VERSION 5.8 ;
BUSBITCHARS "[]" ;
DIVIDERCHAR "/" ;
UNITS
    DATABASE MICRONS 1000 ;
END UNITS

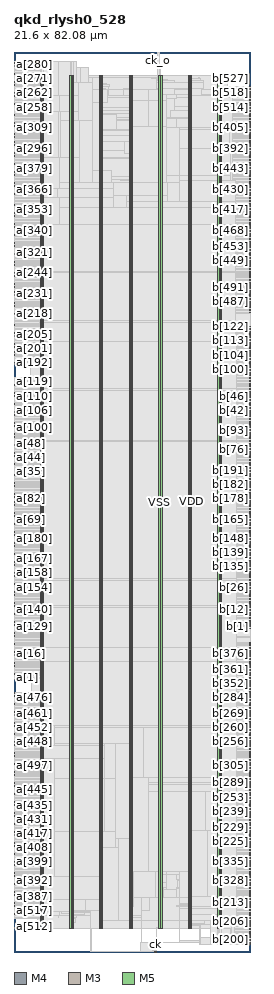
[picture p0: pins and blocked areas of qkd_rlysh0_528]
MACRO qkd_rlysh0_528
  FOREIGN qkd_rlysh0_528 0 0 ;
  CLASS BLOCK ;
  SIZE 21.6 BY 82.08 ;
  PIN a[0]
    DIRECTION INPUT ;
    USE SIGNAL ;
    PORT
      LAYER M4 ;
        RECT  0 24.912 0.084 24.936 ;
    END
  END a[0]
  PIN a[100]
    DIRECTION INPUT ;
    USE SIGNAL ;
    PORT
      LAYER M4 ;
        RECT  0 48.528 0.084 48.552 ;
    END
  END a[100]
  PIN a[101]
    DIRECTION INPUT ;
    USE SIGNAL ;
    PORT
      LAYER M4 ;
        RECT  0 48.672 0.084 48.696 ;
    END
  END a[101]
  PIN a[102]
    DIRECTION INPUT ;
    USE SIGNAL ;
    PORT
      LAYER M4 ;
        RECT  0 48.816 0.084 48.84 ;
    END
  END a[102]
  PIN a[103]
    DIRECTION INPUT ;
    USE SIGNAL ;
    PORT
      LAYER M4 ;
        RECT  0 48.96 0.084 48.984 ;
    END
  END a[103]
  PIN a[104]
    DIRECTION INPUT ;
    USE SIGNAL ;
    PORT
      LAYER M4 ;
        RECT  0 49.104 0.084 49.128 ;
    END
  END a[104]
  PIN a[105]
    DIRECTION INPUT ;
    USE SIGNAL ;
    PORT
      LAYER M4 ;
        RECT  0 49.248 0.084 49.272 ;
    END
  END a[105]
  PIN a[106]
    DIRECTION INPUT ;
    USE SIGNAL ;
    PORT
      LAYER M4 ;
        RECT  0 49.392 0.084 49.416 ;
    END
  END a[106]
  PIN a[107]
    DIRECTION INPUT ;
    USE SIGNAL ;
    PORT
      LAYER M4 ;
        RECT  0 49.536 0.084 49.56 ;
    END
  END a[107]
  PIN a[108]
    DIRECTION INPUT ;
    USE SIGNAL ;
    PORT
      LAYER M4 ;
        RECT  0 49.68 0.084 49.704 ;
    END
  END a[108]
  PIN a[109]
    DIRECTION INPUT ;
    USE SIGNAL ;
    PORT
      LAYER M4 ;
        RECT  0 49.824 0.084 49.848 ;
    END
  END a[109]
  PIN a[10]
    DIRECTION INPUT ;
    USE SIGNAL ;
    PORT
      LAYER M4 ;
        RECT  0 26.352 0.084 26.376 ;
    END
  END a[10]
  PIN a[110]
    DIRECTION INPUT ;
    USE SIGNAL ;
    PORT
      LAYER M4 ;
        RECT  0 49.968 0.084 49.992 ;
    END
  END a[110]
  PIN a[111]
    DIRECTION INPUT ;
    USE SIGNAL ;
    PORT
      LAYER M4 ;
        RECT  0 50.112 0.084 50.136 ;
    END
  END a[111]
  PIN a[112]
    DIRECTION INPUT ;
    USE SIGNAL ;
    PORT
      LAYER M4 ;
        RECT  0 50.256 0.084 50.28 ;
    END
  END a[112]
  PIN a[113]
    DIRECTION INPUT ;
    USE SIGNAL ;
    PORT
      LAYER M4 ;
        RECT  0 50.4 0.084 50.424 ;
    END
  END a[113]
  PIN a[114]
    DIRECTION INPUT ;
    USE SIGNAL ;
    PORT
      LAYER M4 ;
        RECT  0 50.544 0.084 50.568 ;
    END
  END a[114]
  PIN a[115]
    DIRECTION INPUT ;
    USE SIGNAL ;
    PORT
      LAYER M4 ;
        RECT  0 50.688 0.084 50.712 ;
    END
  END a[115]
  PIN a[116]
    DIRECTION INPUT ;
    USE SIGNAL ;
    PORT
      LAYER M4 ;
        RECT  0 50.832 0.084 50.856 ;
    END
  END a[116]
  PIN a[117]
    DIRECTION INPUT ;
    USE SIGNAL ;
    PORT
      LAYER M4 ;
        RECT  0 50.976 0.084 51 ;
    END
  END a[117]
  PIN a[118]
    DIRECTION INPUT ;
    USE SIGNAL ;
    PORT
      LAYER M4 ;
        RECT  0 51.12 0.084 51.144 ;
    END
  END a[118]
  PIN a[119]
    DIRECTION INPUT ;
    USE SIGNAL ;
    PORT
      LAYER M4 ;
        RECT  0 51.264 0.084 51.288 ;
    END
  END a[119]
  PIN a[11]
    DIRECTION INPUT ;
    USE SIGNAL ;
    PORT
      LAYER M4 ;
        RECT  0 26.496 0.084 26.52 ;
    END
  END a[11]
  PIN a[120]
    DIRECTION INPUT ;
    USE SIGNAL ;
    PORT
      LAYER M4 ;
        RECT  0 51.408 0.084 51.432 ;
    END
  END a[120]
  PIN a[121]
    DIRECTION INPUT ;
    USE SIGNAL ;
    PORT
      LAYER M4 ;
        RECT  0 51.552 0.084 51.576 ;
    END
  END a[121]
  PIN a[122]
    DIRECTION INPUT ;
    USE SIGNAL ;
    PORT
      LAYER M4 ;
        RECT  0 51.696 0.084 51.72 ;
    END
  END a[122]
  PIN a[123]
    DIRECTION INPUT ;
    USE SIGNAL ;
    PORT
      LAYER M4 ;
        RECT  0 51.84 0.084 51.864 ;
    END
  END a[123]
  PIN a[124]
    DIRECTION INPUT ;
    USE SIGNAL ;
    PORT
      LAYER M4 ;
        RECT  0 51.984 0.084 52.008 ;
    END
  END a[124]
  PIN a[125]
    DIRECTION INPUT ;
    USE SIGNAL ;
    PORT
      LAYER M4 ;
        RECT  0 52.128 0.084 52.152 ;
    END
  END a[125]
  PIN a[126]
    DIRECTION INPUT ;
    USE SIGNAL ;
    PORT
      LAYER M4 ;
        RECT  0 52.272 0.084 52.296 ;
    END
  END a[126]
  PIN a[127]
    DIRECTION INPUT ;
    USE SIGNAL ;
    PORT
      LAYER M4 ;
        RECT  0 52.416 0.084 52.44 ;
    END
  END a[127]
  PIN a[128]
    DIRECTION INPUT ;
    USE SIGNAL ;
    PORT
      LAYER M4 ;
        RECT  0 29.52 0.084 29.544 ;
    END
  END a[128]
  PIN a[129]
    DIRECTION INPUT ;
    USE SIGNAL ;
    PORT
      LAYER M4 ;
        RECT  0 29.664 0.084 29.688 ;
    END
  END a[129]
  PIN a[12]
    DIRECTION INPUT ;
    USE SIGNAL ;
    PORT
      LAYER M4 ;
        RECT  0 26.64 0.084 26.664 ;
    END
  END a[12]
  PIN a[130]
    DIRECTION INPUT ;
    USE SIGNAL ;
    PORT
      LAYER M4 ;
        RECT  0 29.808 0.084 29.832 ;
    END
  END a[130]
  PIN a[131]
    DIRECTION INPUT ;
    USE SIGNAL ;
    PORT
      LAYER M4 ;
        RECT  0 29.952 0.084 29.976 ;
    END
  END a[131]
  PIN a[132]
    DIRECTION INPUT ;
    USE SIGNAL ;
    PORT
      LAYER M4 ;
        RECT  0 30.096 0.084 30.12 ;
    END
  END a[132]
  PIN a[133]
    DIRECTION INPUT ;
    USE SIGNAL ;
    PORT
      LAYER M4 ;
        RECT  0 30.24 0.084 30.264 ;
    END
  END a[133]
  PIN a[134]
    DIRECTION INPUT ;
    USE SIGNAL ;
    PORT
      LAYER M4 ;
        RECT  0 30.384 0.084 30.408 ;
    END
  END a[134]
  PIN a[135]
    DIRECTION INPUT ;
    USE SIGNAL ;
    PORT
      LAYER M4 ;
        RECT  0 30.528 0.084 30.552 ;
    END
  END a[135]
  PIN a[136]
    DIRECTION INPUT ;
    USE SIGNAL ;
    PORT
      LAYER M4 ;
        RECT  0 30.672 0.084 30.696 ;
    END
  END a[136]
  PIN a[137]
    DIRECTION INPUT ;
    USE SIGNAL ;
    PORT
      LAYER M4 ;
        RECT  0 30.816 0.084 30.84 ;
    END
  END a[137]
  PIN a[138]
    DIRECTION INPUT ;
    USE SIGNAL ;
    PORT
      LAYER M4 ;
        RECT  0 30.96 0.084 30.984 ;
    END
  END a[138]
  PIN a[139]
    DIRECTION INPUT ;
    USE SIGNAL ;
    PORT
      LAYER M4 ;
        RECT  0 31.104 0.084 31.128 ;
    END
  END a[139]
  PIN a[13]
    DIRECTION INPUT ;
    USE SIGNAL ;
    PORT
      LAYER M4 ;
        RECT  0 26.784 0.084 26.808 ;
    END
  END a[13]
  PIN a[140]
    DIRECTION INPUT ;
    USE SIGNAL ;
    PORT
      LAYER M4 ;
        RECT  0 31.248 0.084 31.272 ;
    END
  END a[140]
  PIN a[141]
    DIRECTION INPUT ;
    USE SIGNAL ;
    PORT
      LAYER M4 ;
        RECT  0 31.392 0.084 31.416 ;
    END
  END a[141]
  PIN a[142]
    DIRECTION INPUT ;
    USE SIGNAL ;
    PORT
      LAYER M4 ;
        RECT  0 31.536 0.084 31.56 ;
    END
  END a[142]
  PIN a[143]
    DIRECTION INPUT ;
    USE SIGNAL ;
    PORT
      LAYER M4 ;
        RECT  0 31.68 0.084 31.704 ;
    END
  END a[143]
  PIN a[144]
    DIRECTION INPUT ;
    USE SIGNAL ;
    PORT
      LAYER M4 ;
        RECT  0 31.824 0.084 31.848 ;
    END
  END a[144]
  PIN a[145]
    DIRECTION INPUT ;
    USE SIGNAL ;
    PORT
      LAYER M4 ;
        RECT  0 31.968 0.084 31.992 ;
    END
  END a[145]
  PIN a[146]
    DIRECTION INPUT ;
    USE SIGNAL ;
    PORT
      LAYER M4 ;
        RECT  0 32.112 0.084 32.136 ;
    END
  END a[146]
  PIN a[147]
    DIRECTION INPUT ;
    USE SIGNAL ;
    PORT
      LAYER M4 ;
        RECT  0 32.256 0.084 32.28 ;
    END
  END a[147]
  PIN a[148]
    DIRECTION INPUT ;
    USE SIGNAL ;
    PORT
      LAYER M4 ;
        RECT  0 32.4 0.084 32.424 ;
    END
  END a[148]
  PIN a[149]
    DIRECTION INPUT ;
    USE SIGNAL ;
    PORT
      LAYER M4 ;
        RECT  0 32.544 0.084 32.568 ;
    END
  END a[149]
  PIN a[14]
    DIRECTION INPUT ;
    USE SIGNAL ;
    PORT
      LAYER M4 ;
        RECT  0 26.928 0.084 26.952 ;
    END
  END a[14]
  PIN a[150]
    DIRECTION INPUT ;
    USE SIGNAL ;
    PORT
      LAYER M4 ;
        RECT  0 32.688 0.084 32.712 ;
    END
  END a[150]
  PIN a[151]
    DIRECTION INPUT ;
    USE SIGNAL ;
    PORT
      LAYER M4 ;
        RECT  0 32.832 0.084 32.856 ;
    END
  END a[151]
  PIN a[152]
    DIRECTION INPUT ;
    USE SIGNAL ;
    PORT
      LAYER M4 ;
        RECT  0 32.976 0.084 33 ;
    END
  END a[152]
  PIN a[153]
    DIRECTION INPUT ;
    USE SIGNAL ;
    PORT
      LAYER M4 ;
        RECT  0 33.12 0.084 33.144 ;
    END
  END a[153]
  PIN a[154]
    DIRECTION INPUT ;
    USE SIGNAL ;
    PORT
      LAYER M4 ;
        RECT  0 33.264 0.084 33.288 ;
    END
  END a[154]
  PIN a[155]
    DIRECTION INPUT ;
    USE SIGNAL ;
    PORT
      LAYER M4 ;
        RECT  0 33.408 0.084 33.432 ;
    END
  END a[155]
  PIN a[156]
    DIRECTION INPUT ;
    USE SIGNAL ;
    PORT
      LAYER M4 ;
        RECT  0 33.552 0.084 33.576 ;
    END
  END a[156]
  PIN a[157]
    DIRECTION INPUT ;
    USE SIGNAL ;
    PORT
      LAYER M4 ;
        RECT  0 33.696 0.084 33.72 ;
    END
  END a[157]
  PIN a[158]
    DIRECTION INPUT ;
    USE SIGNAL ;
    PORT
      LAYER M4 ;
        RECT  0 33.84 0.084 33.864 ;
    END
  END a[158]
  PIN a[159]
    DIRECTION INPUT ;
    USE SIGNAL ;
    PORT
      LAYER M4 ;
        RECT  0 33.984 0.084 34.008 ;
    END
  END a[159]
  PIN a[15]
    DIRECTION INPUT ;
    USE SIGNAL ;
    PORT
      LAYER M4 ;
        RECT  0 27.072 0.084 27.096 ;
    END
  END a[15]
  PIN a[160]
    DIRECTION INPUT ;
    USE SIGNAL ;
    PORT
      LAYER M4 ;
        RECT  0 34.128 0.084 34.152 ;
    END
  END a[160]
  PIN a[161]
    DIRECTION INPUT ;
    USE SIGNAL ;
    PORT
      LAYER M4 ;
        RECT  0 34.272 0.084 34.296 ;
    END
  END a[161]
  PIN a[162]
    DIRECTION INPUT ;
    USE SIGNAL ;
    PORT
      LAYER M4 ;
        RECT  0 34.416 0.084 34.44 ;
    END
  END a[162]
  PIN a[163]
    DIRECTION INPUT ;
    USE SIGNAL ;
    PORT
      LAYER M4 ;
        RECT  0 34.56 0.084 34.584 ;
    END
  END a[163]
  PIN a[164]
    DIRECTION INPUT ;
    USE SIGNAL ;
    PORT
      LAYER M4 ;
        RECT  0 34.704 0.084 34.728 ;
    END
  END a[164]
  PIN a[165]
    DIRECTION INPUT ;
    USE SIGNAL ;
    PORT
      LAYER M4 ;
        RECT  0 34.848 0.084 34.872 ;
    END
  END a[165]
  PIN a[166]
    DIRECTION INPUT ;
    USE SIGNAL ;
    PORT
      LAYER M4 ;
        RECT  0 34.992 0.084 35.016 ;
    END
  END a[166]
  PIN a[167]
    DIRECTION INPUT ;
    USE SIGNAL ;
    PORT
      LAYER M4 ;
        RECT  0 35.136 0.084 35.16 ;
    END
  END a[167]
  PIN a[168]
    DIRECTION INPUT ;
    USE SIGNAL ;
    PORT
      LAYER M4 ;
        RECT  0 35.28 0.084 35.304 ;
    END
  END a[168]
  PIN a[169]
    DIRECTION INPUT ;
    USE SIGNAL ;
    PORT
      LAYER M4 ;
        RECT  0 35.424 0.084 35.448 ;
    END
  END a[169]
  PIN a[16]
    DIRECTION INPUT ;
    USE SIGNAL ;
    PORT
      LAYER M4 ;
        RECT  0 27.216 0.084 27.24 ;
    END
  END a[16]
  PIN a[170]
    DIRECTION INPUT ;
    USE SIGNAL ;
    PORT
      LAYER M4 ;
        RECT  0 35.568 0.084 35.592 ;
    END
  END a[170]
  PIN a[171]
    DIRECTION INPUT ;
    USE SIGNAL ;
    PORT
      LAYER M4 ;
        RECT  0 35.712 0.084 35.736 ;
    END
  END a[171]
  PIN a[172]
    DIRECTION INPUT ;
    USE SIGNAL ;
    PORT
      LAYER M4 ;
        RECT  0 35.856 0.084 35.88 ;
    END
  END a[172]
  PIN a[173]
    DIRECTION INPUT ;
    USE SIGNAL ;
    PORT
      LAYER M4 ;
        RECT  0 36 0.084 36.024 ;
    END
  END a[173]
  PIN a[174]
    DIRECTION INPUT ;
    USE SIGNAL ;
    PORT
      LAYER M4 ;
        RECT  0 36.144 0.084 36.168 ;
    END
  END a[174]
  PIN a[175]
    DIRECTION INPUT ;
    USE SIGNAL ;
    PORT
      LAYER M4 ;
        RECT  0 36.288 0.084 36.312 ;
    END
  END a[175]
  PIN a[176]
    DIRECTION INPUT ;
    USE SIGNAL ;
    PORT
      LAYER M4 ;
        RECT  0 36.432 0.084 36.456 ;
    END
  END a[176]
  PIN a[177]
    DIRECTION INPUT ;
    USE SIGNAL ;
    PORT
      LAYER M4 ;
        RECT  0 36.576 0.084 36.6 ;
    END
  END a[177]
  PIN a[178]
    DIRECTION INPUT ;
    USE SIGNAL ;
    PORT
      LAYER M4 ;
        RECT  0 36.72 0.084 36.744 ;
    END
  END a[178]
  PIN a[179]
    DIRECTION INPUT ;
    USE SIGNAL ;
    PORT
      LAYER M4 ;
        RECT  0 36.864 0.084 36.888 ;
    END
  END a[179]
  PIN a[17]
    DIRECTION INPUT ;
    USE SIGNAL ;
    PORT
      LAYER M4 ;
        RECT  0 27.36 0.084 27.384 ;
    END
  END a[17]
  PIN a[180]
    DIRECTION INPUT ;
    USE SIGNAL ;
    PORT
      LAYER M4 ;
        RECT  0 37.008 0.084 37.032 ;
    END
  END a[180]
  PIN a[181]
    DIRECTION INPUT ;
    USE SIGNAL ;
    PORT
      LAYER M4 ;
        RECT  0 37.152 0.084 37.176 ;
    END
  END a[181]
  PIN a[182]
    DIRECTION INPUT ;
    USE SIGNAL ;
    PORT
      LAYER M4 ;
        RECT  0 37.296 0.084 37.32 ;
    END
  END a[182]
  PIN a[183]
    DIRECTION INPUT ;
    USE SIGNAL ;
    PORT
      LAYER M4 ;
        RECT  0 37.44 0.084 37.464 ;
    END
  END a[183]
  PIN a[184]
    DIRECTION INPUT ;
    USE SIGNAL ;
    PORT
      LAYER M4 ;
        RECT  0 37.584 0.084 37.608 ;
    END
  END a[184]
  PIN a[185]
    DIRECTION INPUT ;
    USE SIGNAL ;
    PORT
      LAYER M4 ;
        RECT  0 37.728 0.084 37.752 ;
    END
  END a[185]
  PIN a[186]
    DIRECTION INPUT ;
    USE SIGNAL ;
    PORT
      LAYER M4 ;
        RECT  0 37.872 0.084 37.896 ;
    END
  END a[186]
  PIN a[187]
    DIRECTION INPUT ;
    USE SIGNAL ;
    PORT
      LAYER M4 ;
        RECT  0 38.016 0.084 38.04 ;
    END
  END a[187]
  PIN a[188]
    DIRECTION INPUT ;
    USE SIGNAL ;
    PORT
      LAYER M4 ;
        RECT  0 38.16 0.084 38.184 ;
    END
  END a[188]
  PIN a[189]
    DIRECTION INPUT ;
    USE SIGNAL ;
    PORT
      LAYER M4 ;
        RECT  0 38.304 0.084 38.328 ;
    END
  END a[189]
  PIN a[18]
    DIRECTION INPUT ;
    USE SIGNAL ;
    PORT
      LAYER M4 ;
        RECT  0 27.504 0.084 27.528 ;
    END
  END a[18]
  PIN a[190]
    DIRECTION INPUT ;
    USE SIGNAL ;
    PORT
      LAYER M4 ;
        RECT  0 38.448 0.084 38.472 ;
    END
  END a[190]
  PIN a[191]
    DIRECTION INPUT ;
    USE SIGNAL ;
    PORT
      LAYER M4 ;
        RECT  0 38.592 0.084 38.616 ;
    END
  END a[191]
  PIN a[192]
    DIRECTION INPUT ;
    USE SIGNAL ;
    PORT
      LAYER M4 ;
        RECT  0 53.712 0.084 53.736 ;
    END
  END a[192]
  PIN a[193]
    DIRECTION INPUT ;
    USE SIGNAL ;
    PORT
      LAYER M4 ;
        RECT  0 53.856 0.084 53.88 ;
    END
  END a[193]
  PIN a[194]
    DIRECTION INPUT ;
    USE SIGNAL ;
    PORT
      LAYER M4 ;
        RECT  0 54 0.084 54.024 ;
    END
  END a[194]
  PIN a[195]
    DIRECTION INPUT ;
    USE SIGNAL ;
    PORT
      LAYER M4 ;
        RECT  0 54.144 0.084 54.168 ;
    END
  END a[195]
  PIN a[196]
    DIRECTION INPUT ;
    USE SIGNAL ;
    PORT
      LAYER M4 ;
        RECT  0 54.288 0.084 54.312 ;
    END
  END a[196]
  PIN a[197]
    DIRECTION INPUT ;
    USE SIGNAL ;
    PORT
      LAYER M4 ;
        RECT  0 54.432 0.084 54.456 ;
    END
  END a[197]
  PIN a[198]
    DIRECTION INPUT ;
    USE SIGNAL ;
    PORT
      LAYER M4 ;
        RECT  0 54.576 0.084 54.6 ;
    END
  END a[198]
  PIN a[199]
    DIRECTION INPUT ;
    USE SIGNAL ;
    PORT
      LAYER M4 ;
        RECT  0 54.72 0.084 54.744 ;
    END
  END a[199]
  PIN a[19]
    DIRECTION INPUT ;
    USE SIGNAL ;
    PORT
      LAYER M4 ;
        RECT  0 27.648 0.084 27.672 ;
    END
  END a[19]
  PIN a[1]
    DIRECTION INPUT ;
    USE SIGNAL ;
    PORT
      LAYER M4 ;
        RECT  0 25.056 0.084 25.08 ;
    END
  END a[1]
  PIN a[200]
    DIRECTION INPUT ;
    USE SIGNAL ;
    PORT
      LAYER M4 ;
        RECT  0 54.864 0.084 54.888 ;
    END
  END a[200]
  PIN a[201]
    DIRECTION INPUT ;
    USE SIGNAL ;
    PORT
      LAYER M4 ;
        RECT  0 55.008 0.084 55.032 ;
    END
  END a[201]
  PIN a[202]
    DIRECTION INPUT ;
    USE SIGNAL ;
    PORT
      LAYER M4 ;
        RECT  0 55.152 0.084 55.176 ;
    END
  END a[202]
  PIN a[203]
    DIRECTION INPUT ;
    USE SIGNAL ;
    PORT
      LAYER M4 ;
        RECT  0 55.296 0.084 55.32 ;
    END
  END a[203]
  PIN a[204]
    DIRECTION INPUT ;
    USE SIGNAL ;
    PORT
      LAYER M4 ;
        RECT  0 55.44 0.084 55.464 ;
    END
  END a[204]
  PIN a[205]
    DIRECTION INPUT ;
    USE SIGNAL ;
    PORT
      LAYER M4 ;
        RECT  0 55.584 0.084 55.608 ;
    END
  END a[205]
  PIN a[206]
    DIRECTION INPUT ;
    USE SIGNAL ;
    PORT
      LAYER M4 ;
        RECT  0 55.728 0.084 55.752 ;
    END
  END a[206]
  PIN a[207]
    DIRECTION INPUT ;
    USE SIGNAL ;
    PORT
      LAYER M4 ;
        RECT  0 55.872 0.084 55.896 ;
    END
  END a[207]
  PIN a[208]
    DIRECTION INPUT ;
    USE SIGNAL ;
    PORT
      LAYER M4 ;
        RECT  0 56.016 0.084 56.04 ;
    END
  END a[208]
  PIN a[209]
    DIRECTION INPUT ;
    USE SIGNAL ;
    PORT
      LAYER M4 ;
        RECT  0 56.16 0.084 56.184 ;
    END
  END a[209]
  PIN a[20]
    DIRECTION INPUT ;
    USE SIGNAL ;
    PORT
      LAYER M4 ;
        RECT  0 27.792 0.084 27.816 ;
    END
  END a[20]
  PIN a[210]
    DIRECTION INPUT ;
    USE SIGNAL ;
    PORT
      LAYER M4 ;
        RECT  0 56.304 0.084 56.328 ;
    END
  END a[210]
  PIN a[211]
    DIRECTION INPUT ;
    USE SIGNAL ;
    PORT
      LAYER M4 ;
        RECT  0 56.448 0.084 56.472 ;
    END
  END a[211]
  PIN a[212]
    DIRECTION INPUT ;
    USE SIGNAL ;
    PORT
      LAYER M4 ;
        RECT  0 56.592 0.084 56.616 ;
    END
  END a[212]
  PIN a[213]
    DIRECTION INPUT ;
    USE SIGNAL ;
    PORT
      LAYER M4 ;
        RECT  0 56.736 0.084 56.76 ;
    END
  END a[213]
  PIN a[214]
    DIRECTION INPUT ;
    USE SIGNAL ;
    PORT
      LAYER M4 ;
        RECT  0 56.88 0.084 56.904 ;
    END
  END a[214]
  PIN a[215]
    DIRECTION INPUT ;
    USE SIGNAL ;
    PORT
      LAYER M4 ;
        RECT  0 57.024 0.084 57.048 ;
    END
  END a[215]
  PIN a[216]
    DIRECTION INPUT ;
    USE SIGNAL ;
    PORT
      LAYER M4 ;
        RECT  0 57.168 0.084 57.192 ;
    END
  END a[216]
  PIN a[217]
    DIRECTION INPUT ;
    USE SIGNAL ;
    PORT
      LAYER M4 ;
        RECT  0 57.312 0.084 57.336 ;
    END
  END a[217]
  PIN a[218]
    DIRECTION INPUT ;
    USE SIGNAL ;
    PORT
      LAYER M4 ;
        RECT  0 57.456 0.084 57.48 ;
    END
  END a[218]
  PIN a[219]
    DIRECTION INPUT ;
    USE SIGNAL ;
    PORT
      LAYER M4 ;
        RECT  0 57.6 0.084 57.624 ;
    END
  END a[219]
  PIN a[21]
    DIRECTION INPUT ;
    USE SIGNAL ;
    PORT
      LAYER M4 ;
        RECT  0 27.936 0.084 27.96 ;
    END
  END a[21]
  PIN a[220]
    DIRECTION INPUT ;
    USE SIGNAL ;
    PORT
      LAYER M4 ;
        RECT  0 57.744 0.084 57.768 ;
    END
  END a[220]
  PIN a[221]
    DIRECTION INPUT ;
    USE SIGNAL ;
    PORT
      LAYER M4 ;
        RECT  0 57.888 0.084 57.912 ;
    END
  END a[221]
  PIN a[222]
    DIRECTION INPUT ;
    USE SIGNAL ;
    PORT
      LAYER M4 ;
        RECT  0 58.032 0.084 58.056 ;
    END
  END a[222]
  PIN a[223]
    DIRECTION INPUT ;
    USE SIGNAL ;
    PORT
      LAYER M4 ;
        RECT  0 58.176 0.084 58.2 ;
    END
  END a[223]
  PIN a[224]
    DIRECTION INPUT ;
    USE SIGNAL ;
    PORT
      LAYER M4 ;
        RECT  0 58.32 0.084 58.344 ;
    END
  END a[224]
  PIN a[225]
    DIRECTION INPUT ;
    USE SIGNAL ;
    PORT
      LAYER M4 ;
        RECT  0 58.464 0.084 58.488 ;
    END
  END a[225]
  PIN a[226]
    DIRECTION INPUT ;
    USE SIGNAL ;
    PORT
      LAYER M4 ;
        RECT  0 58.608 0.084 58.632 ;
    END
  END a[226]
  PIN a[227]
    DIRECTION INPUT ;
    USE SIGNAL ;
    PORT
      LAYER M4 ;
        RECT  0 58.752 0.084 58.776 ;
    END
  END a[227]
  PIN a[228]
    DIRECTION INPUT ;
    USE SIGNAL ;
    PORT
      LAYER M4 ;
        RECT  0 58.896 0.084 58.92 ;
    END
  END a[228]
  PIN a[229]
    DIRECTION INPUT ;
    USE SIGNAL ;
    PORT
      LAYER M4 ;
        RECT  0 59.04 0.084 59.064 ;
    END
  END a[229]
  PIN a[22]
    DIRECTION INPUT ;
    USE SIGNAL ;
    PORT
      LAYER M4 ;
        RECT  0 28.08 0.084 28.104 ;
    END
  END a[22]
  PIN a[230]
    DIRECTION INPUT ;
    USE SIGNAL ;
    PORT
      LAYER M4 ;
        RECT  0 59.184 0.084 59.208 ;
    END
  END a[230]
  PIN a[231]
    DIRECTION INPUT ;
    USE SIGNAL ;
    PORT
      LAYER M4 ;
        RECT  0 59.328 0.084 59.352 ;
    END
  END a[231]
  PIN a[232]
    DIRECTION INPUT ;
    USE SIGNAL ;
    PORT
      LAYER M4 ;
        RECT  0 59.472 0.084 59.496 ;
    END
  END a[232]
  PIN a[233]
    DIRECTION INPUT ;
    USE SIGNAL ;
    PORT
      LAYER M4 ;
        RECT  0 59.616 0.084 59.64 ;
    END
  END a[233]
  PIN a[234]
    DIRECTION INPUT ;
    USE SIGNAL ;
    PORT
      LAYER M4 ;
        RECT  0 59.76 0.084 59.784 ;
    END
  END a[234]
  PIN a[235]
    DIRECTION INPUT ;
    USE SIGNAL ;
    PORT
      LAYER M4 ;
        RECT  0 59.904 0.084 59.928 ;
    END
  END a[235]
  PIN a[236]
    DIRECTION INPUT ;
    USE SIGNAL ;
    PORT
      LAYER M4 ;
        RECT  0 60.048 0.084 60.072 ;
    END
  END a[236]
  PIN a[237]
    DIRECTION INPUT ;
    USE SIGNAL ;
    PORT
      LAYER M4 ;
        RECT  0 60.192 0.084 60.216 ;
    END
  END a[237]
  PIN a[238]
    DIRECTION INPUT ;
    USE SIGNAL ;
    PORT
      LAYER M4 ;
        RECT  0 60.336 0.084 60.36 ;
    END
  END a[238]
  PIN a[239]
    DIRECTION INPUT ;
    USE SIGNAL ;
    PORT
      LAYER M4 ;
        RECT  0 60.48 0.084 60.504 ;
    END
  END a[239]
  PIN a[23]
    DIRECTION INPUT ;
    USE SIGNAL ;
    PORT
      LAYER M4 ;
        RECT  0 28.224 0.084 28.248 ;
    END
  END a[23]
  PIN a[240]
    DIRECTION INPUT ;
    USE SIGNAL ;
    PORT
      LAYER M4 ;
        RECT  0 60.624 0.084 60.648 ;
    END
  END a[240]
  PIN a[241]
    DIRECTION INPUT ;
    USE SIGNAL ;
    PORT
      LAYER M4 ;
        RECT  0 60.768 0.084 60.792 ;
    END
  END a[241]
  PIN a[242]
    DIRECTION INPUT ;
    USE SIGNAL ;
    PORT
      LAYER M4 ;
        RECT  0 60.912 0.084 60.936 ;
    END
  END a[242]
  PIN a[243]
    DIRECTION INPUT ;
    USE SIGNAL ;
    PORT
      LAYER M4 ;
        RECT  0 61.056 0.084 61.08 ;
    END
  END a[243]
  PIN a[244]
    DIRECTION INPUT ;
    USE SIGNAL ;
    PORT
      LAYER M4 ;
        RECT  0 61.2 0.084 61.224 ;
    END
  END a[244]
  PIN a[245]
    DIRECTION INPUT ;
    USE SIGNAL ;
    PORT
      LAYER M4 ;
        RECT  0 61.344 0.084 61.368 ;
    END
  END a[245]
  PIN a[246]
    DIRECTION INPUT ;
    USE SIGNAL ;
    PORT
      LAYER M4 ;
        RECT  0 61.488 0.084 61.512 ;
    END
  END a[246]
  PIN a[247]
    DIRECTION INPUT ;
    USE SIGNAL ;
    PORT
      LAYER M4 ;
        RECT  0 61.632 0.084 61.656 ;
    END
  END a[247]
  PIN a[248]
    DIRECTION INPUT ;
    USE SIGNAL ;
    PORT
      LAYER M4 ;
        RECT  0 61.776 0.084 61.8 ;
    END
  END a[248]
  PIN a[249]
    DIRECTION INPUT ;
    USE SIGNAL ;
    PORT
      LAYER M4 ;
        RECT  0 61.92 0.084 61.944 ;
    END
  END a[249]
  PIN a[24]
    DIRECTION INPUT ;
    USE SIGNAL ;
    PORT
      LAYER M4 ;
        RECT  0 28.368 0.084 28.392 ;
    END
  END a[24]
  PIN a[250]
    DIRECTION INPUT ;
    USE SIGNAL ;
    PORT
      LAYER M4 ;
        RECT  0 62.064 0.084 62.088 ;
    END
  END a[250]
  PIN a[251]
    DIRECTION INPUT ;
    USE SIGNAL ;
    PORT
      LAYER M4 ;
        RECT  0 62.208 0.084 62.232 ;
    END
  END a[251]
  PIN a[252]
    DIRECTION INPUT ;
    USE SIGNAL ;
    PORT
      LAYER M4 ;
        RECT  0 62.352 0.084 62.376 ;
    END
  END a[252]
  PIN a[253]
    DIRECTION INPUT ;
    USE SIGNAL ;
    PORT
      LAYER M4 ;
        RECT  0 62.496 0.084 62.52 ;
    END
  END a[253]
  PIN a[254]
    DIRECTION INPUT ;
    USE SIGNAL ;
    PORT
      LAYER M4 ;
        RECT  0 62.64 0.084 62.664 ;
    END
  END a[254]
  PIN a[255]
    DIRECTION INPUT ;
    USE SIGNAL ;
    PORT
      LAYER M4 ;
        RECT  0 62.784 0.084 62.808 ;
    END
  END a[255]
  PIN a[256]
    DIRECTION INPUT ;
    USE SIGNAL ;
    PORT
      LAYER M4 ;
        RECT  0 76.752 0.084 76.776 ;
    END
  END a[256]
  PIN a[257]
    DIRECTION INPUT ;
    USE SIGNAL ;
    PORT
      LAYER M4 ;
        RECT  0 76.896 0.084 76.92 ;
    END
  END a[257]
  PIN a[258]
    DIRECTION INPUT ;
    USE SIGNAL ;
    PORT
      LAYER M4 ;
        RECT  0 77.04 0.084 77.064 ;
    END
  END a[258]
  PIN a[259]
    DIRECTION INPUT ;
    USE SIGNAL ;
    PORT
      LAYER M4 ;
        RECT  0 77.184 0.084 77.208 ;
    END
  END a[259]
  PIN a[25]
    DIRECTION INPUT ;
    USE SIGNAL ;
    PORT
      LAYER M4 ;
        RECT  0 28.512 0.084 28.536 ;
    END
  END a[25]
  PIN a[260]
    DIRECTION INPUT ;
    USE SIGNAL ;
    PORT
      LAYER M4 ;
        RECT  0 77.328 0.084 77.352 ;
    END
  END a[260]
  PIN a[261]
    DIRECTION INPUT ;
    USE SIGNAL ;
    PORT
      LAYER M4 ;
        RECT  0 77.472 0.084 77.496 ;
    END
  END a[261]
  PIN a[262]
    DIRECTION INPUT ;
    USE SIGNAL ;
    PORT
      LAYER M4 ;
        RECT  0 77.616 0.084 77.64 ;
    END
  END a[262]
  PIN a[263]
    DIRECTION INPUT ;
    USE SIGNAL ;
    PORT
      LAYER M4 ;
        RECT  0 77.76 0.084 77.784 ;
    END
  END a[263]
  PIN a[264]
    DIRECTION INPUT ;
    USE SIGNAL ;
    PORT
      LAYER M4 ;
        RECT  0 77.904 0.084 77.928 ;
    END
  END a[264]
  PIN a[265]
    DIRECTION INPUT ;
    USE SIGNAL ;
    PORT
      LAYER M4 ;
        RECT  0 78.048 0.084 78.072 ;
    END
  END a[265]
  PIN a[266]
    DIRECTION INPUT ;
    USE SIGNAL ;
    PORT
      LAYER M4 ;
        RECT  0 78.192 0.084 78.216 ;
    END
  END a[266]
  PIN a[267]
    DIRECTION INPUT ;
    USE SIGNAL ;
    PORT
      LAYER M4 ;
        RECT  0 78.336 0.084 78.36 ;
    END
  END a[267]
  PIN a[268]
    DIRECTION INPUT ;
    USE SIGNAL ;
    PORT
      LAYER M4 ;
        RECT  0 78.48 0.084 78.504 ;
    END
  END a[268]
  PIN a[269]
    DIRECTION INPUT ;
    USE SIGNAL ;
    PORT
      LAYER M4 ;
        RECT  0 78.624 0.084 78.648 ;
    END
  END a[269]
  PIN a[26]
    DIRECTION INPUT ;
    USE SIGNAL ;
    PORT
      LAYER M4 ;
        RECT  0 28.656 0.084 28.68 ;
    END
  END a[26]
  PIN a[270]
    DIRECTION INPUT ;
    USE SIGNAL ;
    PORT
      LAYER M4 ;
        RECT  0 78.768 0.084 78.792 ;
    END
  END a[270]
  PIN a[271]
    DIRECTION INPUT ;
    USE SIGNAL ;
    PORT
      LAYER M4 ;
        RECT  0 78.912 0.084 78.936 ;
    END
  END a[271]
  PIN a[272]
    DIRECTION INPUT ;
    USE SIGNAL ;
    PORT
      LAYER M4 ;
        RECT  0 79.056 0.084 79.08 ;
    END
  END a[272]
  PIN a[273]
    DIRECTION INPUT ;
    USE SIGNAL ;
    PORT
      LAYER M4 ;
        RECT  0 79.2 0.084 79.224 ;
    END
  END a[273]
  PIN a[274]
    DIRECTION INPUT ;
    USE SIGNAL ;
    PORT
      LAYER M4 ;
        RECT  0 79.344 0.084 79.368 ;
    END
  END a[274]
  PIN a[275]
    DIRECTION INPUT ;
    USE SIGNAL ;
    PORT
      LAYER M4 ;
        RECT  0 79.488 0.084 79.512 ;
    END
  END a[275]
  PIN a[276]
    DIRECTION INPUT ;
    USE SIGNAL ;
    PORT
      LAYER M4 ;
        RECT  0 79.632 0.084 79.656 ;
    END
  END a[276]
  PIN a[277]
    DIRECTION INPUT ;
    USE SIGNAL ;
    PORT
      LAYER M4 ;
        RECT  0 79.776 0.084 79.8 ;
    END
  END a[277]
  PIN a[278]
    DIRECTION INPUT ;
    USE SIGNAL ;
    PORT
      LAYER M4 ;
        RECT  0 79.92 0.084 79.944 ;
    END
  END a[278]
  PIN a[279]
    DIRECTION INPUT ;
    USE SIGNAL ;
    PORT
      LAYER M4 ;
        RECT  0 80.064 0.084 80.088 ;
    END
  END a[279]
  PIN a[27]
    DIRECTION INPUT ;
    USE SIGNAL ;
    PORT
      LAYER M4 ;
        RECT  0 28.8 0.084 28.824 ;
    END
  END a[27]
  PIN a[280]
    DIRECTION INPUT ;
    USE SIGNAL ;
    PORT
      LAYER M4 ;
        RECT  0 80.208 0.084 80.232 ;
    END
  END a[280]
  PIN a[281]
    DIRECTION INPUT ;
    USE SIGNAL ;
    PORT
      LAYER M4 ;
        RECT  0 80.352 0.084 80.376 ;
    END
  END a[281]
  PIN a[282]
    DIRECTION INPUT ;
    USE SIGNAL ;
    PORT
      LAYER M4 ;
        RECT  0 80.496 0.084 80.52 ;
    END
  END a[282]
  PIN a[283]
    DIRECTION INPUT ;
    USE SIGNAL ;
    PORT
      LAYER M4 ;
        RECT  0 80.64 0.084 80.664 ;
    END
  END a[283]
  PIN a[284]
    DIRECTION INPUT ;
    USE SIGNAL ;
    PORT
      LAYER M4 ;
        RECT  0 80.784 0.084 80.808 ;
    END
  END a[284]
  PIN a[285]
    DIRECTION INPUT ;
    USE SIGNAL ;
    PORT
      LAYER M4 ;
        RECT  0 80.928 0.084 80.952 ;
    END
  END a[285]
  PIN a[286]
    DIRECTION INPUT ;
    USE SIGNAL ;
    PORT
      LAYER M4 ;
        RECT  0 81.072 0.084 81.096 ;
    END
  END a[286]
  PIN a[287]
    DIRECTION INPUT ;
    USE SIGNAL ;
    PORT
      LAYER M4 ;
        RECT  0 81.216 0.084 81.24 ;
    END
  END a[287]
  PIN a[288]
    DIRECTION INPUT ;
    USE SIGNAL ;
    PORT
      LAYER M4 ;
        RECT  0 72.144 0.084 72.168 ;
    END
  END a[288]
  PIN a[289]
    DIRECTION INPUT ;
    USE SIGNAL ;
    PORT
      LAYER M4 ;
        RECT  0 72.288 0.084 72.312 ;
    END
  END a[289]
  PIN a[28]
    DIRECTION INPUT ;
    USE SIGNAL ;
    PORT
      LAYER M4 ;
        RECT  0 28.944 0.084 28.968 ;
    END
  END a[28]
  PIN a[290]
    DIRECTION INPUT ;
    USE SIGNAL ;
    PORT
      LAYER M4 ;
        RECT  0 72.432 0.084 72.456 ;
    END
  END a[290]
  PIN a[291]
    DIRECTION INPUT ;
    USE SIGNAL ;
    PORT
      LAYER M4 ;
        RECT  0 72.576 0.084 72.6 ;
    END
  END a[291]
  PIN a[292]
    DIRECTION INPUT ;
    USE SIGNAL ;
    PORT
      LAYER M4 ;
        RECT  0 72.72 0.084 72.744 ;
    END
  END a[292]
  PIN a[293]
    DIRECTION INPUT ;
    USE SIGNAL ;
    PORT
      LAYER M4 ;
        RECT  0 72.864 0.084 72.888 ;
    END
  END a[293]
  PIN a[294]
    DIRECTION INPUT ;
    USE SIGNAL ;
    PORT
      LAYER M4 ;
        RECT  0 73.008 0.084 73.032 ;
    END
  END a[294]
  PIN a[295]
    DIRECTION INPUT ;
    USE SIGNAL ;
    PORT
      LAYER M4 ;
        RECT  0 73.152 0.084 73.176 ;
    END
  END a[295]
  PIN a[296]
    DIRECTION INPUT ;
    USE SIGNAL ;
    PORT
      LAYER M4 ;
        RECT  0 73.296 0.084 73.32 ;
    END
  END a[296]
  PIN a[297]
    DIRECTION INPUT ;
    USE SIGNAL ;
    PORT
      LAYER M4 ;
        RECT  0 73.44 0.084 73.464 ;
    END
  END a[297]
  PIN a[298]
    DIRECTION INPUT ;
    USE SIGNAL ;
    PORT
      LAYER M4 ;
        RECT  0 73.584 0.084 73.608 ;
    END
  END a[298]
  PIN a[299]
    DIRECTION INPUT ;
    USE SIGNAL ;
    PORT
      LAYER M4 ;
        RECT  0 73.728 0.084 73.752 ;
    END
  END a[299]
  PIN a[29]
    DIRECTION INPUT ;
    USE SIGNAL ;
    PORT
      LAYER M4 ;
        RECT  0 29.088 0.084 29.112 ;
    END
  END a[29]
  PIN a[2]
    DIRECTION INPUT ;
    USE SIGNAL ;
    PORT
      LAYER M4 ;
        RECT  0 25.2 0.084 25.224 ;
    END
  END a[2]
  PIN a[300]
    DIRECTION INPUT ;
    USE SIGNAL ;
    PORT
      LAYER M4 ;
        RECT  0 73.872 0.084 73.896 ;
    END
  END a[300]
  PIN a[301]
    DIRECTION INPUT ;
    USE SIGNAL ;
    PORT
      LAYER M4 ;
        RECT  0 74.016 0.084 74.04 ;
    END
  END a[301]
  PIN a[302]
    DIRECTION INPUT ;
    USE SIGNAL ;
    PORT
      LAYER M4 ;
        RECT  0 74.16 0.084 74.184 ;
    END
  END a[302]
  PIN a[303]
    DIRECTION INPUT ;
    USE SIGNAL ;
    PORT
      LAYER M4 ;
        RECT  0 74.304 0.084 74.328 ;
    END
  END a[303]
  PIN a[304]
    DIRECTION INPUT ;
    USE SIGNAL ;
    PORT
      LAYER M4 ;
        RECT  0 74.448 0.084 74.472 ;
    END
  END a[304]
  PIN a[305]
    DIRECTION INPUT ;
    USE SIGNAL ;
    PORT
      LAYER M4 ;
        RECT  0 74.592 0.084 74.616 ;
    END
  END a[305]
  PIN a[306]
    DIRECTION INPUT ;
    USE SIGNAL ;
    PORT
      LAYER M4 ;
        RECT  0 74.736 0.084 74.76 ;
    END
  END a[306]
  PIN a[307]
    DIRECTION INPUT ;
    USE SIGNAL ;
    PORT
      LAYER M4 ;
        RECT  0 74.88 0.084 74.904 ;
    END
  END a[307]
  PIN a[308]
    DIRECTION INPUT ;
    USE SIGNAL ;
    PORT
      LAYER M4 ;
        RECT  0 75.024 0.084 75.048 ;
    END
  END a[308]
  PIN a[309]
    DIRECTION INPUT ;
    USE SIGNAL ;
    PORT
      LAYER M4 ;
        RECT  0 75.168 0.084 75.192 ;
    END
  END a[309]
  PIN a[30]
    DIRECTION INPUT ;
    USE SIGNAL ;
    PORT
      LAYER M4 ;
        RECT  0 29.232 0.084 29.256 ;
    END
  END a[30]
  PIN a[310]
    DIRECTION INPUT ;
    USE SIGNAL ;
    PORT
      LAYER M4 ;
        RECT  0 75.312 0.084 75.336 ;
    END
  END a[310]
  PIN a[311]
    DIRECTION INPUT ;
    USE SIGNAL ;
    PORT
      LAYER M4 ;
        RECT  0 75.456 0.084 75.48 ;
    END
  END a[311]
  PIN a[312]
    DIRECTION INPUT ;
    USE SIGNAL ;
    PORT
      LAYER M4 ;
        RECT  0 75.6 0.084 75.624 ;
    END
  END a[312]
  PIN a[313]
    DIRECTION INPUT ;
    USE SIGNAL ;
    PORT
      LAYER M4 ;
        RECT  0 75.744 0.084 75.768 ;
    END
  END a[313]
  PIN a[314]
    DIRECTION INPUT ;
    USE SIGNAL ;
    PORT
      LAYER M4 ;
        RECT  0 75.888 0.084 75.912 ;
    END
  END a[314]
  PIN a[315]
    DIRECTION INPUT ;
    USE SIGNAL ;
    PORT
      LAYER M4 ;
        RECT  0 76.032 0.084 76.056 ;
    END
  END a[315]
  PIN a[316]
    DIRECTION INPUT ;
    USE SIGNAL ;
    PORT
      LAYER M4 ;
        RECT  0 76.176 0.084 76.2 ;
    END
  END a[316]
  PIN a[317]
    DIRECTION INPUT ;
    USE SIGNAL ;
    PORT
      LAYER M4 ;
        RECT  0 76.32 0.084 76.344 ;
    END
  END a[317]
  PIN a[318]
    DIRECTION INPUT ;
    USE SIGNAL ;
    PORT
      LAYER M4 ;
        RECT  0 76.464 0.084 76.488 ;
    END
  END a[318]
  PIN a[319]
    DIRECTION INPUT ;
    USE SIGNAL ;
    PORT
      LAYER M4 ;
        RECT  0 76.608 0.084 76.632 ;
    END
  END a[319]
  PIN a[31]
    DIRECTION INPUT ;
    USE SIGNAL ;
    PORT
      LAYER M4 ;
        RECT  0 29.376 0.084 29.4 ;
    END
  END a[31]
  PIN a[320]
    DIRECTION INPUT ;
    USE SIGNAL ;
    PORT
      LAYER M4 ;
        RECT  0 62.928 0.084 62.952 ;
    END
  END a[320]
  PIN a[321]
    DIRECTION INPUT ;
    USE SIGNAL ;
    PORT
      LAYER M4 ;
        RECT  0 63.072 0.084 63.096 ;
    END
  END a[321]
  PIN a[322]
    DIRECTION INPUT ;
    USE SIGNAL ;
    PORT
      LAYER M4 ;
        RECT  0 63.216 0.084 63.24 ;
    END
  END a[322]
  PIN a[323]
    DIRECTION INPUT ;
    USE SIGNAL ;
    PORT
      LAYER M4 ;
        RECT  0 63.36 0.084 63.384 ;
    END
  END a[323]
  PIN a[324]
    DIRECTION INPUT ;
    USE SIGNAL ;
    PORT
      LAYER M4 ;
        RECT  0 63.504 0.084 63.528 ;
    END
  END a[324]
  PIN a[325]
    DIRECTION INPUT ;
    USE SIGNAL ;
    PORT
      LAYER M4 ;
        RECT  0 63.648 0.084 63.672 ;
    END
  END a[325]
  PIN a[326]
    DIRECTION INPUT ;
    USE SIGNAL ;
    PORT
      LAYER M4 ;
        RECT  0 63.792 0.084 63.816 ;
    END
  END a[326]
  PIN a[327]
    DIRECTION INPUT ;
    USE SIGNAL ;
    PORT
      LAYER M4 ;
        RECT  0 63.936 0.084 63.96 ;
    END
  END a[327]
  PIN a[328]
    DIRECTION INPUT ;
    USE SIGNAL ;
    PORT
      LAYER M4 ;
        RECT  0 64.08 0.084 64.104 ;
    END
  END a[328]
  PIN a[329]
    DIRECTION INPUT ;
    USE SIGNAL ;
    PORT
      LAYER M4 ;
        RECT  0 64.224 0.084 64.248 ;
    END
  END a[329]
  PIN a[32]
    DIRECTION INPUT ;
    USE SIGNAL ;
    PORT
      LAYER M4 ;
        RECT  0 43.344 0.084 43.368 ;
    END
  END a[32]
  PIN a[330]
    DIRECTION INPUT ;
    USE SIGNAL ;
    PORT
      LAYER M4 ;
        RECT  0 64.368 0.084 64.392 ;
    END
  END a[330]
  PIN a[331]
    DIRECTION INPUT ;
    USE SIGNAL ;
    PORT
      LAYER M4 ;
        RECT  0 64.512 0.084 64.536 ;
    END
  END a[331]
  PIN a[332]
    DIRECTION INPUT ;
    USE SIGNAL ;
    PORT
      LAYER M4 ;
        RECT  0 64.656 0.084 64.68 ;
    END
  END a[332]
  PIN a[333]
    DIRECTION INPUT ;
    USE SIGNAL ;
    PORT
      LAYER M4 ;
        RECT  0 64.8 0.084 64.824 ;
    END
  END a[333]
  PIN a[334]
    DIRECTION INPUT ;
    USE SIGNAL ;
    PORT
      LAYER M4 ;
        RECT  0 64.944 0.084 64.968 ;
    END
  END a[334]
  PIN a[335]
    DIRECTION INPUT ;
    USE SIGNAL ;
    PORT
      LAYER M4 ;
        RECT  0 65.088 0.084 65.112 ;
    END
  END a[335]
  PIN a[336]
    DIRECTION INPUT ;
    USE SIGNAL ;
    PORT
      LAYER M4 ;
        RECT  0 65.232 0.084 65.256 ;
    END
  END a[336]
  PIN a[337]
    DIRECTION INPUT ;
    USE SIGNAL ;
    PORT
      LAYER M4 ;
        RECT  0 65.376 0.084 65.4 ;
    END
  END a[337]
  PIN a[338]
    DIRECTION INPUT ;
    USE SIGNAL ;
    PORT
      LAYER M4 ;
        RECT  0 65.52 0.084 65.544 ;
    END
  END a[338]
  PIN a[339]
    DIRECTION INPUT ;
    USE SIGNAL ;
    PORT
      LAYER M4 ;
        RECT  0 65.664 0.084 65.688 ;
    END
  END a[339]
  PIN a[33]
    DIRECTION INPUT ;
    USE SIGNAL ;
    PORT
      LAYER M4 ;
        RECT  0 43.488 0.084 43.512 ;
    END
  END a[33]
  PIN a[340]
    DIRECTION INPUT ;
    USE SIGNAL ;
    PORT
      LAYER M4 ;
        RECT  0 65.808 0.084 65.832 ;
    END
  END a[340]
  PIN a[341]
    DIRECTION INPUT ;
    USE SIGNAL ;
    PORT
      LAYER M4 ;
        RECT  0 65.952 0.084 65.976 ;
    END
  END a[341]
  PIN a[342]
    DIRECTION INPUT ;
    USE SIGNAL ;
    PORT
      LAYER M4 ;
        RECT  0 66.096 0.084 66.12 ;
    END
  END a[342]
  PIN a[343]
    DIRECTION INPUT ;
    USE SIGNAL ;
    PORT
      LAYER M4 ;
        RECT  0 66.24 0.084 66.264 ;
    END
  END a[343]
  PIN a[344]
    DIRECTION INPUT ;
    USE SIGNAL ;
    PORT
      LAYER M4 ;
        RECT  0 66.384 0.084 66.408 ;
    END
  END a[344]
  PIN a[345]
    DIRECTION INPUT ;
    USE SIGNAL ;
    PORT
      LAYER M4 ;
        RECT  0 66.528 0.084 66.552 ;
    END
  END a[345]
  PIN a[346]
    DIRECTION INPUT ;
    USE SIGNAL ;
    PORT
      LAYER M4 ;
        RECT  0 66.672 0.084 66.696 ;
    END
  END a[346]
  PIN a[347]
    DIRECTION INPUT ;
    USE SIGNAL ;
    PORT
      LAYER M4 ;
        RECT  0 66.816 0.084 66.84 ;
    END
  END a[347]
  PIN a[348]
    DIRECTION INPUT ;
    USE SIGNAL ;
    PORT
      LAYER M4 ;
        RECT  0 66.96 0.084 66.984 ;
    END
  END a[348]
  PIN a[349]
    DIRECTION INPUT ;
    USE SIGNAL ;
    PORT
      LAYER M4 ;
        RECT  0 67.104 0.084 67.128 ;
    END
  END a[349]
  PIN a[34]
    DIRECTION INPUT ;
    USE SIGNAL ;
    PORT
      LAYER M4 ;
        RECT  0 43.632 0.084 43.656 ;
    END
  END a[34]
  PIN a[350]
    DIRECTION INPUT ;
    USE SIGNAL ;
    PORT
      LAYER M4 ;
        RECT  0 67.248 0.084 67.272 ;
    END
  END a[350]
  PIN a[351]
    DIRECTION INPUT ;
    USE SIGNAL ;
    PORT
      LAYER M4 ;
        RECT  0 67.392 0.084 67.416 ;
    END
  END a[351]
  PIN a[352]
    DIRECTION INPUT ;
    USE SIGNAL ;
    PORT
      LAYER M4 ;
        RECT  0 67.536 0.084 67.56 ;
    END
  END a[352]
  PIN a[353]
    DIRECTION INPUT ;
    USE SIGNAL ;
    PORT
      LAYER M4 ;
        RECT  0 67.68 0.084 67.704 ;
    END
  END a[353]
  PIN a[354]
    DIRECTION INPUT ;
    USE SIGNAL ;
    PORT
      LAYER M4 ;
        RECT  0 67.824 0.084 67.848 ;
    END
  END a[354]
  PIN a[355]
    DIRECTION INPUT ;
    USE SIGNAL ;
    PORT
      LAYER M4 ;
        RECT  0 67.968 0.084 67.992 ;
    END
  END a[355]
  PIN a[356]
    DIRECTION INPUT ;
    USE SIGNAL ;
    PORT
      LAYER M4 ;
        RECT  0 68.112 0.084 68.136 ;
    END
  END a[356]
  PIN a[357]
    DIRECTION INPUT ;
    USE SIGNAL ;
    PORT
      LAYER M4 ;
        RECT  0 68.256 0.084 68.28 ;
    END
  END a[357]
  PIN a[358]
    DIRECTION INPUT ;
    USE SIGNAL ;
    PORT
      LAYER M4 ;
        RECT  0 68.4 0.084 68.424 ;
    END
  END a[358]
  PIN a[359]
    DIRECTION INPUT ;
    USE SIGNAL ;
    PORT
      LAYER M4 ;
        RECT  0 68.544 0.084 68.568 ;
    END
  END a[359]
  PIN a[35]
    DIRECTION INPUT ;
    USE SIGNAL ;
    PORT
      LAYER M4 ;
        RECT  0 43.776 0.084 43.8 ;
    END
  END a[35]
  PIN a[360]
    DIRECTION INPUT ;
    USE SIGNAL ;
    PORT
      LAYER M4 ;
        RECT  0 68.688 0.084 68.712 ;
    END
  END a[360]
  PIN a[361]
    DIRECTION INPUT ;
    USE SIGNAL ;
    PORT
      LAYER M4 ;
        RECT  0 68.832 0.084 68.856 ;
    END
  END a[361]
  PIN a[362]
    DIRECTION INPUT ;
    USE SIGNAL ;
    PORT
      LAYER M4 ;
        RECT  0 68.976 0.084 69 ;
    END
  END a[362]
  PIN a[363]
    DIRECTION INPUT ;
    USE SIGNAL ;
    PORT
      LAYER M4 ;
        RECT  0 69.12 0.084 69.144 ;
    END
  END a[363]
  PIN a[364]
    DIRECTION INPUT ;
    USE SIGNAL ;
    PORT
      LAYER M4 ;
        RECT  0 69.264 0.084 69.288 ;
    END
  END a[364]
  PIN a[365]
    DIRECTION INPUT ;
    USE SIGNAL ;
    PORT
      LAYER M4 ;
        RECT  0 69.408 0.084 69.432 ;
    END
  END a[365]
  PIN a[366]
    DIRECTION INPUT ;
    USE SIGNAL ;
    PORT
      LAYER M4 ;
        RECT  0 69.552 0.084 69.576 ;
    END
  END a[366]
  PIN a[367]
    DIRECTION INPUT ;
    USE SIGNAL ;
    PORT
      LAYER M4 ;
        RECT  0 69.696 0.084 69.72 ;
    END
  END a[367]
  PIN a[368]
    DIRECTION INPUT ;
    USE SIGNAL ;
    PORT
      LAYER M4 ;
        RECT  0 69.84 0.084 69.864 ;
    END
  END a[368]
  PIN a[369]
    DIRECTION INPUT ;
    USE SIGNAL ;
    PORT
      LAYER M4 ;
        RECT  0 69.984 0.084 70.008 ;
    END
  END a[369]
  PIN a[36]
    DIRECTION INPUT ;
    USE SIGNAL ;
    PORT
      LAYER M4 ;
        RECT  0 43.92 0.084 43.944 ;
    END
  END a[36]
  PIN a[370]
    DIRECTION INPUT ;
    USE SIGNAL ;
    PORT
      LAYER M4 ;
        RECT  0 70.128 0.084 70.152 ;
    END
  END a[370]
  PIN a[371]
    DIRECTION INPUT ;
    USE SIGNAL ;
    PORT
      LAYER M4 ;
        RECT  0 70.272 0.084 70.296 ;
    END
  END a[371]
  PIN a[372]
    DIRECTION INPUT ;
    USE SIGNAL ;
    PORT
      LAYER M4 ;
        RECT  0 70.416 0.084 70.44 ;
    END
  END a[372]
  PIN a[373]
    DIRECTION INPUT ;
    USE SIGNAL ;
    PORT
      LAYER M4 ;
        RECT  0 70.56 0.084 70.584 ;
    END
  END a[373]
  PIN a[374]
    DIRECTION INPUT ;
    USE SIGNAL ;
    PORT
      LAYER M4 ;
        RECT  0 70.704 0.084 70.728 ;
    END
  END a[374]
  PIN a[375]
    DIRECTION INPUT ;
    USE SIGNAL ;
    PORT
      LAYER M4 ;
        RECT  0 70.848 0.084 70.872 ;
    END
  END a[375]
  PIN a[376]
    DIRECTION INPUT ;
    USE SIGNAL ;
    PORT
      LAYER M4 ;
        RECT  0 70.992 0.084 71.016 ;
    END
  END a[376]
  PIN a[377]
    DIRECTION INPUT ;
    USE SIGNAL ;
    PORT
      LAYER M4 ;
        RECT  0 71.136 0.084 71.16 ;
    END
  END a[377]
  PIN a[378]
    DIRECTION INPUT ;
    USE SIGNAL ;
    PORT
      LAYER M4 ;
        RECT  0 71.28 0.084 71.304 ;
    END
  END a[378]
  PIN a[379]
    DIRECTION INPUT ;
    USE SIGNAL ;
    PORT
      LAYER M4 ;
        RECT  0 71.424 0.084 71.448 ;
    END
  END a[379]
  PIN a[37]
    DIRECTION INPUT ;
    USE SIGNAL ;
    PORT
      LAYER M4 ;
        RECT  0 44.064 0.084 44.088 ;
    END
  END a[37]
  PIN a[380]
    DIRECTION INPUT ;
    USE SIGNAL ;
    PORT
      LAYER M4 ;
        RECT  0 71.568 0.084 71.592 ;
    END
  END a[380]
  PIN a[381]
    DIRECTION INPUT ;
    USE SIGNAL ;
    PORT
      LAYER M4 ;
        RECT  0 71.712 0.084 71.736 ;
    END
  END a[381]
  PIN a[382]
    DIRECTION INPUT ;
    USE SIGNAL ;
    PORT
      LAYER M4 ;
        RECT  0 71.856 0.084 71.88 ;
    END
  END a[382]
  PIN a[383]
    DIRECTION INPUT ;
    USE SIGNAL ;
    PORT
      LAYER M4 ;
        RECT  0 72 0.084 72.024 ;
    END
  END a[383]
  PIN a[384]
    DIRECTION INPUT ;
    USE SIGNAL ;
    PORT
      LAYER M4 ;
        RECT  0 5.328 0.084 5.352 ;
    END
  END a[384]
  PIN a[385]
    DIRECTION INPUT ;
    USE SIGNAL ;
    PORT
      LAYER M4 ;
        RECT  0 5.472 0.084 5.496 ;
    END
  END a[385]
  PIN a[386]
    DIRECTION INPUT ;
    USE SIGNAL ;
    PORT
      LAYER M4 ;
        RECT  0 5.616 0.084 5.64 ;
    END
  END a[386]
  PIN a[387]
    DIRECTION INPUT ;
    USE SIGNAL ;
    PORT
      LAYER M4 ;
        RECT  0 5.76 0.084 5.784 ;
    END
  END a[387]
  PIN a[388]
    DIRECTION INPUT ;
    USE SIGNAL ;
    PORT
      LAYER M4 ;
        RECT  0 5.904 0.084 5.928 ;
    END
  END a[388]
  PIN a[389]
    DIRECTION INPUT ;
    USE SIGNAL ;
    PORT
      LAYER M4 ;
        RECT  0 6.048 0.084 6.072 ;
    END
  END a[389]
  PIN a[38]
    DIRECTION INPUT ;
    USE SIGNAL ;
    PORT
      LAYER M4 ;
        RECT  0 44.208 0.084 44.232 ;
    END
  END a[38]
  PIN a[390]
    DIRECTION INPUT ;
    USE SIGNAL ;
    PORT
      LAYER M4 ;
        RECT  0 6.192 0.084 6.216 ;
    END
  END a[390]
  PIN a[391]
    DIRECTION INPUT ;
    USE SIGNAL ;
    PORT
      LAYER M4 ;
        RECT  0 6.336 0.084 6.36 ;
    END
  END a[391]
  PIN a[392]
    DIRECTION INPUT ;
    USE SIGNAL ;
    PORT
      LAYER M4 ;
        RECT  0 6.48 0.084 6.504 ;
    END
  END a[392]
  PIN a[393]
    DIRECTION INPUT ;
    USE SIGNAL ;
    PORT
      LAYER M4 ;
        RECT  0 6.624 0.084 6.648 ;
    END
  END a[393]
  PIN a[394]
    DIRECTION INPUT ;
    USE SIGNAL ;
    PORT
      LAYER M4 ;
        RECT  0 6.768 0.084 6.792 ;
    END
  END a[394]
  PIN a[395]
    DIRECTION INPUT ;
    USE SIGNAL ;
    PORT
      LAYER M4 ;
        RECT  0 6.912 0.084 6.936 ;
    END
  END a[395]
  PIN a[396]
    DIRECTION INPUT ;
    USE SIGNAL ;
    PORT
      LAYER M4 ;
        RECT  0 7.056 0.084 7.08 ;
    END
  END a[396]
  PIN a[397]
    DIRECTION INPUT ;
    USE SIGNAL ;
    PORT
      LAYER M4 ;
        RECT  0 7.2 0.084 7.224 ;
    END
  END a[397]
  PIN a[398]
    DIRECTION INPUT ;
    USE SIGNAL ;
    PORT
      LAYER M4 ;
        RECT  0 7.344 0.084 7.368 ;
    END
  END a[398]
  PIN a[399]
    DIRECTION INPUT ;
    USE SIGNAL ;
    PORT
      LAYER M4 ;
        RECT  0 7.488 0.084 7.512 ;
    END
  END a[399]
  PIN a[39]
    DIRECTION INPUT ;
    USE SIGNAL ;
    PORT
      LAYER M4 ;
        RECT  0 44.352 0.084 44.376 ;
    END
  END a[39]
  PIN a[3]
    DIRECTION INPUT ;
    USE SIGNAL ;
    PORT
      LAYER M4 ;
        RECT  0 25.344 0.084 25.368 ;
    END
  END a[3]
  PIN a[400]
    DIRECTION INPUT ;
    USE SIGNAL ;
    PORT
      LAYER M4 ;
        RECT  0 7.632 0.084 7.656 ;
    END
  END a[400]
  PIN a[401]
    DIRECTION INPUT ;
    USE SIGNAL ;
    PORT
      LAYER M4 ;
        RECT  0 7.776 0.084 7.8 ;
    END
  END a[401]
  PIN a[402]
    DIRECTION INPUT ;
    USE SIGNAL ;
    PORT
      LAYER M4 ;
        RECT  0 7.92 0.084 7.944 ;
    END
  END a[402]
  PIN a[403]
    DIRECTION INPUT ;
    USE SIGNAL ;
    PORT
      LAYER M4 ;
        RECT  0 8.064 0.084 8.088 ;
    END
  END a[403]
  PIN a[404]
    DIRECTION INPUT ;
    USE SIGNAL ;
    PORT
      LAYER M4 ;
        RECT  0 8.208 0.084 8.232 ;
    END
  END a[404]
  PIN a[405]
    DIRECTION INPUT ;
    USE SIGNAL ;
    PORT
      LAYER M4 ;
        RECT  0 8.352 0.084 8.376 ;
    END
  END a[405]
  PIN a[406]
    DIRECTION INPUT ;
    USE SIGNAL ;
    PORT
      LAYER M4 ;
        RECT  0 8.496 0.084 8.52 ;
    END
  END a[406]
  PIN a[407]
    DIRECTION INPUT ;
    USE SIGNAL ;
    PORT
      LAYER M4 ;
        RECT  0 8.64 0.084 8.664 ;
    END
  END a[407]
  PIN a[408]
    DIRECTION INPUT ;
    USE SIGNAL ;
    PORT
      LAYER M4 ;
        RECT  0 8.784 0.084 8.808 ;
    END
  END a[408]
  PIN a[409]
    DIRECTION INPUT ;
    USE SIGNAL ;
    PORT
      LAYER M4 ;
        RECT  0 8.928 0.084 8.952 ;
    END
  END a[409]
  PIN a[40]
    DIRECTION INPUT ;
    USE SIGNAL ;
    PORT
      LAYER M4 ;
        RECT  0 44.496 0.084 44.52 ;
    END
  END a[40]
  PIN a[410]
    DIRECTION INPUT ;
    USE SIGNAL ;
    PORT
      LAYER M4 ;
        RECT  0 9.072 0.084 9.096 ;
    END
  END a[410]
  PIN a[411]
    DIRECTION INPUT ;
    USE SIGNAL ;
    PORT
      LAYER M4 ;
        RECT  0 9.216 0.084 9.24 ;
    END
  END a[411]
  PIN a[412]
    DIRECTION INPUT ;
    USE SIGNAL ;
    PORT
      LAYER M4 ;
        RECT  0 9.36 0.084 9.384 ;
    END
  END a[412]
  PIN a[413]
    DIRECTION INPUT ;
    USE SIGNAL ;
    PORT
      LAYER M4 ;
        RECT  0 9.504 0.084 9.528 ;
    END
  END a[413]
  PIN a[414]
    DIRECTION INPUT ;
    USE SIGNAL ;
    PORT
      LAYER M4 ;
        RECT  0 9.648 0.084 9.672 ;
    END
  END a[414]
  PIN a[415]
    DIRECTION INPUT ;
    USE SIGNAL ;
    PORT
      LAYER M4 ;
        RECT  0 9.792 0.084 9.816 ;
    END
  END a[415]
  PIN a[416]
    DIRECTION INPUT ;
    USE SIGNAL ;
    PORT
      LAYER M4 ;
        RECT  0 9.936 0.084 9.96 ;
    END
  END a[416]
  PIN a[417]
    DIRECTION INPUT ;
    USE SIGNAL ;
    PORT
      LAYER M4 ;
        RECT  0 10.08 0.084 10.104 ;
    END
  END a[417]
  PIN a[418]
    DIRECTION INPUT ;
    USE SIGNAL ;
    PORT
      LAYER M4 ;
        RECT  0 10.224 0.084 10.248 ;
    END
  END a[418]
  PIN a[419]
    DIRECTION INPUT ;
    USE SIGNAL ;
    PORT
      LAYER M4 ;
        RECT  0 10.368 0.084 10.392 ;
    END
  END a[419]
  PIN a[41]
    DIRECTION INPUT ;
    USE SIGNAL ;
    PORT
      LAYER M4 ;
        RECT  0 44.64 0.084 44.664 ;
    END
  END a[41]
  PIN a[420]
    DIRECTION INPUT ;
    USE SIGNAL ;
    PORT
      LAYER M4 ;
        RECT  0 10.512 0.084 10.536 ;
    END
  END a[420]
  PIN a[421]
    DIRECTION INPUT ;
    USE SIGNAL ;
    PORT
      LAYER M4 ;
        RECT  0 10.656 0.084 10.68 ;
    END
  END a[421]
  PIN a[422]
    DIRECTION INPUT ;
    USE SIGNAL ;
    PORT
      LAYER M4 ;
        RECT  0 10.8 0.084 10.824 ;
    END
  END a[422]
  PIN a[423]
    DIRECTION INPUT ;
    USE SIGNAL ;
    PORT
      LAYER M4 ;
        RECT  0 10.944 0.084 10.968 ;
    END
  END a[423]
  PIN a[424]
    DIRECTION INPUT ;
    USE SIGNAL ;
    PORT
      LAYER M4 ;
        RECT  0 11.088 0.084 11.112 ;
    END
  END a[424]
  PIN a[425]
    DIRECTION INPUT ;
    USE SIGNAL ;
    PORT
      LAYER M4 ;
        RECT  0 11.232 0.084 11.256 ;
    END
  END a[425]
  PIN a[426]
    DIRECTION INPUT ;
    USE SIGNAL ;
    PORT
      LAYER M4 ;
        RECT  0 11.376 0.084 11.4 ;
    END
  END a[426]
  PIN a[427]
    DIRECTION INPUT ;
    USE SIGNAL ;
    PORT
      LAYER M4 ;
        RECT  0 11.52 0.084 11.544 ;
    END
  END a[427]
  PIN a[428]
    DIRECTION INPUT ;
    USE SIGNAL ;
    PORT
      LAYER M4 ;
        RECT  0 11.664 0.084 11.688 ;
    END
  END a[428]
  PIN a[429]
    DIRECTION INPUT ;
    USE SIGNAL ;
    PORT
      LAYER M4 ;
        RECT  0 11.808 0.084 11.832 ;
    END
  END a[429]
  PIN a[42]
    DIRECTION INPUT ;
    USE SIGNAL ;
    PORT
      LAYER M4 ;
        RECT  0 44.784 0.084 44.808 ;
    END
  END a[42]
  PIN a[430]
    DIRECTION INPUT ;
    USE SIGNAL ;
    PORT
      LAYER M4 ;
        RECT  0 11.952 0.084 11.976 ;
    END
  END a[430]
  PIN a[431]
    DIRECTION INPUT ;
    USE SIGNAL ;
    PORT
      LAYER M4 ;
        RECT  0 12.096 0.084 12.12 ;
    END
  END a[431]
  PIN a[432]
    DIRECTION INPUT ;
    USE SIGNAL ;
    PORT
      LAYER M4 ;
        RECT  0 12.24 0.084 12.264 ;
    END
  END a[432]
  PIN a[433]
    DIRECTION INPUT ;
    USE SIGNAL ;
    PORT
      LAYER M4 ;
        RECT  0 12.384 0.084 12.408 ;
    END
  END a[433]
  PIN a[434]
    DIRECTION INPUT ;
    USE SIGNAL ;
    PORT
      LAYER M4 ;
        RECT  0 12.528 0.084 12.552 ;
    END
  END a[434]
  PIN a[435]
    DIRECTION INPUT ;
    USE SIGNAL ;
    PORT
      LAYER M4 ;
        RECT  0 12.672 0.084 12.696 ;
    END
  END a[435]
  PIN a[436]
    DIRECTION INPUT ;
    USE SIGNAL ;
    PORT
      LAYER M4 ;
        RECT  0 12.816 0.084 12.84 ;
    END
  END a[436]
  PIN a[437]
    DIRECTION INPUT ;
    USE SIGNAL ;
    PORT
      LAYER M4 ;
        RECT  0 12.96 0.084 12.984 ;
    END
  END a[437]
  PIN a[438]
    DIRECTION INPUT ;
    USE SIGNAL ;
    PORT
      LAYER M4 ;
        RECT  0 13.104 0.084 13.128 ;
    END
  END a[438]
  PIN a[439]
    DIRECTION INPUT ;
    USE SIGNAL ;
    PORT
      LAYER M4 ;
        RECT  0 13.248 0.084 13.272 ;
    END
  END a[439]
  PIN a[43]
    DIRECTION INPUT ;
    USE SIGNAL ;
    PORT
      LAYER M4 ;
        RECT  0 44.928 0.084 44.952 ;
    END
  END a[43]
  PIN a[440]
    DIRECTION INPUT ;
    USE SIGNAL ;
    PORT
      LAYER M4 ;
        RECT  0 13.392 0.084 13.416 ;
    END
  END a[440]
  PIN a[441]
    DIRECTION INPUT ;
    USE SIGNAL ;
    PORT
      LAYER M4 ;
        RECT  0 13.536 0.084 13.56 ;
    END
  END a[441]
  PIN a[442]
    DIRECTION INPUT ;
    USE SIGNAL ;
    PORT
      LAYER M4 ;
        RECT  0 13.68 0.084 13.704 ;
    END
  END a[442]
  PIN a[443]
    DIRECTION INPUT ;
    USE SIGNAL ;
    PORT
      LAYER M4 ;
        RECT  0 13.824 0.084 13.848 ;
    END
  END a[443]
  PIN a[444]
    DIRECTION INPUT ;
    USE SIGNAL ;
    PORT
      LAYER M4 ;
        RECT  0 13.968 0.084 13.992 ;
    END
  END a[444]
  PIN a[445]
    DIRECTION INPUT ;
    USE SIGNAL ;
    PORT
      LAYER M4 ;
        RECT  0 14.112 0.084 14.136 ;
    END
  END a[445]
  PIN a[446]
    DIRECTION INPUT ;
    USE SIGNAL ;
    PORT
      LAYER M4 ;
        RECT  0 14.256 0.084 14.28 ;
    END
  END a[446]
  PIN a[447]
    DIRECTION INPUT ;
    USE SIGNAL ;
    PORT
      LAYER M4 ;
        RECT  0 14.4 0.084 14.424 ;
    END
  END a[447]
  PIN a[448]
    DIRECTION INPUT ;
    USE SIGNAL ;
    PORT
      LAYER M4 ;
        RECT  0 19.152 0.084 19.176 ;
    END
  END a[448]
  PIN a[449]
    DIRECTION INPUT ;
    USE SIGNAL ;
    PORT
      LAYER M4 ;
        RECT  0 19.296 0.084 19.32 ;
    END
  END a[449]
  PIN a[44]
    DIRECTION INPUT ;
    USE SIGNAL ;
    PORT
      LAYER M4 ;
        RECT  0 45.072 0.084 45.096 ;
    END
  END a[44]
  PIN a[450]
    DIRECTION INPUT ;
    USE SIGNAL ;
    PORT
      LAYER M4 ;
        RECT  0 19.44 0.084 19.464 ;
    END
  END a[450]
  PIN a[451]
    DIRECTION INPUT ;
    USE SIGNAL ;
    PORT
      LAYER M4 ;
        RECT  0 19.584 0.084 19.608 ;
    END
  END a[451]
  PIN a[452]
    DIRECTION INPUT ;
    USE SIGNAL ;
    PORT
      LAYER M4 ;
        RECT  0 19.728 0.084 19.752 ;
    END
  END a[452]
  PIN a[453]
    DIRECTION INPUT ;
    USE SIGNAL ;
    PORT
      LAYER M4 ;
        RECT  0 19.872 0.084 19.896 ;
    END
  END a[453]
  PIN a[454]
    DIRECTION INPUT ;
    USE SIGNAL ;
    PORT
      LAYER M4 ;
        RECT  0 20.016 0.084 20.04 ;
    END
  END a[454]
  PIN a[455]
    DIRECTION INPUT ;
    USE SIGNAL ;
    PORT
      LAYER M4 ;
        RECT  0 20.16 0.084 20.184 ;
    END
  END a[455]
  PIN a[456]
    DIRECTION INPUT ;
    USE SIGNAL ;
    PORT
      LAYER M4 ;
        RECT  0 20.304 0.084 20.328 ;
    END
  END a[456]
  PIN a[457]
    DIRECTION INPUT ;
    USE SIGNAL ;
    PORT
      LAYER M4 ;
        RECT  0 20.448 0.084 20.472 ;
    END
  END a[457]
  PIN a[458]
    DIRECTION INPUT ;
    USE SIGNAL ;
    PORT
      LAYER M4 ;
        RECT  0 20.592 0.084 20.616 ;
    END
  END a[458]
  PIN a[459]
    DIRECTION INPUT ;
    USE SIGNAL ;
    PORT
      LAYER M4 ;
        RECT  0 20.736 0.084 20.76 ;
    END
  END a[459]
  PIN a[45]
    DIRECTION INPUT ;
    USE SIGNAL ;
    PORT
      LAYER M4 ;
        RECT  0 45.216 0.084 45.24 ;
    END
  END a[45]
  PIN a[460]
    DIRECTION INPUT ;
    USE SIGNAL ;
    PORT
      LAYER M4 ;
        RECT  0 20.88 0.084 20.904 ;
    END
  END a[460]
  PIN a[461]
    DIRECTION INPUT ;
    USE SIGNAL ;
    PORT
      LAYER M4 ;
        RECT  0 21.024 0.084 21.048 ;
    END
  END a[461]
  PIN a[462]
    DIRECTION INPUT ;
    USE SIGNAL ;
    PORT
      LAYER M4 ;
        RECT  0 21.168 0.084 21.192 ;
    END
  END a[462]
  PIN a[463]
    DIRECTION INPUT ;
    USE SIGNAL ;
    PORT
      LAYER M4 ;
        RECT  0 21.312 0.084 21.336 ;
    END
  END a[463]
  PIN a[464]
    DIRECTION INPUT ;
    USE SIGNAL ;
    PORT
      LAYER M4 ;
        RECT  0 21.456 0.084 21.48 ;
    END
  END a[464]
  PIN a[465]
    DIRECTION INPUT ;
    USE SIGNAL ;
    PORT
      LAYER M4 ;
        RECT  0 21.6 0.084 21.624 ;
    END
  END a[465]
  PIN a[466]
    DIRECTION INPUT ;
    USE SIGNAL ;
    PORT
      LAYER M4 ;
        RECT  0 21.744 0.084 21.768 ;
    END
  END a[466]
  PIN a[467]
    DIRECTION INPUT ;
    USE SIGNAL ;
    PORT
      LAYER M4 ;
        RECT  0 21.888 0.084 21.912 ;
    END
  END a[467]
  PIN a[468]
    DIRECTION INPUT ;
    USE SIGNAL ;
    PORT
      LAYER M4 ;
        RECT  0 22.032 0.084 22.056 ;
    END
  END a[468]
  PIN a[469]
    DIRECTION INPUT ;
    USE SIGNAL ;
    PORT
      LAYER M4 ;
        RECT  0 22.176 0.084 22.2 ;
    END
  END a[469]
  PIN a[46]
    DIRECTION INPUT ;
    USE SIGNAL ;
    PORT
      LAYER M4 ;
        RECT  0 45.36 0.084 45.384 ;
    END
  END a[46]
  PIN a[470]
    DIRECTION INPUT ;
    USE SIGNAL ;
    PORT
      LAYER M4 ;
        RECT  0 22.32 0.084 22.344 ;
    END
  END a[470]
  PIN a[471]
    DIRECTION INPUT ;
    USE SIGNAL ;
    PORT
      LAYER M4 ;
        RECT  0 22.464 0.084 22.488 ;
    END
  END a[471]
  PIN a[472]
    DIRECTION INPUT ;
    USE SIGNAL ;
    PORT
      LAYER M4 ;
        RECT  0 22.608 0.084 22.632 ;
    END
  END a[472]
  PIN a[473]
    DIRECTION INPUT ;
    USE SIGNAL ;
    PORT
      LAYER M4 ;
        RECT  0 22.752 0.084 22.776 ;
    END
  END a[473]
  PIN a[474]
    DIRECTION INPUT ;
    USE SIGNAL ;
    PORT
      LAYER M4 ;
        RECT  0 22.896 0.084 22.92 ;
    END
  END a[474]
  PIN a[475]
    DIRECTION INPUT ;
    USE SIGNAL ;
    PORT
      LAYER M4 ;
        RECT  0 23.04 0.084 23.064 ;
    END
  END a[475]
  PIN a[476]
    DIRECTION INPUT ;
    USE SIGNAL ;
    PORT
      LAYER M4 ;
        RECT  0 23.184 0.084 23.208 ;
    END
  END a[476]
  PIN a[477]
    DIRECTION INPUT ;
    USE SIGNAL ;
    PORT
      LAYER M4 ;
        RECT  0 23.328 0.084 23.352 ;
    END
  END a[477]
  PIN a[478]
    DIRECTION INPUT ;
    USE SIGNAL ;
    PORT
      LAYER M4 ;
        RECT  0 23.472 0.084 23.496 ;
    END
  END a[478]
  PIN a[479]
    DIRECTION INPUT ;
    USE SIGNAL ;
    PORT
      LAYER M4 ;
        RECT  0 23.616 0.084 23.64 ;
    END
  END a[479]
  PIN a[47]
    DIRECTION INPUT ;
    USE SIGNAL ;
    PORT
      LAYER M4 ;
        RECT  0 45.504 0.084 45.528 ;
    END
  END a[47]
  PIN a[480]
    DIRECTION INPUT ;
    USE SIGNAL ;
    PORT
      LAYER M4 ;
        RECT  0 14.544 0.084 14.568 ;
    END
  END a[480]
  PIN a[481]
    DIRECTION INPUT ;
    USE SIGNAL ;
    PORT
      LAYER M4 ;
        RECT  0 14.688 0.084 14.712 ;
    END
  END a[481]
  PIN a[482]
    DIRECTION INPUT ;
    USE SIGNAL ;
    PORT
      LAYER M4 ;
        RECT  0 14.832 0.084 14.856 ;
    END
  END a[482]
  PIN a[483]
    DIRECTION INPUT ;
    USE SIGNAL ;
    PORT
      LAYER M4 ;
        RECT  0 14.976 0.084 15 ;
    END
  END a[483]
  PIN a[484]
    DIRECTION INPUT ;
    USE SIGNAL ;
    PORT
      LAYER M4 ;
        RECT  0 15.12 0.084 15.144 ;
    END
  END a[484]
  PIN a[485]
    DIRECTION INPUT ;
    USE SIGNAL ;
    PORT
      LAYER M4 ;
        RECT  0 15.264 0.084 15.288 ;
    END
  END a[485]
  PIN a[486]
    DIRECTION INPUT ;
    USE SIGNAL ;
    PORT
      LAYER M4 ;
        RECT  0 15.408 0.084 15.432 ;
    END
  END a[486]
  PIN a[487]
    DIRECTION INPUT ;
    USE SIGNAL ;
    PORT
      LAYER M4 ;
        RECT  0 15.552 0.084 15.576 ;
    END
  END a[487]
  PIN a[488]
    DIRECTION INPUT ;
    USE SIGNAL ;
    PORT
      LAYER M4 ;
        RECT  0 15.696 0.084 15.72 ;
    END
  END a[488]
  PIN a[489]
    DIRECTION INPUT ;
    USE SIGNAL ;
    PORT
      LAYER M4 ;
        RECT  0 15.84 0.084 15.864 ;
    END
  END a[489]
  PIN a[48]
    DIRECTION INPUT ;
    USE SIGNAL ;
    PORT
      LAYER M4 ;
        RECT  0 45.648 0.084 45.672 ;
    END
  END a[48]
  PIN a[490]
    DIRECTION INPUT ;
    USE SIGNAL ;
    PORT
      LAYER M4 ;
        RECT  0 15.984 0.084 16.008 ;
    END
  END a[490]
  PIN a[491]
    DIRECTION INPUT ;
    USE SIGNAL ;
    PORT
      LAYER M4 ;
        RECT  0 16.128 0.084 16.152 ;
    END
  END a[491]
  PIN a[492]
    DIRECTION INPUT ;
    USE SIGNAL ;
    PORT
      LAYER M4 ;
        RECT  0 16.272 0.084 16.296 ;
    END
  END a[492]
  PIN a[493]
    DIRECTION INPUT ;
    USE SIGNAL ;
    PORT
      LAYER M4 ;
        RECT  0 16.416 0.084 16.44 ;
    END
  END a[493]
  PIN a[494]
    DIRECTION INPUT ;
    USE SIGNAL ;
    PORT
      LAYER M4 ;
        RECT  0 16.56 0.084 16.584 ;
    END
  END a[494]
  PIN a[495]
    DIRECTION INPUT ;
    USE SIGNAL ;
    PORT
      LAYER M4 ;
        RECT  0 16.704 0.084 16.728 ;
    END
  END a[495]
  PIN a[496]
    DIRECTION INPUT ;
    USE SIGNAL ;
    PORT
      LAYER M4 ;
        RECT  0 16.848 0.084 16.872 ;
    END
  END a[496]
  PIN a[497]
    DIRECTION INPUT ;
    USE SIGNAL ;
    PORT
      LAYER M4 ;
        RECT  0 16.992 0.084 17.016 ;
    END
  END a[497]
  PIN a[498]
    DIRECTION INPUT ;
    USE SIGNAL ;
    PORT
      LAYER M4 ;
        RECT  0 17.136 0.084 17.16 ;
    END
  END a[498]
  PIN a[499]
    DIRECTION INPUT ;
    USE SIGNAL ;
    PORT
      LAYER M4 ;
        RECT  0 17.28 0.084 17.304 ;
    END
  END a[499]
  PIN a[49]
    DIRECTION INPUT ;
    USE SIGNAL ;
    PORT
      LAYER M4 ;
        RECT  0 45.792 0.084 45.816 ;
    END
  END a[49]
  PIN a[4]
    DIRECTION INPUT ;
    USE SIGNAL ;
    PORT
      LAYER M4 ;
        RECT  0 25.488 0.084 25.512 ;
    END
  END a[4]
  PIN a[500]
    DIRECTION INPUT ;
    USE SIGNAL ;
    PORT
      LAYER M4 ;
        RECT  0 17.424 0.084 17.448 ;
    END
  END a[500]
  PIN a[501]
    DIRECTION INPUT ;
    USE SIGNAL ;
    PORT
      LAYER M4 ;
        RECT  0 17.568 0.084 17.592 ;
    END
  END a[501]
  PIN a[502]
    DIRECTION INPUT ;
    USE SIGNAL ;
    PORT
      LAYER M4 ;
        RECT  0 17.712 0.084 17.736 ;
    END
  END a[502]
  PIN a[503]
    DIRECTION INPUT ;
    USE SIGNAL ;
    PORT
      LAYER M4 ;
        RECT  0 17.856 0.084 17.88 ;
    END
  END a[503]
  PIN a[504]
    DIRECTION INPUT ;
    USE SIGNAL ;
    PORT
      LAYER M4 ;
        RECT  0 18 0.084 18.024 ;
    END
  END a[504]
  PIN a[505]
    DIRECTION INPUT ;
    USE SIGNAL ;
    PORT
      LAYER M4 ;
        RECT  0 18.144 0.084 18.168 ;
    END
  END a[505]
  PIN a[506]
    DIRECTION INPUT ;
    USE SIGNAL ;
    PORT
      LAYER M4 ;
        RECT  0 18.288 0.084 18.312 ;
    END
  END a[506]
  PIN a[507]
    DIRECTION INPUT ;
    USE SIGNAL ;
    PORT
      LAYER M4 ;
        RECT  0 18.432 0.084 18.456 ;
    END
  END a[507]
  PIN a[508]
    DIRECTION INPUT ;
    USE SIGNAL ;
    PORT
      LAYER M4 ;
        RECT  0 18.576 0.084 18.6 ;
    END
  END a[508]
  PIN a[509]
    DIRECTION INPUT ;
    USE SIGNAL ;
    PORT
      LAYER M4 ;
        RECT  0 18.72 0.084 18.744 ;
    END
  END a[509]
  PIN a[50]
    DIRECTION INPUT ;
    USE SIGNAL ;
    PORT
      LAYER M4 ;
        RECT  0 45.936 0.084 45.96 ;
    END
  END a[50]
  PIN a[510]
    DIRECTION INPUT ;
    USE SIGNAL ;
    PORT
      LAYER M4 ;
        RECT  0 18.864 0.084 18.888 ;
    END
  END a[510]
  PIN a[511]
    DIRECTION INPUT ;
    USE SIGNAL ;
    PORT
      LAYER M4 ;
        RECT  0 19.008 0.084 19.032 ;
    END
  END a[511]
  PIN a[512]
    DIRECTION INPUT ;
    USE SIGNAL ;
    PORT
      LAYER M4 ;
        RECT  0 3.024 0.084 3.048 ;
    END
  END a[512]
  PIN a[513]
    DIRECTION INPUT ;
    USE SIGNAL ;
    PORT
      LAYER M4 ;
        RECT  0 3.168 0.084 3.192 ;
    END
  END a[513]
  PIN a[514]
    DIRECTION INPUT ;
    USE SIGNAL ;
    PORT
      LAYER M4 ;
        RECT  0 3.312 0.084 3.336 ;
    END
  END a[514]
  PIN a[515]
    DIRECTION INPUT ;
    USE SIGNAL ;
    PORT
      LAYER M4 ;
        RECT  0 3.456 0.084 3.48 ;
    END
  END a[515]
  PIN a[516]
    DIRECTION INPUT ;
    USE SIGNAL ;
    PORT
      LAYER M4 ;
        RECT  0 3.6 0.084 3.624 ;
    END
  END a[516]
  PIN a[517]
    DIRECTION INPUT ;
    USE SIGNAL ;
    PORT
      LAYER M4 ;
        RECT  0 3.744 0.084 3.768 ;
    END
  END a[517]
  PIN a[518]
    DIRECTION INPUT ;
    USE SIGNAL ;
    PORT
      LAYER M4 ;
        RECT  0 3.888 0.084 3.912 ;
    END
  END a[518]
  PIN a[519]
    DIRECTION INPUT ;
    USE SIGNAL ;
    PORT
      LAYER M4 ;
        RECT  0 4.032 0.084 4.056 ;
    END
  END a[519]
  PIN a[51]
    DIRECTION INPUT ;
    USE SIGNAL ;
    PORT
      LAYER M4 ;
        RECT  0 46.08 0.084 46.104 ;
    END
  END a[51]
  PIN a[520]
    DIRECTION INPUT ;
    USE SIGNAL ;
    PORT
      LAYER M4 ;
        RECT  0 4.176 0.084 4.2 ;
    END
  END a[520]
  PIN a[521]
    DIRECTION INPUT ;
    USE SIGNAL ;
    PORT
      LAYER M4 ;
        RECT  0 4.32 0.084 4.344 ;
    END
  END a[521]
  PIN a[522]
    DIRECTION INPUT ;
    USE SIGNAL ;
    PORT
      LAYER M4 ;
        RECT  0 4.464 0.084 4.488 ;
    END
  END a[522]
  PIN a[523]
    DIRECTION INPUT ;
    USE SIGNAL ;
    PORT
      LAYER M4 ;
        RECT  0 4.608 0.084 4.632 ;
    END
  END a[523]
  PIN a[524]
    DIRECTION INPUT ;
    USE SIGNAL ;
    PORT
      LAYER M4 ;
        RECT  0 4.752 0.084 4.776 ;
    END
  END a[524]
  PIN a[525]
    DIRECTION INPUT ;
    USE SIGNAL ;
    PORT
      LAYER M4 ;
        RECT  0 4.896 0.084 4.92 ;
    END
  END a[525]
  PIN a[526]
    DIRECTION INPUT ;
    USE SIGNAL ;
    PORT
      LAYER M4 ;
        RECT  0 5.04 0.084 5.064 ;
    END
  END a[526]
  PIN a[527]
    DIRECTION INPUT ;
    USE SIGNAL ;
    PORT
      LAYER M4 ;
        RECT  0 5.184 0.084 5.208 ;
    END
  END a[527]
  PIN a[52]
    DIRECTION INPUT ;
    USE SIGNAL ;
    PORT
      LAYER M4 ;
        RECT  0 46.224 0.084 46.248 ;
    END
  END a[52]
  PIN a[53]
    DIRECTION INPUT ;
    USE SIGNAL ;
    PORT
      LAYER M4 ;
        RECT  0 46.368 0.084 46.392 ;
    END
  END a[53]
  PIN a[54]
    DIRECTION INPUT ;
    USE SIGNAL ;
    PORT
      LAYER M4 ;
        RECT  0 46.512 0.084 46.536 ;
    END
  END a[54]
  PIN a[55]
    DIRECTION INPUT ;
    USE SIGNAL ;
    PORT
      LAYER M4 ;
        RECT  0 46.656 0.084 46.68 ;
    END
  END a[55]
  PIN a[56]
    DIRECTION INPUT ;
    USE SIGNAL ;
    PORT
      LAYER M4 ;
        RECT  0 46.8 0.084 46.824 ;
    END
  END a[56]
  PIN a[57]
    DIRECTION INPUT ;
    USE SIGNAL ;
    PORT
      LAYER M4 ;
        RECT  0 46.944 0.084 46.968 ;
    END
  END a[57]
  PIN a[58]
    DIRECTION INPUT ;
    USE SIGNAL ;
    PORT
      LAYER M4 ;
        RECT  0 47.088 0.084 47.112 ;
    END
  END a[58]
  PIN a[59]
    DIRECTION INPUT ;
    USE SIGNAL ;
    PORT
      LAYER M4 ;
        RECT  0 47.232 0.084 47.256 ;
    END
  END a[59]
  PIN a[5]
    DIRECTION INPUT ;
    USE SIGNAL ;
    PORT
      LAYER M4 ;
        RECT  0 25.632 0.084 25.656 ;
    END
  END a[5]
  PIN a[60]
    DIRECTION INPUT ;
    USE SIGNAL ;
    PORT
      LAYER M4 ;
        RECT  0 47.376 0.084 47.4 ;
    END
  END a[60]
  PIN a[61]
    DIRECTION INPUT ;
    USE SIGNAL ;
    PORT
      LAYER M4 ;
        RECT  0 47.52 0.084 47.544 ;
    END
  END a[61]
  PIN a[62]
    DIRECTION INPUT ;
    USE SIGNAL ;
    PORT
      LAYER M4 ;
        RECT  0 47.664 0.084 47.688 ;
    END
  END a[62]
  PIN a[63]
    DIRECTION INPUT ;
    USE SIGNAL ;
    PORT
      LAYER M4 ;
        RECT  0 47.808 0.084 47.832 ;
    END
  END a[63]
  PIN a[64]
    DIRECTION INPUT ;
    USE SIGNAL ;
    PORT
      LAYER M4 ;
        RECT  0 38.736 0.084 38.76 ;
    END
  END a[64]
  PIN a[65]
    DIRECTION INPUT ;
    USE SIGNAL ;
    PORT
      LAYER M4 ;
        RECT  0 38.88 0.084 38.904 ;
    END
  END a[65]
  PIN a[66]
    DIRECTION INPUT ;
    USE SIGNAL ;
    PORT
      LAYER M4 ;
        RECT  0 39.024 0.084 39.048 ;
    END
  END a[66]
  PIN a[67]
    DIRECTION INPUT ;
    USE SIGNAL ;
    PORT
      LAYER M4 ;
        RECT  0 39.168 0.084 39.192 ;
    END
  END a[67]
  PIN a[68]
    DIRECTION INPUT ;
    USE SIGNAL ;
    PORT
      LAYER M4 ;
        RECT  0 39.312 0.084 39.336 ;
    END
  END a[68]
  PIN a[69]
    DIRECTION INPUT ;
    USE SIGNAL ;
    PORT
      LAYER M4 ;
        RECT  0 39.456 0.084 39.48 ;
    END
  END a[69]
  PIN a[6]
    DIRECTION INPUT ;
    USE SIGNAL ;
    PORT
      LAYER M4 ;
        RECT  0 25.776 0.084 25.8 ;
    END
  END a[6]
  PIN a[70]
    DIRECTION INPUT ;
    USE SIGNAL ;
    PORT
      LAYER M4 ;
        RECT  0 39.6 0.084 39.624 ;
    END
  END a[70]
  PIN a[71]
    DIRECTION INPUT ;
    USE SIGNAL ;
    PORT
      LAYER M4 ;
        RECT  0 39.744 0.084 39.768 ;
    END
  END a[71]
  PIN a[72]
    DIRECTION INPUT ;
    USE SIGNAL ;
    PORT
      LAYER M4 ;
        RECT  0 39.888 0.084 39.912 ;
    END
  END a[72]
  PIN a[73]
    DIRECTION INPUT ;
    USE SIGNAL ;
    PORT
      LAYER M4 ;
        RECT  0 40.032 0.084 40.056 ;
    END
  END a[73]
  PIN a[74]
    DIRECTION INPUT ;
    USE SIGNAL ;
    PORT
      LAYER M4 ;
        RECT  0 40.176 0.084 40.2 ;
    END
  END a[74]
  PIN a[75]
    DIRECTION INPUT ;
    USE SIGNAL ;
    PORT
      LAYER M4 ;
        RECT  0 40.32 0.084 40.344 ;
    END
  END a[75]
  PIN a[76]
    DIRECTION INPUT ;
    USE SIGNAL ;
    PORT
      LAYER M4 ;
        RECT  0 40.464 0.084 40.488 ;
    END
  END a[76]
  PIN a[77]
    DIRECTION INPUT ;
    USE SIGNAL ;
    PORT
      LAYER M4 ;
        RECT  0 40.608 0.084 40.632 ;
    END
  END a[77]
  PIN a[78]
    DIRECTION INPUT ;
    USE SIGNAL ;
    PORT
      LAYER M4 ;
        RECT  0 40.752 0.084 40.776 ;
    END
  END a[78]
  PIN a[79]
    DIRECTION INPUT ;
    USE SIGNAL ;
    PORT
      LAYER M4 ;
        RECT  0 40.896 0.084 40.92 ;
    END
  END a[79]
  PIN a[7]
    DIRECTION INPUT ;
    USE SIGNAL ;
    PORT
      LAYER M4 ;
        RECT  0 25.92 0.084 25.944 ;
    END
  END a[7]
  PIN a[80]
    DIRECTION INPUT ;
    USE SIGNAL ;
    PORT
      LAYER M4 ;
        RECT  0 41.04 0.084 41.064 ;
    END
  END a[80]
  PIN a[81]
    DIRECTION INPUT ;
    USE SIGNAL ;
    PORT
      LAYER M4 ;
        RECT  0 41.184 0.084 41.208 ;
    END
  END a[81]
  PIN a[82]
    DIRECTION INPUT ;
    USE SIGNAL ;
    PORT
      LAYER M4 ;
        RECT  0 41.328 0.084 41.352 ;
    END
  END a[82]
  PIN a[83]
    DIRECTION INPUT ;
    USE SIGNAL ;
    PORT
      LAYER M4 ;
        RECT  0 41.472 0.084 41.496 ;
    END
  END a[83]
  PIN a[84]
    DIRECTION INPUT ;
    USE SIGNAL ;
    PORT
      LAYER M4 ;
        RECT  0 41.616 0.084 41.64 ;
    END
  END a[84]
  PIN a[85]
    DIRECTION INPUT ;
    USE SIGNAL ;
    PORT
      LAYER M4 ;
        RECT  0 41.76 0.084 41.784 ;
    END
  END a[85]
  PIN a[86]
    DIRECTION INPUT ;
    USE SIGNAL ;
    PORT
      LAYER M4 ;
        RECT  0 41.904 0.084 41.928 ;
    END
  END a[86]
  PIN a[87]
    DIRECTION INPUT ;
    USE SIGNAL ;
    PORT
      LAYER M4 ;
        RECT  0 42.048 0.084 42.072 ;
    END
  END a[87]
  PIN a[88]
    DIRECTION INPUT ;
    USE SIGNAL ;
    PORT
      LAYER M4 ;
        RECT  0 42.192 0.084 42.216 ;
    END
  END a[88]
  PIN a[89]
    DIRECTION INPUT ;
    USE SIGNAL ;
    PORT
      LAYER M4 ;
        RECT  0 42.336 0.084 42.36 ;
    END
  END a[89]
  PIN a[8]
    DIRECTION INPUT ;
    USE SIGNAL ;
    PORT
      LAYER M4 ;
        RECT  0 26.064 0.084 26.088 ;
    END
  END a[8]
  PIN a[90]
    DIRECTION INPUT ;
    USE SIGNAL ;
    PORT
      LAYER M4 ;
        RECT  0 42.48 0.084 42.504 ;
    END
  END a[90]
  PIN a[91]
    DIRECTION INPUT ;
    USE SIGNAL ;
    PORT
      LAYER M4 ;
        RECT  0 42.624 0.084 42.648 ;
    END
  END a[91]
  PIN a[92]
    DIRECTION INPUT ;
    USE SIGNAL ;
    PORT
      LAYER M4 ;
        RECT  0 42.768 0.084 42.792 ;
    END
  END a[92]
  PIN a[93]
    DIRECTION INPUT ;
    USE SIGNAL ;
    PORT
      LAYER M4 ;
        RECT  0 42.912 0.084 42.936 ;
    END
  END a[93]
  PIN a[94]
    DIRECTION INPUT ;
    USE SIGNAL ;
    PORT
      LAYER M4 ;
        RECT  0 43.056 0.084 43.08 ;
    END
  END a[94]
  PIN a[95]
    DIRECTION INPUT ;
    USE SIGNAL ;
    PORT
      LAYER M4 ;
        RECT  0 43.2 0.084 43.224 ;
    END
  END a[95]
  PIN a[96]
    DIRECTION INPUT ;
    USE SIGNAL ;
    PORT
      LAYER M4 ;
        RECT  0 47.952 0.084 47.976 ;
    END
  END a[96]
  PIN a[97]
    DIRECTION INPUT ;
    USE SIGNAL ;
    PORT
      LAYER M4 ;
        RECT  0 48.096 0.084 48.12 ;
    END
  END a[97]
  PIN a[98]
    DIRECTION INPUT ;
    USE SIGNAL ;
    PORT
      LAYER M4 ;
        RECT  0 48.24 0.084 48.264 ;
    END
  END a[98]
  PIN a[99]
    DIRECTION INPUT ;
    USE SIGNAL ;
    PORT
      LAYER M4 ;
        RECT  0 48.384 0.084 48.408 ;
    END
  END a[99]
  PIN a[9]
    DIRECTION INPUT ;
    USE SIGNAL ;
    PORT
      LAYER M4 ;
        RECT  0 26.208 0.084 26.232 ;
    END
  END a[9]
  PIN b[0]
    DIRECTION OUTPUT ;
    USE SIGNAL ;
    PORT
      LAYER M4 ;
        RECT  21.516 29.52 21.6 29.544 ;
    END
  END b[0]
  PIN b[100]
    DIRECTION OUTPUT ;
    USE SIGNAL ;
    PORT
      LAYER M4 ;
        RECT  21.516 53.136 21.6 53.16 ;
    END
  END b[100]
  PIN b[101]
    DIRECTION OUTPUT ;
    USE SIGNAL ;
    PORT
      LAYER M4 ;
        RECT  21.516 53.28 21.6 53.304 ;
    END
  END b[101]
  PIN b[102]
    DIRECTION OUTPUT ;
    USE SIGNAL ;
    PORT
      LAYER M4 ;
        RECT  21.516 53.424 21.6 53.448 ;
    END
  END b[102]
  PIN b[103]
    DIRECTION OUTPUT ;
    USE SIGNAL ;
    PORT
      LAYER M4 ;
        RECT  21.516 53.568 21.6 53.592 ;
    END
  END b[103]
  PIN b[104]
    DIRECTION OUTPUT ;
    USE SIGNAL ;
    PORT
      LAYER M4 ;
        RECT  21.516 53.712 21.6 53.736 ;
    END
  END b[104]
  PIN b[105]
    DIRECTION OUTPUT ;
    USE SIGNAL ;
    PORT
      LAYER M4 ;
        RECT  21.516 53.856 21.6 53.88 ;
    END
  END b[105]
  PIN b[106]
    DIRECTION OUTPUT ;
    USE SIGNAL ;
    PORT
      LAYER M4 ;
        RECT  21.516 54 21.6 54.024 ;
    END
  END b[106]
  PIN b[107]
    DIRECTION OUTPUT ;
    USE SIGNAL ;
    PORT
      LAYER M4 ;
        RECT  21.516 54.144 21.6 54.168 ;
    END
  END b[107]
  PIN b[108]
    DIRECTION OUTPUT ;
    USE SIGNAL ;
    PORT
      LAYER M4 ;
        RECT  21.516 54.288 21.6 54.312 ;
    END
  END b[108]
  PIN b[109]
    DIRECTION OUTPUT ;
    USE SIGNAL ;
    PORT
      LAYER M4 ;
        RECT  21.516 54.432 21.6 54.456 ;
    END
  END b[109]
  PIN b[10]
    DIRECTION OUTPUT ;
    USE SIGNAL ;
    PORT
      LAYER M4 ;
        RECT  21.516 30.96 21.6 30.984 ;
    END
  END b[10]
  PIN b[110]
    DIRECTION OUTPUT ;
    USE SIGNAL ;
    PORT
      LAYER M4 ;
        RECT  21.516 54.576 21.6 54.6 ;
    END
  END b[110]
  PIN b[111]
    DIRECTION OUTPUT ;
    USE SIGNAL ;
    PORT
      LAYER M4 ;
        RECT  21.516 54.72 21.6 54.744 ;
    END
  END b[111]
  PIN b[112]
    DIRECTION OUTPUT ;
    USE SIGNAL ;
    PORT
      LAYER M4 ;
        RECT  21.516 54.864 21.6 54.888 ;
    END
  END b[112]
  PIN b[113]
    DIRECTION OUTPUT ;
    USE SIGNAL ;
    PORT
      LAYER M4 ;
        RECT  21.516 55.008 21.6 55.032 ;
    END
  END b[113]
  PIN b[114]
    DIRECTION OUTPUT ;
    USE SIGNAL ;
    PORT
      LAYER M4 ;
        RECT  21.516 55.152 21.6 55.176 ;
    END
  END b[114]
  PIN b[115]
    DIRECTION OUTPUT ;
    USE SIGNAL ;
    PORT
      LAYER M4 ;
        RECT  21.516 55.296 21.6 55.32 ;
    END
  END b[115]
  PIN b[116]
    DIRECTION OUTPUT ;
    USE SIGNAL ;
    PORT
      LAYER M4 ;
        RECT  21.516 55.44 21.6 55.464 ;
    END
  END b[116]
  PIN b[117]
    DIRECTION OUTPUT ;
    USE SIGNAL ;
    PORT
      LAYER M4 ;
        RECT  21.516 55.584 21.6 55.608 ;
    END
  END b[117]
  PIN b[118]
    DIRECTION OUTPUT ;
    USE SIGNAL ;
    PORT
      LAYER M4 ;
        RECT  21.516 55.728 21.6 55.752 ;
    END
  END b[118]
  PIN b[119]
    DIRECTION OUTPUT ;
    USE SIGNAL ;
    PORT
      LAYER M4 ;
        RECT  21.516 55.872 21.6 55.896 ;
    END
  END b[119]
  PIN b[11]
    DIRECTION OUTPUT ;
    USE SIGNAL ;
    PORT
      LAYER M4 ;
        RECT  21.516 31.104 21.6 31.128 ;
    END
  END b[11]
  PIN b[120]
    DIRECTION OUTPUT ;
    USE SIGNAL ;
    PORT
      LAYER M4 ;
        RECT  21.516 56.016 21.6 56.04 ;
    END
  END b[120]
  PIN b[121]
    DIRECTION OUTPUT ;
    USE SIGNAL ;
    PORT
      LAYER M4 ;
        RECT  21.516 56.16 21.6 56.184 ;
    END
  END b[121]
  PIN b[122]
    DIRECTION OUTPUT ;
    USE SIGNAL ;
    PORT
      LAYER M4 ;
        RECT  21.516 56.304 21.6 56.328 ;
    END
  END b[122]
  PIN b[123]
    DIRECTION OUTPUT ;
    USE SIGNAL ;
    PORT
      LAYER M4 ;
        RECT  21.516 56.448 21.6 56.472 ;
    END
  END b[123]
  PIN b[124]
    DIRECTION OUTPUT ;
    USE SIGNAL ;
    PORT
      LAYER M4 ;
        RECT  21.516 56.592 21.6 56.616 ;
    END
  END b[124]
  PIN b[125]
    DIRECTION OUTPUT ;
    USE SIGNAL ;
    PORT
      LAYER M4 ;
        RECT  21.516 56.736 21.6 56.76 ;
    END
  END b[125]
  PIN b[126]
    DIRECTION OUTPUT ;
    USE SIGNAL ;
    PORT
      LAYER M4 ;
        RECT  21.516 56.88 21.6 56.904 ;
    END
  END b[126]
  PIN b[127]
    DIRECTION OUTPUT ;
    USE SIGNAL ;
    PORT
      LAYER M4 ;
        RECT  21.516 57.024 21.6 57.048 ;
    END
  END b[127]
  PIN b[128]
    DIRECTION OUTPUT ;
    USE SIGNAL ;
    PORT
      LAYER M4 ;
        RECT  21.516 34.128 21.6 34.152 ;
    END
  END b[128]
  PIN b[129]
    DIRECTION OUTPUT ;
    USE SIGNAL ;
    PORT
      LAYER M4 ;
        RECT  21.516 34.272 21.6 34.296 ;
    END
  END b[129]
  PIN b[12]
    DIRECTION OUTPUT ;
    USE SIGNAL ;
    PORT
      LAYER M4 ;
        RECT  21.516 31.248 21.6 31.272 ;
    END
  END b[12]
  PIN b[130]
    DIRECTION OUTPUT ;
    USE SIGNAL ;
    PORT
      LAYER M4 ;
        RECT  21.516 34.416 21.6 34.44 ;
    END
  END b[130]
  PIN b[131]
    DIRECTION OUTPUT ;
    USE SIGNAL ;
    PORT
      LAYER M4 ;
        RECT  21.516 34.56 21.6 34.584 ;
    END
  END b[131]
  PIN b[132]
    DIRECTION OUTPUT ;
    USE SIGNAL ;
    PORT
      LAYER M4 ;
        RECT  21.516 34.704 21.6 34.728 ;
    END
  END b[132]
  PIN b[133]
    DIRECTION OUTPUT ;
    USE SIGNAL ;
    PORT
      LAYER M4 ;
        RECT  21.516 34.848 21.6 34.872 ;
    END
  END b[133]
  PIN b[134]
    DIRECTION OUTPUT ;
    USE SIGNAL ;
    PORT
      LAYER M4 ;
        RECT  21.516 34.992 21.6 35.016 ;
    END
  END b[134]
  PIN b[135]
    DIRECTION OUTPUT ;
    USE SIGNAL ;
    PORT
      LAYER M4 ;
        RECT  21.516 35.136 21.6 35.16 ;
    END
  END b[135]
  PIN b[136]
    DIRECTION OUTPUT ;
    USE SIGNAL ;
    PORT
      LAYER M4 ;
        RECT  21.516 35.28 21.6 35.304 ;
    END
  END b[136]
  PIN b[137]
    DIRECTION OUTPUT ;
    USE SIGNAL ;
    PORT
      LAYER M4 ;
        RECT  21.516 35.424 21.6 35.448 ;
    END
  END b[137]
  PIN b[138]
    DIRECTION OUTPUT ;
    USE SIGNAL ;
    PORT
      LAYER M4 ;
        RECT  21.516 35.568 21.6 35.592 ;
    END
  END b[138]
  PIN b[139]
    DIRECTION OUTPUT ;
    USE SIGNAL ;
    PORT
      LAYER M4 ;
        RECT  21.516 35.712 21.6 35.736 ;
    END
  END b[139]
  PIN b[13]
    DIRECTION OUTPUT ;
    USE SIGNAL ;
    PORT
      LAYER M4 ;
        RECT  21.516 31.392 21.6 31.416 ;
    END
  END b[13]
  PIN b[140]
    DIRECTION OUTPUT ;
    USE SIGNAL ;
    PORT
      LAYER M4 ;
        RECT  21.516 35.856 21.6 35.88 ;
    END
  END b[140]
  PIN b[141]
    DIRECTION OUTPUT ;
    USE SIGNAL ;
    PORT
      LAYER M4 ;
        RECT  21.516 36 21.6 36.024 ;
    END
  END b[141]
  PIN b[142]
    DIRECTION OUTPUT ;
    USE SIGNAL ;
    PORT
      LAYER M4 ;
        RECT  21.516 36.144 21.6 36.168 ;
    END
  END b[142]
  PIN b[143]
    DIRECTION OUTPUT ;
    USE SIGNAL ;
    PORT
      LAYER M4 ;
        RECT  21.516 36.288 21.6 36.312 ;
    END
  END b[143]
  PIN b[144]
    DIRECTION OUTPUT ;
    USE SIGNAL ;
    PORT
      LAYER M4 ;
        RECT  21.516 36.432 21.6 36.456 ;
    END
  END b[144]
  PIN b[145]
    DIRECTION OUTPUT ;
    USE SIGNAL ;
    PORT
      LAYER M4 ;
        RECT  21.516 36.576 21.6 36.6 ;
    END
  END b[145]
  PIN b[146]
    DIRECTION OUTPUT ;
    USE SIGNAL ;
    PORT
      LAYER M4 ;
        RECT  21.516 36.72 21.6 36.744 ;
    END
  END b[146]
  PIN b[147]
    DIRECTION OUTPUT ;
    USE SIGNAL ;
    PORT
      LAYER M4 ;
        RECT  21.516 36.864 21.6 36.888 ;
    END
  END b[147]
  PIN b[148]
    DIRECTION OUTPUT ;
    USE SIGNAL ;
    PORT
      LAYER M4 ;
        RECT  21.516 37.008 21.6 37.032 ;
    END
  END b[148]
  PIN b[149]
    DIRECTION OUTPUT ;
    USE SIGNAL ;
    PORT
      LAYER M4 ;
        RECT  21.516 37.152 21.6 37.176 ;
    END
  END b[149]
  PIN b[14]
    DIRECTION OUTPUT ;
    USE SIGNAL ;
    PORT
      LAYER M4 ;
        RECT  21.516 31.536 21.6 31.56 ;
    END
  END b[14]
  PIN b[150]
    DIRECTION OUTPUT ;
    USE SIGNAL ;
    PORT
      LAYER M4 ;
        RECT  21.516 37.296 21.6 37.32 ;
    END
  END b[150]
  PIN b[151]
    DIRECTION OUTPUT ;
    USE SIGNAL ;
    PORT
      LAYER M4 ;
        RECT  21.516 37.44 21.6 37.464 ;
    END
  END b[151]
  PIN b[152]
    DIRECTION OUTPUT ;
    USE SIGNAL ;
    PORT
      LAYER M4 ;
        RECT  21.516 37.584 21.6 37.608 ;
    END
  END b[152]
  PIN b[153]
    DIRECTION OUTPUT ;
    USE SIGNAL ;
    PORT
      LAYER M4 ;
        RECT  21.516 37.728 21.6 37.752 ;
    END
  END b[153]
  PIN b[154]
    DIRECTION OUTPUT ;
    USE SIGNAL ;
    PORT
      LAYER M4 ;
        RECT  21.516 37.872 21.6 37.896 ;
    END
  END b[154]
  PIN b[155]
    DIRECTION OUTPUT ;
    USE SIGNAL ;
    PORT
      LAYER M4 ;
        RECT  21.516 38.016 21.6 38.04 ;
    END
  END b[155]
  PIN b[156]
    DIRECTION OUTPUT ;
    USE SIGNAL ;
    PORT
      LAYER M4 ;
        RECT  21.516 38.16 21.6 38.184 ;
    END
  END b[156]
  PIN b[157]
    DIRECTION OUTPUT ;
    USE SIGNAL ;
    PORT
      LAYER M4 ;
        RECT  21.516 38.304 21.6 38.328 ;
    END
  END b[157]
  PIN b[158]
    DIRECTION OUTPUT ;
    USE SIGNAL ;
    PORT
      LAYER M4 ;
        RECT  21.516 38.448 21.6 38.472 ;
    END
  END b[158]
  PIN b[159]
    DIRECTION OUTPUT ;
    USE SIGNAL ;
    PORT
      LAYER M4 ;
        RECT  21.516 38.592 21.6 38.616 ;
    END
  END b[159]
  PIN b[15]
    DIRECTION OUTPUT ;
    USE SIGNAL ;
    PORT
      LAYER M4 ;
        RECT  21.516 31.68 21.6 31.704 ;
    END
  END b[15]
  PIN b[160]
    DIRECTION OUTPUT ;
    USE SIGNAL ;
    PORT
      LAYER M4 ;
        RECT  21.516 38.736 21.6 38.76 ;
    END
  END b[160]
  PIN b[161]
    DIRECTION OUTPUT ;
    USE SIGNAL ;
    PORT
      LAYER M4 ;
        RECT  21.516 38.88 21.6 38.904 ;
    END
  END b[161]
  PIN b[162]
    DIRECTION OUTPUT ;
    USE SIGNAL ;
    PORT
      LAYER M4 ;
        RECT  21.516 39.024 21.6 39.048 ;
    END
  END b[162]
  PIN b[163]
    DIRECTION OUTPUT ;
    USE SIGNAL ;
    PORT
      LAYER M4 ;
        RECT  21.516 39.168 21.6 39.192 ;
    END
  END b[163]
  PIN b[164]
    DIRECTION OUTPUT ;
    USE SIGNAL ;
    PORT
      LAYER M4 ;
        RECT  21.516 39.312 21.6 39.336 ;
    END
  END b[164]
  PIN b[165]
    DIRECTION OUTPUT ;
    USE SIGNAL ;
    PORT
      LAYER M4 ;
        RECT  21.516 39.456 21.6 39.48 ;
    END
  END b[165]
  PIN b[166]
    DIRECTION OUTPUT ;
    USE SIGNAL ;
    PORT
      LAYER M4 ;
        RECT  21.516 39.6 21.6 39.624 ;
    END
  END b[166]
  PIN b[167]
    DIRECTION OUTPUT ;
    USE SIGNAL ;
    PORT
      LAYER M4 ;
        RECT  21.516 39.744 21.6 39.768 ;
    END
  END b[167]
  PIN b[168]
    DIRECTION OUTPUT ;
    USE SIGNAL ;
    PORT
      LAYER M4 ;
        RECT  21.516 39.888 21.6 39.912 ;
    END
  END b[168]
  PIN b[169]
    DIRECTION OUTPUT ;
    USE SIGNAL ;
    PORT
      LAYER M4 ;
        RECT  21.516 40.032 21.6 40.056 ;
    END
  END b[169]
  PIN b[16]
    DIRECTION OUTPUT ;
    USE SIGNAL ;
    PORT
      LAYER M4 ;
        RECT  21.516 31.824 21.6 31.848 ;
    END
  END b[16]
  PIN b[170]
    DIRECTION OUTPUT ;
    USE SIGNAL ;
    PORT
      LAYER M4 ;
        RECT  21.516 40.176 21.6 40.2 ;
    END
  END b[170]
  PIN b[171]
    DIRECTION OUTPUT ;
    USE SIGNAL ;
    PORT
      LAYER M4 ;
        RECT  21.516 40.32 21.6 40.344 ;
    END
  END b[171]
  PIN b[172]
    DIRECTION OUTPUT ;
    USE SIGNAL ;
    PORT
      LAYER M4 ;
        RECT  21.516 40.464 21.6 40.488 ;
    END
  END b[172]
  PIN b[173]
    DIRECTION OUTPUT ;
    USE SIGNAL ;
    PORT
      LAYER M4 ;
        RECT  21.516 40.608 21.6 40.632 ;
    END
  END b[173]
  PIN b[174]
    DIRECTION OUTPUT ;
    USE SIGNAL ;
    PORT
      LAYER M4 ;
        RECT  21.516 40.752 21.6 40.776 ;
    END
  END b[174]
  PIN b[175]
    DIRECTION OUTPUT ;
    USE SIGNAL ;
    PORT
      LAYER M4 ;
        RECT  21.516 40.896 21.6 40.92 ;
    END
  END b[175]
  PIN b[176]
    DIRECTION OUTPUT ;
    USE SIGNAL ;
    PORT
      LAYER M4 ;
        RECT  21.516 41.04 21.6 41.064 ;
    END
  END b[176]
  PIN b[177]
    DIRECTION OUTPUT ;
    USE SIGNAL ;
    PORT
      LAYER M4 ;
        RECT  21.516 41.184 21.6 41.208 ;
    END
  END b[177]
  PIN b[178]
    DIRECTION OUTPUT ;
    USE SIGNAL ;
    PORT
      LAYER M4 ;
        RECT  21.516 41.328 21.6 41.352 ;
    END
  END b[178]
  PIN b[179]
    DIRECTION OUTPUT ;
    USE SIGNAL ;
    PORT
      LAYER M4 ;
        RECT  21.516 41.472 21.6 41.496 ;
    END
  END b[179]
  PIN b[17]
    DIRECTION OUTPUT ;
    USE SIGNAL ;
    PORT
      LAYER M4 ;
        RECT  21.516 31.968 21.6 31.992 ;
    END
  END b[17]
  PIN b[180]
    DIRECTION OUTPUT ;
    USE SIGNAL ;
    PORT
      LAYER M4 ;
        RECT  21.516 41.616 21.6 41.64 ;
    END
  END b[180]
  PIN b[181]
    DIRECTION OUTPUT ;
    USE SIGNAL ;
    PORT
      LAYER M4 ;
        RECT  21.516 41.76 21.6 41.784 ;
    END
  END b[181]
  PIN b[182]
    DIRECTION OUTPUT ;
    USE SIGNAL ;
    PORT
      LAYER M4 ;
        RECT  21.516 41.904 21.6 41.928 ;
    END
  END b[182]
  PIN b[183]
    DIRECTION OUTPUT ;
    USE SIGNAL ;
    PORT
      LAYER M4 ;
        RECT  21.516 42.048 21.6 42.072 ;
    END
  END b[183]
  PIN b[184]
    DIRECTION OUTPUT ;
    USE SIGNAL ;
    PORT
      LAYER M4 ;
        RECT  21.516 42.192 21.6 42.216 ;
    END
  END b[184]
  PIN b[185]
    DIRECTION OUTPUT ;
    USE SIGNAL ;
    PORT
      LAYER M4 ;
        RECT  21.516 42.336 21.6 42.36 ;
    END
  END b[185]
  PIN b[186]
    DIRECTION OUTPUT ;
    USE SIGNAL ;
    PORT
      LAYER M4 ;
        RECT  21.516 42.48 21.6 42.504 ;
    END
  END b[186]
  PIN b[187]
    DIRECTION OUTPUT ;
    USE SIGNAL ;
    PORT
      LAYER M4 ;
        RECT  21.516 42.624 21.6 42.648 ;
    END
  END b[187]
  PIN b[188]
    DIRECTION OUTPUT ;
    USE SIGNAL ;
    PORT
      LAYER M4 ;
        RECT  21.516 42.768 21.6 42.792 ;
    END
  END b[188]
  PIN b[189]
    DIRECTION OUTPUT ;
    USE SIGNAL ;
    PORT
      LAYER M4 ;
        RECT  21.516 42.912 21.6 42.936 ;
    END
  END b[189]
  PIN b[18]
    DIRECTION OUTPUT ;
    USE SIGNAL ;
    PORT
      LAYER M4 ;
        RECT  21.516 32.112 21.6 32.136 ;
    END
  END b[18]
  PIN b[190]
    DIRECTION OUTPUT ;
    USE SIGNAL ;
    PORT
      LAYER M4 ;
        RECT  21.516 43.056 21.6 43.08 ;
    END
  END b[190]
  PIN b[191]
    DIRECTION OUTPUT ;
    USE SIGNAL ;
    PORT
      LAYER M4 ;
        RECT  21.516 43.2 21.6 43.224 ;
    END
  END b[191]
  PIN b[192]
    DIRECTION OUTPUT ;
    USE SIGNAL ;
    PORT
      LAYER M4 ;
        RECT  21.516 0.72 21.6 0.744 ;
    END
  END b[192]
  PIN b[193]
    DIRECTION OUTPUT ;
    USE SIGNAL ;
    PORT
      LAYER M4 ;
        RECT  21.516 0.864 21.6 0.888 ;
    END
  END b[193]
  PIN b[194]
    DIRECTION OUTPUT ;
    USE SIGNAL ;
    PORT
      LAYER M4 ;
        RECT  21.516 1.008 21.6 1.032 ;
    END
  END b[194]
  PIN b[195]
    DIRECTION OUTPUT ;
    USE SIGNAL ;
    PORT
      LAYER M4 ;
        RECT  21.516 1.152 21.6 1.176 ;
    END
  END b[195]
  PIN b[196]
    DIRECTION OUTPUT ;
    USE SIGNAL ;
    PORT
      LAYER M4 ;
        RECT  21.516 1.296 21.6 1.32 ;
    END
  END b[196]
  PIN b[197]
    DIRECTION OUTPUT ;
    USE SIGNAL ;
    PORT
      LAYER M4 ;
        RECT  21.516 1.44 21.6 1.464 ;
    END
  END b[197]
  PIN b[198]
    DIRECTION OUTPUT ;
    USE SIGNAL ;
    PORT
      LAYER M4 ;
        RECT  21.516 1.584 21.6 1.608 ;
    END
  END b[198]
  PIN b[199]
    DIRECTION OUTPUT ;
    USE SIGNAL ;
    PORT
      LAYER M4 ;
        RECT  21.516 1.728 21.6 1.752 ;
    END
  END b[199]
  PIN b[19]
    DIRECTION OUTPUT ;
    USE SIGNAL ;
    PORT
      LAYER M4 ;
        RECT  21.516 32.256 21.6 32.28 ;
    END
  END b[19]
  PIN b[1]
    DIRECTION OUTPUT ;
    USE SIGNAL ;
    PORT
      LAYER M4 ;
        RECT  21.516 29.664 21.6 29.688 ;
    END
  END b[1]
  PIN b[200]
    DIRECTION OUTPUT ;
    USE SIGNAL ;
    PORT
      LAYER M4 ;
        RECT  21.516 1.872 21.6 1.896 ;
    END
  END b[200]
  PIN b[201]
    DIRECTION OUTPUT ;
    USE SIGNAL ;
    PORT
      LAYER M4 ;
        RECT  21.516 2.016 21.6 2.04 ;
    END
  END b[201]
  PIN b[202]
    DIRECTION OUTPUT ;
    USE SIGNAL ;
    PORT
      LAYER M4 ;
        RECT  21.516 2.16 21.6 2.184 ;
    END
  END b[202]
  PIN b[203]
    DIRECTION OUTPUT ;
    USE SIGNAL ;
    PORT
      LAYER M4 ;
        RECT  21.516 2.304 21.6 2.328 ;
    END
  END b[203]
  PIN b[204]
    DIRECTION OUTPUT ;
    USE SIGNAL ;
    PORT
      LAYER M4 ;
        RECT  21.516 2.448 21.6 2.472 ;
    END
  END b[204]
  PIN b[205]
    DIRECTION OUTPUT ;
    USE SIGNAL ;
    PORT
      LAYER M4 ;
        RECT  21.516 2.592 21.6 2.616 ;
    END
  END b[205]
  PIN b[206]
    DIRECTION OUTPUT ;
    USE SIGNAL ;
    PORT
      LAYER M4 ;
        RECT  21.516 2.736 21.6 2.76 ;
    END
  END b[206]
  PIN b[207]
    DIRECTION OUTPUT ;
    USE SIGNAL ;
    PORT
      LAYER M4 ;
        RECT  21.516 2.88 21.6 2.904 ;
    END
  END b[207]
  PIN b[208]
    DIRECTION OUTPUT ;
    USE SIGNAL ;
    PORT
      LAYER M4 ;
        RECT  21.516 3.024 21.6 3.048 ;
    END
  END b[208]
  PIN b[209]
    DIRECTION OUTPUT ;
    USE SIGNAL ;
    PORT
      LAYER M4 ;
        RECT  21.516 3.168 21.6 3.192 ;
    END
  END b[209]
  PIN b[20]
    DIRECTION OUTPUT ;
    USE SIGNAL ;
    PORT
      LAYER M4 ;
        RECT  21.516 32.4 21.6 32.424 ;
    END
  END b[20]
  PIN b[210]
    DIRECTION OUTPUT ;
    USE SIGNAL ;
    PORT
      LAYER M4 ;
        RECT  21.516 3.312 21.6 3.336 ;
    END
  END b[210]
  PIN b[211]
    DIRECTION OUTPUT ;
    USE SIGNAL ;
    PORT
      LAYER M4 ;
        RECT  21.516 3.456 21.6 3.48 ;
    END
  END b[211]
  PIN b[212]
    DIRECTION OUTPUT ;
    USE SIGNAL ;
    PORT
      LAYER M4 ;
        RECT  21.516 3.6 21.6 3.624 ;
    END
  END b[212]
  PIN b[213]
    DIRECTION OUTPUT ;
    USE SIGNAL ;
    PORT
      LAYER M4 ;
        RECT  21.516 3.744 21.6 3.768 ;
    END
  END b[213]
  PIN b[214]
    DIRECTION OUTPUT ;
    USE SIGNAL ;
    PORT
      LAYER M4 ;
        RECT  21.516 3.888 21.6 3.912 ;
    END
  END b[214]
  PIN b[215]
    DIRECTION OUTPUT ;
    USE SIGNAL ;
    PORT
      LAYER M4 ;
        RECT  21.516 4.032 21.6 4.056 ;
    END
  END b[215]
  PIN b[216]
    DIRECTION OUTPUT ;
    USE SIGNAL ;
    PORT
      LAYER M4 ;
        RECT  21.516 4.176 21.6 4.2 ;
    END
  END b[216]
  PIN b[217]
    DIRECTION OUTPUT ;
    USE SIGNAL ;
    PORT
      LAYER M4 ;
        RECT  21.516 4.32 21.6 4.344 ;
    END
  END b[217]
  PIN b[218]
    DIRECTION OUTPUT ;
    USE SIGNAL ;
    PORT
      LAYER M4 ;
        RECT  21.516 4.464 21.6 4.488 ;
    END
  END b[218]
  PIN b[219]
    DIRECTION OUTPUT ;
    USE SIGNAL ;
    PORT
      LAYER M4 ;
        RECT  21.516 4.608 21.6 4.632 ;
    END
  END b[219]
  PIN b[21]
    DIRECTION OUTPUT ;
    USE SIGNAL ;
    PORT
      LAYER M4 ;
        RECT  21.516 32.544 21.6 32.568 ;
    END
  END b[21]
  PIN b[220]
    DIRECTION OUTPUT ;
    USE SIGNAL ;
    PORT
      LAYER M4 ;
        RECT  21.516 4.752 21.6 4.776 ;
    END
  END b[220]
  PIN b[221]
    DIRECTION OUTPUT ;
    USE SIGNAL ;
    PORT
      LAYER M4 ;
        RECT  21.516 4.896 21.6 4.92 ;
    END
  END b[221]
  PIN b[222]
    DIRECTION OUTPUT ;
    USE SIGNAL ;
    PORT
      LAYER M4 ;
        RECT  21.516 5.04 21.6 5.064 ;
    END
  END b[222]
  PIN b[223]
    DIRECTION OUTPUT ;
    USE SIGNAL ;
    PORT
      LAYER M4 ;
        RECT  21.516 5.184 21.6 5.208 ;
    END
  END b[223]
  PIN b[224]
    DIRECTION OUTPUT ;
    USE SIGNAL ;
    PORT
      LAYER M4 ;
        RECT  21.516 9.936 21.6 9.96 ;
    END
  END b[224]
  PIN b[225]
    DIRECTION OUTPUT ;
    USE SIGNAL ;
    PORT
      LAYER M4 ;
        RECT  21.516 10.08 21.6 10.104 ;
    END
  END b[225]
  PIN b[226]
    DIRECTION OUTPUT ;
    USE SIGNAL ;
    PORT
      LAYER M4 ;
        RECT  21.516 10.224 21.6 10.248 ;
    END
  END b[226]
  PIN b[227]
    DIRECTION OUTPUT ;
    USE SIGNAL ;
    PORT
      LAYER M4 ;
        RECT  21.516 10.368 21.6 10.392 ;
    END
  END b[227]
  PIN b[228]
    DIRECTION OUTPUT ;
    USE SIGNAL ;
    PORT
      LAYER M4 ;
        RECT  21.516 10.512 21.6 10.536 ;
    END
  END b[228]
  PIN b[229]
    DIRECTION OUTPUT ;
    USE SIGNAL ;
    PORT
      LAYER M4 ;
        RECT  21.516 10.656 21.6 10.68 ;
    END
  END b[229]
  PIN b[22]
    DIRECTION OUTPUT ;
    USE SIGNAL ;
    PORT
      LAYER M4 ;
        RECT  21.516 32.688 21.6 32.712 ;
    END
  END b[22]
  PIN b[230]
    DIRECTION OUTPUT ;
    USE SIGNAL ;
    PORT
      LAYER M4 ;
        RECT  21.516 10.8 21.6 10.824 ;
    END
  END b[230]
  PIN b[231]
    DIRECTION OUTPUT ;
    USE SIGNAL ;
    PORT
      LAYER M4 ;
        RECT  21.516 10.944 21.6 10.968 ;
    END
  END b[231]
  PIN b[232]
    DIRECTION OUTPUT ;
    USE SIGNAL ;
    PORT
      LAYER M4 ;
        RECT  21.516 11.088 21.6 11.112 ;
    END
  END b[232]
  PIN b[233]
    DIRECTION OUTPUT ;
    USE SIGNAL ;
    PORT
      LAYER M4 ;
        RECT  21.516 11.232 21.6 11.256 ;
    END
  END b[233]
  PIN b[234]
    DIRECTION OUTPUT ;
    USE SIGNAL ;
    PORT
      LAYER M4 ;
        RECT  21.516 11.376 21.6 11.4 ;
    END
  END b[234]
  PIN b[235]
    DIRECTION OUTPUT ;
    USE SIGNAL ;
    PORT
      LAYER M4 ;
        RECT  21.516 11.52 21.6 11.544 ;
    END
  END b[235]
  PIN b[236]
    DIRECTION OUTPUT ;
    USE SIGNAL ;
    PORT
      LAYER M4 ;
        RECT  21.516 11.664 21.6 11.688 ;
    END
  END b[236]
  PIN b[237]
    DIRECTION OUTPUT ;
    USE SIGNAL ;
    PORT
      LAYER M4 ;
        RECT  21.516 11.808 21.6 11.832 ;
    END
  END b[237]
  PIN b[238]
    DIRECTION OUTPUT ;
    USE SIGNAL ;
    PORT
      LAYER M4 ;
        RECT  21.516 11.952 21.6 11.976 ;
    END
  END b[238]
  PIN b[239]
    DIRECTION OUTPUT ;
    USE SIGNAL ;
    PORT
      LAYER M4 ;
        RECT  21.516 12.096 21.6 12.12 ;
    END
  END b[239]
  PIN b[23]
    DIRECTION OUTPUT ;
    USE SIGNAL ;
    PORT
      LAYER M4 ;
        RECT  21.516 32.832 21.6 32.856 ;
    END
  END b[23]
  PIN b[240]
    DIRECTION OUTPUT ;
    USE SIGNAL ;
    PORT
      LAYER M4 ;
        RECT  21.516 12.24 21.6 12.264 ;
    END
  END b[240]
  PIN b[241]
    DIRECTION OUTPUT ;
    USE SIGNAL ;
    PORT
      LAYER M4 ;
        RECT  21.516 12.384 21.6 12.408 ;
    END
  END b[241]
  PIN b[242]
    DIRECTION OUTPUT ;
    USE SIGNAL ;
    PORT
      LAYER M4 ;
        RECT  21.516 12.528 21.6 12.552 ;
    END
  END b[242]
  PIN b[243]
    DIRECTION OUTPUT ;
    USE SIGNAL ;
    PORT
      LAYER M4 ;
        RECT  21.516 12.672 21.6 12.696 ;
    END
  END b[243]
  PIN b[244]
    DIRECTION OUTPUT ;
    USE SIGNAL ;
    PORT
      LAYER M4 ;
        RECT  21.516 12.816 21.6 12.84 ;
    END
  END b[244]
  PIN b[245]
    DIRECTION OUTPUT ;
    USE SIGNAL ;
    PORT
      LAYER M4 ;
        RECT  21.516 12.96 21.6 12.984 ;
    END
  END b[245]
  PIN b[246]
    DIRECTION OUTPUT ;
    USE SIGNAL ;
    PORT
      LAYER M4 ;
        RECT  21.516 13.104 21.6 13.128 ;
    END
  END b[246]
  PIN b[247]
    DIRECTION OUTPUT ;
    USE SIGNAL ;
    PORT
      LAYER M4 ;
        RECT  21.516 13.248 21.6 13.272 ;
    END
  END b[247]
  PIN b[248]
    DIRECTION OUTPUT ;
    USE SIGNAL ;
    PORT
      LAYER M4 ;
        RECT  21.516 13.392 21.6 13.416 ;
    END
  END b[248]
  PIN b[249]
    DIRECTION OUTPUT ;
    USE SIGNAL ;
    PORT
      LAYER M4 ;
        RECT  21.516 13.536 21.6 13.56 ;
    END
  END b[249]
  PIN b[24]
    DIRECTION OUTPUT ;
    USE SIGNAL ;
    PORT
      LAYER M4 ;
        RECT  21.516 32.976 21.6 33 ;
    END
  END b[24]
  PIN b[250]
    DIRECTION OUTPUT ;
    USE SIGNAL ;
    PORT
      LAYER M4 ;
        RECT  21.516 13.68 21.6 13.704 ;
    END
  END b[250]
  PIN b[251]
    DIRECTION OUTPUT ;
    USE SIGNAL ;
    PORT
      LAYER M4 ;
        RECT  21.516 13.824 21.6 13.848 ;
    END
  END b[251]
  PIN b[252]
    DIRECTION OUTPUT ;
    USE SIGNAL ;
    PORT
      LAYER M4 ;
        RECT  21.516 13.968 21.6 13.992 ;
    END
  END b[252]
  PIN b[253]
    DIRECTION OUTPUT ;
    USE SIGNAL ;
    PORT
      LAYER M4 ;
        RECT  21.516 14.112 21.6 14.136 ;
    END
  END b[253]
  PIN b[254]
    DIRECTION OUTPUT ;
    USE SIGNAL ;
    PORT
      LAYER M4 ;
        RECT  21.516 14.256 21.6 14.28 ;
    END
  END b[254]
  PIN b[255]
    DIRECTION OUTPUT ;
    USE SIGNAL ;
    PORT
      LAYER M4 ;
        RECT  21.516 14.4 21.6 14.424 ;
    END
  END b[255]
  PIN b[256]
    DIRECTION OUTPUT ;
    USE SIGNAL ;
    PORT
      LAYER M4 ;
        RECT  21.516 19.152 21.6 19.176 ;
    END
  END b[256]
  PIN b[257]
    DIRECTION OUTPUT ;
    USE SIGNAL ;
    PORT
      LAYER M4 ;
        RECT  21.516 19.296 21.6 19.32 ;
    END
  END b[257]
  PIN b[258]
    DIRECTION OUTPUT ;
    USE SIGNAL ;
    PORT
      LAYER M4 ;
        RECT  21.516 19.44 21.6 19.464 ;
    END
  END b[258]
  PIN b[259]
    DIRECTION OUTPUT ;
    USE SIGNAL ;
    PORT
      LAYER M4 ;
        RECT  21.516 19.584 21.6 19.608 ;
    END
  END b[259]
  PIN b[25]
    DIRECTION OUTPUT ;
    USE SIGNAL ;
    PORT
      LAYER M4 ;
        RECT  21.516 33.12 21.6 33.144 ;
    END
  END b[25]
  PIN b[260]
    DIRECTION OUTPUT ;
    USE SIGNAL ;
    PORT
      LAYER M4 ;
        RECT  21.516 19.728 21.6 19.752 ;
    END
  END b[260]
  PIN b[261]
    DIRECTION OUTPUT ;
    USE SIGNAL ;
    PORT
      LAYER M4 ;
        RECT  21.516 19.872 21.6 19.896 ;
    END
  END b[261]
  PIN b[262]
    DIRECTION OUTPUT ;
    USE SIGNAL ;
    PORT
      LAYER M4 ;
        RECT  21.516 20.016 21.6 20.04 ;
    END
  END b[262]
  PIN b[263]
    DIRECTION OUTPUT ;
    USE SIGNAL ;
    PORT
      LAYER M4 ;
        RECT  21.516 20.16 21.6 20.184 ;
    END
  END b[263]
  PIN b[264]
    DIRECTION OUTPUT ;
    USE SIGNAL ;
    PORT
      LAYER M4 ;
        RECT  21.516 20.304 21.6 20.328 ;
    END
  END b[264]
  PIN b[265]
    DIRECTION OUTPUT ;
    USE SIGNAL ;
    PORT
      LAYER M4 ;
        RECT  21.516 20.448 21.6 20.472 ;
    END
  END b[265]
  PIN b[266]
    DIRECTION OUTPUT ;
    USE SIGNAL ;
    PORT
      LAYER M4 ;
        RECT  21.516 20.592 21.6 20.616 ;
    END
  END b[266]
  PIN b[267]
    DIRECTION OUTPUT ;
    USE SIGNAL ;
    PORT
      LAYER M4 ;
        RECT  21.516 20.736 21.6 20.76 ;
    END
  END b[267]
  PIN b[268]
    DIRECTION OUTPUT ;
    USE SIGNAL ;
    PORT
      LAYER M4 ;
        RECT  21.516 20.88 21.6 20.904 ;
    END
  END b[268]
  PIN b[269]
    DIRECTION OUTPUT ;
    USE SIGNAL ;
    PORT
      LAYER M4 ;
        RECT  21.516 21.024 21.6 21.048 ;
    END
  END b[269]
  PIN b[26]
    DIRECTION OUTPUT ;
    USE SIGNAL ;
    PORT
      LAYER M4 ;
        RECT  21.516 33.264 21.6 33.288 ;
    END
  END b[26]
  PIN b[270]
    DIRECTION OUTPUT ;
    USE SIGNAL ;
    PORT
      LAYER M4 ;
        RECT  21.516 21.168 21.6 21.192 ;
    END
  END b[270]
  PIN b[271]
    DIRECTION OUTPUT ;
    USE SIGNAL ;
    PORT
      LAYER M4 ;
        RECT  21.516 21.312 21.6 21.336 ;
    END
  END b[271]
  PIN b[272]
    DIRECTION OUTPUT ;
    USE SIGNAL ;
    PORT
      LAYER M4 ;
        RECT  21.516 21.456 21.6 21.48 ;
    END
  END b[272]
  PIN b[273]
    DIRECTION OUTPUT ;
    USE SIGNAL ;
    PORT
      LAYER M4 ;
        RECT  21.516 21.6 21.6 21.624 ;
    END
  END b[273]
  PIN b[274]
    DIRECTION OUTPUT ;
    USE SIGNAL ;
    PORT
      LAYER M4 ;
        RECT  21.516 21.744 21.6 21.768 ;
    END
  END b[274]
  PIN b[275]
    DIRECTION OUTPUT ;
    USE SIGNAL ;
    PORT
      LAYER M4 ;
        RECT  21.516 21.888 21.6 21.912 ;
    END
  END b[275]
  PIN b[276]
    DIRECTION OUTPUT ;
    USE SIGNAL ;
    PORT
      LAYER M4 ;
        RECT  21.516 22.032 21.6 22.056 ;
    END
  END b[276]
  PIN b[277]
    DIRECTION OUTPUT ;
    USE SIGNAL ;
    PORT
      LAYER M4 ;
        RECT  21.516 22.176 21.6 22.2 ;
    END
  END b[277]
  PIN b[278]
    DIRECTION OUTPUT ;
    USE SIGNAL ;
    PORT
      LAYER M4 ;
        RECT  21.516 22.32 21.6 22.344 ;
    END
  END b[278]
  PIN b[279]
    DIRECTION OUTPUT ;
    USE SIGNAL ;
    PORT
      LAYER M4 ;
        RECT  21.516 22.464 21.6 22.488 ;
    END
  END b[279]
  PIN b[27]
    DIRECTION OUTPUT ;
    USE SIGNAL ;
    PORT
      LAYER M4 ;
        RECT  21.516 33.408 21.6 33.432 ;
    END
  END b[27]
  PIN b[280]
    DIRECTION OUTPUT ;
    USE SIGNAL ;
    PORT
      LAYER M4 ;
        RECT  21.516 22.608 21.6 22.632 ;
    END
  END b[280]
  PIN b[281]
    DIRECTION OUTPUT ;
    USE SIGNAL ;
    PORT
      LAYER M4 ;
        RECT  21.516 22.752 21.6 22.776 ;
    END
  END b[281]
  PIN b[282]
    DIRECTION OUTPUT ;
    USE SIGNAL ;
    PORT
      LAYER M4 ;
        RECT  21.516 22.896 21.6 22.92 ;
    END
  END b[282]
  PIN b[283]
    DIRECTION OUTPUT ;
    USE SIGNAL ;
    PORT
      LAYER M4 ;
        RECT  21.516 23.04 21.6 23.064 ;
    END
  END b[283]
  PIN b[284]
    DIRECTION OUTPUT ;
    USE SIGNAL ;
    PORT
      LAYER M4 ;
        RECT  21.516 23.184 21.6 23.208 ;
    END
  END b[284]
  PIN b[285]
    DIRECTION OUTPUT ;
    USE SIGNAL ;
    PORT
      LAYER M4 ;
        RECT  21.516 23.328 21.6 23.352 ;
    END
  END b[285]
  PIN b[286]
    DIRECTION OUTPUT ;
    USE SIGNAL ;
    PORT
      LAYER M4 ;
        RECT  21.516 23.472 21.6 23.496 ;
    END
  END b[286]
  PIN b[287]
    DIRECTION OUTPUT ;
    USE SIGNAL ;
    PORT
      LAYER M4 ;
        RECT  21.516 23.616 21.6 23.64 ;
    END
  END b[287]
  PIN b[288]
    DIRECTION OUTPUT ;
    USE SIGNAL ;
    PORT
      LAYER M4 ;
        RECT  21.516 14.544 21.6 14.568 ;
    END
  END b[288]
  PIN b[289]
    DIRECTION OUTPUT ;
    USE SIGNAL ;
    PORT
      LAYER M4 ;
        RECT  21.516 14.688 21.6 14.712 ;
    END
  END b[289]
  PIN b[28]
    DIRECTION OUTPUT ;
    USE SIGNAL ;
    PORT
      LAYER M4 ;
        RECT  21.516 33.552 21.6 33.576 ;
    END
  END b[28]
  PIN b[290]
    DIRECTION OUTPUT ;
    USE SIGNAL ;
    PORT
      LAYER M4 ;
        RECT  21.516 14.832 21.6 14.856 ;
    END
  END b[290]
  PIN b[291]
    DIRECTION OUTPUT ;
    USE SIGNAL ;
    PORT
      LAYER M4 ;
        RECT  21.516 14.976 21.6 15 ;
    END
  END b[291]
  PIN b[292]
    DIRECTION OUTPUT ;
    USE SIGNAL ;
    PORT
      LAYER M4 ;
        RECT  21.516 15.12 21.6 15.144 ;
    END
  END b[292]
  PIN b[293]
    DIRECTION OUTPUT ;
    USE SIGNAL ;
    PORT
      LAYER M4 ;
        RECT  21.516 15.264 21.6 15.288 ;
    END
  END b[293]
  PIN b[294]
    DIRECTION OUTPUT ;
    USE SIGNAL ;
    PORT
      LAYER M4 ;
        RECT  21.516 15.408 21.6 15.432 ;
    END
  END b[294]
  PIN b[295]
    DIRECTION OUTPUT ;
    USE SIGNAL ;
    PORT
      LAYER M4 ;
        RECT  21.516 15.552 21.6 15.576 ;
    END
  END b[295]
  PIN b[296]
    DIRECTION OUTPUT ;
    USE SIGNAL ;
    PORT
      LAYER M4 ;
        RECT  21.516 15.696 21.6 15.72 ;
    END
  END b[296]
  PIN b[297]
    DIRECTION OUTPUT ;
    USE SIGNAL ;
    PORT
      LAYER M4 ;
        RECT  21.516 15.84 21.6 15.864 ;
    END
  END b[297]
  PIN b[298]
    DIRECTION OUTPUT ;
    USE SIGNAL ;
    PORT
      LAYER M4 ;
        RECT  21.516 15.984 21.6 16.008 ;
    END
  END b[298]
  PIN b[299]
    DIRECTION OUTPUT ;
    USE SIGNAL ;
    PORT
      LAYER M4 ;
        RECT  21.516 16.128 21.6 16.152 ;
    END
  END b[299]
  PIN b[29]
    DIRECTION OUTPUT ;
    USE SIGNAL ;
    PORT
      LAYER M4 ;
        RECT  21.516 33.696 21.6 33.72 ;
    END
  END b[29]
  PIN b[2]
    DIRECTION OUTPUT ;
    USE SIGNAL ;
    PORT
      LAYER M4 ;
        RECT  21.516 29.808 21.6 29.832 ;
    END
  END b[2]
  PIN b[300]
    DIRECTION OUTPUT ;
    USE SIGNAL ;
    PORT
      LAYER M4 ;
        RECT  21.516 16.272 21.6 16.296 ;
    END
  END b[300]
  PIN b[301]
    DIRECTION OUTPUT ;
    USE SIGNAL ;
    PORT
      LAYER M4 ;
        RECT  21.516 16.416 21.6 16.44 ;
    END
  END b[301]
  PIN b[302]
    DIRECTION OUTPUT ;
    USE SIGNAL ;
    PORT
      LAYER M4 ;
        RECT  21.516 16.56 21.6 16.584 ;
    END
  END b[302]
  PIN b[303]
    DIRECTION OUTPUT ;
    USE SIGNAL ;
    PORT
      LAYER M4 ;
        RECT  21.516 16.704 21.6 16.728 ;
    END
  END b[303]
  PIN b[304]
    DIRECTION OUTPUT ;
    USE SIGNAL ;
    PORT
      LAYER M4 ;
        RECT  21.516 16.848 21.6 16.872 ;
    END
  END b[304]
  PIN b[305]
    DIRECTION OUTPUT ;
    USE SIGNAL ;
    PORT
      LAYER M4 ;
        RECT  21.516 16.992 21.6 17.016 ;
    END
  END b[305]
  PIN b[306]
    DIRECTION OUTPUT ;
    USE SIGNAL ;
    PORT
      LAYER M4 ;
        RECT  21.516 17.136 21.6 17.16 ;
    END
  END b[306]
  PIN b[307]
    DIRECTION OUTPUT ;
    USE SIGNAL ;
    PORT
      LAYER M4 ;
        RECT  21.516 17.28 21.6 17.304 ;
    END
  END b[307]
  PIN b[308]
    DIRECTION OUTPUT ;
    USE SIGNAL ;
    PORT
      LAYER M4 ;
        RECT  21.516 17.424 21.6 17.448 ;
    END
  END b[308]
  PIN b[309]
    DIRECTION OUTPUT ;
    USE SIGNAL ;
    PORT
      LAYER M4 ;
        RECT  21.516 17.568 21.6 17.592 ;
    END
  END b[309]
  PIN b[30]
    DIRECTION OUTPUT ;
    USE SIGNAL ;
    PORT
      LAYER M4 ;
        RECT  21.516 33.84 21.6 33.864 ;
    END
  END b[30]
  PIN b[310]
    DIRECTION OUTPUT ;
    USE SIGNAL ;
    PORT
      LAYER M4 ;
        RECT  21.516 17.712 21.6 17.736 ;
    END
  END b[310]
  PIN b[311]
    DIRECTION OUTPUT ;
    USE SIGNAL ;
    PORT
      LAYER M4 ;
        RECT  21.516 17.856 21.6 17.88 ;
    END
  END b[311]
  PIN b[312]
    DIRECTION OUTPUT ;
    USE SIGNAL ;
    PORT
      LAYER M4 ;
        RECT  21.516 18 21.6 18.024 ;
    END
  END b[312]
  PIN b[313]
    DIRECTION OUTPUT ;
    USE SIGNAL ;
    PORT
      LAYER M4 ;
        RECT  21.516 18.144 21.6 18.168 ;
    END
  END b[313]
  PIN b[314]
    DIRECTION OUTPUT ;
    USE SIGNAL ;
    PORT
      LAYER M4 ;
        RECT  21.516 18.288 21.6 18.312 ;
    END
  END b[314]
  PIN b[315]
    DIRECTION OUTPUT ;
    USE SIGNAL ;
    PORT
      LAYER M4 ;
        RECT  21.516 18.432 21.6 18.456 ;
    END
  END b[315]
  PIN b[316]
    DIRECTION OUTPUT ;
    USE SIGNAL ;
    PORT
      LAYER M4 ;
        RECT  21.516 18.576 21.6 18.6 ;
    END
  END b[316]
  PIN b[317]
    DIRECTION OUTPUT ;
    USE SIGNAL ;
    PORT
      LAYER M4 ;
        RECT  21.516 18.72 21.6 18.744 ;
    END
  END b[317]
  PIN b[318]
    DIRECTION OUTPUT ;
    USE SIGNAL ;
    PORT
      LAYER M4 ;
        RECT  21.516 18.864 21.6 18.888 ;
    END
  END b[318]
  PIN b[319]
    DIRECTION OUTPUT ;
    USE SIGNAL ;
    PORT
      LAYER M4 ;
        RECT  21.516 19.008 21.6 19.032 ;
    END
  END b[319]
  PIN b[31]
    DIRECTION OUTPUT ;
    USE SIGNAL ;
    PORT
      LAYER M4 ;
        RECT  21.516 33.984 21.6 34.008 ;
    END
  END b[31]
  PIN b[320]
    DIRECTION OUTPUT ;
    USE SIGNAL ;
    PORT
      LAYER M4 ;
        RECT  21.516 5.328 21.6 5.352 ;
    END
  END b[320]
  PIN b[321]
    DIRECTION OUTPUT ;
    USE SIGNAL ;
    PORT
      LAYER M4 ;
        RECT  21.516 5.472 21.6 5.496 ;
    END
  END b[321]
  PIN b[322]
    DIRECTION OUTPUT ;
    USE SIGNAL ;
    PORT
      LAYER M4 ;
        RECT  21.516 5.616 21.6 5.64 ;
    END
  END b[322]
  PIN b[323]
    DIRECTION OUTPUT ;
    USE SIGNAL ;
    PORT
      LAYER M4 ;
        RECT  21.516 5.76 21.6 5.784 ;
    END
  END b[323]
  PIN b[324]
    DIRECTION OUTPUT ;
    USE SIGNAL ;
    PORT
      LAYER M4 ;
        RECT  21.516 5.904 21.6 5.928 ;
    END
  END b[324]
  PIN b[325]
    DIRECTION OUTPUT ;
    USE SIGNAL ;
    PORT
      LAYER M4 ;
        RECT  21.516 6.048 21.6 6.072 ;
    END
  END b[325]
  PIN b[326]
    DIRECTION OUTPUT ;
    USE SIGNAL ;
    PORT
      LAYER M4 ;
        RECT  21.516 6.192 21.6 6.216 ;
    END
  END b[326]
  PIN b[327]
    DIRECTION OUTPUT ;
    USE SIGNAL ;
    PORT
      LAYER M4 ;
        RECT  21.516 6.336 21.6 6.36 ;
    END
  END b[327]
  PIN b[328]
    DIRECTION OUTPUT ;
    USE SIGNAL ;
    PORT
      LAYER M4 ;
        RECT  21.516 6.48 21.6 6.504 ;
    END
  END b[328]
  PIN b[329]
    DIRECTION OUTPUT ;
    USE SIGNAL ;
    PORT
      LAYER M4 ;
        RECT  21.516 6.624 21.6 6.648 ;
    END
  END b[329]
  PIN b[32]
    DIRECTION OUTPUT ;
    USE SIGNAL ;
    PORT
      LAYER M4 ;
        RECT  21.516 47.952 21.6 47.976 ;
    END
  END b[32]
  PIN b[330]
    DIRECTION OUTPUT ;
    USE SIGNAL ;
    PORT
      LAYER M4 ;
        RECT  21.516 6.768 21.6 6.792 ;
    END
  END b[330]
  PIN b[331]
    DIRECTION OUTPUT ;
    USE SIGNAL ;
    PORT
      LAYER M4 ;
        RECT  21.516 6.912 21.6 6.936 ;
    END
  END b[331]
  PIN b[332]
    DIRECTION OUTPUT ;
    USE SIGNAL ;
    PORT
      LAYER M4 ;
        RECT  21.516 7.056 21.6 7.08 ;
    END
  END b[332]
  PIN b[333]
    DIRECTION OUTPUT ;
    USE SIGNAL ;
    PORT
      LAYER M4 ;
        RECT  21.516 7.2 21.6 7.224 ;
    END
  END b[333]
  PIN b[334]
    DIRECTION OUTPUT ;
    USE SIGNAL ;
    PORT
      LAYER M4 ;
        RECT  21.516 7.344 21.6 7.368 ;
    END
  END b[334]
  PIN b[335]
    DIRECTION OUTPUT ;
    USE SIGNAL ;
    PORT
      LAYER M4 ;
        RECT  21.516 7.488 21.6 7.512 ;
    END
  END b[335]
  PIN b[336]
    DIRECTION OUTPUT ;
    USE SIGNAL ;
    PORT
      LAYER M4 ;
        RECT  21.516 7.632 21.6 7.656 ;
    END
  END b[336]
  PIN b[337]
    DIRECTION OUTPUT ;
    USE SIGNAL ;
    PORT
      LAYER M4 ;
        RECT  21.516 7.776 21.6 7.8 ;
    END
  END b[337]
  PIN b[338]
    DIRECTION OUTPUT ;
    USE SIGNAL ;
    PORT
      LAYER M4 ;
        RECT  21.516 7.92 21.6 7.944 ;
    END
  END b[338]
  PIN b[339]
    DIRECTION OUTPUT ;
    USE SIGNAL ;
    PORT
      LAYER M4 ;
        RECT  21.516 8.064 21.6 8.088 ;
    END
  END b[339]
  PIN b[33]
    DIRECTION OUTPUT ;
    USE SIGNAL ;
    PORT
      LAYER M4 ;
        RECT  21.516 48.096 21.6 48.12 ;
    END
  END b[33]
  PIN b[340]
    DIRECTION OUTPUT ;
    USE SIGNAL ;
    PORT
      LAYER M4 ;
        RECT  21.516 8.208 21.6 8.232 ;
    END
  END b[340]
  PIN b[341]
    DIRECTION OUTPUT ;
    USE SIGNAL ;
    PORT
      LAYER M4 ;
        RECT  21.516 8.352 21.6 8.376 ;
    END
  END b[341]
  PIN b[342]
    DIRECTION OUTPUT ;
    USE SIGNAL ;
    PORT
      LAYER M4 ;
        RECT  21.516 8.496 21.6 8.52 ;
    END
  END b[342]
  PIN b[343]
    DIRECTION OUTPUT ;
    USE SIGNAL ;
    PORT
      LAYER M4 ;
        RECT  21.516 8.64 21.6 8.664 ;
    END
  END b[343]
  PIN b[344]
    DIRECTION OUTPUT ;
    USE SIGNAL ;
    PORT
      LAYER M4 ;
        RECT  21.516 8.784 21.6 8.808 ;
    END
  END b[344]
  PIN b[345]
    DIRECTION OUTPUT ;
    USE SIGNAL ;
    PORT
      LAYER M4 ;
        RECT  21.516 8.928 21.6 8.952 ;
    END
  END b[345]
  PIN b[346]
    DIRECTION OUTPUT ;
    USE SIGNAL ;
    PORT
      LAYER M4 ;
        RECT  21.516 9.072 21.6 9.096 ;
    END
  END b[346]
  PIN b[347]
    DIRECTION OUTPUT ;
    USE SIGNAL ;
    PORT
      LAYER M4 ;
        RECT  21.516 9.216 21.6 9.24 ;
    END
  END b[347]
  PIN b[348]
    DIRECTION OUTPUT ;
    USE SIGNAL ;
    PORT
      LAYER M4 ;
        RECT  21.516 9.36 21.6 9.384 ;
    END
  END b[348]
  PIN b[349]
    DIRECTION OUTPUT ;
    USE SIGNAL ;
    PORT
      LAYER M4 ;
        RECT  21.516 9.504 21.6 9.528 ;
    END
  END b[349]
  PIN b[34]
    DIRECTION OUTPUT ;
    USE SIGNAL ;
    PORT
      LAYER M4 ;
        RECT  21.516 48.24 21.6 48.264 ;
    END
  END b[34]
  PIN b[350]
    DIRECTION OUTPUT ;
    USE SIGNAL ;
    PORT
      LAYER M4 ;
        RECT  21.516 9.648 21.6 9.672 ;
    END
  END b[350]
  PIN b[351]
    DIRECTION OUTPUT ;
    USE SIGNAL ;
    PORT
      LAYER M4 ;
        RECT  21.516 9.792 21.6 9.816 ;
    END
  END b[351]
  PIN b[352]
    DIRECTION OUTPUT ;
    USE SIGNAL ;
    PORT
      LAYER M4 ;
        RECT  21.516 23.76 21.6 23.784 ;
    END
  END b[352]
  PIN b[353]
    DIRECTION OUTPUT ;
    USE SIGNAL ;
    PORT
      LAYER M4 ;
        RECT  21.516 23.904 21.6 23.928 ;
    END
  END b[353]
  PIN b[354]
    DIRECTION OUTPUT ;
    USE SIGNAL ;
    PORT
      LAYER M4 ;
        RECT  21.516 24.048 21.6 24.072 ;
    END
  END b[354]
  PIN b[355]
    DIRECTION OUTPUT ;
    USE SIGNAL ;
    PORT
      LAYER M4 ;
        RECT  21.516 24.192 21.6 24.216 ;
    END
  END b[355]
  PIN b[356]
    DIRECTION OUTPUT ;
    USE SIGNAL ;
    PORT
      LAYER M4 ;
        RECT  21.516 24.336 21.6 24.36 ;
    END
  END b[356]
  PIN b[357]
    DIRECTION OUTPUT ;
    USE SIGNAL ;
    PORT
      LAYER M4 ;
        RECT  21.516 24.48 21.6 24.504 ;
    END
  END b[357]
  PIN b[358]
    DIRECTION OUTPUT ;
    USE SIGNAL ;
    PORT
      LAYER M4 ;
        RECT  21.516 24.624 21.6 24.648 ;
    END
  END b[358]
  PIN b[359]
    DIRECTION OUTPUT ;
    USE SIGNAL ;
    PORT
      LAYER M4 ;
        RECT  21.516 24.768 21.6 24.792 ;
    END
  END b[359]
  PIN b[35]
    DIRECTION OUTPUT ;
    USE SIGNAL ;
    PORT
      LAYER M4 ;
        RECT  21.516 48.384 21.6 48.408 ;
    END
  END b[35]
  PIN b[360]
    DIRECTION OUTPUT ;
    USE SIGNAL ;
    PORT
      LAYER M4 ;
        RECT  21.516 24.912 21.6 24.936 ;
    END
  END b[360]
  PIN b[361]
    DIRECTION OUTPUT ;
    USE SIGNAL ;
    PORT
      LAYER M4 ;
        RECT  21.516 25.056 21.6 25.08 ;
    END
  END b[361]
  PIN b[362]
    DIRECTION OUTPUT ;
    USE SIGNAL ;
    PORT
      LAYER M4 ;
        RECT  21.516 25.2 21.6 25.224 ;
    END
  END b[362]
  PIN b[363]
    DIRECTION OUTPUT ;
    USE SIGNAL ;
    PORT
      LAYER M4 ;
        RECT  21.516 25.344 21.6 25.368 ;
    END
  END b[363]
  PIN b[364]
    DIRECTION OUTPUT ;
    USE SIGNAL ;
    PORT
      LAYER M4 ;
        RECT  21.516 25.488 21.6 25.512 ;
    END
  END b[364]
  PIN b[365]
    DIRECTION OUTPUT ;
    USE SIGNAL ;
    PORT
      LAYER M4 ;
        RECT  21.516 25.632 21.6 25.656 ;
    END
  END b[365]
  PIN b[366]
    DIRECTION OUTPUT ;
    USE SIGNAL ;
    PORT
      LAYER M4 ;
        RECT  21.516 25.776 21.6 25.8 ;
    END
  END b[366]
  PIN b[367]
    DIRECTION OUTPUT ;
    USE SIGNAL ;
    PORT
      LAYER M4 ;
        RECT  21.516 25.92 21.6 25.944 ;
    END
  END b[367]
  PIN b[368]
    DIRECTION OUTPUT ;
    USE SIGNAL ;
    PORT
      LAYER M4 ;
        RECT  21.516 26.064 21.6 26.088 ;
    END
  END b[368]
  PIN b[369]
    DIRECTION OUTPUT ;
    USE SIGNAL ;
    PORT
      LAYER M4 ;
        RECT  21.516 26.208 21.6 26.232 ;
    END
  END b[369]
  PIN b[36]
    DIRECTION OUTPUT ;
    USE SIGNAL ;
    PORT
      LAYER M4 ;
        RECT  21.516 48.528 21.6 48.552 ;
    END
  END b[36]
  PIN b[370]
    DIRECTION OUTPUT ;
    USE SIGNAL ;
    PORT
      LAYER M4 ;
        RECT  21.516 26.352 21.6 26.376 ;
    END
  END b[370]
  PIN b[371]
    DIRECTION OUTPUT ;
    USE SIGNAL ;
    PORT
      LAYER M4 ;
        RECT  21.516 26.496 21.6 26.52 ;
    END
  END b[371]
  PIN b[372]
    DIRECTION OUTPUT ;
    USE SIGNAL ;
    PORT
      LAYER M4 ;
        RECT  21.516 26.64 21.6 26.664 ;
    END
  END b[372]
  PIN b[373]
    DIRECTION OUTPUT ;
    USE SIGNAL ;
    PORT
      LAYER M4 ;
        RECT  21.516 26.784 21.6 26.808 ;
    END
  END b[373]
  PIN b[374]
    DIRECTION OUTPUT ;
    USE SIGNAL ;
    PORT
      LAYER M4 ;
        RECT  21.516 26.928 21.6 26.952 ;
    END
  END b[374]
  PIN b[375]
    DIRECTION OUTPUT ;
    USE SIGNAL ;
    PORT
      LAYER M4 ;
        RECT  21.516 27.072 21.6 27.096 ;
    END
  END b[375]
  PIN b[376]
    DIRECTION OUTPUT ;
    USE SIGNAL ;
    PORT
      LAYER M4 ;
        RECT  21.516 27.216 21.6 27.24 ;
    END
  END b[376]
  PIN b[377]
    DIRECTION OUTPUT ;
    USE SIGNAL ;
    PORT
      LAYER M4 ;
        RECT  21.516 27.36 21.6 27.384 ;
    END
  END b[377]
  PIN b[378]
    DIRECTION OUTPUT ;
    USE SIGNAL ;
    PORT
      LAYER M4 ;
        RECT  21.516 27.504 21.6 27.528 ;
    END
  END b[378]
  PIN b[379]
    DIRECTION OUTPUT ;
    USE SIGNAL ;
    PORT
      LAYER M4 ;
        RECT  21.516 27.648 21.6 27.672 ;
    END
  END b[379]
  PIN b[37]
    DIRECTION OUTPUT ;
    USE SIGNAL ;
    PORT
      LAYER M4 ;
        RECT  21.516 48.672 21.6 48.696 ;
    END
  END b[37]
  PIN b[380]
    DIRECTION OUTPUT ;
    USE SIGNAL ;
    PORT
      LAYER M4 ;
        RECT  21.516 27.792 21.6 27.816 ;
    END
  END b[380]
  PIN b[381]
    DIRECTION OUTPUT ;
    USE SIGNAL ;
    PORT
      LAYER M4 ;
        RECT  21.516 27.936 21.6 27.96 ;
    END
  END b[381]
  PIN b[382]
    DIRECTION OUTPUT ;
    USE SIGNAL ;
    PORT
      LAYER M4 ;
        RECT  21.516 28.08 21.6 28.104 ;
    END
  END b[382]
  PIN b[383]
    DIRECTION OUTPUT ;
    USE SIGNAL ;
    PORT
      LAYER M4 ;
        RECT  21.516 28.224 21.6 28.248 ;
    END
  END b[383]
  PIN b[384]
    DIRECTION OUTPUT ;
    USE SIGNAL ;
    PORT
      LAYER M4 ;
        RECT  21.516 72.144 21.6 72.168 ;
    END
  END b[384]
  PIN b[385]
    DIRECTION OUTPUT ;
    USE SIGNAL ;
    PORT
      LAYER M4 ;
        RECT  21.516 72.288 21.6 72.312 ;
    END
  END b[385]
  PIN b[386]
    DIRECTION OUTPUT ;
    USE SIGNAL ;
    PORT
      LAYER M4 ;
        RECT  21.516 72.432 21.6 72.456 ;
    END
  END b[386]
  PIN b[387]
    DIRECTION OUTPUT ;
    USE SIGNAL ;
    PORT
      LAYER M4 ;
        RECT  21.516 72.576 21.6 72.6 ;
    END
  END b[387]
  PIN b[388]
    DIRECTION OUTPUT ;
    USE SIGNAL ;
    PORT
      LAYER M4 ;
        RECT  21.516 72.72 21.6 72.744 ;
    END
  END b[388]
  PIN b[389]
    DIRECTION OUTPUT ;
    USE SIGNAL ;
    PORT
      LAYER M4 ;
        RECT  21.516 72.864 21.6 72.888 ;
    END
  END b[389]
  PIN b[38]
    DIRECTION OUTPUT ;
    USE SIGNAL ;
    PORT
      LAYER M4 ;
        RECT  21.516 48.816 21.6 48.84 ;
    END
  END b[38]
  PIN b[390]
    DIRECTION OUTPUT ;
    USE SIGNAL ;
    PORT
      LAYER M4 ;
        RECT  21.516 73.008 21.6 73.032 ;
    END
  END b[390]
  PIN b[391]
    DIRECTION OUTPUT ;
    USE SIGNAL ;
    PORT
      LAYER M4 ;
        RECT  21.516 73.152 21.6 73.176 ;
    END
  END b[391]
  PIN b[392]
    DIRECTION OUTPUT ;
    USE SIGNAL ;
    PORT
      LAYER M4 ;
        RECT  21.516 73.296 21.6 73.32 ;
    END
  END b[392]
  PIN b[393]
    DIRECTION OUTPUT ;
    USE SIGNAL ;
    PORT
      LAYER M4 ;
        RECT  21.516 73.44 21.6 73.464 ;
    END
  END b[393]
  PIN b[394]
    DIRECTION OUTPUT ;
    USE SIGNAL ;
    PORT
      LAYER M4 ;
        RECT  21.516 73.584 21.6 73.608 ;
    END
  END b[394]
  PIN b[395]
    DIRECTION OUTPUT ;
    USE SIGNAL ;
    PORT
      LAYER M4 ;
        RECT  21.516 73.728 21.6 73.752 ;
    END
  END b[395]
  PIN b[396]
    DIRECTION OUTPUT ;
    USE SIGNAL ;
    PORT
      LAYER M4 ;
        RECT  21.516 73.872 21.6 73.896 ;
    END
  END b[396]
  PIN b[397]
    DIRECTION OUTPUT ;
    USE SIGNAL ;
    PORT
      LAYER M4 ;
        RECT  21.516 74.016 21.6 74.04 ;
    END
  END b[397]
  PIN b[398]
    DIRECTION OUTPUT ;
    USE SIGNAL ;
    PORT
      LAYER M4 ;
        RECT  21.516 74.16 21.6 74.184 ;
    END
  END b[398]
  PIN b[399]
    DIRECTION OUTPUT ;
    USE SIGNAL ;
    PORT
      LAYER M4 ;
        RECT  21.516 74.304 21.6 74.328 ;
    END
  END b[399]
  PIN b[39]
    DIRECTION OUTPUT ;
    USE SIGNAL ;
    PORT
      LAYER M4 ;
        RECT  21.516 48.96 21.6 48.984 ;
    END
  END b[39]
  PIN b[3]
    DIRECTION OUTPUT ;
    USE SIGNAL ;
    PORT
      LAYER M4 ;
        RECT  21.516 29.952 21.6 29.976 ;
    END
  END b[3]
  PIN b[400]
    DIRECTION OUTPUT ;
    USE SIGNAL ;
    PORT
      LAYER M4 ;
        RECT  21.516 74.448 21.6 74.472 ;
    END
  END b[400]
  PIN b[401]
    DIRECTION OUTPUT ;
    USE SIGNAL ;
    PORT
      LAYER M4 ;
        RECT  21.516 74.592 21.6 74.616 ;
    END
  END b[401]
  PIN b[402]
    DIRECTION OUTPUT ;
    USE SIGNAL ;
    PORT
      LAYER M4 ;
        RECT  21.516 74.736 21.6 74.76 ;
    END
  END b[402]
  PIN b[403]
    DIRECTION OUTPUT ;
    USE SIGNAL ;
    PORT
      LAYER M4 ;
        RECT  21.516 74.88 21.6 74.904 ;
    END
  END b[403]
  PIN b[404]
    DIRECTION OUTPUT ;
    USE SIGNAL ;
    PORT
      LAYER M4 ;
        RECT  21.516 75.024 21.6 75.048 ;
    END
  END b[404]
  PIN b[405]
    DIRECTION OUTPUT ;
    USE SIGNAL ;
    PORT
      LAYER M4 ;
        RECT  21.516 75.168 21.6 75.192 ;
    END
  END b[405]
  PIN b[406]
    DIRECTION OUTPUT ;
    USE SIGNAL ;
    PORT
      LAYER M4 ;
        RECT  21.516 75.312 21.6 75.336 ;
    END
  END b[406]
  PIN b[407]
    DIRECTION OUTPUT ;
    USE SIGNAL ;
    PORT
      LAYER M4 ;
        RECT  21.516 75.456 21.6 75.48 ;
    END
  END b[407]
  PIN b[408]
    DIRECTION OUTPUT ;
    USE SIGNAL ;
    PORT
      LAYER M4 ;
        RECT  21.516 75.6 21.6 75.624 ;
    END
  END b[408]
  PIN b[409]
    DIRECTION OUTPUT ;
    USE SIGNAL ;
    PORT
      LAYER M4 ;
        RECT  21.516 75.744 21.6 75.768 ;
    END
  END b[409]
  PIN b[40]
    DIRECTION OUTPUT ;
    USE SIGNAL ;
    PORT
      LAYER M4 ;
        RECT  21.516 49.104 21.6 49.128 ;
    END
  END b[40]
  PIN b[410]
    DIRECTION OUTPUT ;
    USE SIGNAL ;
    PORT
      LAYER M4 ;
        RECT  21.516 75.888 21.6 75.912 ;
    END
  END b[410]
  PIN b[411]
    DIRECTION OUTPUT ;
    USE SIGNAL ;
    PORT
      LAYER M4 ;
        RECT  21.516 76.032 21.6 76.056 ;
    END
  END b[411]
  PIN b[412]
    DIRECTION OUTPUT ;
    USE SIGNAL ;
    PORT
      LAYER M4 ;
        RECT  21.516 76.176 21.6 76.2 ;
    END
  END b[412]
  PIN b[413]
    DIRECTION OUTPUT ;
    USE SIGNAL ;
    PORT
      LAYER M4 ;
        RECT  21.516 76.32 21.6 76.344 ;
    END
  END b[413]
  PIN b[414]
    DIRECTION OUTPUT ;
    USE SIGNAL ;
    PORT
      LAYER M4 ;
        RECT  21.516 76.464 21.6 76.488 ;
    END
  END b[414]
  PIN b[415]
    DIRECTION OUTPUT ;
    USE SIGNAL ;
    PORT
      LAYER M4 ;
        RECT  21.516 76.608 21.6 76.632 ;
    END
  END b[415]
  PIN b[416]
    DIRECTION OUTPUT ;
    USE SIGNAL ;
    PORT
      LAYER M4 ;
        RECT  21.516 67.536 21.6 67.56 ;
    END
  END b[416]
  PIN b[417]
    DIRECTION OUTPUT ;
    USE SIGNAL ;
    PORT
      LAYER M4 ;
        RECT  21.516 67.68 21.6 67.704 ;
    END
  END b[417]
  PIN b[418]
    DIRECTION OUTPUT ;
    USE SIGNAL ;
    PORT
      LAYER M4 ;
        RECT  21.516 67.824 21.6 67.848 ;
    END
  END b[418]
  PIN b[419]
    DIRECTION OUTPUT ;
    USE SIGNAL ;
    PORT
      LAYER M4 ;
        RECT  21.516 67.968 21.6 67.992 ;
    END
  END b[419]
  PIN b[41]
    DIRECTION OUTPUT ;
    USE SIGNAL ;
    PORT
      LAYER M4 ;
        RECT  21.516 49.248 21.6 49.272 ;
    END
  END b[41]
  PIN b[420]
    DIRECTION OUTPUT ;
    USE SIGNAL ;
    PORT
      LAYER M4 ;
        RECT  21.516 68.112 21.6 68.136 ;
    END
  END b[420]
  PIN b[421]
    DIRECTION OUTPUT ;
    USE SIGNAL ;
    PORT
      LAYER M4 ;
        RECT  21.516 68.256 21.6 68.28 ;
    END
  END b[421]
  PIN b[422]
    DIRECTION OUTPUT ;
    USE SIGNAL ;
    PORT
      LAYER M4 ;
        RECT  21.516 68.4 21.6 68.424 ;
    END
  END b[422]
  PIN b[423]
    DIRECTION OUTPUT ;
    USE SIGNAL ;
    PORT
      LAYER M4 ;
        RECT  21.516 68.544 21.6 68.568 ;
    END
  END b[423]
  PIN b[424]
    DIRECTION OUTPUT ;
    USE SIGNAL ;
    PORT
      LAYER M4 ;
        RECT  21.516 68.688 21.6 68.712 ;
    END
  END b[424]
  PIN b[425]
    DIRECTION OUTPUT ;
    USE SIGNAL ;
    PORT
      LAYER M4 ;
        RECT  21.516 68.832 21.6 68.856 ;
    END
  END b[425]
  PIN b[426]
    DIRECTION OUTPUT ;
    USE SIGNAL ;
    PORT
      LAYER M4 ;
        RECT  21.516 68.976 21.6 69 ;
    END
  END b[426]
  PIN b[427]
    DIRECTION OUTPUT ;
    USE SIGNAL ;
    PORT
      LAYER M4 ;
        RECT  21.516 69.12 21.6 69.144 ;
    END
  END b[427]
  PIN b[428]
    DIRECTION OUTPUT ;
    USE SIGNAL ;
    PORT
      LAYER M4 ;
        RECT  21.516 69.264 21.6 69.288 ;
    END
  END b[428]
  PIN b[429]
    DIRECTION OUTPUT ;
    USE SIGNAL ;
    PORT
      LAYER M4 ;
        RECT  21.516 69.408 21.6 69.432 ;
    END
  END b[429]
  PIN b[42]
    DIRECTION OUTPUT ;
    USE SIGNAL ;
    PORT
      LAYER M4 ;
        RECT  21.516 49.392 21.6 49.416 ;
    END
  END b[42]
  PIN b[430]
    DIRECTION OUTPUT ;
    USE SIGNAL ;
    PORT
      LAYER M4 ;
        RECT  21.516 69.552 21.6 69.576 ;
    END
  END b[430]
  PIN b[431]
    DIRECTION OUTPUT ;
    USE SIGNAL ;
    PORT
      LAYER M4 ;
        RECT  21.516 69.696 21.6 69.72 ;
    END
  END b[431]
  PIN b[432]
    DIRECTION OUTPUT ;
    USE SIGNAL ;
    PORT
      LAYER M4 ;
        RECT  21.516 69.84 21.6 69.864 ;
    END
  END b[432]
  PIN b[433]
    DIRECTION OUTPUT ;
    USE SIGNAL ;
    PORT
      LAYER M4 ;
        RECT  21.516 69.984 21.6 70.008 ;
    END
  END b[433]
  PIN b[434]
    DIRECTION OUTPUT ;
    USE SIGNAL ;
    PORT
      LAYER M4 ;
        RECT  21.516 70.128 21.6 70.152 ;
    END
  END b[434]
  PIN b[435]
    DIRECTION OUTPUT ;
    USE SIGNAL ;
    PORT
      LAYER M4 ;
        RECT  21.516 70.272 21.6 70.296 ;
    END
  END b[435]
  PIN b[436]
    DIRECTION OUTPUT ;
    USE SIGNAL ;
    PORT
      LAYER M4 ;
        RECT  21.516 70.416 21.6 70.44 ;
    END
  END b[436]
  PIN b[437]
    DIRECTION OUTPUT ;
    USE SIGNAL ;
    PORT
      LAYER M4 ;
        RECT  21.516 70.56 21.6 70.584 ;
    END
  END b[437]
  PIN b[438]
    DIRECTION OUTPUT ;
    USE SIGNAL ;
    PORT
      LAYER M4 ;
        RECT  21.516 70.704 21.6 70.728 ;
    END
  END b[438]
  PIN b[439]
    DIRECTION OUTPUT ;
    USE SIGNAL ;
    PORT
      LAYER M4 ;
        RECT  21.516 70.848 21.6 70.872 ;
    END
  END b[439]
  PIN b[43]
    DIRECTION OUTPUT ;
    USE SIGNAL ;
    PORT
      LAYER M4 ;
        RECT  21.516 49.536 21.6 49.56 ;
    END
  END b[43]
  PIN b[440]
    DIRECTION OUTPUT ;
    USE SIGNAL ;
    PORT
      LAYER M4 ;
        RECT  21.516 70.992 21.6 71.016 ;
    END
  END b[440]
  PIN b[441]
    DIRECTION OUTPUT ;
    USE SIGNAL ;
    PORT
      LAYER M4 ;
        RECT  21.516 71.136 21.6 71.16 ;
    END
  END b[441]
  PIN b[442]
    DIRECTION OUTPUT ;
    USE SIGNAL ;
    PORT
      LAYER M4 ;
        RECT  21.516 71.28 21.6 71.304 ;
    END
  END b[442]
  PIN b[443]
    DIRECTION OUTPUT ;
    USE SIGNAL ;
    PORT
      LAYER M4 ;
        RECT  21.516 71.424 21.6 71.448 ;
    END
  END b[443]
  PIN b[444]
    DIRECTION OUTPUT ;
    USE SIGNAL ;
    PORT
      LAYER M4 ;
        RECT  21.516 71.568 21.6 71.592 ;
    END
  END b[444]
  PIN b[445]
    DIRECTION OUTPUT ;
    USE SIGNAL ;
    PORT
      LAYER M4 ;
        RECT  21.516 71.712 21.6 71.736 ;
    END
  END b[445]
  PIN b[446]
    DIRECTION OUTPUT ;
    USE SIGNAL ;
    PORT
      LAYER M4 ;
        RECT  21.516 71.856 21.6 71.88 ;
    END
  END b[446]
  PIN b[447]
    DIRECTION OUTPUT ;
    USE SIGNAL ;
    PORT
      LAYER M4 ;
        RECT  21.516 72 21.6 72.024 ;
    END
  END b[447]
  PIN b[448]
    DIRECTION OUTPUT ;
    USE SIGNAL ;
    PORT
      LAYER M4 ;
        RECT  21.516 62.928 21.6 62.952 ;
    END
  END b[448]
  PIN b[449]
    DIRECTION OUTPUT ;
    USE SIGNAL ;
    PORT
      LAYER M4 ;
        RECT  21.516 63.072 21.6 63.096 ;
    END
  END b[449]
  PIN b[44]
    DIRECTION OUTPUT ;
    USE SIGNAL ;
    PORT
      LAYER M4 ;
        RECT  21.516 49.68 21.6 49.704 ;
    END
  END b[44]
  PIN b[450]
    DIRECTION OUTPUT ;
    USE SIGNAL ;
    PORT
      LAYER M4 ;
        RECT  21.516 63.216 21.6 63.24 ;
    END
  END b[450]
  PIN b[451]
    DIRECTION OUTPUT ;
    USE SIGNAL ;
    PORT
      LAYER M4 ;
        RECT  21.516 63.36 21.6 63.384 ;
    END
  END b[451]
  PIN b[452]
    DIRECTION OUTPUT ;
    USE SIGNAL ;
    PORT
      LAYER M4 ;
        RECT  21.516 63.504 21.6 63.528 ;
    END
  END b[452]
  PIN b[453]
    DIRECTION OUTPUT ;
    USE SIGNAL ;
    PORT
      LAYER M4 ;
        RECT  21.516 63.648 21.6 63.672 ;
    END
  END b[453]
  PIN b[454]
    DIRECTION OUTPUT ;
    USE SIGNAL ;
    PORT
      LAYER M4 ;
        RECT  21.516 63.792 21.6 63.816 ;
    END
  END b[454]
  PIN b[455]
    DIRECTION OUTPUT ;
    USE SIGNAL ;
    PORT
      LAYER M4 ;
        RECT  21.516 63.936 21.6 63.96 ;
    END
  END b[455]
  PIN b[456]
    DIRECTION OUTPUT ;
    USE SIGNAL ;
    PORT
      LAYER M4 ;
        RECT  21.516 64.08 21.6 64.104 ;
    END
  END b[456]
  PIN b[457]
    DIRECTION OUTPUT ;
    USE SIGNAL ;
    PORT
      LAYER M4 ;
        RECT  21.516 64.224 21.6 64.248 ;
    END
  END b[457]
  PIN b[458]
    DIRECTION OUTPUT ;
    USE SIGNAL ;
    PORT
      LAYER M4 ;
        RECT  21.516 64.368 21.6 64.392 ;
    END
  END b[458]
  PIN b[459]
    DIRECTION OUTPUT ;
    USE SIGNAL ;
    PORT
      LAYER M4 ;
        RECT  21.516 64.512 21.6 64.536 ;
    END
  END b[459]
  PIN b[45]
    DIRECTION OUTPUT ;
    USE SIGNAL ;
    PORT
      LAYER M4 ;
        RECT  21.516 49.824 21.6 49.848 ;
    END
  END b[45]
  PIN b[460]
    DIRECTION OUTPUT ;
    USE SIGNAL ;
    PORT
      LAYER M4 ;
        RECT  21.516 64.656 21.6 64.68 ;
    END
  END b[460]
  PIN b[461]
    DIRECTION OUTPUT ;
    USE SIGNAL ;
    PORT
      LAYER M4 ;
        RECT  21.516 64.8 21.6 64.824 ;
    END
  END b[461]
  PIN b[462]
    DIRECTION OUTPUT ;
    USE SIGNAL ;
    PORT
      LAYER M4 ;
        RECT  21.516 64.944 21.6 64.968 ;
    END
  END b[462]
  PIN b[463]
    DIRECTION OUTPUT ;
    USE SIGNAL ;
    PORT
      LAYER M4 ;
        RECT  21.516 65.088 21.6 65.112 ;
    END
  END b[463]
  PIN b[464]
    DIRECTION OUTPUT ;
    USE SIGNAL ;
    PORT
      LAYER M4 ;
        RECT  21.516 65.232 21.6 65.256 ;
    END
  END b[464]
  PIN b[465]
    DIRECTION OUTPUT ;
    USE SIGNAL ;
    PORT
      LAYER M4 ;
        RECT  21.516 65.376 21.6 65.4 ;
    END
  END b[465]
  PIN b[466]
    DIRECTION OUTPUT ;
    USE SIGNAL ;
    PORT
      LAYER M4 ;
        RECT  21.516 65.52 21.6 65.544 ;
    END
  END b[466]
  PIN b[467]
    DIRECTION OUTPUT ;
    USE SIGNAL ;
    PORT
      LAYER M4 ;
        RECT  21.516 65.664 21.6 65.688 ;
    END
  END b[467]
  PIN b[468]
    DIRECTION OUTPUT ;
    USE SIGNAL ;
    PORT
      LAYER M4 ;
        RECT  21.516 65.808 21.6 65.832 ;
    END
  END b[468]
  PIN b[469]
    DIRECTION OUTPUT ;
    USE SIGNAL ;
    PORT
      LAYER M4 ;
        RECT  21.516 65.952 21.6 65.976 ;
    END
  END b[469]
  PIN b[46]
    DIRECTION OUTPUT ;
    USE SIGNAL ;
    PORT
      LAYER M4 ;
        RECT  21.516 49.968 21.6 49.992 ;
    END
  END b[46]
  PIN b[470]
    DIRECTION OUTPUT ;
    USE SIGNAL ;
    PORT
      LAYER M4 ;
        RECT  21.516 66.096 21.6 66.12 ;
    END
  END b[470]
  PIN b[471]
    DIRECTION OUTPUT ;
    USE SIGNAL ;
    PORT
      LAYER M4 ;
        RECT  21.516 66.24 21.6 66.264 ;
    END
  END b[471]
  PIN b[472]
    DIRECTION OUTPUT ;
    USE SIGNAL ;
    PORT
      LAYER M4 ;
        RECT  21.516 66.384 21.6 66.408 ;
    END
  END b[472]
  PIN b[473]
    DIRECTION OUTPUT ;
    USE SIGNAL ;
    PORT
      LAYER M4 ;
        RECT  21.516 66.528 21.6 66.552 ;
    END
  END b[473]
  PIN b[474]
    DIRECTION OUTPUT ;
    USE SIGNAL ;
    PORT
      LAYER M4 ;
        RECT  21.516 66.672 21.6 66.696 ;
    END
  END b[474]
  PIN b[475]
    DIRECTION OUTPUT ;
    USE SIGNAL ;
    PORT
      LAYER M4 ;
        RECT  21.516 66.816 21.6 66.84 ;
    END
  END b[475]
  PIN b[476]
    DIRECTION OUTPUT ;
    USE SIGNAL ;
    PORT
      LAYER M4 ;
        RECT  21.516 66.96 21.6 66.984 ;
    END
  END b[476]
  PIN b[477]
    DIRECTION OUTPUT ;
    USE SIGNAL ;
    PORT
      LAYER M4 ;
        RECT  21.516 67.104 21.6 67.128 ;
    END
  END b[477]
  PIN b[478]
    DIRECTION OUTPUT ;
    USE SIGNAL ;
    PORT
      LAYER M4 ;
        RECT  21.516 67.248 21.6 67.272 ;
    END
  END b[478]
  PIN b[479]
    DIRECTION OUTPUT ;
    USE SIGNAL ;
    PORT
      LAYER M4 ;
        RECT  21.516 67.392 21.6 67.416 ;
    END
  END b[479]
  PIN b[47]
    DIRECTION OUTPUT ;
    USE SIGNAL ;
    PORT
      LAYER M4 ;
        RECT  21.516 50.112 21.6 50.136 ;
    END
  END b[47]
  PIN b[480]
    DIRECTION OUTPUT ;
    USE SIGNAL ;
    PORT
      LAYER M4 ;
        RECT  21.516 58.32 21.6 58.344 ;
    END
  END b[480]
  PIN b[481]
    DIRECTION OUTPUT ;
    USE SIGNAL ;
    PORT
      LAYER M4 ;
        RECT  21.516 58.464 21.6 58.488 ;
    END
  END b[481]
  PIN b[482]
    DIRECTION OUTPUT ;
    USE SIGNAL ;
    PORT
      LAYER M4 ;
        RECT  21.516 58.608 21.6 58.632 ;
    END
  END b[482]
  PIN b[483]
    DIRECTION OUTPUT ;
    USE SIGNAL ;
    PORT
      LAYER M4 ;
        RECT  21.516 58.752 21.6 58.776 ;
    END
  END b[483]
  PIN b[484]
    DIRECTION OUTPUT ;
    USE SIGNAL ;
    PORT
      LAYER M4 ;
        RECT  21.516 58.896 21.6 58.92 ;
    END
  END b[484]
  PIN b[485]
    DIRECTION OUTPUT ;
    USE SIGNAL ;
    PORT
      LAYER M4 ;
        RECT  21.516 59.04 21.6 59.064 ;
    END
  END b[485]
  PIN b[486]
    DIRECTION OUTPUT ;
    USE SIGNAL ;
    PORT
      LAYER M4 ;
        RECT  21.516 59.184 21.6 59.208 ;
    END
  END b[486]
  PIN b[487]
    DIRECTION OUTPUT ;
    USE SIGNAL ;
    PORT
      LAYER M4 ;
        RECT  21.516 59.328 21.6 59.352 ;
    END
  END b[487]
  PIN b[488]
    DIRECTION OUTPUT ;
    USE SIGNAL ;
    PORT
      LAYER M4 ;
        RECT  21.516 59.472 21.6 59.496 ;
    END
  END b[488]
  PIN b[489]
    DIRECTION OUTPUT ;
    USE SIGNAL ;
    PORT
      LAYER M4 ;
        RECT  21.516 59.616 21.6 59.64 ;
    END
  END b[489]
  PIN b[48]
    DIRECTION OUTPUT ;
    USE SIGNAL ;
    PORT
      LAYER M4 ;
        RECT  21.516 50.256 21.6 50.28 ;
    END
  END b[48]
  PIN b[490]
    DIRECTION OUTPUT ;
    USE SIGNAL ;
    PORT
      LAYER M4 ;
        RECT  21.516 59.76 21.6 59.784 ;
    END
  END b[490]
  PIN b[491]
    DIRECTION OUTPUT ;
    USE SIGNAL ;
    PORT
      LAYER M4 ;
        RECT  21.516 59.904 21.6 59.928 ;
    END
  END b[491]
  PIN b[492]
    DIRECTION OUTPUT ;
    USE SIGNAL ;
    PORT
      LAYER M4 ;
        RECT  21.516 60.048 21.6 60.072 ;
    END
  END b[492]
  PIN b[493]
    DIRECTION OUTPUT ;
    USE SIGNAL ;
    PORT
      LAYER M4 ;
        RECT  21.516 60.192 21.6 60.216 ;
    END
  END b[493]
  PIN b[494]
    DIRECTION OUTPUT ;
    USE SIGNAL ;
    PORT
      LAYER M4 ;
        RECT  21.516 60.336 21.6 60.36 ;
    END
  END b[494]
  PIN b[495]
    DIRECTION OUTPUT ;
    USE SIGNAL ;
    PORT
      LAYER M4 ;
        RECT  21.516 60.48 21.6 60.504 ;
    END
  END b[495]
  PIN b[496]
    DIRECTION OUTPUT ;
    USE SIGNAL ;
    PORT
      LAYER M4 ;
        RECT  21.516 60.624 21.6 60.648 ;
    END
  END b[496]
  PIN b[497]
    DIRECTION OUTPUT ;
    USE SIGNAL ;
    PORT
      LAYER M4 ;
        RECT  21.516 60.768 21.6 60.792 ;
    END
  END b[497]
  PIN b[498]
    DIRECTION OUTPUT ;
    USE SIGNAL ;
    PORT
      LAYER M4 ;
        RECT  21.516 60.912 21.6 60.936 ;
    END
  END b[498]
  PIN b[499]
    DIRECTION OUTPUT ;
    USE SIGNAL ;
    PORT
      LAYER M4 ;
        RECT  21.516 61.056 21.6 61.08 ;
    END
  END b[499]
  PIN b[49]
    DIRECTION OUTPUT ;
    USE SIGNAL ;
    PORT
      LAYER M4 ;
        RECT  21.516 50.4 21.6 50.424 ;
    END
  END b[49]
  PIN b[4]
    DIRECTION OUTPUT ;
    USE SIGNAL ;
    PORT
      LAYER M4 ;
        RECT  21.516 30.096 21.6 30.12 ;
    END
  END b[4]
  PIN b[500]
    DIRECTION OUTPUT ;
    USE SIGNAL ;
    PORT
      LAYER M4 ;
        RECT  21.516 61.2 21.6 61.224 ;
    END
  END b[500]
  PIN b[501]
    DIRECTION OUTPUT ;
    USE SIGNAL ;
    PORT
      LAYER M4 ;
        RECT  21.516 61.344 21.6 61.368 ;
    END
  END b[501]
  PIN b[502]
    DIRECTION OUTPUT ;
    USE SIGNAL ;
    PORT
      LAYER M4 ;
        RECT  21.516 61.488 21.6 61.512 ;
    END
  END b[502]
  PIN b[503]
    DIRECTION OUTPUT ;
    USE SIGNAL ;
    PORT
      LAYER M4 ;
        RECT  21.516 61.632 21.6 61.656 ;
    END
  END b[503]
  PIN b[504]
    DIRECTION OUTPUT ;
    USE SIGNAL ;
    PORT
      LAYER M4 ;
        RECT  21.516 61.776 21.6 61.8 ;
    END
  END b[504]
  PIN b[505]
    DIRECTION OUTPUT ;
    USE SIGNAL ;
    PORT
      LAYER M4 ;
        RECT  21.516 61.92 21.6 61.944 ;
    END
  END b[505]
  PIN b[506]
    DIRECTION OUTPUT ;
    USE SIGNAL ;
    PORT
      LAYER M4 ;
        RECT  21.516 62.064 21.6 62.088 ;
    END
  END b[506]
  PIN b[507]
    DIRECTION OUTPUT ;
    USE SIGNAL ;
    PORT
      LAYER M4 ;
        RECT  21.516 62.208 21.6 62.232 ;
    END
  END b[507]
  PIN b[508]
    DIRECTION OUTPUT ;
    USE SIGNAL ;
    PORT
      LAYER M4 ;
        RECT  21.516 62.352 21.6 62.376 ;
    END
  END b[508]
  PIN b[509]
    DIRECTION OUTPUT ;
    USE SIGNAL ;
    PORT
      LAYER M4 ;
        RECT  21.516 62.496 21.6 62.52 ;
    END
  END b[509]
  PIN b[50]
    DIRECTION OUTPUT ;
    USE SIGNAL ;
    PORT
      LAYER M4 ;
        RECT  21.516 50.544 21.6 50.568 ;
    END
  END b[50]
  PIN b[510]
    DIRECTION OUTPUT ;
    USE SIGNAL ;
    PORT
      LAYER M4 ;
        RECT  21.516 62.64 21.6 62.664 ;
    END
  END b[510]
  PIN b[511]
    DIRECTION OUTPUT ;
    USE SIGNAL ;
    PORT
      LAYER M4 ;
        RECT  21.516 62.784 21.6 62.808 ;
    END
  END b[511]
  PIN b[512]
    DIRECTION OUTPUT ;
    USE SIGNAL ;
    PORT
      LAYER M4 ;
        RECT  21.516 76.752 21.6 76.776 ;
    END
  END b[512]
  PIN b[513]
    DIRECTION OUTPUT ;
    USE SIGNAL ;
    PORT
      LAYER M4 ;
        RECT  21.516 76.896 21.6 76.92 ;
    END
  END b[513]
  PIN b[514]
    DIRECTION OUTPUT ;
    USE SIGNAL ;
    PORT
      LAYER M4 ;
        RECT  21.516 77.04 21.6 77.064 ;
    END
  END b[514]
  PIN b[515]
    DIRECTION OUTPUT ;
    USE SIGNAL ;
    PORT
      LAYER M4 ;
        RECT  21.516 77.184 21.6 77.208 ;
    END
  END b[515]
  PIN b[516]
    DIRECTION OUTPUT ;
    USE SIGNAL ;
    PORT
      LAYER M4 ;
        RECT  21.516 77.328 21.6 77.352 ;
    END
  END b[516]
  PIN b[517]
    DIRECTION OUTPUT ;
    USE SIGNAL ;
    PORT
      LAYER M4 ;
        RECT  21.516 77.472 21.6 77.496 ;
    END
  END b[517]
  PIN b[518]
    DIRECTION OUTPUT ;
    USE SIGNAL ;
    PORT
      LAYER M4 ;
        RECT  21.516 77.616 21.6 77.64 ;
    END
  END b[518]
  PIN b[519]
    DIRECTION OUTPUT ;
    USE SIGNAL ;
    PORT
      LAYER M4 ;
        RECT  21.516 77.76 21.6 77.784 ;
    END
  END b[519]
  PIN b[51]
    DIRECTION OUTPUT ;
    USE SIGNAL ;
    PORT
      LAYER M4 ;
        RECT  21.516 50.688 21.6 50.712 ;
    END
  END b[51]
  PIN b[520]
    DIRECTION OUTPUT ;
    USE SIGNAL ;
    PORT
      LAYER M4 ;
        RECT  21.516 77.904 21.6 77.928 ;
    END
  END b[520]
  PIN b[521]
    DIRECTION OUTPUT ;
    USE SIGNAL ;
    PORT
      LAYER M4 ;
        RECT  21.516 78.048 21.6 78.072 ;
    END
  END b[521]
  PIN b[522]
    DIRECTION OUTPUT ;
    USE SIGNAL ;
    PORT
      LAYER M4 ;
        RECT  21.516 78.192 21.6 78.216 ;
    END
  END b[522]
  PIN b[523]
    DIRECTION OUTPUT ;
    USE SIGNAL ;
    PORT
      LAYER M4 ;
        RECT  21.516 78.336 21.6 78.36 ;
    END
  END b[523]
  PIN b[524]
    DIRECTION OUTPUT ;
    USE SIGNAL ;
    PORT
      LAYER M4 ;
        RECT  21.516 78.48 21.6 78.504 ;
    END
  END b[524]
  PIN b[525]
    DIRECTION OUTPUT ;
    USE SIGNAL ;
    PORT
      LAYER M4 ;
        RECT  21.516 78.624 21.6 78.648 ;
    END
  END b[525]
  PIN b[526]
    DIRECTION OUTPUT ;
    USE SIGNAL ;
    PORT
      LAYER M4 ;
        RECT  21.516 78.768 21.6 78.792 ;
    END
  END b[526]
  PIN b[527]
    DIRECTION OUTPUT ;
    USE SIGNAL ;
    PORT
      LAYER M4 ;
        RECT  21.516 78.912 21.6 78.936 ;
    END
  END b[527]
  PIN b[52]
    DIRECTION OUTPUT ;
    USE SIGNAL ;
    PORT
      LAYER M4 ;
        RECT  21.516 50.832 21.6 50.856 ;
    END
  END b[52]
  PIN b[53]
    DIRECTION OUTPUT ;
    USE SIGNAL ;
    PORT
      LAYER M4 ;
        RECT  21.516 50.976 21.6 51 ;
    END
  END b[53]
  PIN b[54]
    DIRECTION OUTPUT ;
    USE SIGNAL ;
    PORT
      LAYER M4 ;
        RECT  21.516 51.12 21.6 51.144 ;
    END
  END b[54]
  PIN b[55]
    DIRECTION OUTPUT ;
    USE SIGNAL ;
    PORT
      LAYER M4 ;
        RECT  21.516 51.264 21.6 51.288 ;
    END
  END b[55]
  PIN b[56]
    DIRECTION OUTPUT ;
    USE SIGNAL ;
    PORT
      LAYER M4 ;
        RECT  21.516 51.408 21.6 51.432 ;
    END
  END b[56]
  PIN b[57]
    DIRECTION OUTPUT ;
    USE SIGNAL ;
    PORT
      LAYER M4 ;
        RECT  21.516 51.552 21.6 51.576 ;
    END
  END b[57]
  PIN b[58]
    DIRECTION OUTPUT ;
    USE SIGNAL ;
    PORT
      LAYER M4 ;
        RECT  21.516 51.696 21.6 51.72 ;
    END
  END b[58]
  PIN b[59]
    DIRECTION OUTPUT ;
    USE SIGNAL ;
    PORT
      LAYER M4 ;
        RECT  21.516 51.84 21.6 51.864 ;
    END
  END b[59]
  PIN b[5]
    DIRECTION OUTPUT ;
    USE SIGNAL ;
    PORT
      LAYER M4 ;
        RECT  21.516 30.24 21.6 30.264 ;
    END
  END b[5]
  PIN b[60]
    DIRECTION OUTPUT ;
    USE SIGNAL ;
    PORT
      LAYER M4 ;
        RECT  21.516 51.984 21.6 52.008 ;
    END
  END b[60]
  PIN b[61]
    DIRECTION OUTPUT ;
    USE SIGNAL ;
    PORT
      LAYER M4 ;
        RECT  21.516 52.128 21.6 52.152 ;
    END
  END b[61]
  PIN b[62]
    DIRECTION OUTPUT ;
    USE SIGNAL ;
    PORT
      LAYER M4 ;
        RECT  21.516 52.272 21.6 52.296 ;
    END
  END b[62]
  PIN b[63]
    DIRECTION OUTPUT ;
    USE SIGNAL ;
    PORT
      LAYER M4 ;
        RECT  21.516 52.416 21.6 52.44 ;
    END
  END b[63]
  PIN b[64]
    DIRECTION OUTPUT ;
    USE SIGNAL ;
    PORT
      LAYER M4 ;
        RECT  21.516 43.344 21.6 43.368 ;
    END
  END b[64]
  PIN b[65]
    DIRECTION OUTPUT ;
    USE SIGNAL ;
    PORT
      LAYER M4 ;
        RECT  21.516 43.488 21.6 43.512 ;
    END
  END b[65]
  PIN b[66]
    DIRECTION OUTPUT ;
    USE SIGNAL ;
    PORT
      LAYER M4 ;
        RECT  21.516 43.632 21.6 43.656 ;
    END
  END b[66]
  PIN b[67]
    DIRECTION OUTPUT ;
    USE SIGNAL ;
    PORT
      LAYER M4 ;
        RECT  21.516 43.776 21.6 43.8 ;
    END
  END b[67]
  PIN b[68]
    DIRECTION OUTPUT ;
    USE SIGNAL ;
    PORT
      LAYER M4 ;
        RECT  21.516 43.92 21.6 43.944 ;
    END
  END b[68]
  PIN b[69]
    DIRECTION OUTPUT ;
    USE SIGNAL ;
    PORT
      LAYER M4 ;
        RECT  21.516 44.064 21.6 44.088 ;
    END
  END b[69]
  PIN b[6]
    DIRECTION OUTPUT ;
    USE SIGNAL ;
    PORT
      LAYER M4 ;
        RECT  21.516 30.384 21.6 30.408 ;
    END
  END b[6]
  PIN b[70]
    DIRECTION OUTPUT ;
    USE SIGNAL ;
    PORT
      LAYER M4 ;
        RECT  21.516 44.208 21.6 44.232 ;
    END
  END b[70]
  PIN b[71]
    DIRECTION OUTPUT ;
    USE SIGNAL ;
    PORT
      LAYER M4 ;
        RECT  21.516 44.352 21.6 44.376 ;
    END
  END b[71]
  PIN b[72]
    DIRECTION OUTPUT ;
    USE SIGNAL ;
    PORT
      LAYER M4 ;
        RECT  21.516 44.496 21.6 44.52 ;
    END
  END b[72]
  PIN b[73]
    DIRECTION OUTPUT ;
    USE SIGNAL ;
    PORT
      LAYER M4 ;
        RECT  21.516 44.64 21.6 44.664 ;
    END
  END b[73]
  PIN b[74]
    DIRECTION OUTPUT ;
    USE SIGNAL ;
    PORT
      LAYER M4 ;
        RECT  21.516 44.784 21.6 44.808 ;
    END
  END b[74]
  PIN b[75]
    DIRECTION OUTPUT ;
    USE SIGNAL ;
    PORT
      LAYER M4 ;
        RECT  21.516 44.928 21.6 44.952 ;
    END
  END b[75]
  PIN b[76]
    DIRECTION OUTPUT ;
    USE SIGNAL ;
    PORT
      LAYER M4 ;
        RECT  21.516 45.072 21.6 45.096 ;
    END
  END b[76]
  PIN b[77]
    DIRECTION OUTPUT ;
    USE SIGNAL ;
    PORT
      LAYER M4 ;
        RECT  21.516 45.216 21.6 45.24 ;
    END
  END b[77]
  PIN b[78]
    DIRECTION OUTPUT ;
    USE SIGNAL ;
    PORT
      LAYER M4 ;
        RECT  21.516 45.36 21.6 45.384 ;
    END
  END b[78]
  PIN b[79]
    DIRECTION OUTPUT ;
    USE SIGNAL ;
    PORT
      LAYER M4 ;
        RECT  21.516 45.504 21.6 45.528 ;
    END
  END b[79]
  PIN b[7]
    DIRECTION OUTPUT ;
    USE SIGNAL ;
    PORT
      LAYER M4 ;
        RECT  21.516 30.528 21.6 30.552 ;
    END
  END b[7]
  PIN b[80]
    DIRECTION OUTPUT ;
    USE SIGNAL ;
    PORT
      LAYER M4 ;
        RECT  21.516 45.648 21.6 45.672 ;
    END
  END b[80]
  PIN b[81]
    DIRECTION OUTPUT ;
    USE SIGNAL ;
    PORT
      LAYER M4 ;
        RECT  21.516 45.792 21.6 45.816 ;
    END
  END b[81]
  PIN b[82]
    DIRECTION OUTPUT ;
    USE SIGNAL ;
    PORT
      LAYER M4 ;
        RECT  21.516 45.936 21.6 45.96 ;
    END
  END b[82]
  PIN b[83]
    DIRECTION OUTPUT ;
    USE SIGNAL ;
    PORT
      LAYER M4 ;
        RECT  21.516 46.08 21.6 46.104 ;
    END
  END b[83]
  PIN b[84]
    DIRECTION OUTPUT ;
    USE SIGNAL ;
    PORT
      LAYER M4 ;
        RECT  21.516 46.224 21.6 46.248 ;
    END
  END b[84]
  PIN b[85]
    DIRECTION OUTPUT ;
    USE SIGNAL ;
    PORT
      LAYER M4 ;
        RECT  21.516 46.368 21.6 46.392 ;
    END
  END b[85]
  PIN b[86]
    DIRECTION OUTPUT ;
    USE SIGNAL ;
    PORT
      LAYER M4 ;
        RECT  21.516 46.512 21.6 46.536 ;
    END
  END b[86]
  PIN b[87]
    DIRECTION OUTPUT ;
    USE SIGNAL ;
    PORT
      LAYER M4 ;
        RECT  21.516 46.656 21.6 46.68 ;
    END
  END b[87]
  PIN b[88]
    DIRECTION OUTPUT ;
    USE SIGNAL ;
    PORT
      LAYER M4 ;
        RECT  21.516 46.8 21.6 46.824 ;
    END
  END b[88]
  PIN b[89]
    DIRECTION OUTPUT ;
    USE SIGNAL ;
    PORT
      LAYER M4 ;
        RECT  21.516 46.944 21.6 46.968 ;
    END
  END b[89]
  PIN b[8]
    DIRECTION OUTPUT ;
    USE SIGNAL ;
    PORT
      LAYER M4 ;
        RECT  21.516 30.672 21.6 30.696 ;
    END
  END b[8]
  PIN b[90]
    DIRECTION OUTPUT ;
    USE SIGNAL ;
    PORT
      LAYER M4 ;
        RECT  21.516 47.088 21.6 47.112 ;
    END
  END b[90]
  PIN b[91]
    DIRECTION OUTPUT ;
    USE SIGNAL ;
    PORT
      LAYER M4 ;
        RECT  21.516 47.232 21.6 47.256 ;
    END
  END b[91]
  PIN b[92]
    DIRECTION OUTPUT ;
    USE SIGNAL ;
    PORT
      LAYER M4 ;
        RECT  21.516 47.376 21.6 47.4 ;
    END
  END b[92]
  PIN b[93]
    DIRECTION OUTPUT ;
    USE SIGNAL ;
    PORT
      LAYER M4 ;
        RECT  21.516 47.52 21.6 47.544 ;
    END
  END b[93]
  PIN b[94]
    DIRECTION OUTPUT ;
    USE SIGNAL ;
    PORT
      LAYER M4 ;
        RECT  21.516 47.664 21.6 47.688 ;
    END
  END b[94]
  PIN b[95]
    DIRECTION OUTPUT ;
    USE SIGNAL ;
    PORT
      LAYER M4 ;
        RECT  21.516 47.808 21.6 47.832 ;
    END
  END b[95]
  PIN b[96]
    DIRECTION OUTPUT ;
    USE SIGNAL ;
    PORT
      LAYER M4 ;
        RECT  21.516 52.56 21.6 52.584 ;
    END
  END b[96]
  PIN b[97]
    DIRECTION OUTPUT ;
    USE SIGNAL ;
    PORT
      LAYER M4 ;
        RECT  21.516 52.704 21.6 52.728 ;
    END
  END b[97]
  PIN b[98]
    DIRECTION OUTPUT ;
    USE SIGNAL ;
    PORT
      LAYER M4 ;
        RECT  21.516 52.848 21.6 52.872 ;
    END
  END b[98]
  PIN b[99]
    DIRECTION OUTPUT ;
    USE SIGNAL ;
    PORT
      LAYER M4 ;
        RECT  21.516 52.992 21.6 53.016 ;
    END
  END b[99]
  PIN b[9]
    DIRECTION OUTPUT ;
    USE SIGNAL ;
    PORT
      LAYER M4 ;
        RECT  21.516 30.816 21.6 30.84 ;
    END
  END b[9]
  PIN ck
    DIRECTION INPUT ;
    USE SIGNAL ;
    PORT
      LAYER M3 ;
        RECT  12.852 0 12.87 0.037 ;
    END
  END ck
  PIN ck_o
    DIRECTION OUTPUT ;
    USE SIGNAL ;
    PORT
      LAYER M5 ;
        RECT  13.104 81.996 13.128 82.08 ;
    END
  END ck_o
  PIN eb
    DIRECTION OUTPUT ;
    USE SIGNAL ;
    PORT
      LAYER M5 ;
        RECT  13.248 81.996 13.272 82.08 ;
    END
  END eb
  PIN en
    DIRECTION INPUT ;
    USE SIGNAL ;
    PORT
      LAYER M3 ;
        RECT  12.96 0 12.978 0.037 ;
    END
  END en
  PIN VDD
    DIRECTION INOUT ;
    USE POWER ;
    PORT
      LAYER M5 ;
        RECT  18.792 2.151 18.912 79.929 ;
        RECT  16.092 2.151 16.212 79.929 ;
        RECT  13.392 2.151 13.512 79.929 ;
        RECT  10.692 2.151 10.812 79.929 ;
        RECT  7.992 2.151 8.112 79.929 ;
        RECT  5.292 2.151 5.412 79.929 ;
        RECT  2.592 2.151 2.712 79.929 ;
    END
  END VDD
  PIN VSS
    DIRECTION INOUT ;
    USE GROUND ;
    PORT
      LAYER M5 ;
        RECT  18.6 2.137 18.72 79.943 ;
        RECT  15.9 2.137 16.02 79.943 ;
        RECT  13.2 2.137 13.32 79.943 ;
        RECT  10.5 2.137 10.62 79.943 ;
        RECT  7.8 2.137 7.92 79.943 ;
        RECT  5.1 2.137 5.22 79.943 ;
        RECT  2.4 2.137 2.52 79.943 ;
    END
  END VSS
  # OT_OBS_CLOSED layer=M5 d_um=1.536 added=33
  OBS
    LAYER RVTN ;
     RECT  2.16 2.16 19.44 2.295 ;
     RECT  2.16 2.565 19.44 2.835 ;
     RECT  2.16 3.105 19.44 3.375 ;
     RECT  2.16 3.645 19.44 3.915 ;
     RECT  2.16 4.185 19.44 4.455 ;
     RECT  2.16 4.725 19.44 4.995 ;
     RECT  2.16 5.265 19.44 5.535 ;
     RECT  2.16 5.805 19.44 6.075 ;
     RECT  2.16 6.345 19.44 6.615 ;
     RECT  2.16 6.885 19.44 7.155 ;
     RECT  2.16 7.425 19.44 7.695 ;
     RECT  2.16 7.965 19.44 8.235 ;
     RECT  2.16 8.505 19.44 8.775 ;
     RECT  2.16 9.045 19.44 9.315 ;
     RECT  2.16 9.585 19.44 9.855 ;
     RECT  2.16 10.125 19.44 10.395 ;
     RECT  2.16 10.665 19.44 10.935 ;
     RECT  2.16 11.205 19.44 11.475 ;
     RECT  2.16 11.745 19.44 12.015 ;
     RECT  2.16 12.285 19.44 12.555 ;
     RECT  2.16 12.825 19.44 13.095 ;
     RECT  2.16 13.365 19.44 13.635 ;
     RECT  2.16 13.905 19.44 14.175 ;
     RECT  2.16 14.445 19.44 14.715 ;
     RECT  2.16 14.985 19.44 15.255 ;
     RECT  2.16 15.525 19.44 15.795 ;
     RECT  2.16 16.065 19.44 16.335 ;
     RECT  2.16 16.605 19.44 16.875 ;
     RECT  2.16 17.145 19.44 17.415 ;
     RECT  2.16 17.685 19.44 17.955 ;
     RECT  2.16 18.225 19.44 18.495 ;
     RECT  2.16 18.765 19.44 19.035 ;
     RECT  2.16 19.305 19.44 19.575 ;
     RECT  2.16 19.845 19.44 20.115 ;
     RECT  2.16 20.385 19.44 20.655 ;
     RECT  2.16 20.925 19.44 21.195 ;
     RECT  2.16 21.465 19.44 21.735 ;
     RECT  2.16 22.005 19.44 22.275 ;
     RECT  2.16 22.545 19.44 22.815 ;
     RECT  2.16 23.085 19.44 23.355 ;
     RECT  2.16 23.625 19.44 23.895 ;
     RECT  2.16 24.165 19.44 24.435 ;
     RECT  2.16 24.705 19.44 24.975 ;
     RECT  2.16 25.245 19.44 25.515 ;
     RECT  2.16 25.785 19.44 26.055 ;
     RECT  2.16 26.325 19.44 26.595 ;
     RECT  2.16 26.865 19.44 27.135 ;
     RECT  2.16 27.405 19.44 27.675 ;
     RECT  2.16 27.945 19.44 28.215 ;
     RECT  2.16 28.485 19.44 28.755 ;
     RECT  2.16 29.025 19.44 29.295 ;
     RECT  2.16 29.565 19.44 29.835 ;
     RECT  2.16 30.105 19.44 30.375 ;
     RECT  2.16 30.645 19.44 30.915 ;
     RECT  2.16 31.185 19.44 31.455 ;
     RECT  2.16 31.725 19.44 31.995 ;
     RECT  2.16 32.265 19.44 32.535 ;
     RECT  2.16 32.805 19.44 33.075 ;
     RECT  2.16 33.345 19.44 33.615 ;
     RECT  2.16 33.885 19.44 34.155 ;
     RECT  2.16 34.425 19.44 34.695 ;
     RECT  2.16 34.965 19.44 35.235 ;
     RECT  2.16 35.505 19.44 35.775 ;
     RECT  2.16 36.045 19.44 36.315 ;
     RECT  2.16 36.585 19.44 36.855 ;
     RECT  2.16 37.125 19.44 37.395 ;
     RECT  2.16 37.665 19.44 37.935 ;
     RECT  2.16 38.205 19.44 38.475 ;
     RECT  2.16 38.745 19.44 39.015 ;
     RECT  2.16 39.285 19.44 39.555 ;
     RECT  2.16 39.825 19.44 40.095 ;
     RECT  2.16 40.365 19.44 40.635 ;
     RECT  2.16 40.905 19.44 41.175 ;
     RECT  2.16 41.445 19.44 41.715 ;
     RECT  2.16 41.985 19.44 42.255 ;
     RECT  2.16 42.525 19.44 42.795 ;
     RECT  2.16 43.065 19.44 43.335 ;
     RECT  2.16 43.605 19.44 43.875 ;
     RECT  2.16 44.145 19.44 44.415 ;
     RECT  2.16 44.685 19.44 44.955 ;
     RECT  2.16 45.225 19.44 45.495 ;
     RECT  2.16 45.765 19.44 46.035 ;
     RECT  2.16 46.305 19.44 46.575 ;
     RECT  2.16 46.845 19.44 47.115 ;
     RECT  2.16 47.385 19.44 47.655 ;
     RECT  2.16 47.925 19.44 48.195 ;
     RECT  2.16 48.465 19.44 48.735 ;
     RECT  2.16 49.005 19.44 49.275 ;
     RECT  2.16 49.545 19.44 49.815 ;
     RECT  2.16 50.085 19.44 50.355 ;
     RECT  2.16 50.625 19.44 50.895 ;
     RECT  2.16 51.165 19.44 51.435 ;
     RECT  2.16 51.705 19.44 51.975 ;
     RECT  2.16 52.245 19.44 52.515 ;
     RECT  2.16 52.785 19.44 53.055 ;
     RECT  2.16 53.325 19.44 53.595 ;
     RECT  2.16 53.865 19.44 54.135 ;
     RECT  2.16 54.405 19.44 54.675 ;
     RECT  2.16 54.945 19.44 55.215 ;
     RECT  2.16 55.485 19.44 55.755 ;
     RECT  2.16 56.025 19.44 56.295 ;
     RECT  2.16 56.565 19.44 56.835 ;
     RECT  2.16 57.105 19.44 57.375 ;
     RECT  2.16 57.645 19.44 57.915 ;
     RECT  2.16 58.185 19.44 58.455 ;
     RECT  2.16 58.725 19.44 58.995 ;
     RECT  2.16 59.265 19.44 59.535 ;
     RECT  2.16 59.805 19.44 60.075 ;
     RECT  2.16 60.345 19.44 60.615 ;
     RECT  2.16 60.885 19.44 61.155 ;
     RECT  2.16 61.425 19.44 61.695 ;
     RECT  2.16 61.965 19.44 62.235 ;
     RECT  2.16 62.505 19.44 62.775 ;
     RECT  2.16 63.045 19.44 63.315 ;
     RECT  2.16 63.585 19.44 63.855 ;
     RECT  2.16 64.125 19.44 64.395 ;
     RECT  2.16 64.665 19.44 64.935 ;
     RECT  2.16 65.205 19.44 65.475 ;
     RECT  2.16 65.745 19.44 66.015 ;
     RECT  2.16 66.285 19.44 66.555 ;
     RECT  2.16 66.825 19.44 67.095 ;
     RECT  2.16 67.365 19.44 67.635 ;
     RECT  2.16 67.905 19.44 68.175 ;
     RECT  2.16 68.445 19.44 68.715 ;
     RECT  2.16 68.985 19.44 69.255 ;
     RECT  2.16 69.525 19.44 69.795 ;
     RECT  2.16 70.065 19.44 70.335 ;
     RECT  2.16 70.605 19.44 70.875 ;
     RECT  2.16 71.145 19.44 71.415 ;
     RECT  2.16 71.685 19.44 71.955 ;
     RECT  2.16 72.225 19.44 72.495 ;
     RECT  2.16 72.765 19.44 73.035 ;
     RECT  2.16 73.305 19.44 73.575 ;
     RECT  2.16 73.845 19.44 74.115 ;
     RECT  2.16 74.385 19.44 74.655 ;
     RECT  2.16 74.925 19.44 75.195 ;
     RECT  2.16 75.465 19.44 75.735 ;
     RECT  2.16 76.005 19.44 76.275 ;
     RECT  2.16 76.545 19.44 76.815 ;
     RECT  2.16 77.085 19.44 77.355 ;
     RECT  2.16 77.625 19.44 77.895 ;
     RECT  2.16 78.165 19.44 78.435 ;
     RECT  2.16 78.705 19.44 78.975 ;
     RECT  2.16 79.245 19.44 79.515 ;
     RECT  2.16 79.785 19.44 79.92 ;
    LAYER RVTP ;
     RECT  2.16 2.295 19.44 2.565 ;
     RECT  2.16 2.835 19.44 3.105 ;
     RECT  2.16 3.375 19.44 3.645 ;
     RECT  2.16 3.915 19.44 4.185 ;
     RECT  2.16 4.455 19.44 4.725 ;
     RECT  2.16 4.995 19.44 5.265 ;
     RECT  2.16 5.535 19.44 5.805 ;
     RECT  2.16 6.075 19.44 6.345 ;
     RECT  2.16 6.615 19.44 6.885 ;
     RECT  2.16 7.155 19.44 7.425 ;
     RECT  2.16 7.695 19.44 7.965 ;
     RECT  2.16 8.235 19.44 8.505 ;
     RECT  2.16 8.775 19.44 9.045 ;
     RECT  2.16 9.315 19.44 9.585 ;
     RECT  2.16 9.855 19.44 10.125 ;
     RECT  2.16 10.395 19.44 10.665 ;
     RECT  2.16 10.935 19.44 11.205 ;
     RECT  2.16 11.475 19.44 11.745 ;
     RECT  2.16 12.015 19.44 12.285 ;
     RECT  2.16 12.555 19.44 12.825 ;
     RECT  2.16 13.095 19.44 13.365 ;
     RECT  2.16 13.635 19.44 13.905 ;
     RECT  2.16 14.175 19.44 14.445 ;
     RECT  2.16 14.715 19.44 14.985 ;
     RECT  2.16 15.255 19.44 15.525 ;
     RECT  2.16 15.795 19.44 16.065 ;
     RECT  2.16 16.335 19.44 16.605 ;
     RECT  2.16 16.875 19.44 17.145 ;
     RECT  2.16 17.415 19.44 17.685 ;
     RECT  2.16 17.955 19.44 18.225 ;
     RECT  2.16 18.495 19.44 18.765 ;
     RECT  2.16 19.035 19.44 19.305 ;
     RECT  2.16 19.575 19.44 19.845 ;
     RECT  2.16 20.115 19.44 20.385 ;
     RECT  2.16 20.655 19.44 20.925 ;
     RECT  2.16 21.195 19.44 21.465 ;
     RECT  2.16 21.735 19.44 22.005 ;
     RECT  2.16 22.275 19.44 22.545 ;
     RECT  2.16 22.815 19.44 23.085 ;
     RECT  2.16 23.355 19.44 23.625 ;
     RECT  2.16 23.895 19.44 24.165 ;
     RECT  2.16 24.435 19.44 24.705 ;
     RECT  2.16 24.975 19.44 25.245 ;
     RECT  2.16 25.515 19.44 25.785 ;
     RECT  2.16 26.055 19.44 26.325 ;
     RECT  2.16 26.595 19.44 26.865 ;
     RECT  2.16 27.135 19.44 27.405 ;
     RECT  2.16 27.675 19.44 27.945 ;
     RECT  2.16 28.215 19.44 28.485 ;
     RECT  2.16 28.755 19.44 29.025 ;
     RECT  2.16 29.295 19.44 29.565 ;
     RECT  2.16 29.835 19.44 30.105 ;
     RECT  2.16 30.375 19.44 30.645 ;
     RECT  2.16 30.915 19.44 31.185 ;
     RECT  2.16 31.455 19.44 31.725 ;
     RECT  2.16 31.995 19.44 32.265 ;
     RECT  2.16 32.535 19.44 32.805 ;
     RECT  2.16 33.075 19.44 33.345 ;
     RECT  2.16 33.615 19.44 33.885 ;
     RECT  2.16 34.155 19.44 34.425 ;
     RECT  2.16 34.695 19.44 34.965 ;
     RECT  2.16 35.235 19.44 35.505 ;
     RECT  2.16 35.775 19.44 36.045 ;
     RECT  2.16 36.315 19.44 36.585 ;
     RECT  2.16 36.855 19.44 37.125 ;
     RECT  2.16 37.395 19.44 37.665 ;
     RECT  2.16 37.935 19.44 38.205 ;
     RECT  2.16 38.475 19.44 38.745 ;
     RECT  2.16 39.015 19.44 39.285 ;
     RECT  2.16 39.555 19.44 39.825 ;
     RECT  2.16 40.095 19.44 40.365 ;
     RECT  2.16 40.635 19.44 40.905 ;
     RECT  2.16 41.175 19.44 41.445 ;
     RECT  2.16 41.715 19.44 41.985 ;
     RECT  2.16 42.255 19.44 42.525 ;
     RECT  2.16 42.795 19.44 43.065 ;
     RECT  2.16 43.335 19.44 43.605 ;
     RECT  2.16 43.875 19.44 44.145 ;
     RECT  2.16 44.415 19.44 44.685 ;
     RECT  2.16 44.955 19.44 45.225 ;
     RECT  2.16 45.495 19.44 45.765 ;
     RECT  2.16 46.035 19.44 46.305 ;
     RECT  2.16 46.575 19.44 46.845 ;
     RECT  2.16 47.115 19.44 47.385 ;
     RECT  2.16 47.655 19.44 47.925 ;
     RECT  2.16 48.195 19.44 48.465 ;
     RECT  2.16 48.735 19.44 49.005 ;
     RECT  2.16 49.275 19.44 49.545 ;
     RECT  2.16 49.815 19.44 50.085 ;
     RECT  2.16 50.355 19.44 50.625 ;
     RECT  2.16 50.895 19.44 51.165 ;
     RECT  2.16 51.435 19.44 51.705 ;
     RECT  2.16 51.975 19.44 52.245 ;
     RECT  2.16 52.515 19.44 52.785 ;
     RECT  2.16 53.055 19.44 53.325 ;
     RECT  2.16 53.595 19.44 53.865 ;
     RECT  2.16 54.135 19.44 54.405 ;
     RECT  2.16 54.675 19.44 54.945 ;
     RECT  2.16 55.215 19.44 55.485 ;
     RECT  2.16 55.755 19.44 56.025 ;
     RECT  2.16 56.295 19.44 56.565 ;
     RECT  2.16 56.835 19.44 57.105 ;
     RECT  2.16 57.375 19.44 57.645 ;
     RECT  2.16 57.915 19.44 58.185 ;
     RECT  2.16 58.455 19.44 58.725 ;
     RECT  2.16 58.995 19.44 59.265 ;
     RECT  2.16 59.535 19.44 59.805 ;
     RECT  2.16 60.075 19.44 60.345 ;
     RECT  2.16 60.615 19.44 60.885 ;
     RECT  2.16 61.155 19.44 61.425 ;
     RECT  2.16 61.695 19.44 61.965 ;
     RECT  2.16 62.235 19.44 62.505 ;
     RECT  2.16 62.775 19.44 63.045 ;
     RECT  2.16 63.315 19.44 63.585 ;
     RECT  2.16 63.855 19.44 64.125 ;
     RECT  2.16 64.395 19.44 64.665 ;
     RECT  2.16 64.935 19.44 65.205 ;
     RECT  2.16 65.475 19.44 65.745 ;
     RECT  2.16 66.015 19.44 66.285 ;
     RECT  2.16 66.555 19.44 66.825 ;
     RECT  2.16 67.095 19.44 67.365 ;
     RECT  2.16 67.635 19.44 67.905 ;
     RECT  2.16 68.175 19.44 68.445 ;
     RECT  2.16 68.715 19.44 68.985 ;
     RECT  2.16 69.255 19.44 69.525 ;
     RECT  2.16 69.795 19.44 70.065 ;
     RECT  2.16 70.335 19.44 70.605 ;
     RECT  2.16 70.875 19.44 71.145 ;
     RECT  2.16 71.415 19.44 71.685 ;
     RECT  2.16 71.955 19.44 72.225 ;
     RECT  2.16 72.495 19.44 72.765 ;
     RECT  2.16 73.035 19.44 73.305 ;
     RECT  2.16 73.575 19.44 73.845 ;
     RECT  2.16 74.115 19.44 74.385 ;
     RECT  2.16 74.655 19.44 74.925 ;
     RECT  2.16 75.195 19.44 75.465 ;
     RECT  2.16 75.735 19.44 76.005 ;
     RECT  2.16 76.275 19.44 76.545 ;
     RECT  2.16 76.815 19.44 77.085 ;
     RECT  2.16 77.355 19.44 77.625 ;
     RECT  2.16 77.895 19.44 78.165 ;
     RECT  2.16 78.435 19.44 78.705 ;
     RECT  2.16 78.975 19.44 79.245 ;
     RECT  2.16 79.515 19.44 79.785 ;
    LAYER M1 ;
     RECT  2.16 2.151 19.44 79.929 ;
    LAYER M2 ;
     RECT  0.103 3.456 0.175 3.474 ;
     RECT  0.103 76.59 0.175 76.608 ;
     RECT  0.175 3.348 0.203 3.474 ;
     RECT  0.103 48.24 0.203 48.258 ;
     RECT  0.175 76.482 0.203 76.608 ;
     RECT  0.139 55.566 0.239 55.584 ;
     RECT  0.203 3.348 0.275 3.366 ;
     RECT  0.203 76.482 0.275 76.5 ;
     RECT  0.283 35.748 0.419 35.766 ;
     RECT  0.175 73.818 0.535 73.836 ;
     RECT  0.499 78.912 0.535 78.93 ;
     RECT  0.535 78.912 1.147 79.236 ;
     RECT  0.535 68.382 1.507 68.976 ;
     RECT  1.507 68.382 1.543 69.246 ;
     RECT  1.543 67.914 1.579 69.246 ;
     RECT  0.103 13.878 1.615 13.896 ;
     RECT  1.579 12.366 1.651 12.384 ;
     RECT  1.543 25.326 2.011 25.344 ;
     RECT  0.103 66.096 2.011 66.114 ;
     RECT  2.011 24.642 2.047 25.344 ;
     RECT  2.011 65.556 2.047 66.114 ;
     RECT  1.687 66.906 2.047 66.924 ;
     RECT  1.651 11.826 2.155 12.384 ;
     RECT  2.047 65.556 2.155 66.924 ;
     RECT  1.579 67.68 2.155 69.246 ;
     RECT  1.687 10.206 2.16 10.224 ;
     RECT  2.155 11.25 2.16 12.384 ;
     RECT  1.615 13.878 2.16 14.544 ;
     RECT  2.083 19.854 2.16 19.872 ;
     RECT  2.047 22.086 2.16 22.104 ;
     RECT  0.139 22.896 2.16 22.914 ;
     RECT  2.047 24.372 2.16 25.344 ;
     RECT  1.507 26.676 2.16 26.694 ;
     RECT  0.535 27.918 2.16 27.936 ;
     RECT  0.535 30.15 2.16 30.168 ;
     RECT  1.975 36.252 2.16 36.27 ;
     RECT  1.975 39.6 2.16 39.618 ;
     RECT  0.535 58.122 2.16 59.256 ;
     RECT  0.103 61.128 2.16 61.146 ;
     RECT  2.083 62.316 2.16 62.334 ;
     RECT  2.119 64.476 2.16 64.494 ;
     RECT  2.155 65.556 2.16 69.246 ;
     RECT  1.615 70.11 2.16 70.128 ;
     RECT  0.535 73.512 2.16 73.836 ;
     RECT  1.147 78.912 2.16 79.74 ;
     RECT  2.16 2.151 19.44 79.929 ;
     RECT  19.44 77.904 19.463 78.624 ;
     RECT  19.44 53.028 19.751 57.366 ;
     RECT  19.44 71.964 19.787 72.954 ;
     RECT  19.44 63.126 19.931 71.064 ;
     RECT  19.787 72.036 19.931 72.954 ;
     RECT  19.44 2.736 19.967 3.33 ;
     RECT  19.751 53.298 19.967 57.366 ;
     RECT  19.44 59.976 19.967 62.19 ;
     RECT  19.931 63.126 19.967 68.814 ;
     RECT  19.931 72.036 19.967 72.909 ;
     RECT  19.44 75.636 19.967 77.004 ;
     RECT  19.463 77.904 19.967 78.309 ;
     RECT  19.44 29.376 20.003 35.496 ;
     RECT  19.967 55.926 20.003 57.366 ;
     RECT  19.44 23.67 20.183 24.498 ;
     RECT  20.183 24.246 20.191 24.498 ;
     RECT  19.44 25.416 20.191 28.404 ;
     RECT  19.44 19.206 20.219 19.224 ;
     RECT  19.44 21.096 20.219 22.734 ;
     RECT  20.003 56.574 20.255 57.366 ;
     RECT  19.967 63.126 20.255 65.502 ;
     RECT  19.967 77.976 20.255 78.084 ;
     RECT  19.967 53.298 20.291 54.666 ;
     RECT  19.967 59.976 20.327 61.146 ;
     RECT  19.967 62.136 20.327 62.19 ;
     RECT  19.44 10.296 20.335 12.618 ;
     RECT  19.44 13.536 20.335 14.274 ;
     RECT  19.44 15.156 20.335 16.326 ;
     RECT  20.327 60.552 20.363 61.146 ;
     RECT  20.335 10.296 20.435 14.274 ;
     RECT  20.335 15.156 20.435 16.398 ;
     RECT  20.219 21.168 20.435 22.734 ;
     RECT  20.003 29.376 20.435 30.564 ;
     RECT  19.44 36.252 20.471 48.996 ;
     RECT  20.291 53.298 20.471 53.856 ;
     RECT  19.44 4.266 20.507 4.374 ;
     RECT  19.44 5.31 20.507 8.064 ;
     RECT  19.44 8.946 20.507 9.414 ;
     RECT  20.435 10.296 20.507 12.618 ;
     RECT  20.435 21.636 20.507 22.734 ;
     RECT  20.191 24.246 20.507 28.404 ;
     RECT  19.44 51.876 20.507 52.074 ;
     RECT  20.255 56.574 20.507 57.132 ;
     RECT  19.967 72.036 20.507 72.054 ;
     RECT  20.435 29.916 20.543 30.564 ;
     RECT  20.003 31.464 20.543 35.46 ;
     RECT  20.471 36.252 20.543 47.844 ;
     RECT  20.291 54.648 20.543 54.666 ;
     RECT  20.507 56.574 20.543 56.979 ;
     RECT  20.363 60.552 20.543 61.11 ;
     RECT  20.327 62.172 20.543 62.19 ;
     RECT  20.255 63.126 20.543 65.232 ;
     RECT  19.967 66.762 20.543 68.814 ;
     RECT  19.931 69.606 20.543 71.064 ;
     RECT  19.44 73.926 20.543 73.944 ;
     RECT  19.967 75.636 20.543 75.654 ;
     RECT  20.543 39.6 20.579 47.844 ;
     RECT  20.543 64.368 20.579 65.124 ;
     RECT  20.543 66.762 20.579 67.194 ;
     RECT  20.543 69.84 20.579 70.056 ;
     RECT  20.543 71.046 20.579 71.064 ;
     RECT  20.579 40.068 20.615 47.844 ;
     RECT  20.579 64.368 20.615 64.386 ;
     RECT  20.579 70.038 20.615 70.056 ;
     RECT  20.543 32.004 20.651 35.262 ;
     RECT  20.615 40.068 20.651 43.29 ;
     RECT  19.44 51.102 20.803 51.12 ;
     RECT  20.507 51.876 20.803 51.894 ;
     RECT  20.615 44.154 20.831 47.844 ;
     RECT  19.44 49.824 20.839 50.31 ;
     RECT  20.803 51.102 20.839 51.894 ;
     RECT  20.831 44.154 20.867 46.908 ;
     RECT  20.867 44.154 20.903 45.414 ;
     RECT  20.507 22.716 20.911 22.734 ;
     RECT  19.44 58.428 20.911 58.446 ;
     RECT  20.651 32.004 20.939 34.614 ;
     RECT  20.939 32.004 20.975 34.524 ;
     RECT  20.903 44.316 20.975 45.414 ;
     RECT  20.471 48.636 20.975 48.996 ;
     RECT  20.839 49.824 20.975 51.894 ;
     RECT  20.471 53.298 20.975 53.316 ;
     RECT  19.44 17.856 21.011 18.414 ;
     RECT  20.507 25.056 21.011 28.404 ;
     RECT  20.975 32.004 21.011 33.372 ;
     RECT  20.651 40.536 21.011 43.29 ;
     RECT  20.975 51.876 21.011 51.894 ;
     RECT  20.975 34.506 21.047 34.524 ;
     RECT  20.911 22.716 21.083 23.274 ;
     RECT  20.543 36.252 21.083 38.664 ;
     RECT  21.011 40.536 21.083 42.354 ;
     RECT  20.911 58.428 21.091 58.824 ;
     RECT  21.083 40.536 21.119 42.174 ;
     RECT  20.867 46.161 21.119 46.908 ;
     RECT  20.975 49.824 21.119 51.039 ;
     RECT  21.055 20.358 21.155 20.376 ;
     RECT  20.543 29.916 21.155 30.024 ;
     RECT  21.119 49.986 21.191 51.039 ;
     RECT  21.083 38.106 21.227 38.664 ;
     RECT  21.011 43.272 21.227 43.29 ;
     RECT  20.975 48.636 21.227 48.654 ;
     RECT  20.435 13.536 21.235 14.274 ;
     RECT  21.119 40.95 21.263 42.174 ;
     RECT  20.543 60.552 21.271 61.029 ;
     RECT  21.011 26.406 21.299 28.404 ;
     RECT  21.011 32.004 21.299 33.264 ;
     RECT  21.083 36.252 21.299 37.314 ;
     RECT  20.507 10.476 21.307 10.692 ;
     RECT  20.507 11.448 21.307 11.97 ;
     RECT  20.507 21.816 21.335 21.834 ;
     RECT  20.975 44.928 21.335 45.414 ;
     RECT  20.543 56.646 21.343 56.979 ;
     RECT  21.235 13.104 21.371 14.274 ;
     RECT  21.235 17.082 21.371 17.1 ;
     RECT  20.507 24.246 21.371 24.264 ;
     RECT  21.155 30.006 21.371 30.024 ;
     RECT  21.299 37.296 21.371 37.314 ;
     RECT  21.271 60.471 21.371 61.029 ;
     RECT  20.507 9.396 21.407 9.414 ;
     RECT  21.299 36.252 21.407 36.54 ;
     RECT  21.119 46.386 21.407 46.908 ;
     RECT  20.831 47.826 21.407 47.844 ;
     RECT  21.011 25.056 21.415 25.434 ;
     RECT  21.307 10.476 21.443 11.97 ;
     RECT  21.343 56.232 21.443 56.979 ;
     RECT  21.343 64.98 21.443 65.079 ;
     RECT  21.091 58.392 21.451 58.824 ;
     RECT  21.299 32.346 21.479 33.264 ;
     RECT  21.407 36.252 21.479 36.414 ;
     RECT  21.335 44.928 21.479 45.018 ;
     RECT  21.407 46.746 21.479 46.908 ;
     RECT  21.191 50.436 21.479 51.039 ;
     RECT  21.443 56.808 21.479 56.979 ;
     RECT  21.371 61.011 21.479 61.029 ;
     RECT  21.415 30.771 21.487 30.789 ;
     RECT  19.967 76.896 21.487 76.914 ;
     RECT  20.255 78.066 21.487 78.084 ;
     RECT  19.967 2.736 21.515 2.754 ;
     RECT  20.507 4.266 21.515 4.284 ;
     RECT  20.507 5.31 21.515 6.138 ;
     RECT  20.507 7.056 21.515 7.074 ;
     RECT  20.507 8.046 21.515 8.064 ;
     RECT  21.443 10.674 21.515 10.854 ;
     RECT  21.443 11.79 21.515 11.808 ;
     RECT  21.371 13.536 21.515 14.274 ;
     RECT  20.435 15.156 21.515 15.714 ;
     RECT  21.083 22.716 21.515 22.734 ;
     RECT  21.415 24.984 21.515 25.434 ;
     RECT  21.299 27.576 21.515 28.404 ;
     RECT  21.479 36.252 21.515 36.27 ;
     RECT  21.227 38.106 21.515 38.124 ;
     RECT  21.415 38.952 21.515 38.97 ;
     RECT  21.263 40.95 21.515 41.94 ;
     RECT  21.415 53.028 21.515 53.046 ;
     RECT  21.451 58.392 21.515 58.914 ;
     RECT  21.443 64.98 21.515 64.998 ;
     RECT  21.487 76.896 21.515 78.084 ;
     RECT  21.515 10.836 21.551 10.854 ;
     RECT  21.515 24.984 21.551 25.074 ;
     RECT  21.515 58.896 21.551 58.914 ;
     RECT  21.515 5.778 21.587 5.796 ;
     RECT  21.515 14.256 21.587 14.274 ;
     RECT  21.011 18.396 21.587 18.414 ;
     RECT  21.487 30.69 21.587 30.789 ;
     RECT  21.479 33.201 21.587 33.219 ;
     RECT  21.515 40.95 21.587 41.094 ;
     RECT  21.515 41.841 21.587 41.94 ;
     RECT  21.479 46.89 21.587 46.908 ;
     RECT  21.479 50.526 21.587 51.039 ;
     RECT  21.479 56.844 21.587 56.934 ;
     RECT  21.515 77.598 21.587 77.616 ;
    LAYER M3 ;
     RECT  12.87 0.012 12.96 0.037 ;
     RECT  12.852 0.037 12.978 0.043 ;
     RECT  12.564 0.043 12.978 0.173 ;
     RECT  16.884 0.715 16.902 1.291 ;
     RECT  19.728 1.147 19.746 1.435 ;
     RECT  19.656 1.435 19.746 1.579 ;
     RECT  12.96 0.173 12.978 2.143 ;
     RECT  17.928 1.867 17.946 2.143 ;
     RECT  5.115 2.143 5.205 2.191 ;
     RECT  12.96 2.143 13.305 2.255 ;
     RECT  2.415 2.143 2.505 2.413 ;
     RECT  7.815 2.143 7.905 2.413 ;
     RECT  10.515 2.143 10.605 2.413 ;
     RECT  13.215 2.255 13.305 2.413 ;
     RECT  15.915 2.143 16.005 2.413 ;
     RECT  16.884 1.291 17.01 2.413 ;
     RECT  17.928 2.143 18.705 2.413 ;
     RECT  17.928 2.413 18.897 2.443 ;
     RECT  19.656 1.579 20.286 2.443 ;
     RECT  15.915 2.413 17.01 2.539 ;
     RECT  17.928 2.443 20.286 2.539 ;
     RECT  15.915 2.539 20.286 2.573 ;
     RECT  21.456 2.299 21.474 2.587 ;
     RECT  5.115 2.191 5.454 2.731 ;
     RECT  21.456 2.587 21.51 2.759 ;
     RECT  2.415 2.413 2.697 3.019 ;
     RECT  5.115 2.731 5.598 3.037 ;
     RECT  5.115 3.037 5.634 3.181 ;
     RECT  6.948 3.109 6.966 3.181 ;
     RECT  7.815 2.413 8.097 3.181 ;
     RECT  10.515 2.413 10.797 3.181 ;
     RECT  11.592 0.859 11.61 3.181 ;
     RECT  8.964 3.181 8.982 3.299 ;
     RECT  10.515 3.181 11.61 3.299 ;
     RECT  5.115 3.181 5.742 3.301 ;
     RECT  5.112 3.301 5.742 3.307 ;
     RECT  6.948 3.181 8.097 3.307 ;
     RECT  0.18 3.307 0.198 3.343 ;
     RECT  0.18 3.343 0.27 3.389 ;
     RECT  0.18 3.389 0.198 3.451 ;
     RECT  15.915 2.573 18.897 3.451 ;
     RECT  19.656 2.573 20.286 3.451 ;
     RECT  0.108 3.451 0.198 3.479 ;
     RECT  0.108 3.479 0.126 3.488 ;
     RECT  4.068 3.181 4.086 3.541 ;
     RECT  5.112 3.307 8.55 3.569 ;
     RECT  2.304 3.019 2.697 3.721 ;
     RECT  4.068 3.541 4.374 3.721 ;
     RECT  5.112 3.569 8.298 3.721 ;
     RECT  2.304 3.721 3.258 3.773 ;
     RECT  11.592 3.299 11.61 3.811 ;
     RECT  4.068 3.721 8.298 3.839 ;
     RECT  4.068 3.839 8.154 3.883 ;
     RECT  15.12 1.003 15.138 3.955 ;
     RECT  15.915 3.451 20.286 3.955 ;
     RECT  2.304 3.773 2.79 4.019 ;
     RECT  21.456 2.759 21.474 4.027 ;
     RECT  15.12 3.955 20.286 4.117 ;
     RECT  21.42 4.027 21.474 4.157 ;
     RECT  21.456 4.157 21.474 4.171 ;
     RECT  10.515 3.299 10.797 4.189 ;
     RECT  14.832 4.117 20.286 4.217 ;
     RECT  3.996 3.883 8.154 4.253 ;
     RECT  9.324 4.189 9.342 4.261 ;
     RECT  15.12 4.217 20.286 4.315 ;
     RECT  15.12 4.315 20.502 4.379 ;
     RECT  9.144 4.261 9.342 4.451 ;
     RECT  3.996 4.253 8.097 4.531 ;
     RECT  10.515 4.189 10.854 4.621 ;
     RECT  10.44 4.621 10.854 4.721 ;
     RECT  9.144 4.451 9.162 4.829 ;
     RECT  21.456 4.171 21.51 4.891 ;
     RECT  2.304 4.019 2.697 4.987 ;
     RECT  3.42 4.531 8.097 4.987 ;
     RECT  10.515 4.721 10.854 5.021 ;
     RECT  21.42 4.891 21.51 5.035 ;
     RECT  13.215 2.413 13.497 5.179 ;
     RECT  21.384 5.035 21.51 5.323 ;
     RECT  2.304 4.987 8.097 5.357 ;
     RECT  2.304 5.357 3.006 5.495 ;
     RECT  13.215 5.179 13.95 5.575 ;
     RECT  15.12 4.379 20.286 5.611 ;
     RECT  3.996 5.357 8.097 5.701 ;
     RECT  8.892 5.611 8.91 5.701 ;
     RECT  15.12 5.611 20.502 5.707 ;
     RECT  21.348 5.323 21.51 5.773 ;
     RECT  3.996 5.701 8.982 5.837 ;
     RECT  14.832 5.707 20.502 5.837 ;
     RECT  3.996 5.837 8.442 5.873 ;
     RECT  13.176 5.575 13.95 5.881 ;
     RECT  21.348 5.773 21.582 6.043 ;
     RECT  9.324 6.091 9.342 6.151 ;
     RECT  21.312 6.043 21.582 6.221 ;
     RECT  13.104 5.881 13.95 6.305 ;
     RECT  10.515 5.021 10.797 6.349 ;
     RECT  4.032 5.873 6.966 6.413 ;
     RECT  10.26 6.349 10.797 6.421 ;
     RECT  2.415 5.495 3.006 6.475 ;
     RECT  14.868 5.837 20.502 6.539 ;
     RECT  14.868 6.539 20.43 6.583 ;
     RECT  4.068 6.413 6.966 6.619 ;
     RECT  7.74 5.873 8.442 6.619 ;
     RECT  2.304 6.475 3.006 6.691 ;
     RECT  4.068 6.619 8.514 6.691 ;
     RECT  9.324 6.151 9.414 6.691 ;
     RECT  10.188 6.421 10.797 6.691 ;
     RECT  0.144 4.603 0.162 6.797 ;
     RECT  4.068 6.691 10.797 6.953 ;
     RECT  4.392 6.953 10.797 7.133 ;
     RECT  9.072 7.133 10.797 7.159 ;
     RECT  2.304 6.691 3.15 7.189 ;
     RECT  13.215 6.305 13.95 7.231 ;
     RECT  14.832 6.583 20.43 7.231 ;
     RECT  2.304 7.189 3.51 7.321 ;
     RECT  13.215 7.231 20.43 7.339 ;
     RECT  13.215 7.339 20.502 7.387 ;
     RECT  13.14 7.387 20.502 7.427 ;
     RECT  2.268 7.321 3.51 7.457 ;
     RECT  21.384 6.221 21.582 7.483 ;
     RECT  9.072 7.159 10.854 7.627 ;
     RECT  11.592 3.811 12.33 7.627 ;
     RECT  21.312 7.483 21.582 7.661 ;
     RECT  4.392 7.133 8.097 7.771 ;
     RECT  14.688 7.427 20.502 7.799 ;
     RECT  4.104 7.771 8.097 7.861 ;
     RECT  9.072 7.627 12.33 7.861 ;
     RECT  4.104 7.861 12.33 7.889 ;
     RECT  4.392 7.889 12.33 7.949 ;
     RECT  13.215 7.427 13.95 8.069 ;
     RECT  2.268 7.457 3.33 8.203 ;
     RECT  2.268 8.203 3.438 8.465 ;
     RECT  21.348 7.661 21.582 8.491 ;
     RECT  9.072 7.949 12.33 8.779 ;
     RECT  13.215 8.069 13.662 8.779 ;
     RECT  14.688 7.799 20.43 8.779 ;
     RECT  4.392 7.949 8.298 8.851 ;
     RECT  14.652 8.779 20.43 8.923 ;
     RECT  14.652 8.923 20.502 8.969 ;
     RECT  4.248 8.851 8.298 9.085 ;
     RECT  9.072 8.779 13.662 9.085 ;
     RECT  14.652 8.969 20.43 9.085 ;
     RECT  2.268 8.465 2.862 9.211 ;
     RECT  4.068 9.085 8.298 9.239 ;
     RECT  0.144 8.059 0.162 9.341 ;
     RECT  2.268 9.211 2.898 9.419 ;
     RECT  9.072 9.085 20.43 9.589 ;
     RECT  4.248 9.239 8.298 9.625 ;
     RECT  9.036 9.589 20.43 9.625 ;
     RECT  4.248 9.625 20.43 10.075 ;
     RECT  2.268 9.419 2.862 10.201 ;
     RECT  1.692 10.201 2.862 10.291 ;
     RECT  4.248 10.075 20.502 10.327 ;
     RECT  1.692 10.291 3.042 10.471 ;
     RECT  3.816 10.327 20.502 10.471 ;
     RECT  0.144 10.699 0.162 10.829 ;
     RECT  1.692 10.471 20.502 11.129 ;
     RECT  21.312 8.491 21.582 11.515 ;
     RECT  1.692 11.129 20.43 11.821 ;
     RECT  1.656 11.821 20.43 12.361 ;
     RECT  1.584 12.361 20.43 12.379 ;
     RECT  21.276 11.515 21.582 13.099 ;
     RECT  0.108 13.819 0.126 13.901 ;
     RECT  21.24 13.099 21.582 14.279 ;
     RECT  0.144 14.539 0.162 15.053 ;
     RECT  1.584 12.379 20.502 15.115 ;
     RECT  21.24 14.279 21.546 15.115 ;
     RECT  1.584 15.115 21.546 16.987 ;
     RECT  1.116 16.987 21.546 17.117 ;
     RECT  0.144 16.699 0.162 17.549 ;
     RECT  1.584 17.117 21.546 17.651 ;
     RECT  3.564 17.651 21.546 18.391 ;
     RECT  1.584 17.651 2.79 18.571 ;
     RECT  3.564 18.391 21.582 18.571 ;
     RECT  0.144 18.859 0.162 21.053 ;
     RECT  0.324 22.603 0.342 22.781 ;
     RECT  0.144 22.891 0.162 22.928 ;
     RECT  1.584 18.571 21.582 25.321 ;
     RECT  0.144 25.339 0.162 25.949 ;
     RECT  1.548 25.321 21.582 26.671 ;
     RECT  1.512 26.671 21.582 26.923 ;
     RECT  1.152 26.923 21.582 27.101 ;
     RECT  0.144 27.067 0.162 27.197 ;
     RECT  0.54 27.913 0.558 27.965 ;
     RECT  1.512 27.101 21.582 28.651 ;
     RECT  1.152 28.651 21.582 28.781 ;
     RECT  0.144 29.947 0.162 30.145 ;
     RECT  0.144 30.145 0.558 30.269 ;
     RECT  0.144 30.269 0.162 30.941 ;
     RECT  0.144 31.723 0.162 31.853 ;
     RECT  0.144 33.307 0.162 33.437 ;
     RECT  0.144 34.459 0.162 35.261 ;
     RECT  0.288 35.707 0.486 35.771 ;
     RECT  0.396 35.771 0.486 35.789 ;
     RECT  0.468 35.789 0.486 35.885 ;
     RECT  0.144 37.291 0.162 37.421 ;
     RECT  0.18 39.163 0.198 39.293 ;
     RECT  0.144 40.459 0.162 40.877 ;
     RECT  0.144 42.619 0.162 43.229 ;
     RECT  0.18 44.779 0.198 44.909 ;
     RECT  0.144 45.259 0.162 46.061 ;
     RECT  0.144 46.939 0.162 48.22 ;
     RECT  0.108 48.22 0.198 48.413 ;
     RECT  0.144 48.413 0.198 48.461 ;
     RECT  0.144 48.461 0.162 48.989 ;
     RECT  0.144 49.963 0.162 50.093 ;
     RECT  0.144 51.739 0.162 51.869 ;
     RECT  0.144 55.291 0.162 55.531 ;
     RECT  0.144 55.531 0.234 55.589 ;
     RECT  0.144 55.589 0.162 57.149 ;
     RECT  0.54 58.117 0.558 58.507 ;
     RECT  0.144 58.507 0.558 58.637 ;
     RECT  0.54 58.637 0.558 59.501 ;
     RECT  0.144 60.475 0.162 60.605 ;
     RECT  0.108 61.051 0.126 61.151 ;
     RECT  0.144 62.539 0.162 62.669 ;
     RECT  0.144 63.595 0.162 63.821 ;
     RECT  0.144 65.083 0.162 65.213 ;
     RECT  0.108 66.085 0.126 66.125 ;
     RECT  1.512 28.781 21.582 66.659 ;
     RECT  1.512 66.659 2.697 67.405 ;
     RECT  3.456 66.659 21.582 67.405 ;
     RECT  0.54 68.377 0.558 68.539 ;
     RECT  0.144 68.539 0.558 69.005 ;
     RECT  1.512 67.405 21.582 69.251 ;
     RECT  0.144 69.005 0.162 69.821 ;
     RECT  1.62 69.251 21.582 70.133 ;
     RECT  2.232 70.133 21.582 70.439 ;
     RECT  2.304 70.439 21.582 70.733 ;
     RECT  2.304 70.733 2.754 70.835 ;
     RECT  0.144 70.699 0.162 70.925 ;
     RECT  2.304 70.835 2.697 72.283 ;
     RECT  2.268 72.283 2.697 72.391 ;
     RECT  3.528 70.733 21.582 72.391 ;
     RECT  2.268 72.391 21.582 72.455 ;
     RECT  0.54 73.507 0.558 73.613 ;
     RECT  0.18 73.723 0.198 73.841 ;
     RECT  2.304 72.455 21.582 74.477 ;
     RECT  2.304 74.477 20.286 74.885 ;
     RECT  0.144 74.731 0.162 74.957 ;
     RECT  18.396 74.885 20.286 75.631 ;
     RECT  21.096 74.477 21.582 75.631 ;
     RECT  2.304 74.885 17.262 75.659 ;
     RECT  3.636 75.659 17.262 75.835 ;
     RECT  18.396 75.631 21.582 75.835 ;
     RECT  3.636 75.835 21.582 75.917 ;
     RECT  3.636 75.917 20.25 76.061 ;
     RECT  3.636 76.061 13.497 76.109 ;
     RECT  0.144 75.883 0.162 76.459 ;
     RECT  2.304 75.659 2.898 76.459 ;
     RECT  3.636 76.109 11.25 76.459 ;
     RECT  2.304 76.459 11.25 76.469 ;
     RECT  0.144 76.459 0.198 76.477 ;
     RECT  0.144 76.477 0.27 76.541 ;
     RECT  0.144 76.541 0.198 76.585 ;
     RECT  0.108 76.585 0.198 76.613 ;
     RECT  0.108 76.613 0.162 76.637 ;
     RECT  2.304 76.469 10.89 76.739 ;
     RECT  14.256 76.061 20.25 76.775 ;
     RECT  2.304 76.739 10.797 77.045 ;
     RECT  14.616 76.775 20.25 77.069 ;
     RECT  21.096 75.917 21.582 77.213 ;
     RECT  21.492 77.213 21.582 77.621 ;
     RECT  2.415 77.045 10.797 77.899 ;
     RECT  14.616 77.069 17.694 77.899 ;
     RECT  18.432 77.069 20.25 77.899 ;
     RECT  2.304 77.899 10.797 77.963 ;
     RECT  14.616 77.899 20.25 77.999 ;
     RECT  2.415 77.963 10.797 78.089 ;
     RECT  12.348 76.109 13.497 78.359 ;
     RECT  21.492 77.621 21.51 78.365 ;
     RECT  14.616 77.999 19.962 78.629 ;
     RECT  12.78 78.359 13.497 78.665 ;
     RECT  14.616 78.629 17.874 78.665 ;
     RECT  18.612 78.629 19.962 78.665 ;
     RECT  9.972 78.089 10.797 78.737 ;
     RECT  10.044 78.737 10.797 78.773 ;
     RECT  12.96 78.665 13.497 78.781 ;
     RECT  14.616 78.665 17.262 78.781 ;
     RECT  0.144 76.637 0.162 78.797 ;
     RECT  18.615 78.665 19.962 78.797 ;
     RECT  2.415 78.089 8.658 78.899 ;
     RECT  6.552 78.899 8.658 78.934 ;
     RECT  18.615 78.797 19.422 78.941 ;
     RECT  2.415 78.899 5.778 79.015 ;
     RECT  6.552 78.934 8.694 79.079 ;
     RECT  2.304 79.015 5.778 79.085 ;
     RECT  6.552 79.079 8.442 79.169 ;
     RECT  0.504 78.907 0.522 79.213 ;
     RECT  12.96 78.781 17.262 79.313 ;
     RECT  15.915 79.313 17.262 79.439 ;
     RECT  12.96 79.313 14.634 79.511 ;
     RECT  12.96 79.511 14.022 79.583 ;
     RECT  15.915 79.439 17.046 79.619 ;
     RECT  6.552 79.169 8.097 79.667 ;
     RECT  10.515 78.773 10.797 79.667 ;
     RECT  12.96 79.583 13.497 79.667 ;
     RECT  15.915 79.619 16.938 79.667 ;
     RECT  18.615 78.941 18.897 79.667 ;
     RECT  12.96 79.667 13.374 79.681 ;
     RECT  2.376 79.085 5.778 79.709 ;
     RECT  6.552 79.667 7.974 79.709 ;
     RECT  16.812 79.667 16.938 79.709 ;
     RECT  0.504 79.213 0.558 79.717 ;
     RECT  5.076 79.709 5.778 79.753 ;
     RECT  6.552 79.709 6.786 79.753 ;
     RECT  12.564 79.681 13.374 79.757 ;
     RECT  12.744 79.757 13.374 79.781 ;
     RECT  0.504 79.717 1.17 79.819 ;
     RECT  5.076 79.753 6.786 79.853 ;
     RECT  5.115 79.853 6.786 79.937 ;
     RECT  7.815 79.709 7.905 79.937 ;
     RECT  10.515 79.667 10.605 79.937 ;
     RECT  13.215 79.781 13.374 79.937 ;
     RECT  15.915 79.667 16.005 79.937 ;
     RECT  18.615 79.667 18.705 79.937 ;
     RECT  0.144 79.819 1.17 79.949 ;
     RECT  5.688 79.937 6.786 80.093 ;
     RECT  0.504 79.949 1.17 80.381 ;
     RECT  2.376 79.709 3.726 80.525 ;
     RECT  6.768 80.093 6.786 80.669 ;
     RECT  2.376 80.525 3.114 80.813 ;
     RECT  1.152 80.381 1.17 80.957 ;
     RECT  13.356 79.937 13.374 80.957 ;
     RECT  3.096 80.813 3.114 81.101 ;
     RECT  5.688 80.093 5.706 81.245 ;
    LAYER M4 ;
     RECT  0.084 3.024 2.408 3.048 ;
     RECT  0.06 3.048 2.408 3.168 ;
     RECT  0.084 3.168 2.408 3.192 ;
     RECT  0.06 3.192 2.408 3.312 ;
     RECT  0.084 3.312 2.408 3.336 ;
     RECT  0.06 3.336 2.408 3.456 ;
     RECT  0.084 3.456 2.408 3.48 ;
     RECT  0.06 3.48 2.408 3.6 ;
     RECT  0.084 3.6 2.408 3.624 ;
     RECT  0.06 3.624 2.408 3.744 ;
     RECT  0.084 3.744 2.408 3.768 ;
     RECT  0.06 3.768 2.408 3.888 ;
     RECT  0.084 3.888 2.408 3.912 ;
     RECT  0.06 3.912 2.408 4.032 ;
     RECT  0.084 4.032 2.408 4.056 ;
     RECT  0.06 4.056 2.408 4.176 ;
     RECT  0.084 4.176 2.408 4.2 ;
     RECT  0.06 4.2 2.408 4.32 ;
     RECT  0.084 4.32 2.408 4.344 ;
     RECT  0.06 4.344 2.408 4.464 ;
     RECT  0.084 4.464 2.408 4.488 ;
     RECT  0.06 4.488 2.408 4.608 ;
     RECT  0.084 4.608 2.408 4.632 ;
     RECT  0.06 4.632 2.408 4.752 ;
     RECT  0.084 4.752 2.408 4.776 ;
     RECT  0.06 4.776 2.408 4.896 ;
     RECT  0.084 4.896 2.408 4.92 ;
     RECT  0.06 4.92 2.408 5.04 ;
     RECT  0.084 5.04 2.408 5.064 ;
     RECT  0.06 5.064 2.408 5.184 ;
     RECT  0.084 5.184 2.408 5.208 ;
     RECT  0.06 5.208 2.408 5.328 ;
     RECT  0.084 5.328 2.408 5.352 ;
     RECT  0.06 5.352 2.408 5.472 ;
     RECT  0.084 5.472 2.408 5.496 ;
     RECT  0.06 5.496 2.408 5.616 ;
     RECT  0.084 5.616 2.408 5.64 ;
     RECT  0.06 5.64 2.408 5.76 ;
     RECT  0.084 5.76 2.408 5.784 ;
     RECT  0.06 5.784 2.408 5.904 ;
     RECT  0.084 5.904 2.408 5.928 ;
     RECT  0.06 5.928 2.408 6.048 ;
     RECT  0.084 6.048 2.408 6.072 ;
     RECT  0.06 6.072 2.408 6.192 ;
     RECT  0.084 6.192 2.408 6.216 ;
     RECT  0.06 6.216 2.408 6.336 ;
     RECT  0.084 6.336 2.408 6.36 ;
     RECT  0.06 6.36 2.408 6.48 ;
     RECT  0.084 6.48 2.408 6.504 ;
     RECT  0.06 6.504 2.408 6.624 ;
     RECT  0.084 6.624 2.408 6.648 ;
     RECT  0.06 6.648 2.408 6.768 ;
     RECT  0.084 6.768 2.408 6.792 ;
     RECT  0.06 6.792 2.408 6.912 ;
     RECT  0.084 6.912 2.408 6.936 ;
     RECT  0.06 6.936 2.408 7.056 ;
     RECT  0.084 7.056 2.408 7.08 ;
     RECT  0.06 7.08 2.408 7.2 ;
     RECT  0.084 7.2 2.408 7.224 ;
     RECT  0.06 7.224 2.408 7.344 ;
     RECT  0.084 7.344 2.408 7.368 ;
     RECT  0.06 7.368 2.408 7.488 ;
     RECT  0.084 7.488 2.408 7.512 ;
     RECT  0.06 7.512 2.408 7.632 ;
     RECT  0.084 7.632 2.408 7.656 ;
     RECT  0.06 7.656 2.408 7.776 ;
     RECT  0.084 7.776 2.408 7.8 ;
     RECT  0.06 7.8 2.408 7.92 ;
     RECT  0.084 7.92 2.408 7.944 ;
     RECT  0.06 7.944 2.408 8.064 ;
     RECT  0.084 8.064 2.408 8.088 ;
     RECT  0.06 8.088 2.408 8.208 ;
     RECT  0.084 8.208 2.408 8.232 ;
     RECT  0.06 8.232 2.408 8.352 ;
     RECT  0.084 8.352 2.408 8.376 ;
     RECT  0.06 8.376 2.408 8.496 ;
     RECT  0.084 8.496 2.408 8.52 ;
     RECT  0.06 8.52 2.408 8.64 ;
     RECT  0.084 8.64 2.408 8.664 ;
     RECT  0.06 8.664 2.408 8.784 ;
     RECT  0.084 8.784 2.408 8.808 ;
     RECT  0.06 8.808 2.408 8.928 ;
     RECT  0.084 8.928 2.408 8.952 ;
     RECT  0.06 8.952 2.408 9.072 ;
     RECT  0.084 9.072 2.408 9.096 ;
     RECT  0.06 9.096 2.408 9.216 ;
     RECT  0.084 9.216 2.408 9.24 ;
     RECT  0.06 9.24 2.408 9.36 ;
     RECT  0.084 9.36 2.408 9.384 ;
     RECT  0.06 9.384 2.408 9.504 ;
     RECT  0.084 9.504 2.408 9.528 ;
     RECT  0.06 9.528 2.408 9.648 ;
     RECT  0.084 9.648 2.408 9.672 ;
     RECT  0.06 9.672 2.408 9.792 ;
     RECT  0.084 9.792 2.408 9.816 ;
     RECT  0.06 9.816 2.408 9.936 ;
     RECT  0.084 9.936 2.408 9.96 ;
     RECT  0.06 9.96 2.408 10.08 ;
     RECT  0.084 10.08 2.408 10.104 ;
     RECT  0.06 10.104 2.408 10.224 ;
     RECT  0.084 10.224 2.408 10.248 ;
     RECT  0.06 10.248 2.408 10.368 ;
     RECT  0.084 10.368 2.408 10.392 ;
     RECT  0.06 10.392 2.408 10.512 ;
     RECT  0.084 10.512 2.408 10.536 ;
     RECT  0.06 10.536 2.408 10.656 ;
     RECT  0.084 10.656 2.408 10.68 ;
     RECT  0.06 10.68 2.408 10.8 ;
     RECT  0.084 10.8 2.408 10.824 ;
     RECT  0.06 10.824 2.408 10.944 ;
     RECT  0.084 10.944 2.408 10.968 ;
     RECT  0.06 10.968 2.408 11.088 ;
     RECT  0.084 11.088 2.408 11.112 ;
     RECT  0.06 11.112 2.408 11.232 ;
     RECT  0.084 11.232 2.408 11.256 ;
     RECT  0.06 11.256 2.408 11.376 ;
     RECT  0.084 11.376 2.408 11.4 ;
     RECT  0.06 11.4 2.408 11.52 ;
     RECT  0.084 11.52 2.408 11.544 ;
     RECT  0.06 11.544 2.408 11.664 ;
     RECT  0.084 11.664 2.408 11.688 ;
     RECT  0.06 11.688 2.408 11.808 ;
     RECT  0.084 11.808 2.408 11.832 ;
     RECT  0.06 11.832 2.408 11.952 ;
     RECT  0.084 11.952 2.408 11.976 ;
     RECT  0.06 11.976 2.408 12.096 ;
     RECT  0.084 12.096 2.408 12.12 ;
     RECT  0.06 12.12 2.408 12.24 ;
     RECT  0.084 12.24 2.408 12.264 ;
     RECT  0.06 12.264 2.408 12.384 ;
     RECT  0.084 12.384 2.408 12.408 ;
     RECT  0.06 12.408 2.408 12.528 ;
     RECT  0.084 12.528 2.408 12.552 ;
     RECT  0.06 12.552 2.408 12.672 ;
     RECT  0.084 12.672 2.408 12.696 ;
     RECT  0.06 12.696 2.408 12.816 ;
     RECT  0.084 12.816 2.408 12.84 ;
     RECT  0.06 12.84 2.408 12.96 ;
     RECT  0.084 12.96 2.408 12.984 ;
     RECT  0.06 12.984 2.408 13.104 ;
     RECT  0.084 13.104 2.408 13.128 ;
     RECT  0.06 13.128 2.408 13.248 ;
     RECT  0.084 13.248 2.408 13.272 ;
     RECT  0.06 13.272 2.408 13.392 ;
     RECT  0.084 13.392 2.408 13.416 ;
     RECT  0.06 13.416 2.408 13.536 ;
     RECT  0.084 13.536 2.408 13.56 ;
     RECT  0.06 13.56 2.408 13.68 ;
     RECT  0.084 13.68 2.408 13.704 ;
     RECT  0.06 13.704 2.408 13.824 ;
     RECT  0.084 13.824 2.408 13.848 ;
     RECT  0.06 13.848 2.408 13.968 ;
     RECT  0.084 13.968 2.408 13.992 ;
     RECT  0.06 13.992 2.408 14.112 ;
     RECT  0.084 14.112 2.408 14.136 ;
     RECT  0.06 14.136 2.408 14.256 ;
     RECT  0.084 14.256 2.408 14.28 ;
     RECT  0.06 14.28 2.408 14.4 ;
     RECT  0.084 14.4 2.408 14.424 ;
     RECT  0.06 14.424 2.408 14.544 ;
     RECT  0.084 14.544 2.408 14.568 ;
     RECT  0.06 14.568 2.408 14.688 ;
     RECT  0.084 14.688 2.408 14.712 ;
     RECT  0.06 14.712 2.408 14.832 ;
     RECT  0.084 14.832 2.408 14.856 ;
     RECT  0.06 14.856 2.408 14.976 ;
     RECT  0.084 14.976 2.408 15 ;
     RECT  0.06 15 2.408 15.12 ;
     RECT  0.084 15.12 2.408 15.144 ;
     RECT  0.06 15.144 2.408 15.264 ;
     RECT  0.084 15.264 2.408 15.288 ;
     RECT  0.06 15.288 2.408 15.408 ;
     RECT  0.084 15.408 2.408 15.432 ;
     RECT  0.06 15.432 2.408 15.552 ;
     RECT  0.084 15.552 2.408 15.576 ;
     RECT  0.06 15.576 2.408 15.696 ;
     RECT  0.084 15.696 2.408 15.72 ;
     RECT  0.06 15.72 2.408 15.84 ;
     RECT  0.084 15.84 2.408 15.864 ;
     RECT  0.06 15.864 2.408 15.984 ;
     RECT  0.084 15.984 2.408 16.008 ;
     RECT  0.06 16.008 2.408 16.128 ;
     RECT  0.084 16.128 2.408 16.152 ;
     RECT  0.06 16.152 2.408 16.272 ;
     RECT  0.084 16.272 2.408 16.296 ;
     RECT  0.06 16.296 2.408 16.416 ;
     RECT  0.084 16.416 2.408 16.44 ;
     RECT  0.06 16.44 2.408 16.56 ;
     RECT  0.084 16.56 2.408 16.584 ;
     RECT  0.06 16.584 2.408 16.704 ;
     RECT  0.084 16.704 2.408 16.728 ;
     RECT  0.06 16.728 2.408 16.848 ;
     RECT  0.084 16.848 2.408 16.872 ;
     RECT  0.06 16.872 2.408 16.992 ;
     RECT  0.084 16.992 2.408 17.016 ;
     RECT  0.06 17.016 2.408 17.136 ;
     RECT  0.084 17.136 2.408 17.16 ;
     RECT  0.06 17.16 2.408 17.28 ;
     RECT  0.084 17.28 2.408 17.304 ;
     RECT  0.06 17.304 2.408 17.424 ;
     RECT  0.084 17.424 2.408 17.448 ;
     RECT  0.06 17.448 2.408 17.568 ;
     RECT  0.084 17.568 2.408 17.592 ;
     RECT  0.06 17.592 2.408 17.712 ;
     RECT  0.084 17.712 2.408 17.736 ;
     RECT  0.06 17.736 2.408 17.856 ;
     RECT  0.084 17.856 2.408 17.88 ;
     RECT  0.06 17.88 2.408 18 ;
     RECT  0.084 18 2.408 18.024 ;
     RECT  0.06 18.024 2.408 18.144 ;
     RECT  0.084 18.144 2.408 18.168 ;
     RECT  0.06 18.168 2.408 18.288 ;
     RECT  0.084 18.288 2.408 18.312 ;
     RECT  0.06 18.312 2.408 18.432 ;
     RECT  0.084 18.432 2.408 18.456 ;
     RECT  0.06 18.456 2.408 18.576 ;
     RECT  0.084 18.576 2.408 18.6 ;
     RECT  0.06 18.6 2.408 18.72 ;
     RECT  0.084 18.72 2.408 18.744 ;
     RECT  0.06 18.744 2.408 18.864 ;
     RECT  0.084 18.864 2.408 18.888 ;
     RECT  0.06 18.888 2.408 19.008 ;
     RECT  0.084 19.008 2.408 19.032 ;
     RECT  0.06 19.032 2.408 19.152 ;
     RECT  0.084 19.152 2.408 19.176 ;
     RECT  0.06 19.176 2.408 19.296 ;
     RECT  0.084 19.296 2.408 19.32 ;
     RECT  0.06 19.32 2.408 19.44 ;
     RECT  0.084 19.44 2.408 19.464 ;
     RECT  0.06 19.464 2.408 19.584 ;
     RECT  0.084 19.584 2.408 19.608 ;
     RECT  0.06 19.608 2.408 19.728 ;
     RECT  0.084 19.728 2.408 19.752 ;
     RECT  0.06 19.752 2.408 19.872 ;
     RECT  0.084 19.872 2.408 19.896 ;
     RECT  0.06 19.896 2.408 20.016 ;
     RECT  0.084 20.016 2.408 20.04 ;
     RECT  0.06 20.04 2.408 20.16 ;
     RECT  0.084 20.16 2.408 20.184 ;
     RECT  0.06 20.184 2.408 20.304 ;
     RECT  0.084 20.304 2.408 20.328 ;
     RECT  0.06 20.328 2.408 20.448 ;
     RECT  0.084 20.448 2.408 20.472 ;
     RECT  0.06 20.472 2.408 20.592 ;
     RECT  0.084 20.592 2.408 20.616 ;
     RECT  0.06 20.616 2.408 20.736 ;
     RECT  0.084 20.736 2.408 20.76 ;
     RECT  0.06 20.76 2.408 20.88 ;
     RECT  0.084 20.88 2.408 20.904 ;
     RECT  0.06 20.904 2.408 21.024 ;
     RECT  0.084 21.024 2.408 21.048 ;
     RECT  0.06 21.048 2.408 21.168 ;
     RECT  0.084 21.168 2.408 21.192 ;
     RECT  0.06 21.192 2.408 21.312 ;
     RECT  0.084 21.312 2.408 21.336 ;
     RECT  0.06 21.336 2.408 21.456 ;
     RECT  0.084 21.456 2.408 21.48 ;
     RECT  0.06 21.48 2.408 21.6 ;
     RECT  0.084 21.6 2.408 21.624 ;
     RECT  0.06 21.624 2.408 21.744 ;
     RECT  0.084 21.744 2.408 21.768 ;
     RECT  0.06 21.768 2.408 21.888 ;
     RECT  0.084 21.888 2.408 21.912 ;
     RECT  0.06 21.912 2.408 22.032 ;
     RECT  0.084 22.032 2.408 22.056 ;
     RECT  0.06 22.056 2.408 22.176 ;
     RECT  0.084 22.176 2.408 22.2 ;
     RECT  0.06 22.2 2.408 22.32 ;
     RECT  0.084 22.32 2.408 22.344 ;
     RECT  0.06 22.344 2.408 22.464 ;
     RECT  0.084 22.464 2.408 22.488 ;
     RECT  0.06 22.488 2.408 22.608 ;
     RECT  0.084 22.608 2.408 22.632 ;
     RECT  0.06 22.632 2.408 22.752 ;
     RECT  0.084 22.752 2.408 22.776 ;
     RECT  0.06 22.776 2.408 22.896 ;
     RECT  0.084 22.896 2.408 22.92 ;
     RECT  0.06 22.92 2.408 23.04 ;
     RECT  0.084 23.04 2.408 23.064 ;
     RECT  0.06 23.064 2.408 23.184 ;
     RECT  0.084 23.184 2.408 23.208 ;
     RECT  0.06 23.208 2.408 23.328 ;
     RECT  0.084 23.328 2.408 23.352 ;
     RECT  0.06 23.352 2.408 23.472 ;
     RECT  0.084 23.472 2.408 23.496 ;
     RECT  0.06 23.496 2.408 23.616 ;
     RECT  0.084 23.616 2.408 23.64 ;
     RECT  0.084 24.912 2.408 24.936 ;
     RECT  0.06 24.936 2.408 25.056 ;
     RECT  0.084 25.056 2.408 25.08 ;
     RECT  0.06 25.08 2.408 25.2 ;
     RECT  0.084 25.2 2.408 25.224 ;
     RECT  0.06 25.224 2.408 25.344 ;
     RECT  0.084 25.344 2.408 25.368 ;
     RECT  0.06 25.368 2.408 25.488 ;
     RECT  0.084 25.488 2.408 25.512 ;
     RECT  0.06 25.512 2.408 25.632 ;
     RECT  0.084 25.632 2.408 25.656 ;
     RECT  0.06 25.656 2.408 25.776 ;
     RECT  0.084 25.776 2.408 25.8 ;
     RECT  0.06 25.8 2.408 25.92 ;
     RECT  0.084 25.92 2.408 25.944 ;
     RECT  0.06 25.944 2.408 26.064 ;
     RECT  0.084 26.064 2.408 26.088 ;
     RECT  0.06 26.088 2.408 26.208 ;
     RECT  0.084 26.208 2.408 26.232 ;
     RECT  0.06 26.232 2.408 26.352 ;
     RECT  0.084 26.352 2.408 26.376 ;
     RECT  0.06 26.376 2.408 26.496 ;
     RECT  0.084 26.496 2.408 26.52 ;
     RECT  0.06 26.52 2.408 26.64 ;
     RECT  0.084 26.64 2.408 26.664 ;
     RECT  0.06 26.664 2.408 26.784 ;
     RECT  0.084 26.784 2.408 26.808 ;
     RECT  0.06 26.808 2.408 26.928 ;
     RECT  0.084 26.928 2.408 26.952 ;
     RECT  0.06 26.952 2.408 27.072 ;
     RECT  0.084 27.072 2.408 27.096 ;
     RECT  0.06 27.096 2.408 27.216 ;
     RECT  0.084 27.216 2.408 27.24 ;
     RECT  0.06 27.24 2.408 27.36 ;
     RECT  0.084 27.36 2.408 27.384 ;
     RECT  0.06 27.384 2.408 27.504 ;
     RECT  0.084 27.504 2.408 27.528 ;
     RECT  0.06 27.528 2.408 27.648 ;
     RECT  0.084 27.648 2.408 27.672 ;
     RECT  0.06 27.672 2.408 27.792 ;
     RECT  0.084 27.792 2.408 27.816 ;
     RECT  0.06 27.816 2.408 27.936 ;
     RECT  0.084 27.936 2.408 27.96 ;
     RECT  0.06 27.96 2.408 28.08 ;
     RECT  0.084 28.08 2.408 28.104 ;
     RECT  0.06 28.104 2.408 28.224 ;
     RECT  0.084 28.224 2.408 28.248 ;
     RECT  0.06 28.248 2.408 28.368 ;
     RECT  0.084 28.368 2.408 28.392 ;
     RECT  0.06 28.392 2.408 28.512 ;
     RECT  0.084 28.512 2.408 28.536 ;
     RECT  0.06 28.536 2.408 28.656 ;
     RECT  0.084 28.656 2.408 28.68 ;
     RECT  0.06 28.68 2.408 28.8 ;
     RECT  0.084 28.8 2.408 28.824 ;
     RECT  0.06 28.824 2.408 28.944 ;
     RECT  0.084 28.944 2.408 28.968 ;
     RECT  0.06 28.968 2.408 29.088 ;
     RECT  0.084 29.088 2.408 29.112 ;
     RECT  0.06 29.112 2.408 29.232 ;
     RECT  0.084 29.232 2.408 29.256 ;
     RECT  0.06 29.256 2.408 29.376 ;
     RECT  0.084 29.376 2.408 29.4 ;
     RECT  0.06 29.4 2.408 29.52 ;
     RECT  0.084 29.52 2.408 29.544 ;
     RECT  0.06 29.544 2.408 29.664 ;
     RECT  0.084 29.664 2.408 29.688 ;
     RECT  0.06 29.688 2.408 29.808 ;
     RECT  0.084 29.808 2.408 29.832 ;
     RECT  0.06 29.832 2.408 29.952 ;
     RECT  0.084 29.952 2.408 29.976 ;
     RECT  0.06 29.976 2.408 30.096 ;
     RECT  0.084 30.096 2.408 30.12 ;
     RECT  0.06 30.12 2.408 30.24 ;
     RECT  0.084 30.24 2.408 30.264 ;
     RECT  0.06 30.264 2.408 30.384 ;
     RECT  0.084 30.384 2.408 30.408 ;
     RECT  0.06 30.408 2.408 30.528 ;
     RECT  0.084 30.528 2.408 30.552 ;
     RECT  0.06 30.552 2.408 30.672 ;
     RECT  0.084 30.672 2.408 30.696 ;
     RECT  0.06 30.696 2.408 30.816 ;
     RECT  0.084 30.816 2.408 30.84 ;
     RECT  0.06 30.84 2.408 30.96 ;
     RECT  0.084 30.96 2.408 30.984 ;
     RECT  0.06 30.984 2.408 31.104 ;
     RECT  0.084 31.104 2.408 31.128 ;
     RECT  0.06 31.128 2.408 31.248 ;
     RECT  0.084 31.248 2.408 31.272 ;
     RECT  0.06 31.272 2.408 31.392 ;
     RECT  0.084 31.392 2.408 31.416 ;
     RECT  0.06 31.416 2.408 31.536 ;
     RECT  0.084 31.536 2.408 31.56 ;
     RECT  0.06 31.56 2.408 31.68 ;
     RECT  0.084 31.68 2.408 31.704 ;
     RECT  0.06 31.704 2.408 31.824 ;
     RECT  0.084 31.824 2.408 31.848 ;
     RECT  0.06 31.848 2.408 31.968 ;
     RECT  0.084 31.968 2.408 31.992 ;
     RECT  0.06 31.992 2.408 32.112 ;
     RECT  0.084 32.112 2.408 32.136 ;
     RECT  0.06 32.136 2.408 32.256 ;
     RECT  0.084 32.256 2.408 32.28 ;
     RECT  0.06 32.28 2.408 32.4 ;
     RECT  0.084 32.4 2.408 32.424 ;
     RECT  0.06 32.424 2.408 32.544 ;
     RECT  0.084 32.544 2.408 32.568 ;
     RECT  0.06 32.568 2.408 32.688 ;
     RECT  0.084 32.688 2.408 32.712 ;
     RECT  0.06 32.712 2.408 32.832 ;
     RECT  0.084 32.832 2.408 32.856 ;
     RECT  0.06 32.856 2.408 32.976 ;
     RECT  0.084 32.976 2.408 33 ;
     RECT  0.06 33 2.408 33.12 ;
     RECT  0.084 33.12 2.408 33.144 ;
     RECT  0.06 33.144 2.408 33.264 ;
     RECT  0.084 33.264 2.408 33.288 ;
     RECT  0.06 33.288 2.408 33.408 ;
     RECT  0.084 33.408 2.408 33.432 ;
     RECT  0.06 33.432 2.408 33.552 ;
     RECT  0.084 33.552 2.408 33.576 ;
     RECT  0.06 33.576 2.408 33.696 ;
     RECT  0.084 33.696 2.408 33.72 ;
     RECT  0.06 33.72 2.408 33.84 ;
     RECT  0.084 33.84 2.408 33.864 ;
     RECT  0.06 33.864 2.408 33.984 ;
     RECT  0.084 33.984 2.408 34.008 ;
     RECT  0.06 34.008 2.408 34.128 ;
     RECT  0.084 34.128 2.408 34.152 ;
     RECT  0.06 34.152 2.408 34.272 ;
     RECT  0.084 34.272 2.408 34.296 ;
     RECT  0.06 34.296 2.408 34.416 ;
     RECT  0.084 34.416 2.408 34.44 ;
     RECT  0.06 34.44 2.408 34.56 ;
     RECT  0.084 34.56 2.408 34.584 ;
     RECT  0.06 34.584 2.408 34.704 ;
     RECT  0.084 34.704 2.408 34.728 ;
     RECT  0.06 34.728 2.408 34.848 ;
     RECT  0.084 34.848 2.408 34.872 ;
     RECT  0.06 34.872 2.408 34.992 ;
     RECT  0.084 34.992 2.408 35.016 ;
     RECT  0.06 35.016 2.408 35.136 ;
     RECT  0.084 35.136 2.408 35.16 ;
     RECT  0.06 35.16 2.408 35.28 ;
     RECT  0.084 35.28 2.408 35.304 ;
     RECT  0.06 35.304 2.408 35.424 ;
     RECT  0.084 35.424 2.408 35.448 ;
     RECT  0.06 35.448 2.408 35.568 ;
     RECT  0.084 35.568 2.408 35.592 ;
     RECT  0.06 35.592 2.408 35.712 ;
     RECT  0.084 35.712 2.408 35.736 ;
     RECT  0.06 35.736 2.408 35.856 ;
     RECT  0.084 35.856 2.408 35.88 ;
     RECT  0.06 35.88 2.408 36 ;
     RECT  0.084 36 2.408 36.024 ;
     RECT  0.06 36.024 2.408 36.144 ;
     RECT  0.084 36.144 2.408 36.168 ;
     RECT  0.06 36.168 2.408 36.288 ;
     RECT  0.084 36.288 2.408 36.312 ;
     RECT  0.06 36.312 2.408 36.432 ;
     RECT  0.084 36.432 2.408 36.456 ;
     RECT  0.06 36.456 2.408 36.576 ;
     RECT  0.084 36.576 2.408 36.6 ;
     RECT  0.06 36.6 2.408 36.72 ;
     RECT  0.084 36.72 2.408 36.744 ;
     RECT  0.06 36.744 2.408 36.864 ;
     RECT  0.084 36.864 2.408 36.888 ;
     RECT  0.06 36.888 2.408 37.008 ;
     RECT  0.084 37.008 2.408 37.032 ;
     RECT  0.06 37.032 2.408 37.152 ;
     RECT  0.084 37.152 2.408 37.176 ;
     RECT  0.06 37.176 2.408 37.296 ;
     RECT  0.084 37.296 2.408 37.32 ;
     RECT  0.06 37.32 2.408 37.44 ;
     RECT  0.084 37.44 2.408 37.464 ;
     RECT  0.06 37.464 2.408 37.584 ;
     RECT  0.084 37.584 2.408 37.608 ;
     RECT  0.06 37.608 2.408 37.728 ;
     RECT  0.084 37.728 2.408 37.752 ;
     RECT  0.06 37.752 2.408 37.872 ;
     RECT  0.084 37.872 2.408 37.896 ;
     RECT  0.06 37.896 2.408 38.016 ;
     RECT  0.084 38.016 2.408 38.04 ;
     RECT  0.06 38.04 2.408 38.16 ;
     RECT  0.084 38.16 2.408 38.184 ;
     RECT  0.06 38.184 2.408 38.304 ;
     RECT  0.084 38.304 2.408 38.328 ;
     RECT  0.06 38.328 2.408 38.448 ;
     RECT  0.084 38.448 2.408 38.472 ;
     RECT  0.06 38.472 2.408 38.592 ;
     RECT  0.084 38.592 2.408 38.616 ;
     RECT  0.06 38.616 2.408 38.736 ;
     RECT  0.084 38.736 2.408 38.76 ;
     RECT  0.06 38.76 2.408 38.88 ;
     RECT  0.084 38.88 2.408 38.904 ;
     RECT  0.06 38.904 2.408 39.024 ;
     RECT  0.084 39.024 2.408 39.048 ;
     RECT  0.06 39.048 2.408 39.168 ;
     RECT  0.084 39.168 2.408 39.192 ;
     RECT  0.06 39.192 2.408 39.312 ;
     RECT  0.084 39.312 2.408 39.336 ;
     RECT  0.06 39.336 2.408 39.456 ;
     RECT  0.084 39.456 2.408 39.48 ;
     RECT  0.06 39.48 2.408 39.6 ;
     RECT  0.084 39.6 2.408 39.624 ;
     RECT  0.06 39.624 2.408 39.744 ;
     RECT  0.084 39.744 2.408 39.768 ;
     RECT  0.06 39.768 2.408 39.888 ;
     RECT  0.084 39.888 2.408 39.912 ;
     RECT  0.06 39.912 2.408 40.032 ;
     RECT  0.084 40.032 2.408 40.056 ;
     RECT  0.06 40.056 2.408 40.176 ;
     RECT  0.084 40.176 2.408 40.2 ;
     RECT  0.06 40.2 2.408 40.32 ;
     RECT  0.084 40.32 2.408 40.344 ;
     RECT  0.06 40.344 2.408 40.464 ;
     RECT  0.084 40.464 2.408 40.488 ;
     RECT  0.06 40.488 2.408 40.608 ;
     RECT  0.084 40.608 2.408 40.632 ;
     RECT  0.06 40.632 2.408 40.752 ;
     RECT  0.084 40.752 2.408 40.776 ;
     RECT  0.06 40.776 2.408 40.896 ;
     RECT  0.084 40.896 2.408 40.92 ;
     RECT  0.06 40.92 2.408 41.04 ;
     RECT  0.084 41.04 2.408 41.064 ;
     RECT  0.06 41.064 2.408 41.184 ;
     RECT  0.084 41.184 2.408 41.208 ;
     RECT  0.06 41.208 2.408 41.328 ;
     RECT  0.084 41.328 2.408 41.352 ;
     RECT  0.06 41.352 2.408 41.472 ;
     RECT  0.084 41.472 2.408 41.496 ;
     RECT  0.06 41.496 2.408 41.616 ;
     RECT  0.084 41.616 2.408 41.64 ;
     RECT  0.06 41.64 2.408 41.76 ;
     RECT  0.084 41.76 2.408 41.784 ;
     RECT  0.06 41.784 2.408 41.904 ;
     RECT  0.084 41.904 2.408 41.928 ;
     RECT  0.06 41.928 2.408 42.048 ;
     RECT  0.084 42.048 2.408 42.072 ;
     RECT  0.06 42.072 2.408 42.192 ;
     RECT  0.084 42.192 2.408 42.216 ;
     RECT  0.06 42.216 2.408 42.336 ;
     RECT  0.084 42.336 2.408 42.36 ;
     RECT  0.06 42.36 2.408 42.48 ;
     RECT  0.084 42.48 2.408 42.504 ;
     RECT  0.06 42.504 2.408 42.624 ;
     RECT  0.084 42.624 2.408 42.648 ;
     RECT  0.06 42.648 2.408 42.768 ;
     RECT  0.084 42.768 2.408 42.792 ;
     RECT  0.06 42.792 2.408 42.912 ;
     RECT  0.084 42.912 2.408 42.936 ;
     RECT  0.06 42.936 2.408 43.056 ;
     RECT  0.084 43.056 2.408 43.08 ;
     RECT  0.06 43.08 2.408 43.2 ;
     RECT  0.084 43.2 2.408 43.224 ;
     RECT  0.06 43.224 2.408 43.344 ;
     RECT  0.084 43.344 2.408 43.368 ;
     RECT  0.06 43.368 2.408 43.488 ;
     RECT  0.084 43.488 2.408 43.512 ;
     RECT  0.06 43.512 2.408 43.632 ;
     RECT  0.084 43.632 2.408 43.656 ;
     RECT  0.06 43.656 2.408 43.776 ;
     RECT  0.084 43.776 2.408 43.8 ;
     RECT  0.06 43.8 2.408 43.92 ;
     RECT  0.084 43.92 2.408 43.944 ;
     RECT  0.06 43.944 2.408 44.064 ;
     RECT  0.084 44.064 2.408 44.088 ;
     RECT  0.06 44.088 2.408 44.208 ;
     RECT  0.084 44.208 2.408 44.232 ;
     RECT  0.06 44.232 2.408 44.352 ;
     RECT  0.084 44.352 2.408 44.376 ;
     RECT  0.06 44.376 2.408 44.496 ;
     RECT  0.084 44.496 2.408 44.52 ;
     RECT  0.06 44.52 2.408 44.64 ;
     RECT  0.084 44.64 2.408 44.664 ;
     RECT  0.06 44.664 2.408 44.784 ;
     RECT  0.084 44.784 2.408 44.808 ;
     RECT  0.06 44.808 2.408 44.928 ;
     RECT  0.084 44.928 2.408 44.952 ;
     RECT  0.06 44.952 2.408 45.072 ;
     RECT  0.084 45.072 2.408 45.096 ;
     RECT  0.06 45.096 2.408 45.216 ;
     RECT  0.084 45.216 2.408 45.24 ;
     RECT  0.06 45.24 2.408 45.36 ;
     RECT  0.084 45.36 2.408 45.384 ;
     RECT  0.06 45.384 2.408 45.504 ;
     RECT  0.084 45.504 2.408 45.528 ;
     RECT  0.06 45.528 2.408 45.648 ;
     RECT  0.084 45.648 2.408 45.672 ;
     RECT  0.06 45.672 2.408 45.792 ;
     RECT  0.084 45.792 2.408 45.816 ;
     RECT  0.06 45.816 2.408 45.936 ;
     RECT  0.084 45.936 2.408 45.96 ;
     RECT  0.06 45.96 2.408 46.08 ;
     RECT  0.084 46.08 2.408 46.104 ;
     RECT  0.06 46.104 2.408 46.224 ;
     RECT  0.084 46.224 2.408 46.248 ;
     RECT  0.06 46.248 2.408 46.368 ;
     RECT  0.084 46.368 2.408 46.392 ;
     RECT  0.06 46.392 2.408 46.512 ;
     RECT  0.084 46.512 2.408 46.536 ;
     RECT  0.06 46.536 2.408 46.656 ;
     RECT  0.084 46.656 2.408 46.68 ;
     RECT  0.06 46.68 2.408 46.8 ;
     RECT  0.084 46.8 2.408 46.824 ;
     RECT  0.06 46.824 2.408 46.944 ;
     RECT  0.084 46.944 2.408 46.968 ;
     RECT  0.06 46.968 2.408 47.088 ;
     RECT  0.084 47.088 2.408 47.112 ;
     RECT  0.06 47.112 2.408 47.232 ;
     RECT  0.084 47.232 2.408 47.256 ;
     RECT  0.06 47.256 2.408 47.376 ;
     RECT  0.084 47.376 2.408 47.4 ;
     RECT  0.06 47.4 2.408 47.52 ;
     RECT  0.084 47.52 2.408 47.544 ;
     RECT  0.06 47.544 2.408 47.664 ;
     RECT  0.084 47.664 2.408 47.688 ;
     RECT  0.06 47.688 2.408 47.808 ;
     RECT  0.084 47.808 2.408 47.832 ;
     RECT  0.06 47.832 2.408 47.952 ;
     RECT  0.084 47.952 2.408 47.976 ;
     RECT  0.06 47.976 2.408 48.096 ;
     RECT  0.084 48.096 2.408 48.12 ;
     RECT  0.06 48.12 2.408 48.24 ;
     RECT  0.084 48.24 2.408 48.264 ;
     RECT  0.06 48.264 2.408 48.384 ;
     RECT  0.084 48.384 2.408 48.408 ;
     RECT  0.06 48.408 2.408 48.528 ;
     RECT  0.084 48.528 2.408 48.552 ;
     RECT  0.06 48.552 2.408 48.672 ;
     RECT  0.084 48.672 2.408 48.696 ;
     RECT  0.06 48.696 2.408 48.816 ;
     RECT  0.084 48.816 2.408 48.84 ;
     RECT  0.06 48.84 2.408 48.96 ;
     RECT  0.084 48.96 2.408 48.984 ;
     RECT  0.06 48.984 2.408 49.104 ;
     RECT  0.084 49.104 2.408 49.128 ;
     RECT  0.06 49.128 2.408 49.248 ;
     RECT  0.084 49.248 2.408 49.272 ;
     RECT  0.06 49.272 2.408 49.392 ;
     RECT  0.084 49.392 2.408 49.416 ;
     RECT  0.06 49.416 2.408 49.536 ;
     RECT  0.084 49.536 2.408 49.56 ;
     RECT  0.06 49.56 2.408 49.68 ;
     RECT  0.084 49.68 2.408 49.704 ;
     RECT  0.06 49.704 2.408 49.824 ;
     RECT  0.084 49.824 2.408 49.848 ;
     RECT  0.06 49.848 2.408 49.968 ;
     RECT  0.084 49.968 2.408 49.992 ;
     RECT  0.06 49.992 2.408 50.112 ;
     RECT  0.084 50.112 2.408 50.136 ;
     RECT  0.06 50.136 2.408 50.256 ;
     RECT  0.084 50.256 2.408 50.28 ;
     RECT  0.06 50.28 2.408 50.4 ;
     RECT  0.084 50.4 2.408 50.424 ;
     RECT  0.06 50.424 2.408 50.544 ;
     RECT  0.084 50.544 2.408 50.568 ;
     RECT  0.06 50.568 2.408 50.688 ;
     RECT  0.084 50.688 2.408 50.712 ;
     RECT  0.06 50.712 2.408 50.832 ;
     RECT  0.084 50.832 2.408 50.856 ;
     RECT  0.06 50.856 2.408 50.976 ;
     RECT  0.084 50.976 2.408 51 ;
     RECT  0.06 51 2.408 51.12 ;
     RECT  0.084 51.12 2.408 51.144 ;
     RECT  0.06 51.144 2.408 51.264 ;
     RECT  0.084 51.264 2.408 51.288 ;
     RECT  0.06 51.288 2.408 51.408 ;
     RECT  0.084 51.408 2.408 51.432 ;
     RECT  0.06 51.432 2.408 51.552 ;
     RECT  0.084 51.552 2.408 51.576 ;
     RECT  0.06 51.576 2.408 51.696 ;
     RECT  0.084 51.696 2.408 51.72 ;
     RECT  0.06 51.72 2.408 51.84 ;
     RECT  0.084 51.84 2.408 51.864 ;
     RECT  0.06 51.864 2.408 51.984 ;
     RECT  0.084 51.984 2.408 52.008 ;
     RECT  0.06 52.008 2.408 52.128 ;
     RECT  0.084 52.128 2.408 52.152 ;
     RECT  0.06 52.152 2.408 52.272 ;
     RECT  0.084 52.272 2.408 52.296 ;
     RECT  0.06 52.296 2.408 52.416 ;
     RECT  0.084 52.416 2.408 52.44 ;
     RECT  0.084 53.712 2.408 53.736 ;
     RECT  0.06 53.736 2.408 53.856 ;
     RECT  0.084 53.856 2.408 53.88 ;
     RECT  0.06 53.88 2.408 54 ;
     RECT  0.084 54 2.408 54.024 ;
     RECT  0.06 54.024 2.408 54.144 ;
     RECT  0.084 54.144 2.408 54.168 ;
     RECT  0.06 54.168 2.408 54.288 ;
     RECT  0.084 54.288 2.408 54.312 ;
     RECT  0.06 54.312 2.408 54.432 ;
     RECT  0.084 54.432 2.408 54.456 ;
     RECT  0.06 54.456 2.408 54.576 ;
     RECT  0.084 54.576 2.408 54.6 ;
     RECT  0.06 54.6 2.408 54.72 ;
     RECT  0.084 54.72 2.408 54.744 ;
     RECT  0.06 54.744 2.408 54.864 ;
     RECT  0.084 54.864 2.408 54.888 ;
     RECT  0.06 54.888 2.408 55.008 ;
     RECT  0.084 55.008 2.408 55.032 ;
     RECT  0.06 55.032 2.408 55.152 ;
     RECT  0.084 55.152 2.408 55.176 ;
     RECT  0.06 55.176 2.408 55.296 ;
     RECT  0.084 55.296 2.408 55.32 ;
     RECT  0.06 55.32 2.408 55.44 ;
     RECT  0.084 55.44 2.408 55.464 ;
     RECT  0.06 55.464 2.408 55.584 ;
     RECT  0.084 55.584 2.408 55.608 ;
     RECT  0.06 55.608 2.408 55.728 ;
     RECT  0.084 55.728 2.408 55.752 ;
     RECT  0.06 55.752 2.408 55.872 ;
     RECT  0.084 55.872 2.408 55.896 ;
     RECT  0.06 55.896 2.408 56.016 ;
     RECT  0.084 56.016 2.408 56.04 ;
     RECT  0.06 56.04 2.408 56.16 ;
     RECT  0.084 56.16 2.408 56.184 ;
     RECT  0.06 56.184 2.408 56.304 ;
     RECT  0.084 56.304 2.408 56.328 ;
     RECT  0.06 56.328 2.408 56.448 ;
     RECT  0.084 56.448 2.408 56.472 ;
     RECT  0.06 56.472 2.408 56.592 ;
     RECT  0.084 56.592 2.408 56.616 ;
     RECT  0.06 56.616 2.408 56.736 ;
     RECT  0.084 56.736 2.408 56.76 ;
     RECT  0.06 56.76 2.408 56.88 ;
     RECT  0.084 56.88 2.408 56.904 ;
     RECT  0.06 56.904 2.408 57.024 ;
     RECT  0.084 57.024 2.408 57.048 ;
     RECT  0.06 57.048 2.408 57.168 ;
     RECT  0.084 57.168 2.408 57.192 ;
     RECT  0.06 57.192 2.408 57.312 ;
     RECT  0.084 57.312 2.408 57.336 ;
     RECT  0.06 57.336 2.408 57.456 ;
     RECT  0.084 57.456 2.408 57.48 ;
     RECT  0.06 57.48 2.408 57.6 ;
     RECT  0.084 57.6 2.408 57.624 ;
     RECT  0.06 57.624 2.408 57.744 ;
     RECT  0.084 57.744 2.408 57.768 ;
     RECT  0.06 57.768 2.408 57.888 ;
     RECT  0.084 57.888 2.408 57.912 ;
     RECT  0.06 57.912 2.408 58.032 ;
     RECT  0.084 58.032 2.408 58.056 ;
     RECT  0.06 58.056 2.408 58.176 ;
     RECT  0.084 58.176 2.408 58.2 ;
     RECT  0.06 58.2 2.408 58.32 ;
     RECT  0.084 58.32 2.408 58.344 ;
     RECT  0.06 58.344 2.408 58.464 ;
     RECT  0.084 58.464 2.408 58.488 ;
     RECT  0.06 58.488 2.408 58.608 ;
     RECT  0.084 58.608 2.408 58.632 ;
     RECT  0.06 58.632 2.408 58.752 ;
     RECT  0.084 58.752 2.408 58.776 ;
     RECT  0.06 58.776 2.408 58.896 ;
     RECT  0.084 58.896 2.408 58.92 ;
     RECT  0.06 58.92 2.408 59.04 ;
     RECT  0.084 59.04 2.408 59.064 ;
     RECT  0.06 59.064 2.408 59.184 ;
     RECT  0.084 59.184 2.408 59.208 ;
     RECT  0.06 59.208 2.408 59.328 ;
     RECT  0.084 59.328 2.408 59.352 ;
     RECT  0.06 59.352 2.408 59.472 ;
     RECT  0.084 59.472 2.408 59.496 ;
     RECT  0.06 59.496 2.408 59.616 ;
     RECT  0.084 59.616 2.408 59.64 ;
     RECT  0.06 59.64 2.408 59.76 ;
     RECT  0.084 59.76 2.408 59.784 ;
     RECT  0.06 59.784 2.408 59.904 ;
     RECT  0.084 59.904 2.408 59.928 ;
     RECT  0.06 59.928 2.408 60.048 ;
     RECT  0.084 60.048 2.408 60.072 ;
     RECT  0.06 60.072 2.408 60.192 ;
     RECT  0.084 60.192 2.408 60.216 ;
     RECT  0.06 60.216 2.408 60.336 ;
     RECT  0.084 60.336 2.408 60.36 ;
     RECT  0.06 60.36 2.408 60.48 ;
     RECT  0.084 60.48 2.408 60.504 ;
     RECT  0.06 60.504 2.408 60.624 ;
     RECT  0.084 60.624 2.408 60.648 ;
     RECT  0.06 60.648 2.408 60.768 ;
     RECT  0.084 60.768 2.408 60.792 ;
     RECT  0.06 60.792 2.408 60.912 ;
     RECT  0.084 60.912 2.408 60.936 ;
     RECT  0.06 60.936 2.408 61.056 ;
     RECT  0.084 61.056 2.408 61.08 ;
     RECT  0.06 61.08 2.408 61.2 ;
     RECT  0.084 61.2 2.408 61.224 ;
     RECT  0.06 61.224 2.408 61.344 ;
     RECT  0.084 61.344 2.408 61.368 ;
     RECT  0.06 61.368 2.408 61.488 ;
     RECT  0.084 61.488 2.408 61.512 ;
     RECT  0.06 61.512 2.408 61.632 ;
     RECT  0.084 61.632 2.408 61.656 ;
     RECT  0.06 61.656 2.408 61.776 ;
     RECT  0.084 61.776 2.408 61.8 ;
     RECT  0.06 61.8 2.408 61.92 ;
     RECT  0.084 61.92 2.408 61.944 ;
     RECT  0.06 61.944 2.408 62.064 ;
     RECT  0.084 62.064 2.408 62.088 ;
     RECT  0.06 62.088 2.408 62.208 ;
     RECT  0.084 62.208 2.408 62.232 ;
     RECT  0.06 62.232 2.408 62.352 ;
     RECT  0.084 62.352 2.408 62.376 ;
     RECT  0.06 62.376 2.408 62.496 ;
     RECT  0.084 62.496 2.408 62.52 ;
     RECT  0.06 62.52 2.408 62.64 ;
     RECT  0.084 62.64 2.408 62.664 ;
     RECT  0.06 62.664 2.408 62.784 ;
     RECT  0.084 62.784 2.408 62.808 ;
     RECT  0.06 62.808 2.408 62.928 ;
     RECT  0.084 62.928 2.408 62.952 ;
     RECT  0.06 62.952 2.408 63.072 ;
     RECT  0.084 63.072 2.408 63.096 ;
     RECT  0.06 63.096 2.408 63.216 ;
     RECT  0.084 63.216 2.408 63.24 ;
     RECT  0.06 63.24 2.408 63.36 ;
     RECT  0.084 63.36 2.408 63.384 ;
     RECT  0.06 63.384 2.408 63.504 ;
     RECT  0.084 63.504 2.408 63.528 ;
     RECT  0.06 63.528 2.408 63.648 ;
     RECT  0.084 63.648 2.408 63.672 ;
     RECT  0.06 63.672 2.408 63.792 ;
     RECT  0.084 63.792 2.408 63.816 ;
     RECT  0.06 63.816 2.408 63.936 ;
     RECT  0.084 63.936 2.408 63.96 ;
     RECT  0.06 63.96 2.408 64.08 ;
     RECT  0.084 64.08 2.408 64.104 ;
     RECT  0.06 64.104 2.408 64.224 ;
     RECT  0.084 64.224 2.408 64.248 ;
     RECT  0.06 64.248 2.408 64.368 ;
     RECT  0.084 64.368 2.408 64.392 ;
     RECT  0.06 64.392 2.408 64.512 ;
     RECT  0.084 64.512 2.408 64.536 ;
     RECT  0.06 64.536 2.408 64.656 ;
     RECT  0.084 64.656 2.408 64.68 ;
     RECT  0.06 64.68 2.408 64.8 ;
     RECT  0.084 64.8 2.408 64.824 ;
     RECT  0.06 64.824 2.408 64.944 ;
     RECT  0.084 64.944 2.408 64.968 ;
     RECT  0.06 64.968 2.408 65.088 ;
     RECT  0.084 65.088 2.408 65.112 ;
     RECT  0.06 65.112 2.408 65.232 ;
     RECT  0.084 65.232 2.408 65.256 ;
     RECT  0.06 65.256 2.408 65.376 ;
     RECT  0.084 65.376 2.408 65.4 ;
     RECT  0.06 65.4 2.408 65.52 ;
     RECT  0.084 65.52 2.408 65.544 ;
     RECT  0.06 65.544 2.408 65.664 ;
     RECT  0.084 65.664 2.408 65.688 ;
     RECT  0.06 65.688 2.408 65.808 ;
     RECT  0.084 65.808 2.408 65.832 ;
     RECT  0.06 65.832 2.408 65.952 ;
     RECT  0.084 65.952 2.408 65.976 ;
     RECT  0.06 65.976 2.408 66.096 ;
     RECT  0.084 66.096 2.408 66.12 ;
     RECT  0.06 66.12 2.408 66.24 ;
     RECT  0.084 66.24 2.408 66.264 ;
     RECT  0.06 66.264 2.408 66.384 ;
     RECT  0.084 66.384 2.408 66.408 ;
     RECT  0.06 66.408 2.408 66.528 ;
     RECT  0.084 66.528 2.408 66.552 ;
     RECT  0.06 66.552 2.408 66.672 ;
     RECT  0.084 66.672 2.408 66.696 ;
     RECT  0.06 66.696 2.408 66.816 ;
     RECT  0.084 66.816 2.408 66.84 ;
     RECT  0.06 66.84 2.408 66.96 ;
     RECT  0.084 66.96 2.408 66.984 ;
     RECT  0.06 66.984 2.408 67.104 ;
     RECT  0.084 67.104 2.408 67.128 ;
     RECT  0.06 67.128 2.408 67.248 ;
     RECT  0.084 67.248 2.408 67.272 ;
     RECT  0.06 67.272 2.408 67.392 ;
     RECT  0.084 67.392 2.408 67.416 ;
     RECT  0.06 67.416 2.408 67.536 ;
     RECT  0.084 67.536 2.408 67.56 ;
     RECT  0.06 67.56 2.408 67.68 ;
     RECT  0.084 67.68 2.408 67.704 ;
     RECT  0.06 67.704 2.408 67.824 ;
     RECT  0.084 67.824 2.408 67.848 ;
     RECT  0.06 67.848 2.408 67.968 ;
     RECT  0.084 67.968 2.408 67.992 ;
     RECT  0.06 67.992 2.408 68.112 ;
     RECT  0.084 68.112 2.408 68.136 ;
     RECT  0.06 68.136 2.408 68.256 ;
     RECT  0.084 68.256 2.408 68.28 ;
     RECT  0.06 68.28 2.408 68.4 ;
     RECT  0.084 68.4 2.408 68.424 ;
     RECT  0.06 68.424 2.408 68.544 ;
     RECT  0.084 68.544 2.408 68.568 ;
     RECT  0.06 68.568 2.408 68.688 ;
     RECT  0.084 68.688 2.408 68.712 ;
     RECT  0.06 68.712 2.408 68.832 ;
     RECT  0.084 68.832 2.408 68.856 ;
     RECT  0.06 68.856 2.408 68.976 ;
     RECT  0.084 68.976 2.408 69 ;
     RECT  0.06 69 2.408 69.12 ;
     RECT  0.084 69.12 2.408 69.144 ;
     RECT  0.06 69.144 2.408 69.264 ;
     RECT  0.084 69.264 2.408 69.288 ;
     RECT  0.06 69.288 2.408 69.408 ;
     RECT  0.084 69.408 2.408 69.432 ;
     RECT  0.06 69.432 2.408 69.552 ;
     RECT  0.084 69.552 2.408 69.576 ;
     RECT  0.06 69.576 2.408 69.696 ;
     RECT  0.084 69.696 2.408 69.72 ;
     RECT  0.06 69.72 2.408 69.84 ;
     RECT  0.084 69.84 2.408 69.864 ;
     RECT  0.06 69.864 2.408 69.984 ;
     RECT  0.084 69.984 2.408 70.008 ;
     RECT  0.06 70.008 2.408 70.128 ;
     RECT  0.084 70.128 2.408 70.152 ;
     RECT  0.06 70.152 2.408 70.272 ;
     RECT  0.084 70.272 2.408 70.296 ;
     RECT  0.06 70.296 2.408 70.416 ;
     RECT  0.084 70.416 2.408 70.44 ;
     RECT  0.06 70.44 2.408 70.56 ;
     RECT  0.084 70.56 2.408 70.584 ;
     RECT  0.06 70.584 2.408 70.704 ;
     RECT  0.084 70.704 2.408 70.728 ;
     RECT  0.06 70.728 2.408 70.848 ;
     RECT  0.084 70.848 2.408 70.872 ;
     RECT  0.06 70.872 2.408 70.992 ;
     RECT  0.084 70.992 2.408 71.016 ;
     RECT  0.06 71.016 2.408 71.136 ;
     RECT  0.084 71.136 2.408 71.16 ;
     RECT  0.06 71.16 2.408 71.28 ;
     RECT  0.084 71.28 2.408 71.304 ;
     RECT  0.06 71.304 2.408 71.424 ;
     RECT  0.084 71.424 2.408 71.448 ;
     RECT  0.06 71.448 2.408 71.568 ;
     RECT  0.084 71.568 2.408 71.592 ;
     RECT  0.06 71.592 2.408 71.712 ;
     RECT  0.084 71.712 2.408 71.736 ;
     RECT  0.06 71.736 2.408 71.856 ;
     RECT  0.084 71.856 2.408 71.88 ;
     RECT  0.06 71.88 2.408 72 ;
     RECT  0.084 72 2.408 72.024 ;
     RECT  0.06 72.024 2.408 72.144 ;
     RECT  0.084 72.144 2.408 72.168 ;
     RECT  0.06 72.168 2.408 72.288 ;
     RECT  0.084 72.288 2.408 72.312 ;
     RECT  0.06 72.312 2.408 72.432 ;
     RECT  0.084 72.432 2.408 72.456 ;
     RECT  0.06 72.456 2.408 72.576 ;
     RECT  0.084 72.576 2.408 72.6 ;
     RECT  0.06 72.6 2.408 72.72 ;
     RECT  0.084 72.72 2.408 72.744 ;
     RECT  0.06 72.744 2.408 72.864 ;
     RECT  0.084 72.864 2.408 72.888 ;
     RECT  0.06 72.888 2.408 73.008 ;
     RECT  0.084 73.008 2.408 73.032 ;
     RECT  0.06 73.032 2.408 73.152 ;
     RECT  0.084 73.152 2.408 73.176 ;
     RECT  0.06 73.176 2.408 73.296 ;
     RECT  0.084 73.296 2.408 73.32 ;
     RECT  0.06 73.32 2.408 73.44 ;
     RECT  0.084 73.44 2.408 73.464 ;
     RECT  0.06 73.464 2.408 73.584 ;
     RECT  0.084 73.584 2.408 73.608 ;
     RECT  0.06 73.608 2.408 73.728 ;
     RECT  0.084 73.728 2.408 73.752 ;
     RECT  0.06 73.752 2.408 73.872 ;
     RECT  0.084 73.872 2.408 73.896 ;
     RECT  0.06 73.896 2.408 74.016 ;
     RECT  0.084 74.016 2.408 74.04 ;
     RECT  0.06 74.04 2.408 74.16 ;
     RECT  0.084 74.16 2.408 74.184 ;
     RECT  0.06 74.184 2.408 74.304 ;
     RECT  0.084 74.304 2.408 74.328 ;
     RECT  0.06 74.328 2.408 74.448 ;
     RECT  0.084 74.448 2.408 74.472 ;
     RECT  0.06 74.472 2.408 74.592 ;
     RECT  0.084 74.592 2.408 74.616 ;
     RECT  0.06 74.616 2.408 74.736 ;
     RECT  0.084 74.736 2.408 74.76 ;
     RECT  0.06 74.76 2.408 74.88 ;
     RECT  0.084 74.88 2.408 74.904 ;
     RECT  0.06 74.904 2.408 75.024 ;
     RECT  0.084 75.024 2.408 75.048 ;
     RECT  0.06 75.048 2.408 75.168 ;
     RECT  0.084 75.168 2.408 75.192 ;
     RECT  0.06 75.192 2.408 75.312 ;
     RECT  0.084 75.312 2.408 75.336 ;
     RECT  0.06 75.336 2.408 75.456 ;
     RECT  0.084 75.456 2.408 75.48 ;
     RECT  0.06 75.48 2.408 75.6 ;
     RECT  0.084 75.6 2.408 75.624 ;
     RECT  0.06 75.624 2.408 75.744 ;
     RECT  0.084 75.744 2.408 75.768 ;
     RECT  0.06 75.768 2.408 75.888 ;
     RECT  0.084 75.888 2.408 75.912 ;
     RECT  0.06 75.912 2.408 76.032 ;
     RECT  0.084 76.032 2.408 76.056 ;
     RECT  0.06 76.056 2.408 76.176 ;
     RECT  0.084 76.176 2.408 76.2 ;
     RECT  0.06 76.2 2.408 76.32 ;
     RECT  0.084 76.32 2.408 76.344 ;
     RECT  0.06 76.344 2.408 76.464 ;
     RECT  0.084 76.464 2.408 76.488 ;
     RECT  0.06 76.488 2.408 76.608 ;
     RECT  0.084 76.608 2.408 76.632 ;
     RECT  0.06 76.632 2.408 76.752 ;
     RECT  0.084 76.752 2.408 76.776 ;
     RECT  0.06 76.776 2.408 76.896 ;
     RECT  0.084 76.896 2.408 76.92 ;
     RECT  0.06 76.92 2.408 77.04 ;
     RECT  0.084 77.04 2.408 77.064 ;
     RECT  0.06 77.064 2.408 77.184 ;
     RECT  0.084 77.184 2.408 77.208 ;
     RECT  0.06 77.208 2.408 77.328 ;
     RECT  0.084 77.328 2.408 77.352 ;
     RECT  0.06 77.352 2.408 77.472 ;
     RECT  0.084 77.472 2.408 77.496 ;
     RECT  0.06 77.496 2.408 77.616 ;
     RECT  0.084 77.616 2.408 77.64 ;
     RECT  0.06 77.64 2.408 77.76 ;
     RECT  0.084 77.76 2.408 77.784 ;
     RECT  0.06 77.784 2.408 77.904 ;
     RECT  0.084 77.904 2.408 77.928 ;
     RECT  0.06 77.928 2.408 78.048 ;
     RECT  0.084 78.048 2.408 78.072 ;
     RECT  0.06 78.072 2.408 78.192 ;
     RECT  0.084 78.192 2.408 78.216 ;
     RECT  0.06 78.216 2.408 78.336 ;
     RECT  0.084 78.336 2.408 78.36 ;
     RECT  0.06 78.36 2.408 78.48 ;
     RECT  0.084 78.48 2.408 78.504 ;
     RECT  0.06 78.504 2.408 78.624 ;
     RECT  0.084 78.624 2.408 78.648 ;
     RECT  0.06 78.648 2.408 78.768 ;
     RECT  0.084 78.768 2.408 78.792 ;
     RECT  0.06 78.792 2.408 78.912 ;
     RECT  0.084 78.912 2.408 78.936 ;
     RECT  0.06 78.936 2.408 79.056 ;
     RECT  0.084 79.056 2.408 79.08 ;
     RECT  0.06 79.08 2.408 79.2 ;
     RECT  0.084 79.2 2.408 79.224 ;
     RECT  0.06 79.224 2.408 79.344 ;
     RECT  0.084 79.344 2.408 79.368 ;
     RECT  0.06 79.368 2.408 79.488 ;
     RECT  0.084 79.488 2.408 79.512 ;
     RECT  0.06 79.512 2.408 79.632 ;
     RECT  0.084 79.632 2.408 79.656 ;
     RECT  0.06 79.656 2.408 79.776 ;
     RECT  0.084 79.776 2.408 79.8 ;
     RECT  0.06 79.8 2.408 79.92 ;
     RECT  0.084 79.92 2.408 79.944 ;
     RECT  0.06 79.944 2.408 80.064 ;
     RECT  0.084 80.064 2.408 80.088 ;
     RECT  0.06 80.088 2.408 80.208 ;
     RECT  0.084 80.208 2.408 80.232 ;
     RECT  0.06 80.232 2.408 80.352 ;
     RECT  0.084 80.352 2.408 80.376 ;
     RECT  0.06 80.376 2.408 80.496 ;
     RECT  0.084 80.496 2.408 80.52 ;
     RECT  0.06 80.52 2.408 80.64 ;
     RECT  0.084 80.64 2.408 80.664 ;
     RECT  0.06 80.664 2.408 80.784 ;
     RECT  0.084 80.784 2.408 80.808 ;
     RECT  0.06 80.808 2.408 80.928 ;
     RECT  0.084 80.928 2.408 80.952 ;
     RECT  0.06 80.952 2.408 81.072 ;
     RECT  0.084 81.072 2.408 81.096 ;
     RECT  0.06 81.096 2.408 81.216 ;
     RECT  0.084 81.216 2.408 81.24 ;
     RECT  2.408 2.148 2.512 81.24 ;
     RECT  2.512 2.418 2.704 81.24 ;
     RECT  2.704 25.104 2.981 52.344 ;
     RECT  2.704 54.144 4.069 81.24 ;
     RECT  2.704 3.36 4.117 23.928 ;
     RECT  2.981 25.104 4.117 52.248 ;
     RECT  4.117 3.36 5.101 52.248 ;
     RECT  5.101 3.312 5.108 52.248 ;
     RECT  4.069 54.048 5.108 81.24 ;
     RECT  5.108 2.148 5.212 81.24 ;
     RECT  5.212 2.418 5.404 81.24 ;
     RECT  5.404 14.4 5.429 17.64 ;
     RECT  5.404 47.616 5.429 52.248 ;
     RECT  5.404 54.096 5.429 58.152 ;
     RECT  5.404 25.056 5.465 28.824 ;
     RECT  5.404 33.888 5.465 36.504 ;
     RECT  5.404 67.344 5.465 67.848 ;
     RECT  5.404 4.8 5.573 13.416 ;
     RECT  5.573 7.2 5.645 13.416 ;
     RECT  5.429 14.736 5.645 17.64 ;
     RECT  5.404 18.768 5.681 23.928 ;
     RECT  5.465 25.056 5.681 28.248 ;
     RECT  5.404 29.808 5.681 32.28 ;
     RECT  5.404 37.92 5.681 46.104 ;
     RECT  5.404 68.928 5.681 81.24 ;
     RECT  5.465 67.392 5.717 67.848 ;
     RECT  5.681 71.232 5.717 81.24 ;
     RECT  5.681 38.784 5.74 46.104 ;
     RECT  5.681 30.144 5.789 32.28 ;
     RECT  5.429 47.616 5.789 52.056 ;
     RECT  5.717 71.232 5.891 77.064 ;
     RECT  5.717 67.776 5.897 67.848 ;
     RECT  5.717 78.432 6.077 80.664 ;
     RECT  5.74 38.784 6.083 41.736 ;
     RECT  5.74 43.104 6.083 46.104 ;
     RECT  6.083 38.784 6.124 39.864 ;
     RECT  5.645 9.648 6.131 13.416 ;
     RECT  6.083 43.104 6.221 44.904 ;
     RECT  5.681 68.928 6.257 70.056 ;
     RECT  5.681 25.056 6.323 28.008 ;
     RECT  5.681 18.768 6.365 22.104 ;
     RECT  5.681 23.328 6.384 23.928 ;
     RECT  5.645 14.736 6.437 16.584 ;
     RECT  6.323 25.68 6.437 28.008 ;
     RECT  5.429 54.096 6.437 56.232 ;
     RECT  5.891 71.232 6.437 75.816 ;
     RECT  6.131 9.648 6.467 10.872 ;
     RECT  5.404 3.312 6.469 3.432 ;
     RECT  5.573 4.8 6.469 6.168 ;
     RECT  5.789 48.384 6.469 52.056 ;
     RECT  6.469 3.312 6.473 6.168 ;
     RECT  6.131 11.952 6.517 13.416 ;
     RECT  6.437 14.736 6.517 15.768 ;
     RECT  6.469 48.384 6.545 52.44 ;
     RECT  6.437 55.872 6.553 56.232 ;
     RECT  6.517 11.952 6.563 15.768 ;
     RECT  5.897 67.824 6.572 67.848 ;
     RECT  6.257 68.928 6.572 69.048 ;
     RECT  6.545 48.432 6.581 52.44 ;
     RECT  5.404 59.184 6.604 61.656 ;
     RECT  6.581 48.432 6.611 50.856 ;
     RECT  6.473 3.84 6.649 6.168 ;
     RECT  5.645 7.2 6.649 8.52 ;
     RECT  5.789 30.192 6.689 32.28 ;
     RECT  6.124 38.784 6.689 39.336 ;
     RECT  6.083 46.08 6.689 46.104 ;
     RECT  6.611 48.432 6.689 50.76 ;
     RECT  6.553 56.208 6.689 56.232 ;
     RECT  6.604 61.632 6.721 61.656 ;
     RECT  6.604 59.184 6.755 60.456 ;
     RECT  6.365 18.768 6.761 18.792 ;
     RECT  6.689 38.976 6.761 39.336 ;
     RECT  6.221 44.88 6.761 44.904 ;
     RECT  6.077 78.48 6.797 80.664 ;
     RECT  5.465 34.56 6.829 36.504 ;
     RECT  6.083 40.848 6.829 41.736 ;
     RECT  5.429 57.312 6.833 58.152 ;
     RECT  6.755 59.184 6.833 60.12 ;
     RECT  6.572 67.824 6.865 69.048 ;
     RECT  6.365 19.92 6.901 22.104 ;
     RECT  6.384 23.328 6.901 23.352 ;
     RECT  6.829 34.56 6.901 36.648 ;
     RECT  5.645 17.616 6.973 17.64 ;
     RECT  5.891 77.04 7.045 77.064 ;
     RECT  6.829 40.848 7.141 41.976 ;
     RECT  6.221 43.104 7.141 43.656 ;
     RECT  6.581 52.032 7.225 52.44 ;
     RECT  7.141 40.848 7.333 43.656 ;
     RECT  6.901 19.92 7.405 23.352 ;
     RECT  6.649 3.84 7.429 8.52 ;
     RECT  6.467 9.648 7.429 10.44 ;
     RECT  5.404 62.784 7.477 66.312 ;
     RECT  6.437 27.408 7.525 28.008 ;
     RECT  6.833 57.6 7.657 58.152 ;
     RECT  6.437 74.304 7.669 75.816 ;
     RECT  7.045 76.944 7.669 77.064 ;
     RECT  7.429 3.84 7.808 10.44 ;
     RECT  6.563 11.952 7.808 14.232 ;
     RECT  6.563 15.744 7.808 15.768 ;
     RECT  6.973 17.04 7.808 17.64 ;
     RECT  7.405 18.816 7.808 23.352 ;
     RECT  6.901 24.624 7.808 24.648 ;
     RECT  6.437 25.68 7.808 25.752 ;
     RECT  7.525 27.408 7.808 28.488 ;
     RECT  6.689 30.432 7.808 32.28 ;
     RECT  6.901 34.08 7.808 36.648 ;
     RECT  6.761 38.976 7.808 39 ;
     RECT  7.333 40.56 7.808 43.656 ;
     RECT  7.505 47.328 7.808 47.352 ;
     RECT  6.689 48.816 7.808 50.76 ;
     RECT  7.225 52.032 7.808 52.824 ;
     RECT  6.437 54.096 7.808 54.408 ;
     RECT  7.573 56.496 7.808 56.52 ;
     RECT  7.657 57.6 7.808 58.248 ;
     RECT  6.833 60.096 7.808 60.12 ;
     RECT  6.721 61.632 7.808 61.704 ;
     RECT  7.477 62.736 7.808 66.312 ;
     RECT  6.865 67.44 7.808 69.048 ;
     RECT  6.785 70.128 7.808 70.152 ;
     RECT  6.437 71.232 7.808 73.128 ;
     RECT  7.669 74.304 7.808 77.064 ;
     RECT  6.797 78.48 7.808 79.752 ;
     RECT  7.808 2.148 7.912 79.932 ;
     RECT  7.912 2.418 8.104 79.752 ;
     RECT  8.104 4.128 8.165 7.944 ;
     RECT  8.104 55.824 8.165 57.048 ;
     RECT  8.104 62.736 8.201 64.728 ;
     RECT  8.104 52.704 8.237 53.832 ;
     RECT  8.104 40.896 8.291 43.656 ;
     RECT  8.237 52.8 8.291 53.832 ;
     RECT  8.104 78.624 8.309 78.744 ;
     RECT  8.104 58.08 8.345 60.12 ;
     RECT  8.104 27.312 8.387 30.312 ;
     RECT  8.345 58.08 8.417 58.248 ;
     RECT  8.104 68.976 8.417 69 ;
     RECT  8.291 40.944 8.435 43.656 ;
     RECT  8.104 34.656 8.453 34.68 ;
     RECT  8.435 40.944 8.489 42.264 ;
     RECT  8.291 52.8 8.525 52.824 ;
     RECT  8.165 57.024 8.525 57.048 ;
     RECT  8.104 77.472 8.531 77.496 ;
     RECT  8.165 55.824 8.561 55.896 ;
     RECT  8.104 50.304 8.633 51.336 ;
     RECT  8.104 22.224 8.675 22.776 ;
     RECT  8.633 50.304 8.705 50.76 ;
     RECT  8.165 4.992 8.813 7.944 ;
     RECT  8.561 55.824 8.819 55.848 ;
     RECT  8.104 38.64 8.849 39 ;
     RECT  8.104 71.28 8.867 71.304 ;
     RECT  8.387 29.472 8.957 30.312 ;
     RECT  8.489 40.944 8.957 42.216 ;
     RECT  8.104 65.712 8.957 66.312 ;
     RECT  8.957 29.472 8.963 30.264 ;
     RECT  8.345 59.28 8.965 60.12 ;
     RECT  8.387 27.312 9.011 28.488 ;
     RECT  8.417 58.08 9.011 58.152 ;
     RECT  8.963 29.472 9.029 29.64 ;
     RECT  8.705 50.736 9.029 50.76 ;
     RECT  8.104 70.128 9.059 70.152 ;
     RECT  9.011 27.312 9.073 28.008 ;
     RECT  8.957 40.944 9.101 42.168 ;
     RECT  8.104 20.304 9.107 20.328 ;
     RECT  8.104 8.976 9.137 11.064 ;
     RECT  8.201 62.736 9.137 64.632 ;
     RECT  9.137 9.552 9.205 11.064 ;
     RECT  9.169 66.72 9.299 66.744 ;
     RECT  8.104 12.864 9.385 13.08 ;
     RECT  8.104 15.744 9.385 15.816 ;
     RECT  8.104 74.976 9.389 76.344 ;
     RECT  9.308 51.84 9.395 51.864 ;
     RECT  9.137 62.784 9.421 64.632 ;
     RECT  8.957 65.712 9.421 65.736 ;
     RECT  9.349 29.088 9.461 29.112 ;
     RECT  8.675 22.752 9.491 22.776 ;
     RECT  9.421 62.784 9.505 65.736 ;
     RECT  8.104 18.96 9.589 19.032 ;
     RECT  9.529 57.6 9.637 57.624 ;
     RECT  8.291 53.808 9.745 53.832 ;
     RECT  9.385 15.264 9.781 15.816 ;
     RECT  9.565 67.824 9.781 67.848 ;
     RECT  9.781 14.976 10.033 15.816 ;
     RECT  9.829 17.424 10.105 17.448 ;
     RECT  9.589 18.432 10.105 19.032 ;
     RECT  8.104 73.104 10.105 73.896 ;
     RECT  9.745 53.808 10.133 54.744 ;
     RECT  10.105 17.424 10.165 19.032 ;
     RECT  9.457 37.056 10.249 37.08 ;
     RECT  10.249 37.056 10.261 37.272 ;
     RECT  10.141 34.896 10.285 34.92 ;
     RECT  10.177 20.112 10.357 20.136 ;
     RECT  8.104 24.624 10.429 24.648 ;
     RECT  10.357 20.112 10.465 20.184 ;
     RECT  9.889 21.408 10.465 21.432 ;
     RECT  9.101 41.472 10.465 42.168 ;
     RECT  10.133 53.568 10.465 54.744 ;
     RECT  9.493 2.88 10.508 2.904 ;
     RECT  8.813 4.992 10.508 7.128 ;
     RECT  9.241 8.448 10.508 8.472 ;
     RECT  9.205 9.552 10.508 11.16 ;
     RECT  9.385 12.864 10.508 13.368 ;
     RECT  10.033 14.64 10.508 15.816 ;
     RECT  10.165 16.896 10.508 19.032 ;
     RECT  10.465 20.112 10.508 21.432 ;
     RECT  10.213 22.464 10.508 22.488 ;
     RECT  10.429 24.192 10.508 24.648 ;
     RECT  8.104 25.728 10.508 25.752 ;
     RECT  10.261 26.784 10.508 26.808 ;
     RECT  9.073 27.984 10.508 28.008 ;
     RECT  10.22 29.04 10.508 29.064 ;
     RECT  9.997 30.72 10.508 30.744 ;
     RECT  10.285 34.896 10.508 34.968 ;
     RECT  10.261 36.576 10.508 37.272 ;
     RECT  8.849 38.976 10.508 39 ;
     RECT  10.465 40.944 10.508 42.168 ;
     RECT  8.435 43.632 10.508 43.656 ;
     RECT  9.529 45.504 10.508 45.528 ;
     RECT  10.033 46.752 10.508 46.776 ;
     RECT  9.925 50.88 10.508 50.904 ;
     RECT  10.465 53.568 10.508 55.704 ;
     RECT  9.637 57.024 10.508 57.624 ;
     RECT  8.965 60.096 10.508 60.12 ;
     RECT  8.104 61.632 10.508 61.656 ;
     RECT  9.505 62.784 10.508 64.632 ;
     RECT  9.505 65.712 10.508 65.736 ;
     RECT  9.781 67.44 10.508 67.848 ;
     RECT  10.213 68.976 10.508 69 ;
     RECT  9.673 70.368 10.508 70.392 ;
     RECT  10.105 72.816 10.508 73.896 ;
     RECT  9.389 74.976 10.508 75.864 ;
     RECT  8.309 78.624 10.508 78.648 ;
     RECT  8.104 79.728 10.508 79.752 ;
     RECT  10.508 2.148 10.612 79.932 ;
     RECT  10.612 2.418 10.804 79.752 ;
     RECT  10.804 34.896 10.829 34.92 ;
     RECT  10.804 4.896 10.865 8.472 ;
     RECT  10.804 72 11.123 73.896 ;
     RECT  10.804 41.472 11.225 41.928 ;
     RECT  10.804 69.552 11.341 70.392 ;
     RECT  10.804 74.976 11.377 75.288 ;
     RECT  10.804 43.632 11.513 43.656 ;
     RECT  6.997 0.048 11.581 0.072 ;
     RECT  10.804 62.784 11.699 65.736 ;
     RECT  10.804 46.752 11.729 46.776 ;
     RECT  10.804 14.64 11.797 15.72 ;
     RECT  10.804 16.896 11.797 19.032 ;
     RECT  10.804 25.728 11.833 25.752 ;
     RECT  11.225 41.712 11.837 41.928 ;
     RECT  10.804 60.096 11.843 60.12 ;
     RECT  11.797 14.64 11.881 19.032 ;
     RECT  11.837 41.712 11.909 41.736 ;
     RECT  10.804 78.624 12.277 78.648 ;
     RECT  11.377 74.976 12.301 75.144 ;
     RECT  10.804 53.568 12.481 53.832 ;
     RECT  11.581 0.048 12.593 0.888 ;
     RECT  11.881 14.64 12.841 15.72 ;
     RECT  12.593 0.144 12.881 0.888 ;
     RECT  10.865 4.992 12.913 8.472 ;
     RECT  10.804 9.648 12.913 9.816 ;
     RECT  11.699 62.784 12.949 62.808 ;
     RECT  11.341 70.368 12.985 70.392 ;
     RECT  10.804 2.88 13.208 2.904 ;
     RECT  12.913 4.992 13.208 9.816 ;
     RECT  10.804 11.136 13.208 11.16 ;
     RECT  10.804 12.864 13.208 13.368 ;
     RECT  12.841 14.4 13.208 15.72 ;
     RECT  11.881 16.896 13.208 19.032 ;
     RECT  10.804 20.016 13.208 21.432 ;
     RECT  10.804 22.464 13.208 24.648 ;
     RECT  11.833 25.728 13.208 25.8 ;
     RECT  12.949 29.52 13.208 29.544 ;
     RECT  10.804 32.736 13.208 32.76 ;
     RECT  10.804 38.976 13.208 39 ;
     RECT  12.949 41.664 13.208 41.688 ;
     RECT  12.517 43.632 13.208 43.656 ;
     RECT  10.804 45.504 13.208 45.528 ;
     RECT  10.804 51.696 13.208 51.72 ;
     RECT  12.481 53.28 13.208 53.832 ;
     RECT  10.804 55.68 13.208 55.704 ;
     RECT  12.409 60.624 13.208 60.648 ;
     RECT  12.949 62.16 13.208 62.808 ;
     RECT  11.699 63.84 13.208 65.736 ;
     RECT  10.804 67.824 13.208 67.848 ;
     RECT  12.985 70.368 13.208 70.872 ;
     RECT  11.123 72 13.208 72.024 ;
     RECT  11.123 73.104 13.208 73.896 ;
     RECT  12.301 74.88 13.208 75.144 ;
     RECT  12.277 77.664 13.208 78.648 ;
     RECT  10.804 79.728 13.208 79.752 ;
     RECT  13.208 2.148 13.312 79.932 ;
     RECT  13.237 80.928 13.385 80.952 ;
     RECT  13.312 2.418 13.504 79.662 ;
     RECT  13.504 4.992 13.601 5.832 ;
     RECT  13.504 41.664 13.673 41.688 ;
     RECT  13.504 32.736 13.889 33.576 ;
     RECT  13.504 7.104 13.955 9.816 ;
     RECT  13.504 62.16 13.961 62.808 ;
     RECT  13.504 12.864 14.003 13.368 ;
     RECT  13.504 70.128 14.041 70.872 ;
     RECT  13.504 63.84 14.051 65.736 ;
     RECT  13.504 38.736 14.105 39 ;
     RECT  13.504 67.824 14.485 67.848 ;
     RECT  14.003 13.344 14.531 13.368 ;
     RECT  13.504 72 14.533 72.024 ;
     RECT  13.955 7.392 14.579 9.816 ;
     RECT  14.105 38.976 14.641 39 ;
     RECT  13.504 53.28 14.677 53.832 ;
     RECT  13.504 16.896 14.713 19.032 ;
     RECT  13.601 4.992 14.821 5.736 ;
     RECT  14.677 52.848 14.821 53.832 ;
     RECT  13.504 59.76 14.821 61.08 ;
     RECT  13.504 14.4 14.857 15.72 ;
     RECT  14.579 7.488 14.861 9.816 ;
     RECT  13.504 20.016 14.861 21.432 ;
     RECT  13.889 32.736 14.861 33.432 ;
     RECT  13.504 43.776 14.861 44.232 ;
     RECT  14.051 63.84 14.861 65.304 ;
     RECT  14.533 71.856 14.861 72.024 ;
     RECT  13.504 73.248 14.861 76.056 ;
     RECT  13.504 77.808 14.861 78.168 ;
     RECT  14.861 43.872 14.897 44.232 ;
     RECT  12.881 0.864 15.109 0.888 ;
     RECT  14.041 70.368 15.253 70.872 ;
     RECT  13.504 11.136 15.361 11.16 ;
     RECT  13.961 62.784 15.397 62.808 ;
     RECT  14.485 67.824 15.721 68.424 ;
     RECT  15.253 69.552 15.721 70.872 ;
     RECT  13.504 58.512 15.757 58.536 ;
     RECT  14.857 14.4 15.793 15.816 ;
     RECT  14.713 16.848 15.793 19.032 ;
     RECT  14.861 32.736 15.793 33.336 ;
     RECT  14.641 38.976 15.865 39.768 ;
     RECT  13.504 2.88 15.908 2.904 ;
     RECT  14.821 4.992 15.908 5.832 ;
     RECT  14.861 7.632 15.908 9.816 ;
     RECT  15.361 11.136 15.908 11.688 ;
     RECT  15.793 14.4 15.908 19.032 ;
     RECT  14.861 20.112 15.908 21.432 ;
     RECT  13.504 22.464 15.908 24.216 ;
     RECT  13.504 25.2 15.908 25.8 ;
     RECT  13.504 29.52 15.908 29.64 ;
     RECT  14.821 31.104 15.908 31.128 ;
     RECT  15.793 32.304 15.908 33.336 ;
     RECT  13.504 37.632 15.908 37.656 ;
     RECT  15.865 38.784 15.908 39.768 ;
     RECT  15.901 42 15.908 42.024 ;
     RECT  14.897 43.872 15.908 44.136 ;
     RECT  13.504 45.504 15.908 45.528 ;
     RECT  13.504 49.536 15.908 49.56 ;
     RECT  13.504 51.696 15.908 51.72 ;
     RECT  14.821 52.752 15.908 53.832 ;
     RECT  13.504 55.68 15.908 55.992 ;
     RECT  15.757 58.224 15.908 58.536 ;
     RECT  14.821 59.76 15.908 61.176 ;
     RECT  15.397 62.208 15.908 62.808 ;
     RECT  14.861 63.84 15.908 65.208 ;
     RECT  15.721 67.824 15.908 70.872 ;
     RECT  14.861 71.952 15.908 72.024 ;
     RECT  14.861 73.248 15.908 73.896 ;
     RECT  14.861 74.88 15.908 76.056 ;
     RECT  14.861 77.904 15.908 78.168 ;
     RECT  15.908 2.148 16.012 79.932 ;
     RECT  16.012 2.418 16.204 79.662 ;
     RECT  16.204 41.136 16.451 44.52 ;
     RECT  16.204 30.816 16.517 31.128 ;
     RECT  16.451 43.872 16.517 44.52 ;
     RECT  16.451 41.136 16.625 42.216 ;
     RECT  15.109 0.864 16.873 1.032 ;
     RECT  16.873 0.72 16.981 1.032 ;
     RECT  16.204 77.904 17.075 78.696 ;
     RECT  16.204 51.408 17.165 53.832 ;
     RECT  16.204 29.52 17.269 29.544 ;
     RECT  16.204 14.4 17.305 19.032 ;
     RECT  16.204 2.88 17.377 2.904 ;
     RECT  17.269 29.52 17.549 29.832 ;
     RECT  16.517 30.864 17.549 31.128 ;
     RECT  17.549 29.52 17.629 31.128 ;
     RECT  16.204 32.304 17.629 33.336 ;
     RECT  17.629 29.52 17.633 33.336 ;
     RECT  17.305 13.68 17.665 19.032 ;
     RECT  16.204 20.112 17.665 21.432 ;
     RECT  16.204 36 17.665 36.024 ;
     RECT  16.204 37.632 17.665 37.656 ;
     RECT  16.204 38.784 17.665 40.056 ;
     RECT  16.204 48.672 17.701 50.136 ;
     RECT  17.165 51.408 17.701 53.688 ;
     RECT  16.204 55.68 17.797 56.088 ;
     RECT  16.625 41.136 17.809 41.16 ;
     RECT  16.204 73.248 17.881 73.896 ;
     RECT  16.204 74.88 17.881 76.056 ;
     RECT  16.981 0.72 17.917 1.32 ;
     RECT  17.377 2.544 17.917 2.904 ;
     RECT  17.665 66.576 17.953 66.6 ;
     RECT  16.625 42.192 18.025 42.216 ;
     RECT  16.517 43.872 18.025 44.136 ;
     RECT  16.204 59.76 18.025 61.176 ;
     RECT  16.204 62.208 18.025 62.808 ;
     RECT  16.204 4.128 18.133 6.072 ;
     RECT  16.204 7.632 18.133 9.816 ;
     RECT  16.204 10.944 18.133 12.312 ;
     RECT  17.809 41.04 18.133 41.16 ;
     RECT  18.025 42.192 18.205 44.136 ;
     RECT  16.204 45.504 18.205 45.528 ;
     RECT  17.665 36 18.241 40.056 ;
     RECT  18.133 41.04 18.241 41.208 ;
     RECT  17.797 55.296 18.241 56.088 ;
     RECT  16.204 67.824 18.241 72.024 ;
     RECT  17.881 73.248 18.241 76.056 ;
     RECT  16.204 63.84 18.277 65.256 ;
     RECT  17.953 66.24 18.277 66.6 ;
     RECT  18.241 36 18.313 41.208 ;
     RECT  17.665 13.68 18.349 21.432 ;
     RECT  18.349 13.344 18.385 21.432 ;
     RECT  16.204 22.464 18.385 26.376 ;
     RECT  17.075 77.904 18.385 78.168 ;
     RECT  18.385 77.04 18.421 78.168 ;
     RECT  18.241 67.824 18.457 76.056 ;
     RECT  18.421 77.04 18.457 78.504 ;
     RECT  17.701 48.672 18.493 53.688 ;
     RECT  17.917 0.72 18.565 2.904 ;
     RECT  18.133 4.128 18.565 12.312 ;
     RECT  18.565 0.72 18.608 12.312 ;
     RECT  18.385 13.344 18.608 26.376 ;
     RECT  17.633 29.52 18.608 29.832 ;
     RECT  17.633 31.104 18.608 33.336 ;
     RECT  18.313 35.76 18.608 41.208 ;
     RECT  18.205 42.192 18.608 45.528 ;
     RECT  18.529 46.608 18.608 46.632 ;
     RECT  18.493 48.672 18.608 53.832 ;
     RECT  18.241 55.296 18.608 56.52 ;
     RECT  16.204 58.224 18.608 58.776 ;
     RECT  18.025 59.76 18.608 62.808 ;
     RECT  18.277 63.84 18.608 66.6 ;
     RECT  18.457 67.824 18.608 78.504 ;
     RECT  18.608 0.72 18.712 79.932 ;
     RECT  18.712 0.72 18.904 79.662 ;
     RECT  18.904 29.52 19.933 29.976 ;
     RECT  18.904 31.104 19.933 57.048 ;
     RECT  18.904 58.224 19.933 77.064 ;
     RECT  18.904 78.048 19.933 78.936 ;
     RECT  18.904 0.72 20.077 28.104 ;
     RECT  19.933 58.224 21.521 58.32 ;
     RECT  19.933 58.32 21.516 58.344 ;
     RECT  19.933 58.344 21.521 58.464 ;
     RECT  19.933 58.464 21.516 58.488 ;
     RECT  19.933 58.488 21.521 58.608 ;
     RECT  19.933 58.608 21.516 58.632 ;
     RECT  19.933 58.632 21.521 58.752 ;
     RECT  19.933 58.752 21.516 58.776 ;
     RECT  19.933 58.776 21.521 58.896 ;
     RECT  19.933 58.896 21.516 58.92 ;
     RECT  19.933 58.92 21.521 59.04 ;
     RECT  19.933 59.04 21.516 59.064 ;
     RECT  19.933 59.064 21.521 59.184 ;
     RECT  19.933 59.184 21.516 59.208 ;
     RECT  19.933 59.208 21.521 59.328 ;
     RECT  19.933 59.328 21.516 59.352 ;
     RECT  19.933 59.352 21.521 59.472 ;
     RECT  19.933 59.472 21.516 59.496 ;
     RECT  19.933 59.496 21.521 59.616 ;
     RECT  19.933 59.616 21.516 59.64 ;
     RECT  19.933 59.64 21.521 59.76 ;
     RECT  19.933 59.76 21.516 59.784 ;
     RECT  19.933 59.784 21.521 59.904 ;
     RECT  19.933 59.904 21.516 59.928 ;
     RECT  19.933 59.928 21.521 60.048 ;
     RECT  19.933 60.048 21.516 60.072 ;
     RECT  19.933 60.072 21.521 60.192 ;
     RECT  19.933 60.192 21.516 60.216 ;
     RECT  19.933 60.216 21.521 60.336 ;
     RECT  19.933 60.336 21.516 60.36 ;
     RECT  19.933 60.36 21.521 60.48 ;
     RECT  19.933 60.48 21.516 60.504 ;
     RECT  19.933 60.504 21.521 60.624 ;
     RECT  19.933 60.624 21.516 60.648 ;
     RECT  19.933 60.648 21.521 60.768 ;
     RECT  19.933 60.768 21.516 60.792 ;
     RECT  19.933 60.792 21.521 60.912 ;
     RECT  19.933 60.912 21.516 60.936 ;
     RECT  19.933 60.936 21.521 61.056 ;
     RECT  19.933 61.056 21.516 61.08 ;
     RECT  19.933 61.08 21.521 61.2 ;
     RECT  19.933 61.2 21.516 61.224 ;
     RECT  19.933 61.224 21.521 61.344 ;
     RECT  19.933 61.344 21.516 61.368 ;
     RECT  19.933 61.368 21.521 61.488 ;
     RECT  19.933 61.488 21.516 61.512 ;
     RECT  19.933 61.512 21.521 61.632 ;
     RECT  19.933 61.632 21.516 61.656 ;
     RECT  19.933 61.656 21.521 61.776 ;
     RECT  19.933 61.776 21.516 61.8 ;
     RECT  19.933 61.8 21.521 61.92 ;
     RECT  19.933 61.92 21.516 61.944 ;
     RECT  19.933 61.944 21.521 62.064 ;
     RECT  19.933 62.064 21.516 62.088 ;
     RECT  19.933 62.088 21.521 62.208 ;
     RECT  19.933 62.208 21.516 62.232 ;
     RECT  19.933 62.232 21.521 62.352 ;
     RECT  19.933 62.352 21.516 62.376 ;
     RECT  19.933 62.376 21.521 62.496 ;
     RECT  19.933 62.496 21.516 62.52 ;
     RECT  19.933 62.52 21.521 62.64 ;
     RECT  19.933 62.64 21.516 62.664 ;
     RECT  19.933 62.664 21.521 62.784 ;
     RECT  19.933 62.784 21.516 62.808 ;
     RECT  19.933 62.808 21.521 62.928 ;
     RECT  19.933 62.928 21.516 62.952 ;
     RECT  19.933 62.952 21.521 63.072 ;
     RECT  19.933 63.072 21.516 63.096 ;
     RECT  19.933 63.096 21.521 63.216 ;
     RECT  19.933 63.216 21.516 63.24 ;
     RECT  19.933 63.24 21.521 63.36 ;
     RECT  19.933 63.36 21.516 63.384 ;
     RECT  19.933 63.384 21.521 63.504 ;
     RECT  19.933 63.504 21.516 63.528 ;
     RECT  19.933 63.528 21.521 63.648 ;
     RECT  19.933 63.648 21.516 63.672 ;
     RECT  19.933 63.672 21.521 63.792 ;
     RECT  19.933 63.792 21.516 63.816 ;
     RECT  19.933 63.816 21.521 63.936 ;
     RECT  19.933 63.936 21.516 63.96 ;
     RECT  19.933 63.96 21.521 64.08 ;
     RECT  19.933 64.08 21.516 64.104 ;
     RECT  19.933 64.104 21.521 64.224 ;
     RECT  19.933 64.224 21.516 64.248 ;
     RECT  19.933 64.248 21.521 64.368 ;
     RECT  19.933 64.368 21.516 64.392 ;
     RECT  19.933 64.392 21.521 64.512 ;
     RECT  19.933 64.512 21.516 64.536 ;
     RECT  19.933 64.536 21.521 64.656 ;
     RECT  19.933 64.656 21.516 64.68 ;
     RECT  19.933 64.68 21.521 64.8 ;
     RECT  19.933 64.8 21.516 64.824 ;
     RECT  19.933 64.824 21.521 64.944 ;
     RECT  19.933 64.944 21.516 64.968 ;
     RECT  19.933 64.968 21.521 65.088 ;
     RECT  19.933 65.088 21.516 65.112 ;
     RECT  19.933 65.112 21.521 65.232 ;
     RECT  19.933 65.232 21.516 65.256 ;
     RECT  19.933 65.256 21.521 65.376 ;
     RECT  19.933 65.376 21.516 65.4 ;
     RECT  19.933 65.4 21.521 65.52 ;
     RECT  19.933 65.52 21.516 65.544 ;
     RECT  19.933 65.544 21.521 65.664 ;
     RECT  19.933 65.664 21.516 65.688 ;
     RECT  19.933 65.688 21.521 65.808 ;
     RECT  19.933 65.808 21.516 65.832 ;
     RECT  19.933 65.832 21.521 65.952 ;
     RECT  19.933 65.952 21.516 65.976 ;
     RECT  19.933 65.976 21.521 66.096 ;
     RECT  19.933 66.096 21.516 66.12 ;
     RECT  19.933 66.12 21.521 66.24 ;
     RECT  19.933 66.24 21.516 66.264 ;
     RECT  19.933 66.264 21.521 66.384 ;
     RECT  19.933 66.384 21.516 66.408 ;
     RECT  19.933 66.408 21.521 66.528 ;
     RECT  19.933 66.528 21.516 66.552 ;
     RECT  19.933 66.552 21.521 66.672 ;
     RECT  19.933 66.672 21.516 66.696 ;
     RECT  19.933 66.696 21.521 66.816 ;
     RECT  19.933 66.816 21.516 66.84 ;
     RECT  19.933 66.84 21.521 66.96 ;
     RECT  19.933 66.96 21.516 66.984 ;
     RECT  19.933 66.984 21.521 67.104 ;
     RECT  19.933 67.104 21.516 67.128 ;
     RECT  19.933 67.128 21.521 67.248 ;
     RECT  19.933 67.248 21.516 67.272 ;
     RECT  19.933 67.272 21.521 67.392 ;
     RECT  19.933 67.392 21.516 67.416 ;
     RECT  19.933 67.416 21.521 67.536 ;
     RECT  19.933 67.536 21.516 67.56 ;
     RECT  19.933 67.56 21.521 67.68 ;
     RECT  19.933 67.68 21.516 67.704 ;
     RECT  19.933 67.704 21.521 67.824 ;
     RECT  19.933 67.824 21.516 67.848 ;
     RECT  19.933 67.848 21.521 67.968 ;
     RECT  19.933 67.968 21.516 67.992 ;
     RECT  19.933 67.992 21.521 68.112 ;
     RECT  19.933 68.112 21.516 68.136 ;
     RECT  19.933 68.136 21.521 68.256 ;
     RECT  19.933 68.256 21.516 68.28 ;
     RECT  19.933 68.28 21.521 68.4 ;
     RECT  19.933 68.4 21.516 68.424 ;
     RECT  19.933 68.424 21.521 68.544 ;
     RECT  19.933 68.544 21.516 68.568 ;
     RECT  19.933 68.568 21.521 68.688 ;
     RECT  19.933 68.688 21.516 68.712 ;
     RECT  19.933 68.712 21.521 68.832 ;
     RECT  19.933 68.832 21.516 68.856 ;
     RECT  19.933 68.856 21.521 68.976 ;
     RECT  19.933 68.976 21.516 69 ;
     RECT  19.933 69 21.521 69.12 ;
     RECT  19.933 69.12 21.516 69.144 ;
     RECT  19.933 69.144 21.521 69.264 ;
     RECT  19.933 69.264 21.516 69.288 ;
     RECT  19.933 69.288 21.521 69.408 ;
     RECT  19.933 69.408 21.516 69.432 ;
     RECT  19.933 69.432 21.521 69.552 ;
     RECT  19.933 69.552 21.516 69.576 ;
     RECT  19.933 69.576 21.521 69.696 ;
     RECT  19.933 69.696 21.516 69.72 ;
     RECT  19.933 69.72 21.521 69.84 ;
     RECT  19.933 69.84 21.516 69.864 ;
     RECT  19.933 69.864 21.521 69.984 ;
     RECT  19.933 69.984 21.516 70.008 ;
     RECT  19.933 70.008 21.521 70.128 ;
     RECT  19.933 70.128 21.516 70.152 ;
     RECT  19.933 70.152 21.521 70.272 ;
     RECT  19.933 70.272 21.516 70.296 ;
     RECT  19.933 70.296 21.521 70.416 ;
     RECT  19.933 70.416 21.516 70.44 ;
     RECT  19.933 70.44 21.521 70.56 ;
     RECT  19.933 70.56 21.516 70.584 ;
     RECT  19.933 70.584 21.521 70.704 ;
     RECT  19.933 70.704 21.516 70.728 ;
     RECT  19.933 70.728 21.521 70.848 ;
     RECT  19.933 70.848 21.516 70.872 ;
     RECT  19.933 70.872 21.521 70.992 ;
     RECT  19.933 70.992 21.516 71.016 ;
     RECT  19.933 71.016 21.521 71.136 ;
     RECT  19.933 71.136 21.516 71.16 ;
     RECT  19.933 71.16 21.521 71.28 ;
     RECT  19.933 71.28 21.516 71.304 ;
     RECT  19.933 71.304 21.521 71.424 ;
     RECT  19.933 71.424 21.516 71.448 ;
     RECT  19.933 71.448 21.521 71.568 ;
     RECT  19.933 71.568 21.516 71.592 ;
     RECT  19.933 71.592 21.521 71.712 ;
     RECT  19.933 71.712 21.516 71.736 ;
     RECT  19.933 71.736 21.521 71.856 ;
     RECT  19.933 71.856 21.516 71.88 ;
     RECT  19.933 71.88 21.521 72 ;
     RECT  19.933 72 21.516 72.024 ;
     RECT  19.933 72.024 21.521 72.144 ;
     RECT  19.933 72.144 21.516 72.168 ;
     RECT  19.933 72.168 21.521 72.288 ;
     RECT  19.933 72.288 21.516 72.312 ;
     RECT  19.933 72.312 21.521 72.432 ;
     RECT  19.933 72.432 21.516 72.456 ;
     RECT  19.933 72.456 21.521 72.576 ;
     RECT  19.933 72.576 21.516 72.6 ;
     RECT  19.933 72.6 21.521 72.72 ;
     RECT  19.933 72.72 21.516 72.744 ;
     RECT  19.933 72.744 21.521 72.864 ;
     RECT  19.933 72.864 21.516 72.888 ;
     RECT  19.933 72.888 21.521 73.008 ;
     RECT  19.933 73.008 21.516 73.032 ;
     RECT  19.933 73.032 21.521 73.152 ;
     RECT  19.933 73.152 21.516 73.176 ;
     RECT  19.933 73.176 21.521 73.296 ;
     RECT  19.933 73.296 21.516 73.32 ;
     RECT  19.933 73.32 21.521 73.44 ;
     RECT  19.933 73.44 21.516 73.464 ;
     RECT  19.933 73.464 21.521 73.584 ;
     RECT  19.933 73.584 21.516 73.608 ;
     RECT  19.933 73.608 21.521 73.728 ;
     RECT  19.933 73.728 21.516 73.752 ;
     RECT  19.933 73.752 21.521 73.872 ;
     RECT  19.933 73.872 21.516 73.896 ;
     RECT  19.933 73.896 21.521 74.016 ;
     RECT  19.933 74.016 21.516 74.04 ;
     RECT  19.933 74.04 21.521 74.16 ;
     RECT  19.933 74.16 21.516 74.184 ;
     RECT  19.933 74.184 21.521 74.304 ;
     RECT  19.933 74.304 21.516 74.328 ;
     RECT  19.933 74.328 21.521 74.448 ;
     RECT  19.933 74.448 21.516 74.472 ;
     RECT  19.933 74.472 21.521 74.592 ;
     RECT  19.933 74.592 21.516 74.616 ;
     RECT  19.933 74.616 21.521 74.736 ;
     RECT  19.933 74.736 21.516 74.76 ;
     RECT  19.933 74.76 21.521 74.88 ;
     RECT  19.933 74.88 21.516 74.904 ;
     RECT  19.933 74.904 21.521 75.024 ;
     RECT  19.933 75.024 21.516 75.048 ;
     RECT  19.933 75.048 21.521 75.168 ;
     RECT  19.933 75.168 21.516 75.192 ;
     RECT  19.933 75.192 21.521 75.312 ;
     RECT  19.933 75.312 21.516 75.336 ;
     RECT  19.933 75.336 21.521 75.456 ;
     RECT  19.933 75.456 21.516 75.48 ;
     RECT  19.933 75.48 21.521 75.6 ;
     RECT  19.933 75.6 21.516 75.624 ;
     RECT  19.933 75.624 21.521 75.744 ;
     RECT  19.933 75.744 21.516 75.768 ;
     RECT  19.933 75.768 21.521 75.888 ;
     RECT  19.933 75.888 21.516 75.912 ;
     RECT  19.933 75.912 21.521 76.032 ;
     RECT  19.933 76.032 21.516 76.056 ;
     RECT  19.933 76.056 21.521 76.176 ;
     RECT  19.933 76.176 21.516 76.2 ;
     RECT  19.933 76.2 21.521 76.32 ;
     RECT  19.933 76.32 21.516 76.344 ;
     RECT  19.933 76.344 21.521 76.464 ;
     RECT  19.933 76.464 21.516 76.488 ;
     RECT  19.933 76.488 21.521 76.608 ;
     RECT  19.933 76.608 21.516 76.632 ;
     RECT  19.933 76.632 21.521 76.752 ;
     RECT  19.933 76.752 21.516 76.776 ;
     RECT  19.933 76.776 21.521 76.896 ;
     RECT  19.933 76.896 21.516 76.92 ;
     RECT  19.933 76.92 21.521 77.04 ;
     RECT  19.933 77.04 21.516 77.064 ;
     RECT  19.933 77.064 21.521 77.184 ;
     RECT  19.933 77.184 21.516 77.208 ;
     RECT  19.933 77.208 21.521 77.328 ;
     RECT  19.933 77.328 21.516 77.352 ;
     RECT  19.933 77.352 21.521 77.472 ;
     RECT  19.933 77.472 21.516 77.496 ;
     RECT  19.933 77.496 21.521 77.616 ;
     RECT  19.933 77.616 21.516 77.64 ;
     RECT  19.933 77.64 21.521 77.76 ;
     RECT  19.933 77.76 21.516 77.784 ;
     RECT  19.933 77.784 21.521 77.904 ;
     RECT  19.933 77.904 21.516 77.928 ;
     RECT  19.933 77.928 21.521 78.048 ;
     RECT  19.933 78.048 21.516 78.072 ;
     RECT  19.933 78.072 21.521 78.192 ;
     RECT  19.933 78.192 21.516 78.216 ;
     RECT  19.933 78.216 21.521 78.336 ;
     RECT  19.933 78.336 21.516 78.36 ;
     RECT  19.933 78.36 21.521 78.48 ;
     RECT  19.933 78.48 21.516 78.504 ;
     RECT  19.933 78.504 21.521 78.624 ;
     RECT  19.933 78.624 21.516 78.648 ;
     RECT  19.933 78.648 21.521 78.768 ;
     RECT  19.933 78.768 21.516 78.792 ;
     RECT  19.933 78.792 21.521 78.912 ;
     RECT  19.933 78.912 21.516 78.936 ;
     RECT  20.077 0.72 21.516 0.744 ;
     RECT  20.077 0.744 21.564 0.864 ;
     RECT  20.077 0.864 21.516 0.888 ;
     RECT  20.077 0.888 21.564 1.008 ;
     RECT  20.077 1.008 21.516 1.032 ;
     RECT  20.077 1.032 21.564 1.152 ;
     RECT  20.077 1.152 21.516 1.176 ;
     RECT  20.077 1.176 21.564 1.296 ;
     RECT  20.077 1.296 21.516 1.32 ;
     RECT  20.077 1.32 21.564 1.44 ;
     RECT  20.077 1.44 21.516 1.464 ;
     RECT  20.077 1.464 21.564 1.584 ;
     RECT  20.077 1.584 21.516 1.608 ;
     RECT  20.077 1.608 21.564 1.728 ;
     RECT  20.077 1.728 21.516 1.752 ;
     RECT  20.077 1.752 21.564 1.872 ;
     RECT  20.077 1.872 21.516 1.896 ;
     RECT  20.077 1.896 21.564 2.016 ;
     RECT  20.077 2.016 21.516 2.04 ;
     RECT  20.077 2.04 21.564 2.16 ;
     RECT  20.077 2.16 21.516 2.184 ;
     RECT  20.077 2.184 21.564 2.304 ;
     RECT  20.077 2.304 21.516 2.328 ;
     RECT  20.077 2.328 21.564 2.448 ;
     RECT  20.077 2.448 21.516 2.472 ;
     RECT  20.077 2.472 21.564 2.592 ;
     RECT  20.077 2.592 21.516 2.616 ;
     RECT  20.077 2.616 21.564 2.736 ;
     RECT  20.077 2.736 21.516 2.76 ;
     RECT  20.077 2.76 21.564 2.88 ;
     RECT  20.077 2.88 21.516 2.904 ;
     RECT  20.077 2.904 21.564 3.024 ;
     RECT  20.077 3.024 21.516 3.048 ;
     RECT  20.077 3.048 21.564 3.168 ;
     RECT  20.077 3.168 21.516 3.192 ;
     RECT  20.077 3.192 21.564 3.312 ;
     RECT  20.077 3.312 21.516 3.336 ;
     RECT  20.077 3.336 21.564 3.456 ;
     RECT  20.077 3.456 21.516 3.48 ;
     RECT  20.077 3.48 21.564 3.6 ;
     RECT  20.077 3.6 21.516 3.624 ;
     RECT  20.077 3.624 21.564 3.744 ;
     RECT  20.077 3.744 21.516 3.768 ;
     RECT  20.077 3.768 21.564 3.888 ;
     RECT  20.077 3.888 21.516 3.912 ;
     RECT  20.077 3.912 21.564 4.032 ;
     RECT  20.077 4.032 21.516 4.056 ;
     RECT  20.077 4.056 21.564 4.176 ;
     RECT  20.077 4.176 21.516 4.2 ;
     RECT  20.077 4.2 21.564 4.32 ;
     RECT  20.077 4.32 21.516 4.344 ;
     RECT  20.077 4.344 21.564 4.464 ;
     RECT  20.077 4.464 21.516 4.488 ;
     RECT  20.077 4.488 21.564 4.608 ;
     RECT  20.077 4.608 21.516 4.632 ;
     RECT  20.077 4.632 21.564 4.752 ;
     RECT  20.077 4.752 21.516 4.776 ;
     RECT  20.077 4.776 21.564 4.896 ;
     RECT  20.077 4.896 21.516 4.92 ;
     RECT  20.077 4.92 21.564 5.04 ;
     RECT  20.077 5.04 21.516 5.064 ;
     RECT  20.077 5.064 21.564 5.184 ;
     RECT  20.077 5.184 21.516 5.208 ;
     RECT  20.077 5.208 21.564 5.328 ;
     RECT  20.077 5.328 21.516 5.352 ;
     RECT  20.077 5.352 21.564 5.472 ;
     RECT  20.077 5.472 21.516 5.496 ;
     RECT  20.077 5.496 21.564 5.616 ;
     RECT  20.077 5.616 21.516 5.64 ;
     RECT  20.077 5.64 21.564 5.76 ;
     RECT  20.077 5.76 21.516 5.784 ;
     RECT  20.077 5.784 21.564 5.904 ;
     RECT  20.077 5.904 21.516 5.928 ;
     RECT  20.077 5.928 21.564 6.048 ;
     RECT  20.077 6.048 21.516 6.072 ;
     RECT  20.077 6.072 21.564 6.192 ;
     RECT  20.077 6.192 21.516 6.216 ;
     RECT  20.077 6.216 21.564 6.336 ;
     RECT  20.077 6.336 21.516 6.36 ;
     RECT  20.077 6.36 21.564 6.48 ;
     RECT  20.077 6.48 21.516 6.504 ;
     RECT  20.077 6.504 21.564 6.624 ;
     RECT  20.077 6.624 21.516 6.648 ;
     RECT  20.077 6.648 21.564 6.768 ;
     RECT  20.077 6.768 21.516 6.792 ;
     RECT  20.077 6.792 21.564 6.912 ;
     RECT  20.077 6.912 21.516 6.936 ;
     RECT  20.077 6.936 21.564 7.056 ;
     RECT  20.077 7.056 21.516 7.08 ;
     RECT  20.077 7.08 21.564 7.2 ;
     RECT  20.077 7.2 21.516 7.224 ;
     RECT  20.077 7.224 21.564 7.344 ;
     RECT  20.077 7.344 21.516 7.368 ;
     RECT  20.077 7.368 21.564 7.488 ;
     RECT  20.077 7.488 21.516 7.512 ;
     RECT  20.077 7.512 21.564 7.632 ;
     RECT  20.077 7.632 21.516 7.656 ;
     RECT  20.077 7.656 21.564 7.776 ;
     RECT  20.077 7.776 21.516 7.8 ;
     RECT  20.077 7.8 21.564 7.92 ;
     RECT  20.077 7.92 21.516 7.944 ;
     RECT  20.077 7.944 21.564 8.064 ;
     RECT  20.077 8.064 21.516 8.088 ;
     RECT  20.077 8.088 21.564 8.208 ;
     RECT  20.077 8.208 21.516 8.232 ;
     RECT  20.077 8.232 21.564 8.352 ;
     RECT  20.077 8.352 21.516 8.376 ;
     RECT  20.077 8.376 21.564 8.496 ;
     RECT  20.077 8.496 21.516 8.52 ;
     RECT  20.077 8.52 21.564 8.64 ;
     RECT  20.077 8.64 21.516 8.664 ;
     RECT  20.077 8.664 21.564 8.784 ;
     RECT  20.077 8.784 21.516 8.808 ;
     RECT  20.077 8.808 21.564 8.928 ;
     RECT  20.077 8.928 21.516 8.952 ;
     RECT  20.077 8.952 21.564 9.072 ;
     RECT  20.077 9.072 21.516 9.096 ;
     RECT  20.077 9.096 21.564 9.216 ;
     RECT  20.077 9.216 21.516 9.24 ;
     RECT  20.077 9.24 21.564 9.36 ;
     RECT  20.077 9.36 21.516 9.384 ;
     RECT  20.077 9.384 21.564 9.504 ;
     RECT  20.077 9.504 21.516 9.528 ;
     RECT  20.077 9.528 21.564 9.648 ;
     RECT  20.077 9.648 21.516 9.672 ;
     RECT  20.077 9.672 21.564 9.792 ;
     RECT  20.077 9.792 21.516 9.816 ;
     RECT  20.077 9.816 21.564 9.936 ;
     RECT  20.077 9.936 21.516 9.96 ;
     RECT  20.077 9.96 21.564 10.08 ;
     RECT  20.077 10.08 21.516 10.104 ;
     RECT  20.077 10.104 21.564 10.224 ;
     RECT  20.077 10.224 21.516 10.248 ;
     RECT  20.077 10.248 21.564 10.368 ;
     RECT  20.077 10.368 21.516 10.392 ;
     RECT  20.077 10.392 21.564 10.512 ;
     RECT  20.077 10.512 21.516 10.536 ;
     RECT  20.077 10.536 21.564 10.656 ;
     RECT  20.077 10.656 21.516 10.68 ;
     RECT  20.077 10.68 21.564 10.8 ;
     RECT  20.077 10.8 21.516 10.824 ;
     RECT  20.077 10.824 21.564 10.944 ;
     RECT  20.077 10.944 21.516 10.968 ;
     RECT  20.077 10.968 21.564 11.088 ;
     RECT  20.077 11.088 21.516 11.112 ;
     RECT  20.077 11.112 21.564 11.232 ;
     RECT  20.077 11.232 21.516 11.256 ;
     RECT  20.077 11.256 21.564 11.376 ;
     RECT  20.077 11.376 21.516 11.4 ;
     RECT  20.077 11.4 21.564 11.52 ;
     RECT  20.077 11.52 21.516 11.544 ;
     RECT  20.077 11.544 21.564 11.664 ;
     RECT  20.077 11.664 21.516 11.688 ;
     RECT  20.077 11.688 21.564 11.808 ;
     RECT  20.077 11.808 21.516 11.832 ;
     RECT  20.077 11.832 21.564 11.952 ;
     RECT  20.077 11.952 21.516 11.976 ;
     RECT  20.077 11.976 21.564 12.096 ;
     RECT  20.077 12.096 21.516 12.12 ;
     RECT  20.077 12.12 21.564 12.24 ;
     RECT  20.077 12.24 21.516 12.264 ;
     RECT  20.077 12.264 21.564 12.384 ;
     RECT  20.077 12.384 21.516 12.408 ;
     RECT  20.077 12.408 21.564 12.528 ;
     RECT  20.077 12.528 21.516 12.552 ;
     RECT  20.077 12.552 21.564 12.672 ;
     RECT  20.077 12.672 21.516 12.696 ;
     RECT  20.077 12.696 21.564 12.816 ;
     RECT  20.077 12.816 21.516 12.84 ;
     RECT  20.077 12.84 21.564 12.96 ;
     RECT  20.077 12.96 21.516 12.984 ;
     RECT  20.077 12.984 21.564 13.104 ;
     RECT  20.077 13.104 21.516 13.128 ;
     RECT  20.077 13.128 21.564 13.248 ;
     RECT  20.077 13.248 21.516 13.272 ;
     RECT  20.077 13.272 21.564 13.392 ;
     RECT  20.077 13.392 21.516 13.416 ;
     RECT  20.077 13.416 21.564 13.536 ;
     RECT  20.077 13.536 21.516 13.56 ;
     RECT  20.077 13.56 21.564 13.68 ;
     RECT  20.077 13.68 21.516 13.704 ;
     RECT  20.077 13.704 21.564 13.824 ;
     RECT  20.077 13.824 21.516 13.848 ;
     RECT  20.077 13.848 21.564 13.968 ;
     RECT  20.077 13.968 21.516 13.992 ;
     RECT  20.077 13.992 21.564 14.112 ;
     RECT  20.077 14.112 21.516 14.136 ;
     RECT  20.077 14.136 21.564 14.256 ;
     RECT  20.077 14.256 21.516 14.28 ;
     RECT  20.077 14.28 21.564 14.4 ;
     RECT  20.077 14.4 21.516 14.424 ;
     RECT  20.077 14.424 21.564 14.544 ;
     RECT  20.077 14.544 21.516 14.568 ;
     RECT  20.077 14.568 21.564 14.688 ;
     RECT  20.077 14.688 21.516 14.712 ;
     RECT  20.077 14.712 21.564 14.832 ;
     RECT  20.077 14.832 21.516 14.856 ;
     RECT  20.077 14.856 21.564 14.976 ;
     RECT  20.077 14.976 21.516 15 ;
     RECT  20.077 15 21.564 15.12 ;
     RECT  20.077 15.12 21.516 15.144 ;
     RECT  20.077 15.144 21.564 15.264 ;
     RECT  20.077 15.264 21.516 15.288 ;
     RECT  20.077 15.288 21.564 15.408 ;
     RECT  20.077 15.408 21.516 15.432 ;
     RECT  20.077 15.432 21.564 15.552 ;
     RECT  20.077 15.552 21.516 15.576 ;
     RECT  20.077 15.576 21.564 15.696 ;
     RECT  20.077 15.696 21.516 15.72 ;
     RECT  20.077 15.72 21.564 15.84 ;
     RECT  20.077 15.84 21.516 15.864 ;
     RECT  20.077 15.864 21.564 15.984 ;
     RECT  20.077 15.984 21.516 16.008 ;
     RECT  20.077 16.008 21.564 16.128 ;
     RECT  20.077 16.128 21.516 16.152 ;
     RECT  20.077 16.152 21.564 16.272 ;
     RECT  20.077 16.272 21.516 16.296 ;
     RECT  20.077 16.296 21.564 16.416 ;
     RECT  20.077 16.416 21.516 16.44 ;
     RECT  20.077 16.44 21.564 16.56 ;
     RECT  20.077 16.56 21.516 16.584 ;
     RECT  20.077 16.584 21.564 16.704 ;
     RECT  20.077 16.704 21.516 16.728 ;
     RECT  20.077 16.728 21.564 16.848 ;
     RECT  20.077 16.848 21.516 16.872 ;
     RECT  20.077 16.872 21.564 16.992 ;
     RECT  20.077 16.992 21.516 17.016 ;
     RECT  20.077 17.016 21.564 17.136 ;
     RECT  20.077 17.136 21.516 17.16 ;
     RECT  20.077 17.16 21.564 17.28 ;
     RECT  20.077 17.28 21.516 17.304 ;
     RECT  20.077 17.304 21.564 17.424 ;
     RECT  20.077 17.424 21.516 17.448 ;
     RECT  20.077 17.448 21.564 17.568 ;
     RECT  20.077 17.568 21.516 17.592 ;
     RECT  20.077 17.592 21.564 17.712 ;
     RECT  20.077 17.712 21.516 17.736 ;
     RECT  20.077 17.736 21.564 17.856 ;
     RECT  20.077 17.856 21.516 17.88 ;
     RECT  20.077 17.88 21.564 18 ;
     RECT  20.077 18 21.516 18.024 ;
     RECT  20.077 18.024 21.564 18.144 ;
     RECT  20.077 18.144 21.516 18.168 ;
     RECT  20.077 18.168 21.564 18.288 ;
     RECT  20.077 18.288 21.516 18.312 ;
     RECT  20.077 18.312 21.564 18.432 ;
     RECT  20.077 18.432 21.516 18.456 ;
     RECT  20.077 18.456 21.564 18.576 ;
     RECT  20.077 18.576 21.516 18.6 ;
     RECT  20.077 18.6 21.564 18.72 ;
     RECT  20.077 18.72 21.516 18.744 ;
     RECT  20.077 18.744 21.564 18.864 ;
     RECT  20.077 18.864 21.516 18.888 ;
     RECT  20.077 18.888 21.564 19.008 ;
     RECT  20.077 19.008 21.516 19.032 ;
     RECT  20.077 19.032 21.564 19.152 ;
     RECT  20.077 19.152 21.516 19.176 ;
     RECT  20.077 19.176 21.564 19.296 ;
     RECT  20.077 19.296 21.516 19.32 ;
     RECT  20.077 19.32 21.564 19.44 ;
     RECT  20.077 19.44 21.516 19.464 ;
     RECT  20.077 19.464 21.564 19.584 ;
     RECT  20.077 19.584 21.516 19.608 ;
     RECT  20.077 19.608 21.564 19.728 ;
     RECT  20.077 19.728 21.516 19.752 ;
     RECT  20.077 19.752 21.564 19.872 ;
     RECT  20.077 19.872 21.516 19.896 ;
     RECT  20.077 19.896 21.564 20.016 ;
     RECT  20.077 20.016 21.516 20.04 ;
     RECT  20.077 20.04 21.564 20.16 ;
     RECT  20.077 20.16 21.516 20.184 ;
     RECT  20.077 20.184 21.564 20.304 ;
     RECT  20.077 20.304 21.516 20.328 ;
     RECT  20.077 20.328 21.564 20.448 ;
     RECT  20.077 20.448 21.516 20.472 ;
     RECT  20.077 20.472 21.564 20.592 ;
     RECT  20.077 20.592 21.516 20.616 ;
     RECT  20.077 20.616 21.564 20.736 ;
     RECT  20.077 20.736 21.516 20.76 ;
     RECT  20.077 20.76 21.564 20.88 ;
     RECT  20.077 20.88 21.516 20.904 ;
     RECT  20.077 20.904 21.564 21.024 ;
     RECT  20.077 21.024 21.516 21.048 ;
     RECT  20.077 21.048 21.564 21.168 ;
     RECT  20.077 21.168 21.516 21.192 ;
     RECT  20.077 21.192 21.564 21.312 ;
     RECT  20.077 21.312 21.516 21.336 ;
     RECT  20.077 21.336 21.564 21.456 ;
     RECT  20.077 21.456 21.516 21.48 ;
     RECT  20.077 21.48 21.564 21.6 ;
     RECT  20.077 21.6 21.516 21.624 ;
     RECT  20.077 21.624 21.564 21.744 ;
     RECT  20.077 21.744 21.516 21.768 ;
     RECT  20.077 21.768 21.564 21.888 ;
     RECT  20.077 21.888 21.516 21.912 ;
     RECT  20.077 21.912 21.564 22.032 ;
     RECT  20.077 22.032 21.516 22.056 ;
     RECT  20.077 22.056 21.564 22.176 ;
     RECT  20.077 22.176 21.516 22.2 ;
     RECT  20.077 22.2 21.564 22.32 ;
     RECT  20.077 22.32 21.516 22.344 ;
     RECT  20.077 22.344 21.564 22.464 ;
     RECT  20.077 22.464 21.516 22.488 ;
     RECT  20.077 22.488 21.564 22.608 ;
     RECT  20.077 22.608 21.516 22.632 ;
     RECT  20.077 22.632 21.564 22.752 ;
     RECT  20.077 22.752 21.516 22.776 ;
     RECT  20.077 22.776 21.564 22.896 ;
     RECT  20.077 22.896 21.516 22.92 ;
     RECT  20.077 22.92 21.564 23.04 ;
     RECT  20.077 23.04 21.516 23.064 ;
     RECT  20.077 23.064 21.564 23.184 ;
     RECT  20.077 23.184 21.516 23.208 ;
     RECT  20.077 23.208 21.564 23.328 ;
     RECT  20.077 23.328 21.516 23.352 ;
     RECT  20.077 23.352 21.564 23.472 ;
     RECT  20.077 23.472 21.516 23.496 ;
     RECT  20.077 23.496 21.564 23.616 ;
     RECT  20.077 23.616 21.516 23.64 ;
     RECT  20.077 23.64 21.564 23.76 ;
     RECT  20.077 23.76 21.516 23.784 ;
     RECT  20.077 23.784 21.564 23.904 ;
     RECT  20.077 23.904 21.516 23.928 ;
     RECT  20.077 23.928 21.564 24.048 ;
     RECT  20.077 24.048 21.516 24.072 ;
     RECT  20.077 24.072 21.564 24.192 ;
     RECT  20.077 24.192 21.516 24.216 ;
     RECT  20.077 24.216 21.564 24.336 ;
     RECT  20.077 24.336 21.516 24.36 ;
     RECT  20.077 24.36 21.564 24.48 ;
     RECT  20.077 24.48 21.516 24.504 ;
     RECT  20.077 24.504 21.564 24.624 ;
     RECT  20.077 24.624 21.516 24.648 ;
     RECT  20.077 24.648 21.564 24.768 ;
     RECT  20.077 24.768 21.516 24.792 ;
     RECT  20.077 24.792 21.564 24.912 ;
     RECT  20.077 24.912 21.516 24.936 ;
     RECT  20.077 24.936 21.564 25.056 ;
     RECT  20.077 25.056 21.516 25.08 ;
     RECT  20.077 25.08 21.564 25.2 ;
     RECT  20.077 25.2 21.516 25.224 ;
     RECT  20.077 25.224 21.564 25.344 ;
     RECT  20.077 25.344 21.516 25.368 ;
     RECT  20.077 25.368 21.564 25.488 ;
     RECT  20.077 25.488 21.516 25.512 ;
     RECT  20.077 25.512 21.564 25.632 ;
     RECT  20.077 25.632 21.516 25.656 ;
     RECT  20.077 25.656 21.564 25.776 ;
     RECT  20.077 25.776 21.516 25.8 ;
     RECT  20.077 25.8 21.564 25.92 ;
     RECT  20.077 25.92 21.516 25.944 ;
     RECT  20.077 25.944 21.564 26.064 ;
     RECT  20.077 26.064 21.516 26.088 ;
     RECT  20.077 26.088 21.564 26.208 ;
     RECT  20.077 26.208 21.516 26.232 ;
     RECT  20.077 26.232 21.564 26.352 ;
     RECT  20.077 26.352 21.516 26.376 ;
     RECT  20.077 26.376 21.564 26.496 ;
     RECT  20.077 26.496 21.516 26.52 ;
     RECT  20.077 26.52 21.564 26.64 ;
     RECT  20.077 26.64 21.516 26.664 ;
     RECT  20.077 26.664 21.564 26.784 ;
     RECT  20.077 26.784 21.516 26.808 ;
     RECT  20.077 26.808 21.564 26.928 ;
     RECT  20.077 26.928 21.516 26.952 ;
     RECT  20.077 26.952 21.564 27.072 ;
     RECT  20.077 27.072 21.516 27.096 ;
     RECT  20.077 27.096 21.564 27.216 ;
     RECT  20.077 27.216 21.516 27.24 ;
     RECT  20.077 27.24 21.564 27.36 ;
     RECT  20.077 27.36 21.516 27.384 ;
     RECT  20.077 27.384 21.564 27.504 ;
     RECT  20.077 27.504 21.516 27.528 ;
     RECT  20.077 27.528 21.564 27.648 ;
     RECT  20.077 27.648 21.516 27.672 ;
     RECT  20.077 27.672 21.564 27.792 ;
     RECT  20.077 27.792 21.516 27.816 ;
     RECT  20.077 27.816 21.564 27.936 ;
     RECT  20.077 27.936 21.516 27.96 ;
     RECT  20.077 27.96 21.564 28.08 ;
     RECT  20.077 28.08 21.516 28.104 ;
     RECT  20.077 28.104 21.564 28.224 ;
     RECT  20.077 28.224 21.516 28.248 ;
     RECT  19.933 29.52 21.516 29.544 ;
     RECT  19.933 29.544 21.564 29.664 ;
     RECT  19.933 29.664 21.516 29.688 ;
     RECT  19.933 29.688 21.564 29.808 ;
     RECT  19.933 29.808 21.516 29.832 ;
     RECT  19.933 29.832 21.564 29.952 ;
     RECT  19.933 29.952 21.516 29.976 ;
     RECT  19.933 29.976 21.564 30.096 ;
     RECT  19.933 30.096 21.516 30.12 ;
     RECT  19.933 30.12 21.564 30.24 ;
     RECT  19.933 30.24 21.516 30.264 ;
     RECT  19.933 30.264 21.564 30.384 ;
     RECT  19.933 30.384 21.516 30.408 ;
     RECT  19.933 30.408 21.564 30.528 ;
     RECT  19.933 30.528 21.516 30.552 ;
     RECT  19.933 30.552 21.564 30.672 ;
     RECT  19.933 30.672 21.516 30.696 ;
     RECT  19.933 30.696 21.564 30.816 ;
     RECT  19.933 30.816 21.516 30.84 ;
     RECT  19.933 30.84 21.564 30.96 ;
     RECT  19.933 30.96 21.516 30.984 ;
     RECT  19.933 30.984 21.564 31.104 ;
     RECT  19.933 31.104 21.516 31.128 ;
     RECT  19.933 31.128 21.564 31.248 ;
     RECT  19.933 31.248 21.516 31.272 ;
     RECT  19.933 31.272 21.564 31.392 ;
     RECT  19.933 31.392 21.516 31.416 ;
     RECT  19.933 31.416 21.564 31.536 ;
     RECT  19.933 31.536 21.516 31.56 ;
     RECT  19.933 31.56 21.564 31.68 ;
     RECT  19.933 31.68 21.516 31.704 ;
     RECT  19.933 31.704 21.564 31.824 ;
     RECT  19.933 31.824 21.516 31.848 ;
     RECT  19.933 31.848 21.564 31.968 ;
     RECT  19.933 31.968 21.516 31.992 ;
     RECT  19.933 31.992 21.564 32.112 ;
     RECT  19.933 32.112 21.516 32.136 ;
     RECT  19.933 32.136 21.564 32.256 ;
     RECT  19.933 32.256 21.516 32.28 ;
     RECT  19.933 32.28 21.564 32.4 ;
     RECT  19.933 32.4 21.516 32.424 ;
     RECT  19.933 32.424 21.564 32.544 ;
     RECT  19.933 32.544 21.516 32.568 ;
     RECT  19.933 32.568 21.564 32.688 ;
     RECT  19.933 32.688 21.516 32.712 ;
     RECT  19.933 32.712 21.564 32.832 ;
     RECT  19.933 32.832 21.516 32.856 ;
     RECT  19.933 32.856 21.564 32.976 ;
     RECT  19.933 32.976 21.516 33 ;
     RECT  19.933 33 21.564 33.12 ;
     RECT  19.933 33.12 21.516 33.144 ;
     RECT  19.933 33.144 21.564 33.264 ;
     RECT  19.933 33.264 21.516 33.288 ;
     RECT  19.933 33.288 21.564 33.408 ;
     RECT  19.933 33.408 21.516 33.432 ;
     RECT  19.933 33.432 21.564 33.552 ;
     RECT  19.933 33.552 21.516 33.576 ;
     RECT  19.933 33.576 21.564 33.696 ;
     RECT  19.933 33.696 21.516 33.72 ;
     RECT  19.933 33.72 21.564 33.84 ;
     RECT  19.933 33.84 21.516 33.864 ;
     RECT  19.933 33.864 21.564 33.984 ;
     RECT  19.933 33.984 21.516 34.008 ;
     RECT  19.933 34.008 21.564 34.128 ;
     RECT  19.933 34.128 21.516 34.152 ;
     RECT  19.933 34.152 21.564 34.272 ;
     RECT  19.933 34.272 21.516 34.296 ;
     RECT  19.933 34.296 21.564 34.416 ;
     RECT  19.933 34.416 21.516 34.44 ;
     RECT  19.933 34.44 21.564 34.56 ;
     RECT  19.933 34.56 21.516 34.584 ;
     RECT  19.933 34.584 21.564 34.704 ;
     RECT  19.933 34.704 21.516 34.728 ;
     RECT  19.933 34.728 21.564 34.848 ;
     RECT  19.933 34.848 21.516 34.872 ;
     RECT  19.933 34.872 21.564 34.992 ;
     RECT  19.933 34.992 21.516 35.016 ;
     RECT  19.933 35.016 21.564 35.136 ;
     RECT  19.933 35.136 21.516 35.16 ;
     RECT  19.933 35.16 21.564 35.28 ;
     RECT  19.933 35.28 21.516 35.304 ;
     RECT  19.933 35.304 21.564 35.424 ;
     RECT  19.933 35.424 21.516 35.448 ;
     RECT  19.933 35.448 21.564 35.568 ;
     RECT  19.933 35.568 21.516 35.592 ;
     RECT  19.933 35.592 21.564 35.712 ;
     RECT  19.933 35.712 21.516 35.736 ;
     RECT  19.933 35.736 21.564 35.856 ;
     RECT  19.933 35.856 21.516 35.88 ;
     RECT  19.933 35.88 21.564 36 ;
     RECT  19.933 36 21.516 36.024 ;
     RECT  19.933 36.024 21.564 36.144 ;
     RECT  19.933 36.144 21.516 36.168 ;
     RECT  19.933 36.168 21.564 36.288 ;
     RECT  19.933 36.288 21.516 36.312 ;
     RECT  19.933 36.312 21.564 36.432 ;
     RECT  19.933 36.432 21.516 36.456 ;
     RECT  19.933 36.456 21.564 36.576 ;
     RECT  19.933 36.576 21.516 36.6 ;
     RECT  19.933 36.6 21.564 36.72 ;
     RECT  19.933 36.72 21.516 36.744 ;
     RECT  19.933 36.744 21.564 36.864 ;
     RECT  19.933 36.864 21.516 36.888 ;
     RECT  19.933 36.888 21.564 37.008 ;
     RECT  19.933 37.008 21.516 37.032 ;
     RECT  19.933 37.032 21.564 37.152 ;
     RECT  19.933 37.152 21.516 37.176 ;
     RECT  19.933 37.176 21.564 37.296 ;
     RECT  19.933 37.296 21.516 37.32 ;
     RECT  19.933 37.32 21.564 37.44 ;
     RECT  19.933 37.44 21.516 37.464 ;
     RECT  19.933 37.464 21.564 37.584 ;
     RECT  19.933 37.584 21.516 37.608 ;
     RECT  19.933 37.608 21.564 37.728 ;
     RECT  19.933 37.728 21.516 37.752 ;
     RECT  19.933 37.752 21.564 37.872 ;
     RECT  19.933 37.872 21.516 37.896 ;
     RECT  19.933 37.896 21.564 38.016 ;
     RECT  19.933 38.016 21.516 38.04 ;
     RECT  19.933 38.04 21.564 38.16 ;
     RECT  19.933 38.16 21.516 38.184 ;
     RECT  19.933 38.184 21.564 38.304 ;
     RECT  19.933 38.304 21.516 38.328 ;
     RECT  19.933 38.328 21.564 38.448 ;
     RECT  19.933 38.448 21.516 38.472 ;
     RECT  19.933 38.472 21.564 38.592 ;
     RECT  19.933 38.592 21.516 38.616 ;
     RECT  19.933 38.616 21.564 38.736 ;
     RECT  19.933 38.736 21.516 38.76 ;
     RECT  19.933 38.76 21.564 38.88 ;
     RECT  19.933 38.88 21.516 38.904 ;
     RECT  19.933 38.904 21.564 39.024 ;
     RECT  19.933 39.024 21.516 39.048 ;
     RECT  19.933 39.048 21.564 39.168 ;
     RECT  19.933 39.168 21.516 39.192 ;
     RECT  19.933 39.192 21.564 39.312 ;
     RECT  19.933 39.312 21.516 39.336 ;
     RECT  19.933 39.336 21.564 39.456 ;
     RECT  19.933 39.456 21.516 39.48 ;
     RECT  19.933 39.48 21.564 39.6 ;
     RECT  19.933 39.6 21.516 39.624 ;
     RECT  19.933 39.624 21.564 39.744 ;
     RECT  19.933 39.744 21.516 39.768 ;
     RECT  19.933 39.768 21.564 39.888 ;
     RECT  19.933 39.888 21.516 39.912 ;
     RECT  19.933 39.912 21.564 40.032 ;
     RECT  19.933 40.032 21.516 40.056 ;
     RECT  19.933 40.056 21.564 40.176 ;
     RECT  19.933 40.176 21.516 40.2 ;
     RECT  19.933 40.2 21.564 40.32 ;
     RECT  19.933 40.32 21.516 40.344 ;
     RECT  19.933 40.344 21.564 40.464 ;
     RECT  19.933 40.464 21.516 40.488 ;
     RECT  19.933 40.488 21.564 40.608 ;
     RECT  19.933 40.608 21.516 40.632 ;
     RECT  19.933 40.632 21.564 40.752 ;
     RECT  19.933 40.752 21.516 40.776 ;
     RECT  19.933 40.776 21.564 40.896 ;
     RECT  19.933 40.896 21.516 40.92 ;
     RECT  19.933 40.92 21.564 41.04 ;
     RECT  19.933 41.04 21.516 41.064 ;
     RECT  19.933 41.064 21.564 41.184 ;
     RECT  19.933 41.184 21.516 41.208 ;
     RECT  19.933 41.208 21.564 41.328 ;
     RECT  19.933 41.328 21.516 41.352 ;
     RECT  19.933 41.352 21.564 41.472 ;
     RECT  19.933 41.472 21.516 41.496 ;
     RECT  19.933 41.496 21.564 41.616 ;
     RECT  19.933 41.616 21.516 41.64 ;
     RECT  19.933 41.64 21.564 41.76 ;
     RECT  19.933 41.76 21.516 41.784 ;
     RECT  19.933 41.784 21.564 41.904 ;
     RECT  19.933 41.904 21.516 41.928 ;
     RECT  19.933 41.928 21.564 42.048 ;
     RECT  19.933 42.048 21.516 42.072 ;
     RECT  19.933 42.072 21.564 42.192 ;
     RECT  19.933 42.192 21.516 42.216 ;
     RECT  19.933 42.216 21.564 42.336 ;
     RECT  19.933 42.336 21.516 42.36 ;
     RECT  19.933 42.36 21.564 42.48 ;
     RECT  19.933 42.48 21.516 42.504 ;
     RECT  19.933 42.504 21.564 42.624 ;
     RECT  19.933 42.624 21.516 42.648 ;
     RECT  19.933 42.648 21.564 42.768 ;
     RECT  19.933 42.768 21.516 42.792 ;
     RECT  19.933 42.792 21.564 42.912 ;
     RECT  19.933 42.912 21.516 42.936 ;
     RECT  19.933 42.936 21.564 43.056 ;
     RECT  19.933 43.056 21.516 43.08 ;
     RECT  19.933 43.08 21.564 43.2 ;
     RECT  19.933 43.2 21.516 43.224 ;
     RECT  19.933 43.224 21.564 43.344 ;
     RECT  19.933 43.344 21.516 43.368 ;
     RECT  19.933 43.368 21.564 43.488 ;
     RECT  19.933 43.488 21.516 43.512 ;
     RECT  19.933 43.512 21.564 43.632 ;
     RECT  19.933 43.632 21.516 43.656 ;
     RECT  19.933 43.656 21.564 43.776 ;
     RECT  19.933 43.776 21.516 43.8 ;
     RECT  19.933 43.8 21.564 43.92 ;
     RECT  19.933 43.92 21.516 43.944 ;
     RECT  19.933 43.944 21.564 44.064 ;
     RECT  19.933 44.064 21.516 44.088 ;
     RECT  19.933 44.088 21.564 44.208 ;
     RECT  19.933 44.208 21.516 44.232 ;
     RECT  19.933 44.232 21.564 44.352 ;
     RECT  19.933 44.352 21.516 44.376 ;
     RECT  19.933 44.376 21.564 44.496 ;
     RECT  19.933 44.496 21.516 44.52 ;
     RECT  19.933 44.52 21.564 44.64 ;
     RECT  19.933 44.64 21.516 44.664 ;
     RECT  19.933 44.664 21.564 44.784 ;
     RECT  19.933 44.784 21.516 44.808 ;
     RECT  19.933 44.808 21.564 44.928 ;
     RECT  19.933 44.928 21.516 44.952 ;
     RECT  19.933 44.952 21.564 45.072 ;
     RECT  19.933 45.072 21.516 45.096 ;
     RECT  19.933 45.096 21.564 45.216 ;
     RECT  19.933 45.216 21.516 45.24 ;
     RECT  19.933 45.24 21.564 45.36 ;
     RECT  19.933 45.36 21.516 45.384 ;
     RECT  19.933 45.384 21.564 45.504 ;
     RECT  19.933 45.504 21.516 45.528 ;
     RECT  19.933 45.528 21.564 45.648 ;
     RECT  19.933 45.648 21.516 45.672 ;
     RECT  19.933 45.672 21.564 45.792 ;
     RECT  19.933 45.792 21.516 45.816 ;
     RECT  19.933 45.816 21.564 45.936 ;
     RECT  19.933 45.936 21.516 45.96 ;
     RECT  19.933 45.96 21.564 46.08 ;
     RECT  19.933 46.08 21.516 46.104 ;
     RECT  19.933 46.104 21.564 46.224 ;
     RECT  19.933 46.224 21.516 46.248 ;
     RECT  19.933 46.248 21.564 46.368 ;
     RECT  19.933 46.368 21.516 46.392 ;
     RECT  19.933 46.392 21.564 46.512 ;
     RECT  19.933 46.512 21.516 46.536 ;
     RECT  19.933 46.536 21.564 46.656 ;
     RECT  19.933 46.656 21.516 46.68 ;
     RECT  19.933 46.68 21.564 46.8 ;
     RECT  19.933 46.8 21.516 46.824 ;
     RECT  19.933 46.824 21.564 46.944 ;
     RECT  19.933 46.944 21.516 46.968 ;
     RECT  19.933 46.968 21.564 47.088 ;
     RECT  19.933 47.088 21.516 47.112 ;
     RECT  19.933 47.112 21.564 47.232 ;
     RECT  19.933 47.232 21.516 47.256 ;
     RECT  19.933 47.256 21.564 47.376 ;
     RECT  19.933 47.376 21.516 47.4 ;
     RECT  19.933 47.4 21.564 47.52 ;
     RECT  19.933 47.52 21.516 47.544 ;
     RECT  19.933 47.544 21.564 47.664 ;
     RECT  19.933 47.664 21.516 47.688 ;
     RECT  19.933 47.688 21.564 47.808 ;
     RECT  19.933 47.808 21.516 47.832 ;
     RECT  19.933 47.832 21.564 47.952 ;
     RECT  19.933 47.952 21.516 47.976 ;
     RECT  19.933 47.976 21.564 48.096 ;
     RECT  19.933 48.096 21.516 48.12 ;
     RECT  19.933 48.12 21.564 48.24 ;
     RECT  19.933 48.24 21.516 48.264 ;
     RECT  19.933 48.264 21.564 48.384 ;
     RECT  19.933 48.384 21.516 48.408 ;
     RECT  19.933 48.408 21.564 48.528 ;
     RECT  19.933 48.528 21.516 48.552 ;
     RECT  19.933 48.552 21.564 48.672 ;
     RECT  19.933 48.672 21.516 48.696 ;
     RECT  19.933 48.696 21.564 48.816 ;
     RECT  19.933 48.816 21.516 48.84 ;
     RECT  19.933 48.84 21.564 48.96 ;
     RECT  19.933 48.96 21.516 48.984 ;
     RECT  19.933 48.984 21.564 49.104 ;
     RECT  19.933 49.104 21.516 49.128 ;
     RECT  19.933 49.128 21.564 49.248 ;
     RECT  19.933 49.248 21.516 49.272 ;
     RECT  19.933 49.272 21.564 49.392 ;
     RECT  19.933 49.392 21.516 49.416 ;
     RECT  19.933 49.416 21.564 49.536 ;
     RECT  19.933 49.536 21.516 49.56 ;
     RECT  19.933 49.56 21.564 49.68 ;
     RECT  19.933 49.68 21.516 49.704 ;
     RECT  19.933 49.704 21.564 49.824 ;
     RECT  19.933 49.824 21.516 49.848 ;
     RECT  19.933 49.848 21.564 49.968 ;
     RECT  19.933 49.968 21.516 49.992 ;
     RECT  19.933 49.992 21.564 50.112 ;
     RECT  19.933 50.112 21.516 50.136 ;
     RECT  19.933 50.136 21.564 50.256 ;
     RECT  19.933 50.256 21.516 50.28 ;
     RECT  19.933 50.28 21.564 50.4 ;
     RECT  19.933 50.4 21.516 50.424 ;
     RECT  19.933 50.424 21.564 50.544 ;
     RECT  19.933 50.544 21.516 50.568 ;
     RECT  19.933 50.568 21.564 50.688 ;
     RECT  19.933 50.688 21.516 50.712 ;
     RECT  19.933 50.712 21.564 50.832 ;
     RECT  19.933 50.832 21.516 50.856 ;
     RECT  19.933 50.856 21.564 50.976 ;
     RECT  19.933 50.976 21.516 51 ;
     RECT  19.933 51 21.564 51.12 ;
     RECT  19.933 51.12 21.516 51.144 ;
     RECT  19.933 51.144 21.564 51.264 ;
     RECT  19.933 51.264 21.516 51.288 ;
     RECT  19.933 51.288 21.564 51.408 ;
     RECT  19.933 51.408 21.516 51.432 ;
     RECT  19.933 51.432 21.564 51.552 ;
     RECT  19.933 51.552 21.516 51.576 ;
     RECT  19.933 51.576 21.564 51.696 ;
     RECT  19.933 51.696 21.516 51.72 ;
     RECT  19.933 51.72 21.564 51.84 ;
     RECT  19.933 51.84 21.516 51.864 ;
     RECT  19.933 51.864 21.564 51.984 ;
     RECT  19.933 51.984 21.516 52.008 ;
     RECT  19.933 52.008 21.564 52.128 ;
     RECT  19.933 52.128 21.516 52.152 ;
     RECT  19.933 52.152 21.564 52.272 ;
     RECT  19.933 52.272 21.516 52.296 ;
     RECT  19.933 52.296 21.564 52.416 ;
     RECT  19.933 52.416 21.516 52.44 ;
     RECT  19.933 52.44 21.564 52.56 ;
     RECT  19.933 52.56 21.516 52.584 ;
     RECT  19.933 52.584 21.564 52.704 ;
     RECT  19.933 52.704 21.516 52.728 ;
     RECT  19.933 52.728 21.564 52.848 ;
     RECT  19.933 52.848 21.516 52.872 ;
     RECT  19.933 52.872 21.564 52.992 ;
     RECT  19.933 52.992 21.516 53.016 ;
     RECT  19.933 53.016 21.564 53.136 ;
     RECT  19.933 53.136 21.516 53.16 ;
     RECT  19.933 53.16 21.564 53.28 ;
     RECT  19.933 53.28 21.516 53.304 ;
     RECT  19.933 53.304 21.564 53.424 ;
     RECT  19.933 53.424 21.516 53.448 ;
     RECT  19.933 53.448 21.564 53.568 ;
     RECT  19.933 53.568 21.516 53.592 ;
     RECT  19.933 53.592 21.564 53.712 ;
     RECT  19.933 53.712 21.516 53.736 ;
     RECT  19.933 53.736 21.564 53.856 ;
     RECT  19.933 53.856 21.516 53.88 ;
     RECT  19.933 53.88 21.564 54 ;
     RECT  19.933 54 21.516 54.024 ;
     RECT  19.933 54.024 21.564 54.144 ;
     RECT  19.933 54.144 21.516 54.168 ;
     RECT  19.933 54.168 21.564 54.288 ;
     RECT  19.933 54.288 21.516 54.312 ;
     RECT  19.933 54.312 21.564 54.432 ;
     RECT  19.933 54.432 21.516 54.456 ;
     RECT  19.933 54.456 21.564 54.576 ;
     RECT  19.933 54.576 21.516 54.6 ;
     RECT  19.933 54.6 21.564 54.72 ;
     RECT  19.933 54.72 21.516 54.744 ;
     RECT  19.933 54.744 21.564 54.864 ;
     RECT  19.933 54.864 21.516 54.888 ;
     RECT  19.933 54.888 21.564 55.008 ;
     RECT  19.933 55.008 21.516 55.032 ;
     RECT  19.933 55.032 21.564 55.152 ;
     RECT  19.933 55.152 21.516 55.176 ;
     RECT  19.933 55.176 21.564 55.296 ;
     RECT  19.933 55.296 21.516 55.32 ;
     RECT  19.933 55.32 21.564 55.44 ;
     RECT  19.933 55.44 21.516 55.464 ;
     RECT  19.933 55.464 21.564 55.584 ;
     RECT  19.933 55.584 21.516 55.608 ;
     RECT  19.933 55.608 21.564 55.728 ;
     RECT  19.933 55.728 21.516 55.752 ;
     RECT  19.933 55.752 21.564 55.872 ;
     RECT  19.933 55.872 21.516 55.896 ;
     RECT  19.933 55.896 21.564 56.016 ;
     RECT  19.933 56.016 21.516 56.04 ;
     RECT  19.933 56.04 21.564 56.16 ;
     RECT  19.933 56.16 21.516 56.184 ;
     RECT  19.933 56.184 21.564 56.304 ;
     RECT  19.933 56.304 21.516 56.328 ;
     RECT  19.933 56.328 21.564 56.448 ;
     RECT  19.933 56.448 21.516 56.472 ;
     RECT  19.933 56.472 21.564 56.592 ;
     RECT  19.933 56.592 21.516 56.616 ;
     RECT  19.933 56.616 21.564 56.736 ;
     RECT  19.933 56.736 21.516 56.76 ;
     RECT  19.933 56.76 21.564 56.88 ;
     RECT  19.933 56.88 21.516 56.904 ;
     RECT  19.933 56.904 21.564 57.024 ;
     RECT  19.933 57.024 21.516 57.048 ;
     RECT  21.521 58.344 21.564 58.464 ;
     RECT  21.521 58.488 21.564 58.608 ;
     RECT  21.521 58.632 21.564 58.752 ;
     RECT  21.521 58.776 21.564 58.896 ;
     RECT  21.521 58.92 21.564 59.04 ;
     RECT  21.521 59.064 21.564 59.184 ;
     RECT  21.521 59.208 21.564 59.328 ;
     RECT  21.521 59.352 21.564 59.472 ;
     RECT  21.521 59.496 21.564 59.616 ;
     RECT  21.521 59.64 21.564 59.76 ;
     RECT  21.521 59.784 21.564 59.904 ;
     RECT  21.521 59.928 21.564 60.048 ;
     RECT  21.521 60.072 21.564 60.192 ;
     RECT  21.521 60.216 21.564 60.336 ;
     RECT  21.521 60.36 21.564 60.48 ;
     RECT  21.521 60.504 21.564 60.624 ;
     RECT  21.521 60.648 21.564 60.768 ;
     RECT  21.521 60.792 21.564 60.912 ;
     RECT  21.521 60.936 21.564 61.056 ;
     RECT  21.521 61.08 21.564 61.2 ;
     RECT  21.521 61.224 21.564 61.344 ;
     RECT  21.521 61.368 21.564 61.488 ;
     RECT  21.521 61.512 21.564 61.632 ;
     RECT  21.521 61.656 21.564 61.776 ;
     RECT  21.521 61.8 21.564 61.92 ;
     RECT  21.521 61.944 21.564 62.064 ;
     RECT  21.521 62.088 21.564 62.208 ;
     RECT  21.521 62.232 21.564 62.352 ;
     RECT  21.521 62.376 21.564 62.496 ;
     RECT  21.521 62.52 21.564 62.64 ;
     RECT  21.521 62.664 21.564 62.784 ;
     RECT  21.521 62.808 21.564 62.928 ;
     RECT  21.521 62.952 21.564 63.072 ;
     RECT  21.521 63.096 21.564 63.216 ;
     RECT  21.521 63.24 21.564 63.36 ;
     RECT  21.521 63.384 21.564 63.504 ;
     RECT  21.521 63.528 21.564 63.648 ;
     RECT  21.521 63.672 21.564 63.792 ;
     RECT  21.521 63.816 21.564 63.936 ;
     RECT  21.521 63.96 21.564 64.08 ;
     RECT  21.521 64.104 21.564 64.224 ;
     RECT  21.521 64.248 21.564 64.368 ;
     RECT  21.521 64.392 21.564 64.512 ;
     RECT  21.521 64.536 21.564 64.656 ;
     RECT  21.521 64.68 21.564 64.8 ;
     RECT  21.521 64.824 21.564 64.944 ;
     RECT  21.521 64.968 21.564 65.088 ;
     RECT  21.521 65.112 21.564 65.232 ;
     RECT  21.521 65.256 21.564 65.376 ;
     RECT  21.521 65.4 21.564 65.52 ;
     RECT  21.521 65.544 21.564 65.664 ;
     RECT  21.521 65.688 21.564 65.808 ;
     RECT  21.521 65.832 21.564 65.952 ;
     RECT  21.521 65.976 21.564 66.096 ;
     RECT  21.521 66.12 21.564 66.24 ;
     RECT  21.521 66.264 21.564 66.384 ;
     RECT  21.521 66.408 21.564 66.528 ;
     RECT  21.521 66.552 21.564 66.672 ;
     RECT  21.521 66.696 21.564 66.816 ;
     RECT  21.521 66.84 21.564 66.96 ;
     RECT  21.521 66.984 21.564 67.104 ;
     RECT  21.521 67.128 21.564 67.248 ;
     RECT  21.521 67.272 21.564 67.392 ;
     RECT  21.521 67.416 21.564 67.536 ;
     RECT  21.521 67.56 21.564 67.68 ;
     RECT  21.521 67.704 21.564 67.824 ;
     RECT  21.521 67.848 21.564 67.968 ;
     RECT  21.521 67.992 21.564 68.112 ;
     RECT  21.521 68.136 21.564 68.256 ;
     RECT  21.521 68.28 21.564 68.4 ;
     RECT  21.521 68.424 21.564 68.544 ;
     RECT  21.521 68.568 21.564 68.688 ;
     RECT  21.521 68.712 21.564 68.832 ;
     RECT  21.521 68.856 21.564 68.976 ;
     RECT  21.521 69 21.564 69.12 ;
     RECT  21.521 69.144 21.564 69.264 ;
     RECT  21.521 69.288 21.564 69.408 ;
     RECT  21.521 69.432 21.564 69.552 ;
     RECT  21.521 69.576 21.564 69.696 ;
     RECT  21.521 69.72 21.564 69.84 ;
     RECT  21.521 69.864 21.564 69.984 ;
     RECT  21.521 70.008 21.564 70.128 ;
     RECT  21.521 70.152 21.564 70.272 ;
     RECT  21.521 70.296 21.564 70.416 ;
     RECT  21.521 70.44 21.564 70.56 ;
     RECT  21.521 70.584 21.564 70.704 ;
     RECT  21.521 70.728 21.564 70.848 ;
     RECT  21.521 70.872 21.564 70.992 ;
     RECT  21.521 71.016 21.564 71.136 ;
     RECT  21.521 71.16 21.564 71.28 ;
     RECT  21.521 71.304 21.564 71.424 ;
     RECT  21.521 71.448 21.564 71.568 ;
     RECT  21.521 71.592 21.564 71.712 ;
     RECT  21.521 71.736 21.564 71.856 ;
     RECT  21.521 71.88 21.564 72 ;
     RECT  21.521 72.024 21.564 72.144 ;
     RECT  21.521 72.168 21.564 72.288 ;
     RECT  21.521 72.312 21.564 72.432 ;
     RECT  21.521 72.456 21.564 72.576 ;
     RECT  21.521 72.6 21.564 72.72 ;
     RECT  21.521 72.744 21.564 72.864 ;
     RECT  21.521 72.888 21.564 73.008 ;
     RECT  21.521 73.032 21.564 73.152 ;
     RECT  21.521 73.176 21.564 73.296 ;
     RECT  21.521 73.32 21.564 73.44 ;
     RECT  21.521 73.464 21.564 73.584 ;
     RECT  21.521 73.608 21.564 73.728 ;
     RECT  21.521 73.752 21.564 73.872 ;
     RECT  21.521 73.896 21.564 74.016 ;
     RECT  21.521 74.04 21.564 74.16 ;
     RECT  21.521 74.184 21.564 74.304 ;
     RECT  21.521 74.328 21.564 74.448 ;
     RECT  21.521 74.472 21.564 74.592 ;
     RECT  21.521 74.616 21.564 74.736 ;
     RECT  21.521 74.76 21.564 74.88 ;
     RECT  21.521 74.904 21.564 75.024 ;
     RECT  21.521 75.048 21.564 75.168 ;
     RECT  21.521 75.192 21.564 75.312 ;
     RECT  21.521 75.336 21.564 75.456 ;
     RECT  21.521 75.48 21.564 75.6 ;
     RECT  21.521 75.624 21.564 75.744 ;
     RECT  21.521 75.768 21.564 75.888 ;
     RECT  21.521 75.912 21.564 76.032 ;
     RECT  21.521 76.056 21.564 76.176 ;
     RECT  21.521 76.2 21.564 76.32 ;
     RECT  21.521 76.344 21.564 76.464 ;
     RECT  21.521 76.488 21.564 76.608 ;
     RECT  21.521 76.632 21.564 76.752 ;
     RECT  21.521 76.776 21.564 76.896 ;
     RECT  21.521 76.92 21.564 77.04 ;
     RECT  21.521 77.064 21.564 77.184 ;
     RECT  21.521 77.208 21.564 77.328 ;
     RECT  21.521 77.352 21.564 77.472 ;
     RECT  21.521 77.496 21.564 77.616 ;
     RECT  21.521 77.64 21.564 77.76 ;
     RECT  21.521 77.784 21.564 77.904 ;
     RECT  21.521 77.928 21.564 78.048 ;
     RECT  21.521 78.072 21.564 78.192 ;
     RECT  21.521 78.216 21.564 78.336 ;
     RECT  21.521 78.36 21.564 78.48 ;
     RECT  21.521 78.504 21.564 78.624 ;
     RECT  21.521 78.648 21.564 78.768 ;
     RECT  21.521 78.792 21.564 78.912 ;
     RECT  21.564 33.072 21.593 33.096 ;
     RECT  21.564 46.752 21.593 46.776 ;
    LAYER M5 ;
     RECT  7.008 0.037 7.032 2.137 ;
     RECT  2.4 2.137 2.52 2.151 ;
     RECT  5.1 2.137 5.22 2.151 ;
     RECT  7.008 2.137 7.92 2.151 ;
     RECT  10.5 2.137 10.62 2.151 ;
     RECT  13.2 2.137 13.32 2.151 ;
     RECT  15.9 2.137 16.02 2.151 ;
     RECT  18.6 2.137 18.72 2.151 ;
     RECT  19.776 1.717 19.8 2.151 ;
     RECT  18.6 2.151 19.8 2.725 ;
     RECT  5.1 2.151 5.412 3.541 ;
     RECT  2.4 2.151 2.712 3.733 ;
     RECT  4.32 3.541 5.412 3.733 ;
     RECT  7.008 2.151 8.112 3.829 ;
     RECT  2.4 3.733 5.412 4.789 ;
     RECT  6.48 3.829 8.112 4.789 ;
     RECT  15.9 2.151 16.212 4.981 ;
     RECT  18.6 2.725 20.28 5.077 ;
     RECT  2.4 4.789 8.112 6.851 ;
     RECT  13.2 2.151 13.512 7.093 ;
     RECT  13.2 7.093 13.944 7.381 ;
     RECT  15.072 4.981 16.212 7.381 ;
     RECT  9.504 2.869 9.528 9.541 ;
     RECT  2.4 6.851 2.712 10.117 ;
     RECT  2.256 10.117 2.712 10.259 ;
     RECT  9.264 9.541 9.528 10.309 ;
     RECT  10.5 2.151 10.812 10.309 ;
     RECT  3.696 6.851 8.112 11.029 ;
     RECT  17.616 5.077 20.28 11.125 ;
     RECT  21.408 14.389 21.432 14.531 ;
     RECT  12.24 7.381 16.212 14.629 ;
     RECT  17.424 11.125 20.28 14.629 ;
     RECT  12.24 14.629 20.28 15.301 ;
     RECT  12.24 15.301 21.144 15.491 ;
     RECT  3.696 11.029 8.232 15.781 ;
     RECT  12.24 15.491 20.28 15.925 ;
     RECT  21.408 17.413 21.432 17.555 ;
     RECT  2.4 10.259 2.712 17.605 ;
     RECT  3.696 15.781 8.28 17.605 ;
     RECT  2.4 17.605 8.28 18.803 ;
     RECT  3.696 18.803 8.28 18.997 ;
     RECT  9.264 10.309 10.812 18.997 ;
     RECT  3.696 18.997 10.812 20.485 ;
     RECT  11.808 15.925 20.28 20.485 ;
     RECT  2.4 18.803 2.712 20.677 ;
     RECT  3.696 20.485 20.28 20.677 ;
     RECT  0.144 22.645 0.168 22.787 ;
     RECT  21.408 24.901 21.432 25.043 ;
     RECT  2.4 20.677 20.28 26.485 ;
     RECT  2.304 26.485 20.28 27.731 ;
     RECT  2.4 27.731 20.28 31.429 ;
     RECT  2.256 31.429 20.28 31.571 ;
     RECT  21.408 33.061 21.432 33.539 ;
     RECT  2.4 31.571 20.28 33.877 ;
     RECT  2.304 33.877 20.28 34.019 ;
     RECT  2.4 34.019 20.28 46.549 ;
     RECT  2.256 46.549 20.28 46.691 ;
     RECT  21.408 50.773 21.432 50.963 ;
     RECT  2.4 46.691 20.28 51.205 ;
     RECT  2.304 51.205 20.28 51.395 ;
     RECT  2.4 51.395 20.28 55.715 ;
     RECT  2.4 55.715 20.232 57.397 ;
     RECT  2.304 57.397 20.232 57.587 ;
     RECT  2.4 57.587 20.232 61.957 ;
     RECT  2.256 61.957 20.232 62.099 ;
     RECT  2.4 62.099 20.232 66.323 ;
     RECT  0.144 67.237 0.168 67.379 ;
     RECT  4.128 66.323 20.232 67.859 ;
     RECT  10.224 67.859 20.232 68.435 ;
     RECT  4.128 67.859 9.048 68.821 ;
     RECT  10.224 68.435 13.992 69.011 ;
     RECT  3.936 68.821 9.048 69.635 ;
     RECT  4.128 69.635 9.048 70.163 ;
     RECT  10.5 69.011 13.992 70.163 ;
     RECT  15.072 68.435 20.232 70.403 ;
     RECT  15.072 70.403 19.704 70.835 ;
     RECT  7.2 70.163 8.856 71.315 ;
     RECT  21.408 71.317 21.432 71.459 ;
     RECT  4.128 70.163 5.928 72.419 ;
     RECT  15.12 70.835 19.704 73.283 ;
     RECT  15.12 73.283 19.656 75.011 ;
     RECT  15.12 75.011 18.912 75.155 ;
     RECT  10.5 70.163 13.944 75.299 ;
     RECT  4.272 72.419 5.928 75.827 ;
     RECT  4.272 75.827 5.88 76.693 ;
     RECT  7.2 71.315 8.112 77.461 ;
     RECT  12.288 75.299 13.944 77.699 ;
     RECT  4.176 76.693 5.88 78.083 ;
     RECT  15.9 75.155 18.912 78.131 ;
     RECT  13.2 77.699 13.944 78.179 ;
     RECT  7.2 77.461 8.52 78.659 ;
     RECT  15.9 78.131 17.064 78.707 ;
     RECT  2.4 66.323 2.712 79.237 ;
     RECT  5.1 78.083 5.88 79.283 ;
     RECT  2.304 79.237 2.712 79.379 ;
     RECT  13.2 78.179 13.512 79.717 ;
     RECT  7.2 78.659 8.112 79.763 ;
     RECT  2.4 79.379 2.712 79.929 ;
     RECT  5.1 79.283 5.412 79.929 ;
     RECT  7.8 79.763 8.112 79.929 ;
     RECT  10.5 75.299 10.812 79.929 ;
     RECT  13.104 79.717 13.512 79.929 ;
     RECT  15.9 78.707 16.212 79.929 ;
     RECT  18.6 78.131 18.912 79.929 ;
     RECT  2.4 79.929 2.52 79.943 ;
     RECT  5.1 79.929 5.22 79.943 ;
     RECT  7.8 79.929 7.92 79.943 ;
     RECT  10.5 79.929 10.62 79.943 ;
     RECT  13.104 79.929 13.32 79.943 ;
     RECT  15.9 79.929 16.02 79.943 ;
     RECT  18.6 79.929 18.72 79.943 ;
     RECT  13.104 79.943 13.128 80.917 ;
     RECT  13.104 80.917 13.272 81.996 ;
     RECT  13.128 81.996 13.248 82.064 ;
     RECT  18.72 2.137 19.776 2.151 ;
     RECT  8.112 2.869 9.504 9.541 ;
     RECT  9.528 2.869 10.5 10.309 ;
     RECT  5.412 3.829 6.48 4.789 ;
     RECT  16.212 5.077 17.616 11.125 ;
     RECT  2.712 6.851 3.696 17.605 ;
     RECT  13.944 7.093 15.072 7.381 ;
     RECT  10.812 7.381 12.24 15.925 ;
     RECT  8.112 9.541 9.264 11.029 ;
     RECT  8.232 11.029 9.264 15.781 ;
     RECT  16.212 11.125 17.424 14.629 ;
     RECT  20.28 14.389 21.408 14.531 ;
     RECT  20.28 14.531 21.144 15.301 ;
     RECT  8.28 15.781 9.264 18.997 ;
     RECT  10.812 15.925 11.808 20.485 ;
     RECT  20.28 17.413 21.408 17.555 ;
     RECT  2.712 18.803 3.696 20.677 ;
     RECT  20.28 24.901 21.408 25.043 ;
     RECT  20.28 33.061 21.408 33.539 ;
     RECT  20.28 50.773 21.408 50.963 ;
     RECT  2.712 66.323 4.128 68.821 ;
     RECT  9.048 67.859 10.224 69.011 ;
     RECT  13.992 68.435 15.072 70.163 ;
     RECT  2.712 68.821 3.936 69.635 ;
     RECT  9.048 69.011 10.5 70.163 ;
     RECT  2.712 69.635 4.128 72.419 ;
     RECT  5.928 70.163 7.2 75.827 ;
     RECT  13.944 70.163 15.072 70.835 ;
     RECT  13.944 70.835 15.12 75.155 ;
     RECT  10.812 75.299 12.288 77.699 ;
     RECT  5.88 75.827 7.2 79.283 ;
     RECT  2.712 76.693 4.176 78.083 ;
     RECT  13.128 79.943 13.272 80.917 ;
  END
END qkd_rlysh0_528
END LIBRARY
